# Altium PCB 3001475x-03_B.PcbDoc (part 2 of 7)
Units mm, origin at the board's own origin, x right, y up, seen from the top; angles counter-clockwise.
Board outline 100 x 72 mm, 12 copper layers (Top Layer, L2 GND, Layer 3, L4 GND, Layer 5, L6 PWR, L7 3V3, Layer 8, L9 GND, Layer 10, L11 GND, Bottom Layer), stack 1.735 mm thick; 431 components, 499 nets, 1977 pads, 1473 vias.

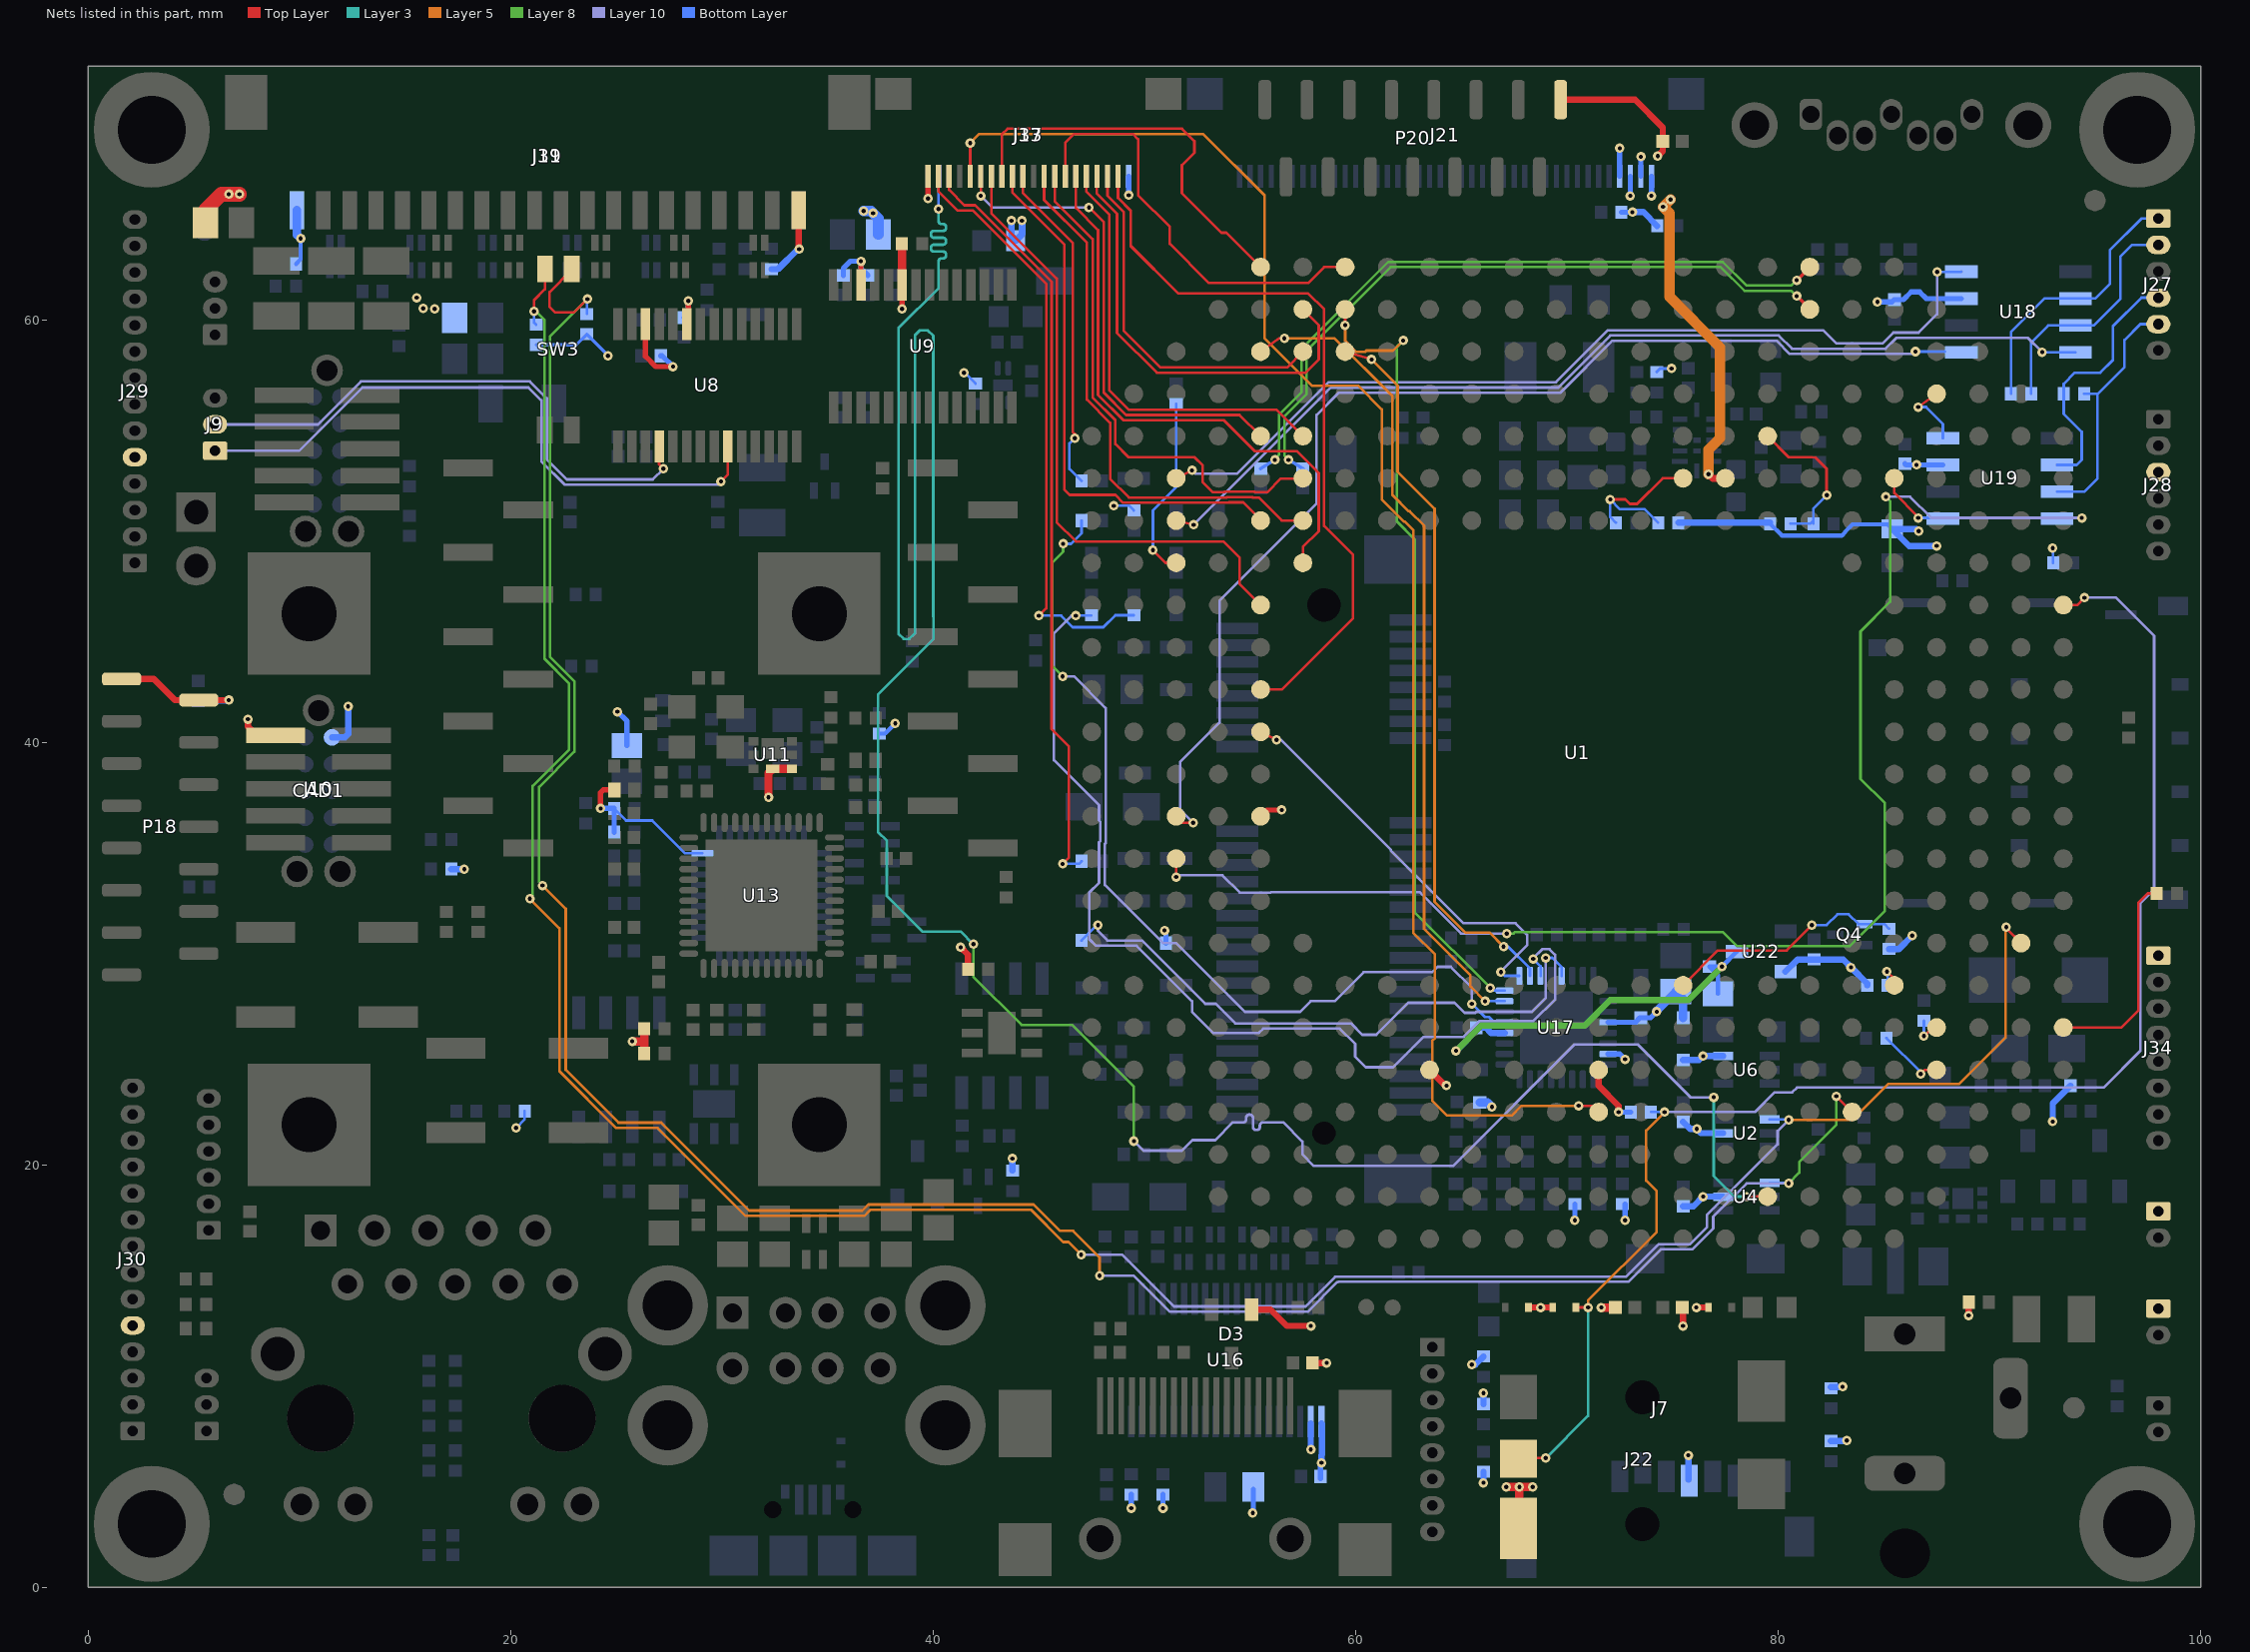
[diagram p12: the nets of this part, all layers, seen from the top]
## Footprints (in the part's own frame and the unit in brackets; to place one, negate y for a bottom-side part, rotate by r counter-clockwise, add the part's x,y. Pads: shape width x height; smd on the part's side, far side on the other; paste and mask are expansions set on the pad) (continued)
MODULE_CCWMX6 [mil]
  round 35 smd: A5(-590.55,905.51) A6(-511.81,905.51) A7(-433.07,905.51) A8(-354.33,905.51) A9(-275.59,905.51) A10(-196.85,905.51) A11(-118.11,905.51) A12(-39.37,905.51) A13(39.37,905.51) A14(118.11,905.51) A15(196.85,905.51) A16(275.59,905.51) A17(354.33,905.51) A18(433.07,905.51) A19(511.81,905.51) A20(590.55,905.51) AA2(-826.77,-669.29) AA3(-748.03,-669.29) AA4(-669.29,-669.29) AA5(-590.55,-669.29) AA6(-511.81,-669.29) AA7(-433.07,-669.29) AA8(-354.33,-669.29) AA9(-275.59,-669.29) AA10(-196.85,-669.29) AA11(-118.11,-669.29) AA12(-39.37,-669.29) AA13(39.37,-669.29) AA14(118.11,-669.29) AA15(196.85,-669.29) AA16(275.59,-669.29) AA17(354.33,-669.29) AA18(433.07,-669.29) AA19(511.81,-669.29) AA20(590.55,-669.29) AA21(669.29,-669.29) AA22(748.03,-669.29) AA23(826.77,-669.29) AB3(-748.03,-748.03) AB4(-669.29,-748.03) AB5(-590.55,-748.03) AB6(-511.81,-748.03) AB7(-433.07,-748.03) AB8(-354.33,-748.03) AB9(-275.59,-748.03) AB10(-196.85,-748.03) AB11(-118.11,-748.03) AB12(-39.37,-748.03) AB13(39.37,-748.03) AB14(118.11,-748.03) AB15(196.85,-748.03) AB16(275.59,-748.03) AB17(354.33,-748.03) AB18(433.07,-748.03) AB19(511.81,-748.03) AB20(590.55,-748.03) AB21(669.29,-748.03) AB22(748.03,-748.03) AC4(-669.29,-826.77) AC5(-590.55,-826.77) AC6(-511.81,-826.77) AC7(-433.07,-826.77) AC8(-354.33,-826.77) AC9(-275.59,-826.77) AC10(-196.85,-826.77) AC11(-118.11,-826.77) AC12(-39.37,-826.77) AC13(39.37,-826.77) AC14(118.11,-826.77) AC15(196.85,-826.77) AC16(275.59,-826.77) AC17(354.33,-826.77) AC18(433.07,-826.77) AC19(511.81,-826.77) AC20(590.55,-826.77) AC21(669.29,-826.77) AD5(-590.55,-905.51) AD6(-511.81,-905.51) AD7(-433.07,-905.51) AD8(-354.33,-905.51) AD9(-275.59,-905.51) AD10(-196.85,-905.51) AD11(-118.11,-905.51) AD12(-39.37,-905.51) AD13(39.37,-905.51) AD14(118.11,-905.51) AD15(196.85,-905.51) AD16(275.59,-905.51) AD17(354.33,-905.51) AD18(433.07,-905.51) AD19(511.81,-905.51) AD20(590.55,-905.51) B4(-669.29,826.77) B5(-590.55,826.77) B6(-511.81,826.77) B7(-433.07,826.77) B8(-354.33,826.77) B9(-275.59,826.77) B10(-196.85,826.77) B11(-118.11,826.77) B12(-39.37,826.77) B13(39.37,826.77) B14(118.11,826.77) B15(196.85,826.77) B16(275.59,826.77) B17(354.33,826.77) B18(433.07,826.77) B19(511.81,826.77) B20(590.55,826.77) B21(669.29,826.77) C3(-748.03,748.03) C4(-669.29,748.03) C5(-590.55,748.03) C6(-511.81,748.03) C7(-433.07,748.03) C8(-354.33,748.03) C9(-275.59,748.03) C10(-196.85,748.03) C11(-118.11,748.03) C12(-39.37,748.03) C13(39.37,748.03) C14(118.11,748.03) C15(196.85,748.03) C16(275.59,748.03) C17(354.33,748.03) C18(433.07,748.03) C19(511.81,748.03) C20(590.55,748.03) C21(669.29,748.03) C22(748.03,748.03) D2(-826.77,669.29) D3(-748.03,669.29) D4(-669.29,669.29) D5(-590.55,669.29) D6(-511.81,669.29) D7(-433.07,669.29) D8(-354.33,669.29) D9(-275.59,669.29) D10(-196.85,669.29) D11(-118.11,669.29) D12(-39.37,669.29) D13(39.37,669.29) D14(118.11,669.29) D15(196.85,669.29) D16(275.59,669.29) D17(354.33,669.29) D18(433.07,669.29) D19(511.81,669.29) D20(590.55,669.29) D21(669.29,669.29) D22(748.03,669.29) D23(826.77,669.29) E1(-905.51,590.55) E2(-826.77,590.55) E3(-748.03,590.55) E4(-669.29,590.55) E5(-590.55,590.55) E6(-511.81,590.55) E7(-433.07,590.55) E8(-354.33,590.55) E9(-275.59,590.55) E10(-196.85,590.55) E11(-118.11,590.55) E12(-39.37,590.55) E13(39.37,590.55) E14(118.11,590.55) E15(196.85,590.55) E16(275.59,590.55) E17(354.33,590.55) E18(433.07,590.55) E19(511.81,590.55) E20(590.55,590.55) E21(669.29,590.55) E22(748.03,590.55) E23(826.77,590.55) E24(905.51,590.55) F1(-905.51,511.81) F2(-826.77,511.81) F3(-748.03,511.81) F4(-669.29,511.81) F5(-590.55,511.81) F6(-511.81,511.81) F7(-433.07,511.81) F8(-354.33,511.81) F9(-275.59,511.81) F10(-196.85,511.81) F11(-118.11,511.81) F12(-39.37,511.81) F13(39.37,511.81) F14(118.11,511.81) F15(196.85,511.81) F16(275.59,511.81) F17(354.33,511.81) F18(433.07,511.81) F19(511.81,511.81) F20(590.55,511.81) F21(669.29,511.81) F22(748.03,511.81) F23(826.77,511.81) F24(905.51,511.81) G1(-905.51,433.07) G2(-826.77,433.07) G3(-748.03,433.07) G4(-669.29,433.07) G5(-590.55,433.07) G6(-511.81,433.07) G7(-433.07,433.07) G8(-354.33,433.07) G9(-275.59,433.07) G10(-196.85,433.07) G11(-118.11,433.07) G12(-39.37,433.07) G13(39.37,433.07) G14(118.11,433.07) G15(196.85,433.07) G16(275.59,433.07) G17(354.33,433.07) G18(433.07,433.07) G19(511.81,433.07) G20(590.55,433.07) G21(669.29,433.07) G22(748.03,433.07) G23(826.77,433.07) G24(905.51,433.07) H1(-905.51,354.33) H2(-826.77,354.33) H3(-748.03,354.33) H4(-669.29,354.33) H5(-590.55,354.33) H6(-511.81,354.33) H19(511.81,354.33) H20(590.55,354.33) H21(669.29,354.33) H22(748.03,354.33) H23(826.77,354.33) H24(905.51,354.33) J1(-905.51,275.59) J2(-826.77,275.59) J3(-748.03,275.59) J4(-669.29,275.59) J5(-590.55,275.59) J20(590.55,275.59) J21(669.29,275.59) J22(748.03,275.59) J23(826.77,275.59) J24(905.51,275.59) K1(-905.51,196.85) K2(-826.77,196.85) K3(-748.03,196.85) K4(-669.29,196.85) K5(-590.55,196.85) K20(590.55,196.85) K21(669.29,196.85) K22(748.03,196.85) K23(826.77,196.85) K24(905.51,196.85) L1(-905.51,118.11) L2(-826.77,118.11) L3(-748.03,118.11) L4(-669.29,118.11) L5(-590.55,118.11) L20(590.55,118.11) L21(669.29,118.11) L22(748.03,118.11) L23(826.77,118.11) L24(905.51,118.11) M1(-905.51,39.37) M2(-826.77,39.37) M3(-748.03,39.37) M4(-669.29,39.37) M5(-590.55,39.37) M20(590.55,39.37) M21(669.29,39.37) M22(748.03,39.37) M23(826.77,39.37) M24(905.51,39.37) N1(-905.51,-39.37) N2(-826.77,-39.37) N3(-748.03,-39.37) N4(-669.29,-39.37) N5(-590.55,-39.37) N20(590.55,-39.37) N21(669.29,-39.37) N22(748.03,-39.37) N23(826.77,-39.37) N24(905.51,-39.37) P1(-905.51,-118.11) P2(-826.77,-118.11) P3(-748.03,-118.11) P4(-669.29,-118.11) P5(-590.55,-118.11) P20(590.55,-118.11) P21(669.29,-118.11) P22(748.03,-118.11) P23(826.77,-118.11) P24(905.51,-118.11) R1(-905.51,-196.85) R2(-826.77,-196.85) R3(-748.03,-196.85) R4(-669.29,-196.85) R5(-590.55,-196.85) R20(590.55,-196.85) R21(669.29,-196.85) R22(748.03,-196.85) R23(826.77,-196.85) R24(905.51,-196.85) T1(-905.51,-275.59) T2(-826.77,-275.59) T3(-748.03,-275.59) T4(-669.29,-275.59) T5(-590.55,-275.59) T20(590.55,-275.59) T21(669.29,-275.59) T22(748.03,-275.59) T23(826.77,-275.59) T24(905.51,-275.59) U1(-905.51,-354.33) U2(-826.77,-354.33) U3(-748.03,-354.33) U4(-669.29,-354.33) U5(-590.55,-354.33) U6(-511.81,-354.33) U19(511.81,-354.33) U20(590.55,-354.33) U21(669.29,-354.33) U22(748.03,-354.33) U23(826.77,-354.33) U24(905.51,-354.33) V1(-905.51,-433.07) V2(-826.77,-433.07) V3(-748.03,-433.07) V4(-669.29,-433.07) V5(-590.55,-433.07) V6(-511.81,-433.07) V7(-433.07,-433.07) V8(-354.33,-433.07) V9(-275.59,-433.07) V10(-196.85,-433.07) V11(-118.11,-433.07) V12(-39.37,-433.07) V13(39.37,-433.07) V14(118.11,-433.07) V15(196.85,-433.07) V16(275.59,-433.07) V17(354.33,-433.07) V18(433.07,-433.07) V19(511.81,-433.07) V20(590.55,-433.07) V21(669.29,-433.07) V22(748.03,-433.07) V23(826.77,-433.07) V24(905.51,-433.07) W1(-905.51,-511.81) W2(-826.77,-511.81) W3(-748.03,-511.81) W4(-669.29,-511.81) W5(-590.55,-511.81) W6(-511.81,-511.81) W7(-433.07,-511.81) W8(-354.33,-511.81) W9(-275.59,-511.81) W10(-196.85,-511.81) W11(-118.11,-511.81) W12(-39.37,-511.81) W13(39.37,-511.81) W14(118.11,-511.81) W15(196.85,-511.81) W16(275.59,-511.81) W17(354.33,-511.81) W18(433.07,-511.81) W19(511.81,-511.81) W20(590.55,-511.81) W21(669.29,-511.81) W22(748.03,-511.81) W23(826.77,-511.81) W24(905.51,-511.81) Y1(-905.51,-590.55) Y2(-826.77,-590.55) Y3(-748.03,-590.55) Y4(-669.29,-590.55) Y5(-590.55,-590.55) Y6(-511.81,-590.55) Y7(-433.07,-590.55) Y8(-354.33,-590.55) Y9(-275.59,-590.55) Y10(-196.85,-590.55) Y11(-118.11,-590.55) Y12(-39.37,-590.55) Y13(39.37,-590.55) Y14(118.11,-590.55) Y15(196.85,-590.55) Y16(275.59,-590.55) Y17(354.33,-590.55) Y18(433.07,-590.55) Y19(511.81,-590.55) Y20(590.55,-590.55) Y21(669.29,-590.55) Y22(748.03,-590.55) Y23(826.77,-590.55) Y24(905.51,-590.55)
  silkscreen extent -984,-984 984,984, body extent -984,-984 984,984, height 220
MOLEX_53047-0210 [mm]
  rrect20% 0.875x1.15 hole 0.5: 1(0,0)
  oval 0.875x1.15 hole 0.5: 2(1.25,0)
  body extent -1.52,-1.15 2.73,2.05, height 4.2
MOLEX_53047-0310#1 [mm]
  rrect20% 1x1.15 hole 0.5: 1(0,0)
  oval 1x1.15 hole 0.5: 2(1.25,0) 3(2.5,0)
  body extent -1.5,-1.15 4,2.05, height 4.2
MOLEX_53047-0310#2 [mm]
  rrect20% 0.875x1.15 hole 0.5: 1(0,0)
  oval 0.875x1.15 hole 0.5: 2(1.25,0) 3(2.5,0)
  body extent -1.5,-1.15 4,2.05, height 4.2
MOLEX_53047-0610 [mm]
  rrect20% 0.875x1.15 hole 0.5: 1(0,0)
  oval 0.875x1.15 hole 0.5: 2(1.25,0) 3(2.5,0) 4(3.75,0) 5(5,0) 6(6.25,0)
  body extent -1.5,-1.15 7.75,2.05, height 4.2
MOLEX_53047-0810#1 [mm]
  rect 0.875x1.15 hole 0.5: 1(0,0)
  oval 0.875x1.15 hole 0.5: 2(1.25,0) 3(2.5,0) 4(3.75,0) 5(5,0) 6(6.25,0) 7(7.5,0) 8(8.75,0)
  body extent -1.5,-1.15 10.25,2.05, height 4.2
MOLEX_53047-0810#2 [mm]
  rrect20% 0.875x1.15 hole 0.5: 1(0,0)
  oval 0.875x1.15 hole 0.5: 2(1.25,0) 3(2.5,0) 4(3.75,0) 5(5,0) 6(6.25,0) 7(7.5,0) 8(8.75,0)
  body extent -1.5,-1.15 10.25,2.05, height 4.2
MOLEX_53047-1410 [mm]
  rrect20% 0.875x1.15 hole 0.5: 1(0,0)
  oval 0.875x1.15 hole 0.5: 2(1.25,0) 3(2.5,0) 4(3.75,0) 5(5,0) 6(6.25,0) 7(7.5,0) 8(8.75,0) 9(10,0) 10(11.25,0) 11(12.5,0) 12(13.75,0) 13(15,0) 14(16.25,0)
  body extent -1.5,-1.15 17.75,2.05, height 4.2
MOLEX_78727-0001 [mm]
  rect 0.8x0.6 smd: 1(0.33,4.38) 2(0.33,1.84) 3(0.33,-0.7) 4(0.33,-3.24) 5(-7.29,4.38) 6(-7.29,1.84) 7(-7.29,-0.7) 8(-7.29,-3.24)
  rect 0.85x0.8 smd: 9(-13.99,-4.98)
  rect 1.5x0.42 smd: 10(-2.47,-6.54) 12(-6.35,7.11) 13(-12.21,7.11) 14(-12.21,-7.11) 15(-6.35,-7.11)
  rect 1.4x0.87 smd: 11(0,6.95) 16(0,-6.95)
  body extent -14.53,-7.26 0.69,7.27, height 1.4
MOLEX_500873-0806 [mm]
  rect 0.8x1.5 smd: 1(0,0) 2(1.1,-0.4) 3(2.2,0) 4(3.3,0.2) 5(4.4,0) 6(5.5,0.2) 7(6.6,0) 8(7.7,0)
  rect 1.8x1.4 smd: 9(1.2,-10.3) 10(6.9,-10.3)
  rect 1.4x1.9 smd: 11(8.5,2.85) 12(-4.65,3.85)
  body extent -5.05,-10.7 8.95,4.5, height 1.87
omron_xf2m-2015-1a [mm]
  rect 0.25x1.1 smd: 1(-4.75,1.95) 2(-4.25,1.95) 3(-3.75,1.95) 4(-3.25,1.95) 5(-2.75,1.95) 6(-2.25,1.95) 7(-1.75,1.95) 8(-1.25,1.95) 9(-0.75,1.95) 10(-0.25,1.95) 11(0.25,1.95) 12(0.75,1.95) 13(1.25,1.95) 14(1.75,1.95) 15(2.25,1.95) 16(2.75,1.95) 17(3.25,1.95) 18(3.75,1.95) 19(4.25,1.95) 20(4.75,1.95)
  rect 1.7x1.5 smd: M1(6.4,-1.95) M2(-6.4,-1.95)
  body extent -7.05,-2.9 7.05,3.3, height 2.18
OMRON_XF2M-4015-1A [mm]
  rect 0.25x1.1 smd: 1(-9.75,1.95) 2(-9.25,1.95) 3(-8.75,1.95) 4(-8.25,1.95) 5(-7.75,1.95) 6(-7.25,1.95) 7(-6.75,1.95) 8(-6.25,1.95) 9(-5.75,1.95) 10(-5.25,1.95) 11(-4.75,1.95) 12(-4.25,1.95) 13(-3.75,1.95) 14(-3.25,1.95) 15(-2.75,1.95) 16(-2.25,1.95) 17(-1.75,1.95) 18(-1.25,1.95) 19(-0.75,1.95) 20(-0.25,1.95) 21(0.25,1.95) 22(0.75,1.95) 23(1.25,1.95) 24(1.75,1.95) 25(2.25,1.95) 26(2.75,1.95) 27(3.25,1.95) 28(3.75,1.95) 29(4.25,1.95) 30(4.75,1.95) 31(5.25,1.95) 32(5.75,1.95) 33(6.25,1.95) 34(6.75,1.95) 35(7.25,1.95) 36(7.75,1.95) 37(8.25,1.95) 38(8.75,1.95) 39(9.25,1.95) 40(9.75,1.95)
  rect 1.7x1.5 smd: M1(11.4,-1.95) M2(-11.4,-1.95)
  body extent -12.05,-2.9 12.05,3.3, height 2.18
OSC210P320X250X90-4N [mm]
  rect 1.25x1.1 smd: 1(-1.15,-0.95)
  rect 1.3x1.1 smd: 2(1.15,-0.95) 3(1.15,0.95) 4(-1.15,0.95)
  body extent -1.63,-1.3 1.62,1.3, height 0.6
PCBNUMBER [mm]
QFN50P500X500X100-33CN [mm]
  rrect50% 0.85x0.3 smd: 1(-2.45,1.75) 2(-2.45,1.25) 3(-2.45,0.75) 4(-2.45,0.25) 5(-2.45,-0.25) 6(-2.45,-0.75) 7(-2.45,-1.25) 8(-2.45,-1.75) 17(2.45,-1.75) 18(2.45,-1.25) 19(2.45,-0.75) 20(2.45,-0.25) 21(2.45,0.25) 22(2.45,0.75) 23(2.45,1.25) 24(2.45,1.75)
  rrect50% 0.3x0.85 smd: 9(-1.75,-2.45) 10(-1.25,-2.45) 11(-0.75,-2.45) 12(-0.25,-2.45) 13(0.25,-2.45) 14(0.75,-2.45) 15(1.25,-2.45) 16(1.75,-2.45) 25(1.75,2.45) 26(1.25,2.45) 27(0.75,2.45) 28(0.25,2.45) 29(-0.25,2.45) 30(-0.75,2.45) 31(-1.25,2.45) 32(-1.75,2.45)
  rect 3.45x3.45 smd: 33(0,0)
  body extent -2.5,-2.5 2.5,2.5, height 1.01
QFN50P600X600X100-37AN [mm]
  rrect35% 1.05x0.3 smd: 1(-2.8,2) 9(-2.8,-2) 19(2.8,-2) 27(2.8,2)
  rrect25% 1.1x0.3 smd: 2(-2.8,1.5) 3(-2.8,1) 4(-2.8,0.5) 5(-2.8,0) 6(-2.8,-0.5) 7(-2.8,-1) 8(-2.8,-1.5) 20(2.8,-1.5) 21(2.8,-1) 22(2.8,-0.5) 23(2.8,0) 24(2.8,0.5) 25(2.8,1) 26(2.8,1.5)
  rrect35% 0.3x1.05 smd: 10(-2,-2.8) 18(2,-2.8) 28(2,2.8) 36(-2,2.8)
  rrect25% 0.3x1.1 smd: 11(-1.5,-2.8) 12(-1,-2.8) 13(-0.5,-2.8) 14(0,-2.8) 15(0.5,-2.8) 16(1,-2.8) 17(1.5,-2.8) 29(1.5,2.8) 30(1,2.8) 31(0.5,2.8) 32(0,2.8) 33(-0.5,2.8) 34(-1,2.8) 35(-1.5,2.8)
  rect 3.8x3.8 smd: 37(0,0)
  body extent -3.05,-3.05 3.05,3.05, height 1.01
QFN50P700X700X100-49N [mm]
  oval 0.9x0.3 smd: 1(-3.45,2.75) 2(-3.45,2.25) 3(-3.45,1.75) 4(-3.45,1.25) 5(-3.45,0.75) 6(-3.45,0.25) 7(-3.45,-0.25) 8(-3.45,-0.75) 9(-3.45,-1.25) 10(-3.45,-1.75) 11(-3.45,-2.25) 12(-3.45,-2.75) 25(3.45,-2.75) 26(3.45,-2.25) 27(3.45,-1.75) 28(3.45,-1.25) 29(3.45,-0.75) 30(3.45,-0.25) 31(3.45,0.25) 32(3.45,0.75) 33(3.45,1.25) 34(3.45,1.75) 35(3.45,2.25) 36(3.45,2.75)
  oval 0.3x0.9 smd: 13(-2.75,-3.45) 14(-2.25,-3.45) 15(-1.75,-3.45) 16(-1.25,-3.45) 17(-0.75,-3.45) 18(-0.25,-3.45) 19(0.25,-3.45) 20(0.75,-3.45) 21(1.25,-3.45) 22(1.75,-3.45) 23(2.25,-3.45) 24(2.75,-3.45) 37(2.75,3.45) 38(2.25,3.45) 39(1.75,3.45) 40(1.25,3.45) 41(0.75,3.45) 42(0.25,3.45) 43(-0.25,3.45) 44(-0.75,3.45) 45(-1.25,3.45) 46(-1.75,3.45) 47(-2.25,3.45) 48(-2.75,3.45)
  rect 5.3x5.3 smd: 49(0,0)
  body extent -3.57,-3.57 3.57,3.57, height 1.01
QFN_MPS_MP2316 [mm]
  rect 0.75x0.25 smd: 1(-0.8,1)
  rect 0.7x0.25 smd: 2(-0.8,0.5) 3(-0.8,0) 4(-0.8,-0.5) 5(-0.8,-1) 7(0.8,-1) 8(0.8,-0.5) 9(0.8,0) 10(0.8,0.5) 11(0.8,1)
  rect 0.25x0.7 smd: 6(0,-1.45) 12(0,1.45)
  rect 0.35x0.25 smd: 13(0,0.5) 14(0,0)
  body extent -1,-1.5 1,1.5, height 1.01
RESC1005X40N#1 [mm]
  rect 0.57x0.62 smd: 1(-0.48,0) 2(0.48,0)
  body extent -0.5,-0.25 0.5,0.25, height 0.4
RESC1005X40N#2 [mm]
  rect 0.57x0.62 smd mask+0.05: 1(-0.48,0) 2(0.48,0)
  body extent -0.5,-0.25 0.5,0.25, height 0.4
RESC1609X55N#1 [mm]
  rect 0.9x1 smd: 1(-0.8,0) 2(0.8,0)
  body extent -0.87,-0.48 0.87,0.48, height 0.55
RESC1609X55N#2 [mm]
  rect 0.9x1 smd mask+0.05: 1(-0.8,0) 2(0.8,0)
  body extent -0.87,-0.48 0.87,0.48, height 0.55
RESC2013X70N [mm]
  rect 1.05x1.4 smd: 1(-0.95,0) 2(0.95,0)
  body extent -1.1,-0.67 1.1,0.68, height 0.7
SAMTEC_FTSH-105-01-F-DV [mil]
  rect 110x29 smd: 1(-80,100) 2(80,100) 3(-80,50) 4(80,50) 5(-80,0) 6(80,0) 7(-80,-50) 8(80,-50) 9(-80,-100) 10(80,-100)
  body extent -115,-207 115,208, height 325
SAMTEC_SMM-110-02-F-S [mm]
  rect 0.8x2.35 smd: 1(-9,-1.425) 2(-7,1.425) 3(-5,-1.425) 4(-3,1.425) 5(-1,-1.425) 6(1,1.425) 7(3,-1.425) 8(5,1.425) 9(7,-1.425) 10(9,1.425)
  body extent -10,-1 10,1, height 7.37
SOD3716X135N [mm]
  rect 1x0.8 smd: A(-1.8,0) K(1.8,0)
  body extent -1.95,-0.9 1.95,0.9, height 1.36
SODFL1006X43N12 [mm]
  rect 0.32x0.43 smd: 1(-0.55,0) 2(0.55,0)
  body extent -0.58,-0.33 0.58,0.33, height 0.4
SOIC127P600X175-8N [mm]
  rect 0.6x1.55 smd: 1(-1.905,-2.7) 2(-0.635,-2.7) 3(0.635,-2.7) 4(1.905,-2.7) 5(1.905,2.7) 6(0.635,2.7) 7(-0.635,2.7) 8(-1.905,2.7)
  body extent -2.5,-3.1 2.5,3.1, height 1.75
SON50P120X160X60-5T55X91N [mm] "Small Outline No-Lead (SON with Tab), 0.50 mm pitch; 4 pin, 1.20 mm L X 1.60 mm W X 0.60 mm H body"
  rrect52% 0.67x0.27 smd mask+0.051: 1(-0.81,0.25) 2(-0.81,-0.25) 3(0.81,-0.25) 4(0.81,0.25)
  rect 0.55x0.91 smd paste-0.099 mask+0.051: 5(0,0)
  body extent -0.85,-0.6 0.85,0.6, height 0.6
SON95P300X300X80-7N [mm]
  rect 0.4x1 smd: 1(-0.95,-1.4) 2(0,-1.4) 3(0.95,-1.4) 4(0.95,1.4) 5(0,1.4) 6(-0.95,1.4)
  rect 2x1.3 smd: 7(0,0)
  body extent -1.58,-1.58 1.58,1.58, height 0.8
SOP50P640X120-38N [mm]
  rect 1.5x0.3 smd: 1(-2.9,4.5) 2(-2.9,4) 3(-2.9,3.5) 4(-2.9,3) 5(-2.9,2.5) 6(-2.9,2) 7(-2.9,1.5) 8(-2.9,1) 9(-2.9,0.5) 10(-2.9,0) 11(-2.9,-0.5) 12(-2.9,-1) 13(-2.9,-1.5) 14(-2.9,-2) 15(-2.9,-2.5) 16(-2.9,-3) 17(-2.9,-3.5) 18(-2.9,-4) 19(-2.9,-4.5) 20(2.9,-4.5) 21(2.9,-4) 22(2.9,-3.5) 23(2.9,-3) 24(2.9,-2.5) 25(2.9,-2) 26(2.9,-1.5) 27(2.9,-1) 28(2.9,-0.5) 29(2.9,0) 30(2.9,0.5) 31(2.9,1) 32(2.9,1.5) 33(2.9,2) 34(2.9,2.5) 35(2.9,3) 36(2.9,3.5) 37(2.9,4) 38(2.9,4.5)
  body extent -3.3,-4.9 3.3,4.9, height 1.1
SOP65P640X120-28N [mm]
  rect 0.45x1.5 smd: 1(-4.225,-2.9) 2(-3.575,-2.9) 3(-2.925,-2.9) 4(-2.275,-2.9) 5(-1.625,-2.9) 6(-0.975,-2.9) 7(-0.325,-2.9) 8(0.325,-2.9) 9(0.975,-2.9) 10(1.625,-2.9) 11(2.275,-2.9) 12(2.925,-2.9) 13(3.575,-2.9) 14(4.225,-2.9) 15(4.225,2.9) 16(3.575,2.9) 17(2.925,2.9) 18(2.275,2.9) 19(1.625,2.9) 20(0.975,2.9) 21(0.325,2.9) 22(-0.325,2.9) 23(-0.975,2.9) 24(-1.625,2.9) 25(-2.275,2.9) 26(-2.925,2.9) 27(-3.575,2.9) 28(-4.225,2.9)
  body extent -4.9,-3.3 4.9,3.3, height 1.21
SOT65P210X110-5N [mm]
  rect 0.4x0.95 smd: 1(-0.65,-1.1) 2(0,-1.1) 3(0.65,-1.1) 4(0.65,1.1) 5(-0.65,1.1)
  body extent -1.07,-1.2 1.07,1.2, height 1.11
SOT65P210X110-6N [mm]
  rect 0.4x0.95 smd: 1(-0.65,-1.1) 2(0,-1.1) 3(0.65,-1.1) 4(0.65,1.1) 5(0,1.1) 6(-0.65,1.1)
  body extent -1.07,-1.2 1.07,1.2, height 1.11
SOT95P240X110-3N [mm]
  rect 0.7x1.1 smd: 1(-0.95,-1.2) 2(0.95,-1.2) 3(0,1.2)
  body extent -1.56,-1.35 1.56,1.35, height 1.11
SOT95P240X110_AXK-3N [mm]
  rect 0.65x1.05 smd: A(-0.95,-1.15) K(0,1.15) X(0.95,-1.15)
  body extent -1.56,-1.35 1.56,1.35, height 1.11
SOT95P240X110_GSD-3N [mm]
  rect 0.65x1.05 smd: D(0,1.15) G(-0.95,-1.15) S(0.95,-1.15)
  body extent -1.56,-1.35 1.56,1.35, height 1.11
SOTFL50P160X80_GSD-3N [mm]
  rect 0.4x0.77 smd: D(0,0.69) G(-0.5,-0.69) S(0.5,-0.69)
  body extent -0.85,-0.85 0.85,0.85, height 0.8
SW_KSC221J [mm]
  rect 1x2.8 smd: 1(2,2.9) 2(2,-2.9) 3(-2,2.9) 4(-2,-2.9)
  body extent -3.1,-3.4 3.1,3.4, height 3.5
SW_TDA02 [mm]
  rect 1.27x0.76 smd: 1(-3.81,0.635) 2(-3.81,-0.635) 3(3.81,-0.635)
  rect 1.27x0.74 smd: 4(3.81,0.635)
  body extent -3.12,-1.84 3.13,1.84, height 2.3
TC_TC2050-IDC-NL [mil]
  round 31 smd paste-50: 1(-100,-25) 2(-50,-25) 3(0,-25) 4(50,-25) 5(100,-25) 6(100,25) 7(50,25) 8(0,25) 9(-50,25) 10(-100,25)
  round 59 hole 39 unplated: MT1(-150,0) MT2(150,40) MT3(150,-40)
TP0762 [mil] "30mil SMT Round Testpoint"
  round 30 smd paste-100: 1(0,0)
XTAL_C3E-3427 [mm]
  rect 1.4x1.15 smd: 1(-1.1,-0.8) 2(1.1,-0.8) 3(1.1,0.8) 4(-1.1,0.8)
  body extent -1.7,-1.35 1.7,1.35, height 0.75

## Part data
C1 C9 C34 C35 C36: library part 1001196, "CAP TANT 100UF 6.3V 20% 1206"
C2 C11 C12 C42 C49 C56 C57 C60 C67 C69 C71 C72 C98: library part 1001168, "CAP CER 10UF 10V 20% X5R 0402"
C3 C62 C65 C87 C88 C91 C92 C93 C94 C104: library part 1001167, "CAP CER 1UF 10V 10% X5R 0402"
C4 C5 C6 C7 C10 C13 C18 C19 C20 C21 C22 C23 C24 C25 C26 C27 C29 C31 C32 C33 C37 C38 C39 C41 C43 C44 C45 C46 C47 C48 C50 C51 C52 C53 C54 C55 C58 C59 C61 C66 C68 C70 C73 C74 C75 C76 C77 C78 C79 C81 C82 C83 C84 C85 C86 C89 C90 C95 C96 C97 C99 C100 C101 C105 C106 C107 C118: library part 1000006, "CAP 100nF 16V 10% X7R 0402"
C8 C102 C103 C112: library part 1000998, "CAP CER 22UF 10V 20% X5R 0603"
C14 C15 C16 C17: library part 1001165, "CAP CER 10000PF 16V 10% X7R 0402"
C28 C30: library part 1001166, "CAP CER 22PF 50V 5% NP0 0402"
C40 C80: library part 1000500, "CAP CER 4.7UF 25V 10% X5R 0805"
C63 C64: library part 1000010, "CAP 33pF 50V 5% NP0 0402"
C108: library part 1000007, "CAP 47pF 50V 5% NP0 0402"
C109: library part 1000110, "CAP CER 1UF 25V 10% X5R 0603"
C110: library part 1000512, "CAP CER 0.015UF 16V 10% X7R 0402"
C111: library part 1000501, "CAP CER 47UF 6.3V 20% X5R 0805"
C113: library part 1000918, "CAP CER 0.1UF 50V 10% X7R 0402"
C114: library part 1000566, "CAP CER 100UF 10V 20% X5R 1206"
C115 C116 C117 C119: library part 1000111, "CAP CER 10UF 16V 10% X5R 0805"
CAD1 CAD2: library part CAD0066, "CBL PLUG-OF-NAILS 10-PIN"
D1 D4 D11: library part 1001189, "LED GREEN 573NM 1208 SMD"
D2: library part 1001494, "DIODE ZENER 5.1V 500MW SOD123"
D3: library part 1001169, "DIODE SCHOTTKY 30V 0.2A SOT23-3"
D5: library part 1001188, "LED YELLOW 588NM 1208 SMD"
D6: library part 1001190, "LED RED 653NM 20MA 1208 SMD"
D7 D8 D9 D10: library part 1001264, "TVS DIODE 5VWM SOD923"
FIDUCIAL1 FIDUCIAL2 FIDUCIAL3 FIDUCIAL4 FIDUCIAL5 FIDUCIAL6 FIDUCIAL7 FIDUCIAL8 FIDUCIAL9 FIDUCIAL10 FIDUCIAL11 FIDUCIAL12 FIDUCIAL13 FIDUCIAL14: library part CAD0023, "40 Mil Round Fiducial"
FIL1: library part 1001918, "DNF 2 MHZ -1000 MHZ SMD"
H1 H2 H3 H4: library part CAD0006, "NPTH for Tooling, 0.125in dia."
J1: library part 1001105, "DC Power Jack"
J2 J4 J5: library part 1001136, "CONN HEADER 2POS 1.25MM VERT TIN"
J3 J9 J25: library part 1001183, "CONN HEADER 3POS 1.25MM VERT TIN"
J7: library part 1001118, "CONN TRANSFLSH R/A PUSH-PUSH SMD"
J8: library part 1001115, "CONN PLUG SATA 7PS VERT PCB GOLD"
J10 J11: library part 1000034, "CONN HEADER 10POS DUAL .05\" SMD"
J12: library part 1001130, "SMCONN,MINI PCI EXP, 6.8MM HT"
J13: library part 1001142, "CONN MAGJACK 1PORT 1000 BASE-T"
J14: library part 1001120, "MEMORY CARD 6POS PUSH/PULL SMD"
J15: library part 1001121, "USB Stacked Dual A type"
J16: library part 1001117, "CONN RECEPT MICRO-USB TYPE AB R/A"
J17 J33: library part 1001145, "CONN FPC 20POS 0.5MM PITCH SMD"
J18: library part 1001128, "CONN HEADER 2POS .100\" SGL GOLD"
J19 J31: library part 1001132, "CONN HEADER 20POS 1.25MM R/A SMD"
J21: library part 1001144, "CONN FPC 40POS 0.5MM PITCH SMD"
J22: library part 1001133, "CONN JACK STEREO 5POS 3.5MM SMD"
J23 J24: library part 1001495, "CONN RCPT 2MM 10POS SMD"
J26 J34: library part 1001139, "CONN HEADER 8POS 1.25MM VERT TIN"
J27 J28 J32: library part 1001138, "CONN HEADER 6POS 1.25MM VERT TIN"
J29 J30: library part 1001140, "CONN HEADER 14POS 1.25MM STR TIN"
L1: library part 1001912, "FIXED IND 1.5UH 4.5A 42 MOHM SMD"
L2 L3 L4 L5 L18 L19 L20 L21 L22 L23 L24 L25: library part 1001175, "FERRITE BEAD 120 OHM .35A 0402"
L6 L7 L9 L12 L13 L15 L17 L26 L27 L28 L29 L35 L45: library part 1001174, "FERRITE BEAD 220 OHM 2.0A 0805"
L8 L10 L11 L14 L16: library part 1001173, "CHOKE COM MODE 120 OHM .37A"
L30 L31 L32 L33 L34 L36 L37 L38 L39 L40 L41 L42 L43 L44: library part 1001014, "CHOKE COIL COMMON MODE 150MA SMD"
P1: library part 1001123, "HDMI RECEPTACLE, SMT"
P18 P20: library part 1001866, "CONN FFC FPC VERT 15POS 1MM SMD"
PCB1: library part 3000137, "PCB CCWM6_SBC_v0.3"
Q1 Q3: library part 1001204, "TRANS GP SS PNP 40V SOT23"
Q2 Q4 Q5: library part 1000715, "MOSFET N-CH 60V 115MA SOT-523F"
R1 R2 R3 R42 R43 R48: library part 1000466, "RES 49.9 OHM 1/10W 1% 0402 SMD"
R4 R5 R6 R20 R24 R25 R44 R47 R51 R52 R77 R80 R81 R82 R84 R95 R96 R97 R98 R99 R100 R101 R102 R103 R105 R106 R107 R108 R111 R112 R113 R114 R115 R123 R129 R130 R131 R134 R135 R136 R141 R149 R150 R151 R152 R155 R156 R204 R205 R206 R207 R208 R257 R258 R259 R298 R299: library part 1000076, "RES 0.0 OHM 1/10W 0402 SMD"
R7 R13 R23 R31 R32 R33 R34 R36 R53 R55 R58 R60 R61 R62 R63 R64 R65 R66 R69 R72 R76 R78 R91 R92 R93 R117 R118 R122 R125 R126 R127 R128 R145 R146 R147 R153 R154: library part 1000537, "RES 10.0K OHM 1/10W 1% 0402 SMD"
R8 R35 R46: library part 1000467, "RES 100 OHM 1/10W 1% 0402 SMD"
R9 R10 R16 R17 R18 R19 R22 R28 R29 R41 R50 R54 R56 R57 R59: library part 1000079, "RES 1.00K OHM 1/10W 1% 0402 SMD"
R11: library part 1001323, "RES 270 OHM 1/2W 5% 0805 SMD"
R12: library part 1001154, "RES 220 OHM 1/16W 1% 0402 SMD"
R14 R137 R138: library part 1000701, "RES 470K OHM 1/10W 1% 0402 SMD"
R15: library part 1001150, "RES 316K OHM 1/10W 1% 0603 SMD"
R21 R83: library part 1000208, "RES 0.0 OHM 1/10W 0603"
R26 R27 R68 R71 R73 R74 R88 R90: library part 1001155, "RES 47.0K OHM 1/16W 1% 0402 SMD"
R30: library part 1001149, "RES 22.1K OHM 1/16W 1% 0402 SMD"
R37 R40 R75 R85 R87 R132: library part 1000038, "RES 4.7K OHM 1/10W 5% 0402 SMD"
R38 R45: library part 1000465, "RES 150 OHM 1/10W 1% 0402 SMD"
R39 R67: library part 1000971, "RES 1.00M OHM 1/16W 1% 0402 SMD"
R49 R70: library part 1000828, "RES 12.1K OHM 1/10W 1% 0402 SMD"
R86: library part 1001153, "RES 27.0K OHM 1/16W 1% 0402 SMD"
R89: library part 1000174, "RES 15.0K OHM 1/10W 1% 0402 SMD"
R94 R109 R110: library part 1001156, "RES 2.20K OHM 1/16W 1% 0402 SMD"
R104 R116 R119 R120 R121 R133: library part 1001158, "RES 120 OHM 1/16W 1% 0402 SMD"
R139 R140: library part 1000480, "RES 100K OHM 1/10W 1% 0402 SMD"
R142: library part 1001916, "RES SMD 2 OHM 5% 1/10W 0603"
R143: library part 1001518, "RES 53.6K OHM 1/10W 1% 0603 SMD"
R144: library part 1001200, "RES 12.0K OHM 1/10W 1% 0603 SMD"
R148: library part 1001557, "RES 0.0 OHM 1/8W JUMP 0805 SMD"
SW1 SW2: library part 1001124, "SWITCH TACTILE SPST-NO 0.05A 32V"
SW3: library part 1001500, "SWITCH DIP 2POS HALF PITCH 24V"
TP1 TP2: library part CAD0011, "TEST POINT 30mil PAD SMT"
U1: library part 1001177, "module, CCWMX6"
U2 U4: library part 1001179, "IC SWITCH SPDT SC88"
U3 U11: library part 1001205, "MOSFET P-CH 20V 7.8A 6-MICROFET"
U5: library part 1001206, "TVS DIODE 5VWM 9.2VC SMB"
U6: library part 1001160, "IC GATE NAND 2-INP HS LOG SC70-5"
U7: library part 1001857, "IC SW W/CTRL SLEW RATE 4TDFN"
U8 U9: library part 1001499, "IC RS232 3V-5.5V DRVR 28-TSSOP"
U10: library part 1001110, "IC TXRX ETHERNET 48-QFN"
U12 U14: library part 1001143, "IC SW DISTRIBUTION 2CHAN 8SOIC"
U13: library part 1001114, "4-PORT USB 2.0 HUB CTRLR 36VQFN"
U15 U22: library part 1001163, "MOSFET P-CH 20V 3.7A SOT23-3"
U16: library part 1001125, "IC HDMI XMITTER PORT P/I 38TSSOP"
U17: library part 1001126, "IC AUDIO CODEC STEREO 32-QFN"
U18 U19: library part 1001129, "IC CAN TRANSCEIVER 3.3V 8-SOIC"
U20 U21: library part 1001265, "TVS DIODE 5.5VWM 6SON"
U23: library part 1001907, "IC REG BUCK ADJ 3A SYNC"
X1: library part 1001497, "SMCRY,25MHZ 50PPM 20PF RH100 EXT"
X2: library part 1001134, "CRYSTAL 24MHZ 18PF SMD"

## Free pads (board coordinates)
  round 5.5 hole 3.2: 0(3,3) 0(3,69) 0(97,3) 0(97,69)
  rect 5.8x5.8 hole 2.6: 0(10.45,21.9) 0(10.45,46.1) 0(34.6,21.9) 0(34.6,46.1)

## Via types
v1: diameter 0.45, hole 0.2, Top Layer to Bottom Layer, tented both sides, 1473 vias

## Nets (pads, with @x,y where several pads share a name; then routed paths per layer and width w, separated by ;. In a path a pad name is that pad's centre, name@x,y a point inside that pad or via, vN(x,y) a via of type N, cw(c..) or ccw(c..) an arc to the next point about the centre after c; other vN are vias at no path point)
3V3: C5.2 C6.2 C7.2 C12.2 C13.2 C19.2 C21.2 C26.2 C27.2 C82.2 C99.2 C100.2 C105.2 C106.2 CAD1.1 D3.A J4.1 J7.4 J10.1 J17.20 J19.1 J21.37 J21.38 J28.3 J29.5 J30.5 J31.1 J33.20 J34.1 L2.1 L17.2 L28.1 P18.1 P18.2 P20.1 R7.2 R9.2 R10.2 R16.2 R22.2 R24.2 R25.2 R30.2 R31.2 R32.2 R33.2 R34.2 R36.2 R64.2 R65.2 R66.2 R68.2 R69.1 R75.1 R76.1 R78.1 R83.1 R88.1 R90.1 R93.2 R109.2 R110.2 R117.1 R118.1 R122.1 R127.1 R128.1 R132.2 R135.2 R139.1 R149.1 U1.P5 U1.Y9 U1.Y13 U2.5 U4.5 U6.5 U8.23 U8.26 U9.23 U9.26 U11.4 U11.8 U13.27 U16.2 U18.3 U19.3 U22.S | length 120.7
  Top Layer w0.25: v1(24.25,36.875) 24.25,37.625 24.375,37.75 L2.1@24.895,37.75 ; U8.26@26.375,59.805 26.375,58.275 26.863,57.787 v1(27.68,57.787) ; U8.23@28.325,59.805 28.3,59.83 28.4,59.93 v1(28.4,60.9) ; U9.26@36.575,61.65 v1(36.575,62.775) ; v1(38.525,60.525) U9.23@38.525,61.65 ; v1(39.75,65.75) J17.20@39.75,66.8 ; U1.P5@55.5,36.5 55.8,36.8 v1(56.5,36.8)
  Top Layer w0.3: P18.1@1.575,43 3.1,43 4.1,42 P18.2@5.225,42 v1(6.65,42) ; v1(7.55,41.1) 7.55,40.75 7.96,40.34 J10.1@8.868,40.34 ; J19.1@33.625,65.2 33.625,63.375 v1(33.65,63.35) ; v1(41.3,30.3) 41.645,29.955 R64.2@41.645,29.25 ; D3.A@55.075,13.15 55.975,13.15 56.75,12.375 v1(57.875,12.375) ; C82.2@57.96,10.625 v1(58.625,10.625) ; U1.Y9@63.5,24.5 64.25,23.75 v1(64.3,23.75) ; P20.1@69.7,70.425 73.225,70.425 74.54,69.11 C106.2@74.54,68.45 74.54,67.99 v1(74.3,67.75) ; U1.Y13@71.5,24.5 71.5,23.749 72.45,22.799 v1(72.45,22.5) ; v1(75.5,12.375) C12.2@75.5,13.21
  Top Layer w0.4: v1(25.75,25.85) 26.32,25.85 ; R66.2@26.32,25.275 26.32,25.85 ; R65.2@26.32,26.45 26.32,25.85 ; v1(32.2,37.4) 32.2,38.55 U11.8@32.4,38.75 U11.4@33.31,38.75 ; R127.1@38.52,63.6 38.525,63.595 U9.23@38.525,61.65 ; v1(71.625,13.25) C13.2@72.29,13.25
  Bottom Layer w0.125: v1(20.25,21.75) 20.655,22.155 R7.2@20.655,22.55 ; R68.2@24.895,36.86 25.455,36.3 26.7,36.3 28.25,34.75 U13.27@29.075,34.75 ; v1(41.45,57.5) 41.48,57.5 R22.2@42,56.98 ; v1(48.55,51.2) 49.28,51.2 R110.2@49.5,50.98 ; v1(93,49.2) 93.02,49.18 R117.1@93.02,48.5
  Bottom Layer w0.15: R9.2@21.2,58.82 23.1,58.82 R10.2@23.6,59.32 24.6,58.32 v1(24.6,58.3) ; R139.1@74.25,57.53 74.42,57.7 v1(74.95,57.7)
  Bottom Layer w0.2: R76.1@9.83,62.65 10.05,62.87 v1(10.05,63.85) ; R135.2@37.45,40.42 37.72,40.42 v1(38.2,40.9) ; R24.2@79.62,50.35 80.18,49.79 83.019,49.79 83.165,49.936 83.165,49.965 83.525,50.325 85.175,50.325 R83.1@85.4,50.1
  Bottom Layer w0.25: v1(24.25,36.875) R68.2@24.895,36.875 ; R69.1@24.895,35.75 R68.2@24.895,36.86 ; v1(25.05,41.45) 25.5,41 L17.2@25.5,39.85 ; C19.2@27.11,58.3 27.166,58.3 v1(27.68,57.787) ; C26.2@28.2,60.11 28.4,60.31 v1(28.4,60.9) ; C21.2@35.75,62.11 35.75,62.45 36.075,62.775 v1(36.575,62.775) 36.575,62.435 C27.2@36.9,62.11 ; v1(49.25,65.9) J33.20@49.25,66.8 ; v1(49.375,3.75) R90.1@49.375,4.395 ; v1(50.875,3.75) R88.1@50.875,4.395 ; v1(50.95,31.1) 51.02,31.03 R109.2@51.02,30.5 ; v1(72.45,22.5) R93.2@73.02,22.5 ; J21.37@72.5,66.8 v1(72.5,68.125) ; R78.1@72.58,65.1 v1(73.1,65.1) ; v1(73,65.875) J21.38@73,66.8 ; v1(84.7,60.85) 85.39,60.85 C99.2@85.5,60.96 85.932,60.96 86.297,61.325 86.697,61.325 87.012,61.01 U18.3@88.675,61.01 ; C100.2@86,53.19 86.055,53.135 v1(86.55,53.135) U19.3@87.8,53.135
  Bottom Layer w0.3: C105.2@5.2,41.99 6.64,41.99 v1(6.65,42) ; CAD1.1@11.535,40.24 12.14,40.24 12.3,40.4 v1(12.3,41.7) ; R149.1@17.18,34 v1(17.8,34) ; R118.1@32.35,62.4 32.65,62.4 33.6,63.35 v1(33.65,63.35) ; R75.1@43.75,19.73 v1(43.75,20.3) ; v1(57.875,6.525) U16.2@57.875,7.75 ; v1(65.5,10.55) 65.67,10.55 R30.2@66.05,10.93 ; v1(66.05,4.95) R32.2@66.05,5.47 ; R31.2@66.05,8.68 v1(66.05,9.2) ; v1(73.1,65.1) 73.62,65.1 R36.2@74.27,64.45 ; R25.2@75.28,50.4 R24.2@79.62,50.4 ; C7.2@75.5,18.04 75.99,18.04 v1(76.45,18.5) U4.5@77.4,18.5 ; C6.2@75.5,22.04 75.84,21.7 v1(76.15,21.7) 76.35,21.5 U2.5@77.4,21.5 ; C5.2@75.5,24.96 76.26,24.96 v1(76.45,25.15) U6.5@77.4,25.15 ; J7.4@75.75,5.1 v1(75.75,6.25) ; U22.S@80.35,29.15 80.92,29.72 R128.1@81.7,29.72 83.08,29.72 v1(83.45,29.35) 84.22,28.58 R16.2@84.22,28.5 ; R34.2@82.5,6.93 83.23,6.93 v1(83.25,6.95) ; R33.2@82.5,9.48 83.03,9.48 v1(83.05,9.5) ; R132.2@85.25,30.22 85.72,30.22 v1(86.35,30.85) ; v1(86.65,50) 86.55,50.1 R83.1@85.4,50.1 86.2,49.3 v1(87.5,49.3) ; v1(93,22.05) 93,22.91 R122.1@93.84,23.75
  Bottom Layer w0.4: J31.1@9.875,65.2 9.875,64.025 v1(10.05,63.85)
  other v1: 16.4,60.525 15.85,60.55 15.55,61.05
3V3_CODEC: C95.2 C96.2 L26.1 U17.20 U22.D | length 20.2
  Layer 8 w0.3: v1(64.75,25.4) 65.95,26.6 70.85,26.6 72.05,27.8 75.75,27.8 v1(77.34,29.39)
  Bottom Layer w0.2: L26.1@77.15,28.1 77.15,28.99 C96.2@76.75,29.39 v1(77.34,29.39) U22.D@78.05,30.1
  Bottom Layer w0.3: v1(64.75,25.4) 65.71,26.36 C95.2@65.71,26.5 66.157,26.5 66.407,26.25 U17.20@67.05,26.25
5V: C80.2 C81.2 J5.1 J21.39 J21.40 L35.1 L45.1 R12.2 R21.2 U1.F16 U16.1 | length 27.8
  Top Layer w0.3: v1(89.02,12.87) R12.2@89.02,13.5
  Top Layer w0.325: v1(76.7,52.7) 76.9,52.5 U1.F16@77.5,52.5
  Top Layer w0.7: L35.1@5.55,64.6 5.55,65.2 6.3,65.95 v1(6.65,65.95) v1(7.15,65.95)
  Layer 5 w0.5: v1(74.9,65.7) v1(74.55,65.35) 74.85,65.05 74.85,61.1 77.25,58.7 77.25,54.4 76.7,53.85 v1(76.7,52.7)
  Bottom Layer w0.25: v1@55.15,3.55 C80.2@55.15,4.65 ; C81.2@58.335,5.15 58.335,5.86 v1(58.375,5.9) ; J21.39@73.5,66.8 v1(73.5,67.725) ; v1(74,65.875) J21.40@74,66.8
  Bottom Layer w0.3: v1(58.375,5.9) 58.375,6.258 58.4,6.283 58.4,7.725 U16.1@58.375,7.75
  Bottom Layer w0.325: v1(43.7,64.7) 43.7,63.95 R21.2@43.9,63.75 44.2,64.05 v1(44.2,64.7)
  Bottom Layer w0.5: v1(36.7,65.15) 37.05,65.15 v1(37.15,65.05) 37.4,64.8 L45.1@37.4,64.05
  other v1: 55.125,3.525
AGND: C94.1 C97.1 C98.1 D7.1 D8.1 D9.1 J22.1 L27.2 R91.1 R92.1 U17.4 U17.7 | length 13.7
  Top Layer w0.3: D7.1@68.175,13.25 v1(68.75,13.25) D9.1@69.325,13.25 ; v1(76.125,13.25) D8.1@76.7,13.25
  Top Layer w0.4: v1(67.125,4.75) v1(67.75,4.75) ; J22.1@67.7,2.8 J22.1@67.7,3.325 ; J22.1@67.75,2.8 v1(67.75,4.75) ; v1(68.375,4.75) v1(67.75,4.75)
  Bottom Layer w0.25: v1(70.375,17.375) R91.1@70.375,18.145 ; U17.7@71.95,25.25 72.5,25.25 v1(72.75,25) ; U17.4@71.95,26.75 73.25,26.75 C97.1@73.46,26.96 ; v1(72.75,17.375) R92.1@72.75,18.145 ; C97.1@73.5,26.96 73.96,26.96 v1(74.25,27.25)
  Bottom Layer w0.4: C94.1@65.875,22.96 66.24,22.96 v1(66.45,22.75) ; v1(74.25,27.25) 74.25,27.3 L27.2@75.15,28.2 75.5,27.85 C98.1@75.5,26.96
AUD_CLK: R1.2 U17.21 | length 43.2
  Layer 8 w0.125: v1(46.125,43.125) 45.625,43.625 45.625,48.5 46.15,49.025 v1(46.15,49.4)
  Layer 10 w0.125: v1(46.125,43.125) 46.658,43.125 48.163,41.621 48.163,35.226 48.125,35.188 48.125,33.25 50.875,30.5 51.5,30.5 54.75,27.25 57.375,27.25 57.875,27.75 59,27.75 60.375,29.125 63.625,29.125 63.875,29.375 64.5,29.375 65.5,28.375 v1(65.5,27.625)
  Bottom Layer w0.125: v1(46.15,49.4) 46.525,49.4 47.02,49.895 R1.2@47.02,50.5 ; v1(65.5,27.625) 66.125,27 66.313,27 66.563,26.75 U17.21@67.05,26.75
AUD_HP_DET: D9.2 J22.5 R93.1 U1.J24 | length 70.5
  Top Layer w0.125: J22.5@67.725,6.125 v1(69,6.125) ; D9.2@70.425,13.25 v1(71,13.25) ; U1.J24@93.5,46.5 94.15,46.5 v1(94.5,46.85)
  Layer 5 w0.125: v1(71,13.25) 71,13.575 74.25,16.825 74.25,18.75 73.75,19.25 73.75,21.625 v1(74.625,22.5)
  Layer 10 w0.125: v1(74.625,22.5) 78.9,22.5 79.837,23.437 80.671,23.437 80.896,23.663 95.413,23.663 97.15,25.4 97.15,32.4 97.8,33.05 97.8,45.05 96,46.85 v1(94.5,46.85)
  Layer 3 w0.125: v1(69,6.125) 71,8.125 v1(71,13.25)
  Bottom Layer w0.125: R93.1@73.98,22.5 v1(74.625,22.5)
AUD_I2C_SCL: R114.2 U17.29 | length 28.9
  Layer 10 w0.125: v1(47.8,31.35) 47.8,31.075 48.25,30.625 49.875,30.625 52.875,27.625 53.375,27.625 54.3,26.7 59.775,26.7 60.312,26.163 60.975,26.163 62.487,27.675 64.675,27.675 65.15,27.2 65.658,27.2 65.708,27.25 68.333,27.25 69,27.917 v1(69,29.8)
  Bottom Layer w0.125: R114.2@47.02,30.625 47.745,31.35 v1(47.8,31.35) ; v1(69,29.8) 69.317,29.8 69.75,29.367 U17.29@69.75,28.95
AUD_I2C_SDA: R115.2 U17.27 | length 48.8
  Layer 10 w0.125: v1(46.75,46) 46.542,46 45.712,45.171 45.712,39.163 47.85,37.025 47.85,36.3 47.913,36.237 47.913,35.329 47.85,35.267 47.85,33.35 47.387,32.887 47.387,30.688 47.7,30.375 49.625,30.375 52.25,27.75 52.25,27.25 53.25,26.25 55.425,26.25 55.625,26.45 59.25,26.45 59.975,25.725 59.975,25.125 60.475,24.625 61.775,24.625 63.213,26.063 65.113,26.063 65.85,26.8 68.4,26.8 69.45,27.85 69.45,29.667 69.437,29.679 69.437,29.946 69.171,30.213 68.829,30.213 68.4,29.783 v1(68.4,29.75)
  Bottom Layer w0.125: v1(46.75,46) R115.2@47.48,46 ; v1(68.4,29.75) 68.75,29.4 U17.27@68.75,28.95
AUD_PWR_EN: Q4.G R132.1 U1.V15 | length 11.4
  Top Layer w0.125: U1.V15@75.5,28.5 77.15,30.15 80.4,30.15 v1(81.6,31.35)
  Bottom Layer w0.125: v1(81.6,31.35) 82.3,31.35 82.813,31.863 83.337,31.863 83.8,31.4 Q4.G@84.09,31.4 85.03,31.4 R132.1@85.25,31.18
AUD_RXD: U1.M5 U17.25 | length 19.8
  Top Layer w0.125: U1.M5@55.5,40.5 v1(56.25,40.125)
  Layer 10 w0.125: v1(56.25,40.125) 56.458,40.125 61.663,34.921 61.663,34.879 65.104,31.438 67.562,31.438 68.113,30.887 68.113,30.399 66.875,29.162 v1(66.875,29.125)
  Bottom Layer w0.125: v1(66.875,29.125) 67.05,28.95 U17.25@67.75,28.95
AUD_TXC: U1.B7 U17.24 | length 38
  Top Layer w0.125: v1(59.5,59.75) U1.B7@59.5,60.5
  Layer 8 w0.125: v1(62.25,59.025) 61.95,58.725 61.95,50.454 62.8,49.604 62.8,31.95 v1(66.375,28.375)
  Layer 5 w0.125: v1(59.5,59.75) 59.5,59.017 60.029,58.487 60.437,58.487 60.5,58.55 61.775,58.55 v1(62.25,59.025)
  Bottom Layer w0.125: v1(66.375,28.375) 66.5,28.25 U17.24@67.05,28.25
AUD_TXD: U1.C7 U17.26 | length 34.4
  Top Layer w0.125: U1.C7@59.5,58.5 v1(60.75,58.125)
  Layer 5 w0.125: v1(60.75,58.125) 61.987,56.888 61.987,52.813 63.737,51.063 63.737,32.451 65.188,31 66.333,31 v1(67,30.333)
  Bottom Layer w0.125: v1(67,30.333) 67.217,30.333 68.25,29.3 U17.26@68.25,28.95
AUD_TXFS: U1.C5 U17.23 | length 38.7
  Top Layer w0.125: U1.C5@55.5,58.5 56.375,59.125
  Layer 5 w0.125: v1(56.625,59.125) 59,59.125 61.737,56.388 61.737,51.714 62.509,50.942 62.558,50.942 63.237,50.263 63.237,31.176 65.43,28.983 65.43,28.445 v1(66.125,27.75)
  Bottom Layer w0.125: v1(66.125,27.75) U17.23@67.05,27.75
BOOT_CFG_1_4: R18.1 U1.W24 | length 10
  Top Layer w0.125: U1.W24@93.5,26.5 96.25,26.5 97.05,27.3 97.05,32.4 97.5,32.85 R18.1@97.92,32.85
BOOT_CFG_1_5: R10.1 SW3.3 U1.AA19 U4.1 | length 117.3
  Top Layer w0.125: SW3.3@22.884,62.367 21.837,61.321 21.837,60.613 22.1,60.35 22.986,60.35 v1(23.625,60.988) ; SW3.3@22.885,62.367 SW3.3@22.885,62.41 ; v1(82.75,23.25) U1.AA19@83.5,22.5
  Layer 8 w0.125: v1(21.5,33.225) 21.337,33.388 21.337,37.884 23.013,39.559 23.013,42.891 21.85,44.054 21.85,58.854 21.85,59.214 v1(23.625,60.988) ; v1(80.5,19.125) 81,19.625 81,20.137 82.75,21.887 v1(82.75,23.25)
  Layer 5 w0.125: v1(21.5,33.225) 22.6,32.125 22.6,24.5 25.1,22 27.125,22 31.288,17.837 36.638,17.837 36.925,18.125 44.75,18.125 46,16.875 46.625,16.875 47.875,15.625 v1(47.875,14.75)
  Layer 10 w0.125: v1(47.875,14.75) 49.5,14.75 51.2,13.05 57.736,13.05 59.136,14.45 59.167,14.45 59.179,14.463 72.913,14.463 74.45,16 75.937,16 76.925,16.988 76.925,17.55 78.5,19.125 v1(80.5,19.125)
  Bottom Layer w0.125: R10.1@23.6,60.28 23.6,60.964 v1(23.625,60.988) ; U4.1@79.6,19.15 v1@80.475,19.15
BOOT_CFG_1_6: R9.1 SW3.4 U1.U23 U2.1 | length 127.4
  Top Layer w0.125: v1(21.1,60.4) 21.1,60.937 21.615,61.452 SW3.4@21.615,62.41 ; v1(90.8,31.25) 90.8,31.2 U1.U23@91.5,30.5
  Layer 8 w0.125: v1(20.9,32.6) 21.038,32.738 21.038,37.938 22.763,39.663 22.763,42.787 21.6,43.95 21.6,60 21.2,60.4 v1(21.1,60.4)
  Layer 5 w0.125: v1(20.9,32.6) 22.3,31.2 22.3,24.446 24.996,21.75 26.95,21.75 31.113,17.587 36.741,17.587 37.029,17.875 44.625,17.875 46.15,16.35 46.4,16.35 v1(47,15.75) ; v1(80.5,22.125) 83.5,22.125 85.212,23.837 88.571,23.837 90.763,26.029 90.763,31.213 v1(90.8,31.25)
  Layer 10 w0.125: v1(47,15.75) 48.946,15.75 51.396,13.3 57.632,13.3 59.032,14.7 59.063,14.7 59.076,14.713 72.809,14.713 74.346,16.25 75.833,16.25 76.625,17.042 76.625,17.625 79.975,20.975 79.975,21.608 80.492,22.125 v1(80.5,22.125)
  Bottom Layer w0.125: v1(21.1,60.4) 21.1,59.88 R9.1@21.2,59.78 ; U2.1@79.6,22.15 v1@80.475,22.15
BOOT_CFG_1_7: R19.1 U1.Y21 | length 3.2
  Top Layer w0.125: v1(86.75,24.3) 86.95,24.5 U1.Y21@87.5,24.5
  Bottom Layer w0.125: R19.1@85.13,26 86.75,24.38 v1(86.75,24.3)
BOOT_CFG_2_5: R16.1 U1.V20 | length 1.5
  Top Layer w0.125: v1(85.15,29.15) 85.5,28.8 U1.V20@85.5,28.5
  Bottom Layer w0.125: v1(85.15,29.15) 85.18,29.12 R16.1@85.18,28.5
BOOT_CFG_2_6: R17.1 U1.W21 | length 1.5
  Top Layer w0.125: v1(86.9,26.1) 87.3,26.5 U1.W21@87.5,26.5
  Bottom Layer w0.125: v1(86.9,26.1) R17.1@86.9,26.82
BOOT_MODE0: R24.1 R28.1 U1.E17 | length 7.7
  Top Layer w0.125: U1.E17@79.5,54.5 80.5,53.5 81.75,53.5 82.294,52.956 82.294,51.556 82.3,51.562 v1(82.3,51.7)
  Bottom Layer w0.125: R24.1@80.58,50.35 81.52,50.35 R28.1@81.67,50.5 ; R28.1@81.67,50.35 R28.1@81.67,50.5 ; v1(82.3,51.7) 81.67,51.07 R28.1@81.67,50.5
BOOT_MODE1: R25.1 R29.1 U1.F15 | length 8
  Top Layer w0.125: v1(72.05,51.5) 72.767,51.5 72.979,51.287 73.321,51.287 74.533,52.5 U1.F15@75.5,52.5
  Bottom Layer w0.125: R29.1@72.32,50.4 72.05,50.67 v1(72.05,51.5) 72.512,51.038 73.682,51.038 R25.1@74.32,50.4
BT_DISABLE_N: R4.2 U1.H3 | length 8.7
  Top Layer w0.125: v1(50.4,49.1) 51,48.5 U1.H3@51.5,48.5
  Bottom Layer w0.125: v1(50.4,49.1) 50.4,50.975 51.5,52.075 R4.2@51.5,56.02
CAN1_H: J27.2 R104.2 U18.7 | length 11.5
  Bottom Layer w0.125: R104.2@91.98,56.5 91.98,58.93 92.79,59.74 U18.7@94.075,59.74 94.95,59.74 96.2,60.99 96.2,63 96.75,63.55 J27.2@98,63.55
CAN1_L: J27.1 R104.1 U18.6 | length 13.1
  Bottom Layer w0.125: R104.1@91.02,56.5 91.02,59.42 92.61,61.01 U18.6@94.075,61.01 95.01,61.01 95.7,61.7 95.7,63.3 97.2,64.8 J27.1@98,64.8
CAN1_RXD: U1.F3 U18.4 | length 43
  Top Layer w0.125: U1.F3@51.5,52.5 v1(52.25,52.875)
  Layer 10 w0.125: v1(52.25,52.875) 52.413,52.712 54.384,52.712 58.721,57.05 69.483,57.05 71.946,59.513 82.137,59.513 82.763,58.887 84.937,58.887 85.45,59.4 86.65,59.4 87.525,60.275 v1(87.525,62.275)
  Bottom Layer w0.125: v1(87.525,62.275) 88.67,62.275 U18.4@88.675,62.28
CAN1_STBY: U1.G3 U18.8 | length 47.1
  Top Layer w0.125: U1.G3@51.5,50.5 v1(52.325,50.3)
  Layer 10 w0.125: v1(52.325,50.3) 58.825,56.8 69.587,56.8 72.049,59.263 80.029,59.263 80.654,58.637 85.087,58.637 85.6,59.15 91.825,59.15 v1(92.5,58.475)
  Bottom Layer w0.125: v1@92.5,58.47 U18.8@94.075,58.47
CAN1_TXD: U1.P3 U18.1 | length 54.7
  Top Layer w0.125: U1.P3@51.5,36.5 51.8,36.2 v1(52.3,36.2)
  Layer 10 w0.125: v1(52.3,36.2) 51.687,36.813 51.687,39.074 53.55,40.937 53.55,46.712 58.15,51.312 58.15,55.5 59.2,56.55 69.69,56.55 72.153,59.013 79.925,59.013 80.55,58.387 86.387,58.387 v1(86.5,58.5)
  Bottom Layer w0.125: v1(86.5,58.5) 87.895,58.5
CAN2_H: J27.5 R116.2 U19.7 | length 11.8
  Bottom Layer w0.125: U19.7@93.2,51.865 94.49,51.865 95.125,52.5 95.125,56.5 ; R116.2@94.48,56.5 95.125,56.5 ; J27.5@98,59.8 97.15,59.8 96.4,59.05 96.4,57.775 95.125,56.5
CAN2_L: J27.4 R116.1 U19.6 | length 12.3
  Bottom Layer w0.125: U19.6@93.2,53.135 94.135,53.135 94.375,53.375 94.375,54.7 93.52,55.555 R116.1@93.52,56.5 93.52,56.97 94.05,57.5 95.25,57.5 95.85,58.1 95.85,59.7 97.2,61.05 J27.4@98,61.05
CAN2_RXD: U1.D21 U19.4 | length 3.3
  Top Layer w0.125: v1(86.625,55.875) U1.D21@87.5,56.5
  Bottom Layer w0.125: v1(86.625,55.875) 87,55.875 87.8,55.075 U19.4@87.8,54.405
CAN2_STBY: U1.R3 U19.8 | length 68.2
  Top Layer w0.125: v1(51.5,33.625) U1.R3@51.5,34.5
  Layer 8 w0.125: v1(67.15,30.95) 67.467,30.95 67.529,31.013 77.387,31.013 78.05,30.35 83.375,30.35 85.05,32.025 85.05,37.125 83.9,38.275 83.9,45.25 85.3,46.65 85.3,51.425 v1(85.1,51.625)
  Layer 10 w0.125: v1(51.5,33.625) 51.588,33.713 53.687,33.713 54.513,32.887 55.971,32.887 55.996,32.913 63.021,32.913 64.983,30.95 v1(67.15,30.95) ; v1(85.1,51.625) 86.25,51.625 87.25,50.625 v1(94.375,50.625)
  Bottom Layer w0.125: U19.8@93.23,50.625 v1(94.375,50.625)
CAN2_TXD: U1.F20 U19.1 | length 3.5
  Top Layer w0.125: U1.F20@85.5,52.5 85.5,51.808 86.625,50.683 v1(86.625,50.625)
  Bottom Layer w0.125: v1(86.625,50.625) U19.1@87.77,50.625
CLK1_N: C31.1 U1.B18 | length 32.8
  Top Layer w0.157: v1(80.875,61.125) U1.B18@81.5,60.5
  Layer 8 w0.119: v1(56.825,53.375) 56.622,53.578 56.622,55.422 57.598,56.398 57.669,56.469 57.669,58.524 61.645,62.5 77.28,62.5 78.402,61.378 80.622,61.378 v1(80.875,61.125)
  Bottom Layer w0.157: v1(56.825,53.375) C31.1@57.5,52.96
CLK1_P: C32.1 U1.A18 | length 33.2
  Top Layer w0.157: v1(80.875,61.875) U1.A18@81.5,62.5
  Layer 8 w0.119: v1(56.175,53.375) 56.175,53.425 56.378,53.628 56.378,55.523 57.425,56.57 57.425,58.625 61.544,62.744 77.381,62.744 78.503,61.622 80.622,61.622 v1(80.875,61.875)
  Bottom Layer w0.157: C32.1@55.5,52.96 v1(56.175,53.375)
CONSOLE_RX: J9.2 U8.4 | length 27
  Top Layer w0.125: U8.4@27.025,54.005 27.025,53.155 v1(27.225,52.955)
  Layer 10 w0.125: J9.2@6,55.05 10.872,55.05 12.909,57.087 20.902,57.087 21.7,56.289 21.7,53.404 22.654,52.45 26.72,52.45 v1(27.225,52.955)
CONSOLE_TX: J9.1 U8.9 | length 30.6
  Top Layer w0.125: v1(29.95,52.35) 30.275,52.675 U8.9@30.275,54.005
  Layer 10 w0.125: J9.1@6,53.8 9.975,53.8 12.975,56.8 20.833,56.8 21.45,56.183 21.45,53.3 22.55,52.2 29.8,52.2 v1(29.95,52.35)
CSI0_DAT12: J17.2 U1.L5 | length 34.9
  Top Layer w0.125: J17.2@48.75,66.8 48.75,65.775 49.35,65.175 49.35,63.5 51.6,61.25 57.75,61.25 58.5,60.5 58.5,50.25 59.875,48.875 59.875,45.875 56.5,42.5 U1.L5@55.5,42.5
CSI0_DAT13: J17.3 U1.C6 | length 17.1
  Top Layer w0.125: J17.3@48.25,66.8 48.25,65.875 49.025,65.1 49.025,59.479 50.754,57.75 56.75,57.75 U1.C6@57.5,58.5
CSI0_DAT14: J17.4 U1.B6 | length 21.1
  Top Layer w0.125: J17.4@47.75,66.8 47.75,65.975 48.7,65.025 48.7,59.385 50.585,57.5 57.625,57.5 58.25,58.125 58.25,59.75 U1.B6@57.5,60.5
CSI0_DAT15: J17.5 U1.E6 | length 20.6
  Top Layer w0.125: J17.5@47.25,66.8 47.25,66.075 48.337,64.988 48.337,56.663 49.25,55.75 56.25,55.75 U1.E6@57.5,54.5
CSI0_DAT16: J17.6 U1.H6 | length 27.3
  Top Layer w0.125: J17.6@46.75,66.8 46.75,65.3 47.8,64.25 47.8,56.45 49,55.25 53.75,55.25 55.212,53.788 57.212,53.788 58.25,52.75 58.25,50 57.5,49.25 U1.H6@57.5,48.5
CSI0_DAT17: J17.7 U1.A7 | length 20.3
  Top Layer w0.125: J17.7@46.25,66.8 46.25,68.375 46.675,68.8 49.45,68.8 49.7,68.55 49.7,65.9 51.2,64.4 51.2,63.6 53.05,61.75 57.75,61.75 58.5,62.5 U1.A7@59.5,62.5
CSI0_DAT18: J17.8 U1.F6 | length 24.5
  Top Layer w0.125: J17.8@45.75,66.8 45.75,65.625 47.55,63.825 47.55,56.325 48.625,55.25 48.625,54.125 49.25,53.5 52.375,53.5 52.75,53.125 52.75,52.321 53.228,51.843 53.772,51.843 53.792,51.863 55.208,51.863 55.228,51.843 55.81,51.843 56.454,52.487 57.5,52.487 U1.F6@57.5,52.5
CSI0_DAT19: J17.9 U1.G6 | length 25.6
  Top Layer w0.125: J17.9@45.25,66.8 45.25,65.675 47.275,63.65 47.275,56.225 48.375,55.125 48.375,52.475 49.257,51.593 53.876,51.593 53.895,51.613 55.105,51.613 55.124,51.593 55.407,51.593 56.5,50.5 U1.G6@57.5,50.5
CSI0_GPIO: J17.15 U1.E5 | length 23.6
  Top Layer w0.125: v1(42.25,65.875) J17.15@42.25,66.8 ; v1(47.375,65.325) 48.075,64.625 48.075,56.55 49.125,55.5 54.5,55.5 U1.E5@55.5,54.5
  Layer 10 w0.125: v1(42.25,65.875) 42.8,65.325 v1(47.375,65.325)
CSI0_HSYNC: J17.13 U1.A5 | length 19.3
  Top Layer w0.125: J17.13@43.25,66.8 43.25,68.775 43.525,69.05 51.775,69.05 52.363,68.462 52.363,67.913 51.775,67.325 51.775,66 53.65,64.125 53.875,64.125 U1.A5@55.5,62.5
CSI0_I2C_SCL: J17.18 R108.2 | length 36.3
  Top Layer w0.125: J17.18@40.75,66.8 40.75,66.15 41.475,65.425 41.987,65.425 45.6,61.812 45.6,40.625 46.425,39.8 46.425,34.55 v1(46.125,34.25)
  Bottom Layer w0.125: v1(46.125,34.25) 46.895,34.25 R108.2@47.02,34.375
CSI0_I2C_SDA: J17.19 R111.2 | length 28.5
  Top Layer w0.125: J17.19@40.25,66.8 40.25,66.075 41.15,65.175 41.883,65.175 45.35,61.708 45.35,46.35 v1(45,46)
  Bottom Layer w0.125: v1(45,46) 46.05,46 46.6,45.45 48.05,45.45 48.62,46.02 R111.2@49.5,46.02
CSI0_MCLK: J17.11 R3.2 | length 15.8
  Top Layer w0.125: J17.11@44.25,66.8 44.25,66 46.6,63.65 46.6,54.7 46.7,54.6 v1(46.7,54.4)
  Bottom Layer w0.125: v1(46.7,54.4) 46.45,54.15 46.45,52.945 R3.2@47.02,52.375
CSI0_PIXCLK: J17.12 U1.G5 | length 25.8
  Top Layer w0.125: J17.12@43.75,66.8 43.75,66.025 46.213,63.562 46.213,51.962 46.462,51.713 48.621,51.713 48.99,51.343 53.979,51.343 53.999,51.363 54.671,51.363 55.5,50.533 U1.G5@55.5,50.5
CSI0_RESET_N: J17.16 U1.AA13 | length 72.9
  Top Layer w0.125: J17.16@41.75,66.8 v1(41.75,68.375) ; v1(70.55,22.8) 71.2,22.8 U1.AA13@71.5,22.5
  Layer 5 w0.125: v1(41.75,68.375) 42.175,68.8 52.775,68.8 55.687,65.888 55.687,59.126 57.927,56.886 60.114,56.886 61.237,55.763 61.237,51.507 62.302,50.442 62.329,50.442 62.737,50.034 62.737,30.968 63.75,29.956 63.75,26 63.625,25.875 63.625,23.042 64.329,22.337 67.387,22.337 67.85,22.8 v1(70.55,22.8)
CSI0_VSYNC: J17.14 U1.J5 | length 29.7
  Top Layer w0.125: J17.14@42.75,66.8 42.75,65.05 45.85,61.95 45.85,50.417 46.754,49.513 53.737,49.513 54.5,48.75 54.5,47.5 U1.J5@55.5,46.5
CSI1_DAT12: J33.2 U1.AC17 | length 128.7
  Top Layer w0.125: v1(78.5,18.5) U1.AC17@79.5,18.5
  Layer 8 w0.125: v1(41.9,30.45) 41.9,28.912 44.187,26.625 46.575,26.625 49.5,23.7 v1(49.5,21.125)
  Layer 10 w0.125: v1(49.5,21.125) 49.95,20.675 51.775,20.675 52.275,21.175 53.35,21.175 54.188,22.013 54.65,22.013 54.666,22.013 ccw(c54.666,22.159) 54.812,22.159 54.812,22.229 cw(c54.959,22.229) 54.959,22.375 54.991,22.375 cw(c54.991,22.229) 55.137,22.229 55.137,22.013 55.137,21.796 ccw(c55.284,21.796) 55.284,21.65 55.316,21.65 ccw(c55.316,21.796) 55.463,21.796 55.463,21.866 cw(c55.609,21.866) 55.609,22.013 56.571,22.013 57.475,21.108 57.475,20.5 58.025,19.95 64.6,19.95 70.35,25.7 73.35,25.7 75.85,23.2 v1(76.95,23.2)
  Layer 3 w0.125: v1(40.25,65.25) 40.25,64.684 ccw(c40.396,64.684) 40.396,64.538 40.462,64.538 cw(c40.462,64.391) 40.608,64.391 40.608,64.359 cw(c40.462,64.359) 40.462,64.213 40.038,64.213 ccw(c40.038,64.066) 39.892,64.066 39.892,64.034 ccw(c40.038,64.034) 40.038,63.887 40.462,63.887 cw(c40.462,63.741) 40.608,63.741 40.608,63.709 cw(c40.462,63.709) 40.462,63.562 40.038,63.562 ccw(c40.038,63.416) 39.892,63.416 39.892,63.384 ccw(c40.038,63.384) 40.038,63.237 40.462,63.237 cw(c40.462,63.091) 40.608,63.091 40.608,63.059 cw(c40.462,63.059) 40.462,62.912 40.396,62.912 ccw(c40.396,62.766) 40.25,62.766 40.25,61.5 38.35,59.6 38.35,45.15 38.6,44.9 38.869,44.9 39.138,45.169 39.138,59.287 39.35,59.5 39.75,59.5 40,59.25 40,45.946 40.013,45.933 40.013,44.896 37.387,42.271 37.387,35.763 37.8,35.35 37.8,32.742 39.492,31.05 41.3,31.05 v1(41.9,30.45) ; v1(76.95,23.2) 76.95,19.475 77.925,18.5 v1(78.5,18.5)
  Bottom Layer w0.125: v1(40.25,65.25) J33.2@40.25,66.8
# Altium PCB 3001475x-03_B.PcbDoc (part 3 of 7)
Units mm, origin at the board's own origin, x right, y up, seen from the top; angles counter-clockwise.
Board outline 100 x 72 mm, 12 copper layers (Top Layer, L2 GND, Layer 3, L4 GND, Layer 5, L6 PWR, L7 3V3, Layer 8, L9 GND, Layer 10, L11 GND, Bottom Layer), stack 1.735 mm thick; 431 components, 499 nets, 1977 pads, 1473 vias.

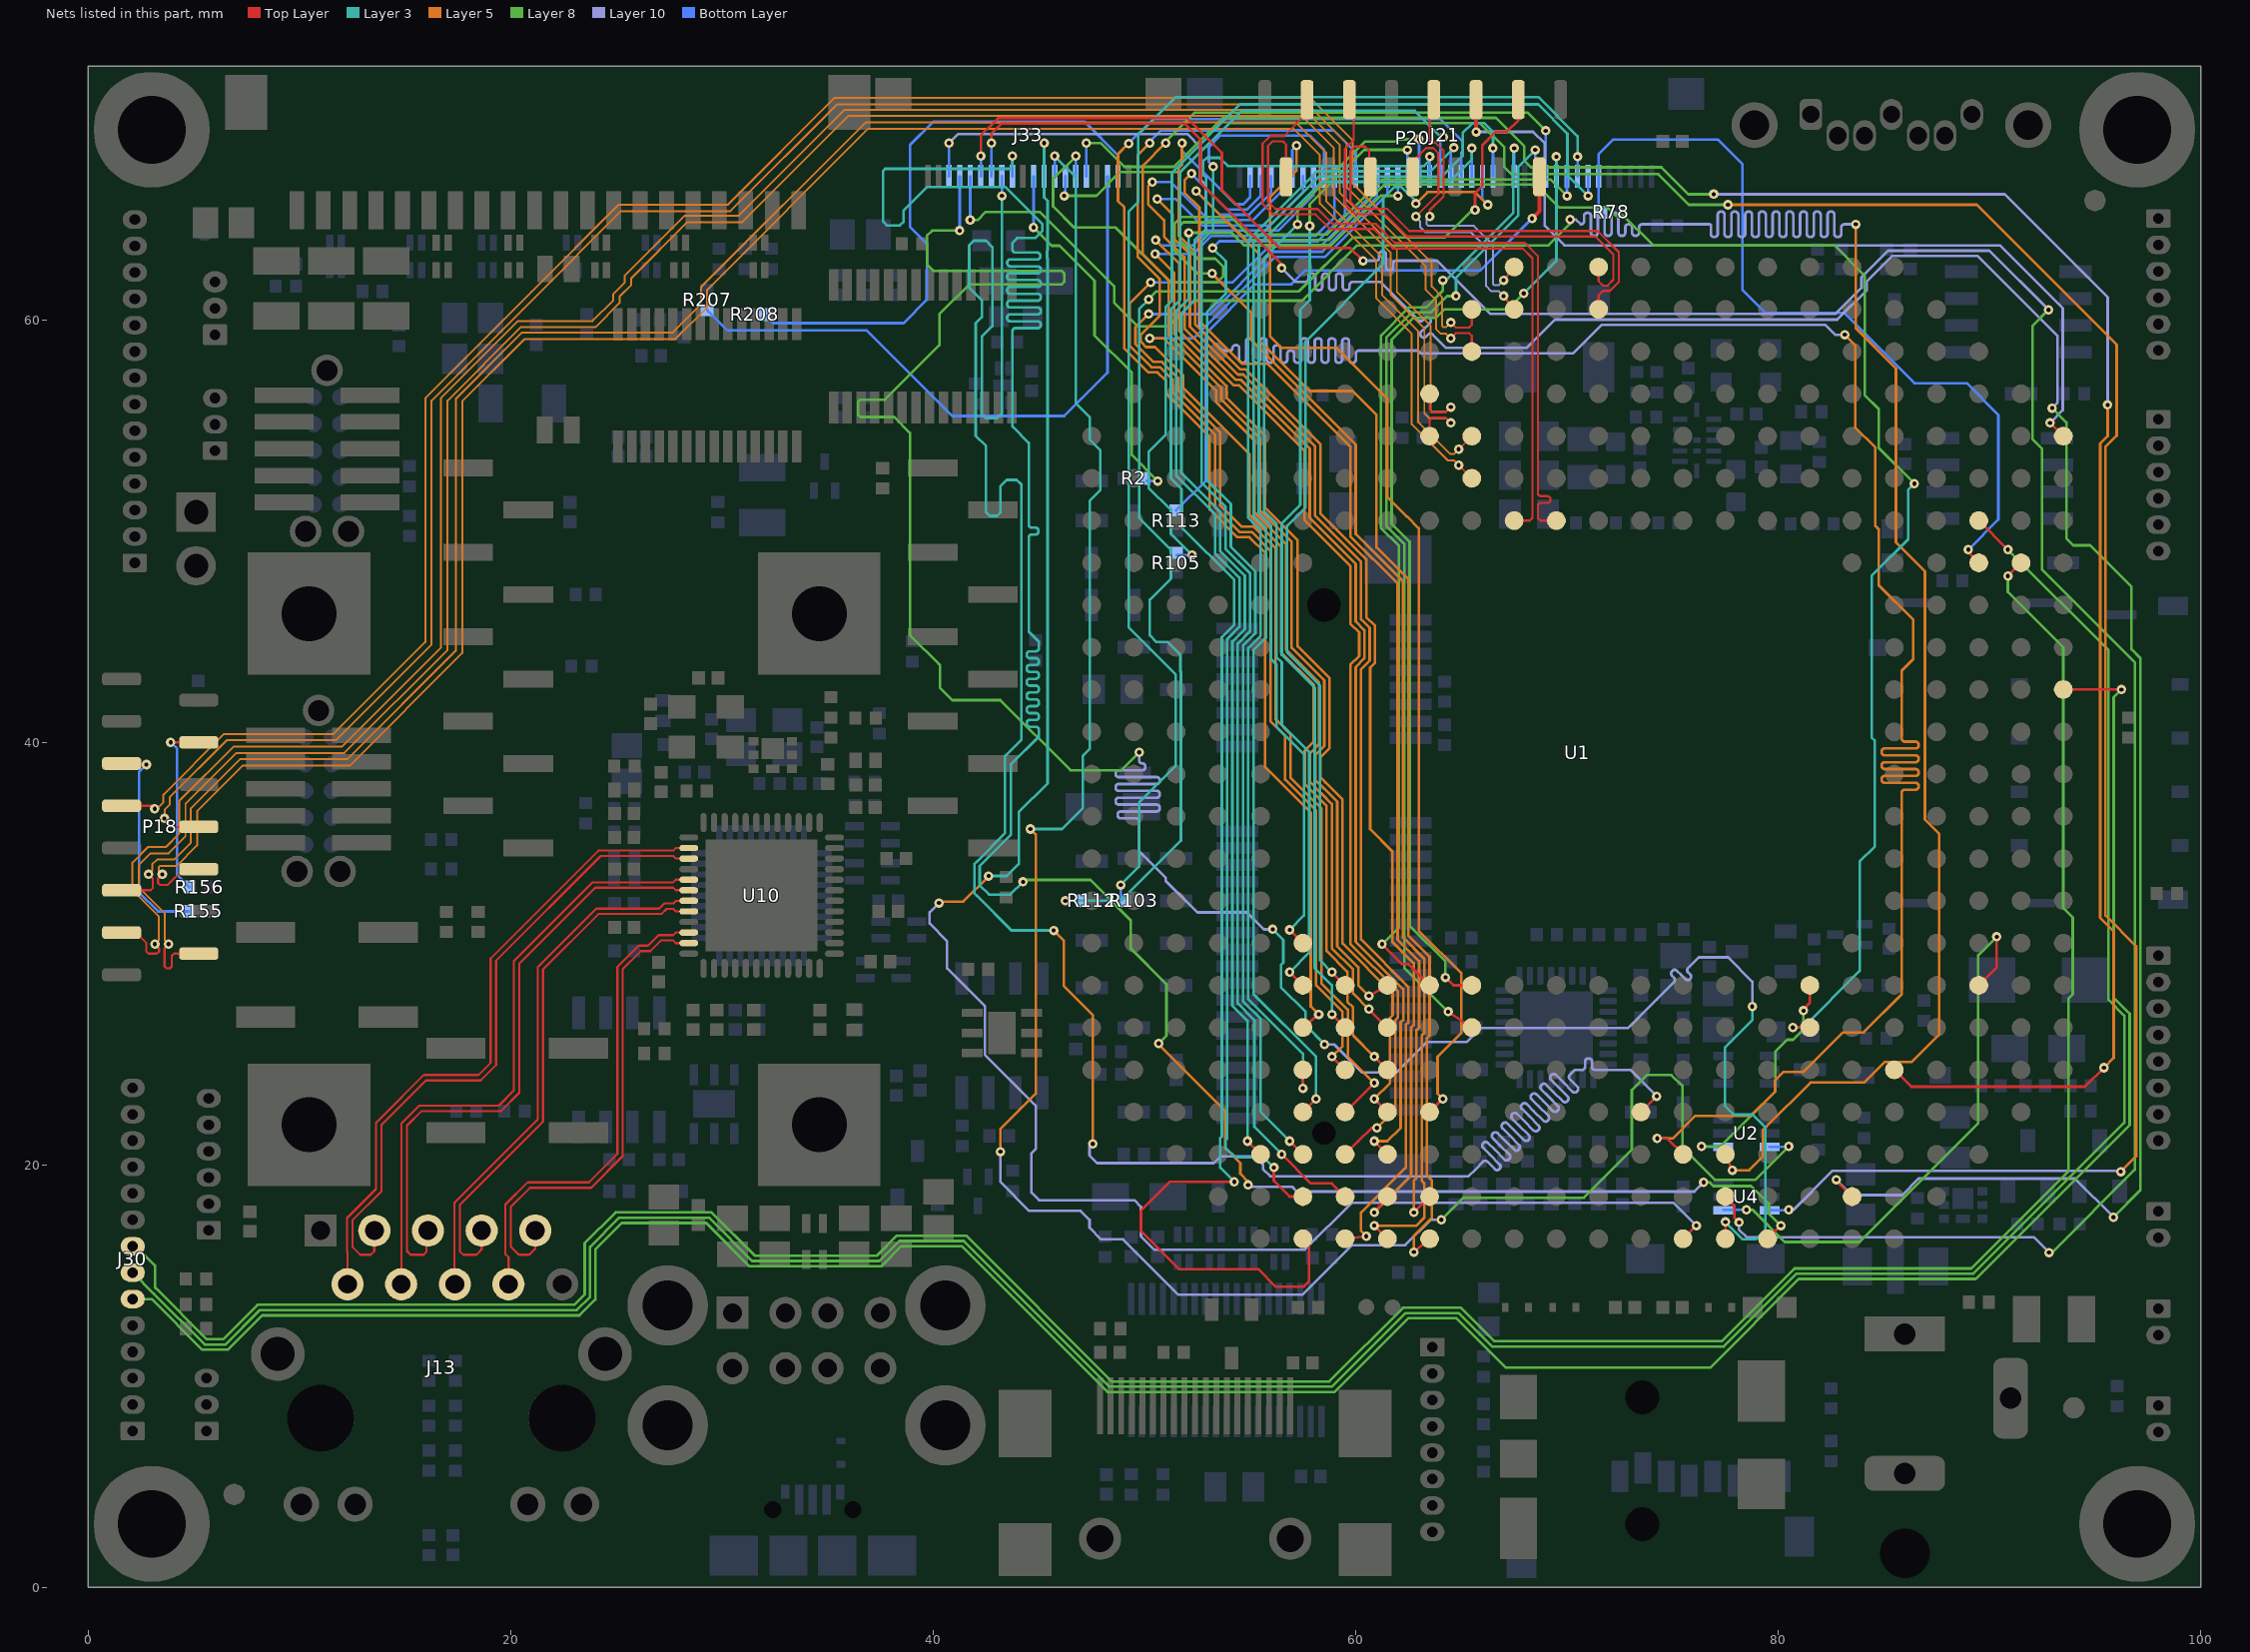
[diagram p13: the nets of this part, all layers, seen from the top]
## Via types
v1: diameter 0.45, hole 0.2, Top Layer to Bottom Layer, tented both sides, 1473 vias

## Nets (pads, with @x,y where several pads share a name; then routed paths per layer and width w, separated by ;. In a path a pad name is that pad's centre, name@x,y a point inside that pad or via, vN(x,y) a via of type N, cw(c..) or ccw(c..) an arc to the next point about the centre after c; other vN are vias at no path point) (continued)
CSI1_DAT13: J33.3 U1.AB15 | length 130.5
  Top Layer w0.125: v1(74.275,21.25) 74.75,21.25 U1.AB15@75.5,20.5
  Layer 5 w0.125: v1(74.275,21.25) 75,21.25 76.075,22.325 78.7,22.325 79.85,23.475 79.85,24 80.25,24.4 81.2,24.4 83.075,26.275 84.05,26.275 85.85,28.075 85.85,37.616 cw(c85.996,37.616) 85.996,37.762 86.503,37.762 ccw(c86.503,37.909) 86.649,37.909 86.649,37.941 ccw(c86.503,37.941) 86.503,38.087 85.047,38.087 cw(c85.047,38.234) 84.901,38.234 84.901,38.266 cw(c85.047,38.266) 85.047,38.412 86.503,38.412 ccw(c86.503,38.559) 86.649,38.559 86.649,38.591 ccw(c86.503,38.591) 86.503,38.737 85.047,38.737 cw(c85.047,38.884) 84.901,38.884 84.901,38.916 cw(c85.047,38.916) 85.047,39.062 86.503,39.062 ccw(c86.503,39.209) 86.649,39.209 86.649,39.241 ccw(c86.503,39.241) 86.503,39.388 85.047,39.388 cw(c85.047,39.534) 84.901,39.534 84.901,39.566 cw(c85.047,39.566) 85.047,39.713 86.503,39.713 ccw(c86.503,39.859) 86.649,39.859 86.649,39.891 ccw(c86.503,39.891) 86.503,40.038 85.996,40.038 cw(c85.996,40.184) 85.85,40.184 85.85,43.4 86.4,43.95 86.4,45.8 84.763,47.437 84.763,50.087 84.6,50.25 84.6,53.95 83.65,54.9 83.65,58.8 v1(83.15,59.3)
  Layer 10 w0.125: v1(40.75,68.375) 41.175,68.8 52.025,68.8 52.65,68.175 52.65,66.65 52.9,66.4 52.9,64.275 52.6,63.975 52.6,59.613 53.663,58.55 54,58.55 54.053,58.55 ccw(c54.053,58.659) 54.163,58.659 cw(c54.309,58.659) 54.309,58.806 54.341,58.806 cw(c54.341,58.659) 54.488,58.659 54.488,58.55 54.488,58.121 ccw(c54.634,58.121) 54.634,57.975 54.666,57.975 ccw(c54.666,58.121) 54.813,58.121 54.813,58.55 54.813,58.979 cw(c54.959,58.979) 54.959,59.125 54.991,59.125 cw(c54.991,58.979) 55.138,58.979 55.138,58.55 55.138,58.121 ccw(c55.284,58.121) 55.284,57.975 55.316,57.975 ccw(c55.316,58.121) 55.463,58.121 55.463,58.55 55.463,58.979 cw(c55.609,58.979) 55.609,59.125 55.641,59.125 cw(c55.641,58.979) 55.788,58.979 55.788,58.55 55.788,58.121 ccw(c55.934,58.121) 55.934,57.975 55.966,57.975 ccw(c55.966,58.121) 56.113,58.121 56.113,58.55 56.113,58.654 cw(c56.259,58.654) 56.259,58.8 56.291,58.8 cw(c56.291,58.654) 56.438,58.654 56.438,58.55 56.438,58.121 ccw(c56.584,58.121) 56.584,57.975 56.616,57.975 ccw(c56.616,58.121) 56.763,58.121 56.763,58.404 cw(c56.909,58.404) 56.909,58.55 56.941,58.55 cw(c56.941,58.404) 57.088,58.404 57.088,58.121 ccw(c57.234,58.121) 57.234,57.975 57.266,57.975 ccw(c57.266,58.121) 57.413,58.121 57.413,58.55 57.413,58.979 cw(c57.559,58.979) 57.559,59.125 57.591,59.125 cw(c57.591,58.979) 57.738,58.979 57.738,58.55 57.738,58.121 ccw(c57.884,58.121) 57.884,57.975 57.916,57.975 ccw(c57.916,58.121) 58.063,58.121 58.063,58.55 58.063,58.979 cw(c58.209,58.979) 58.209,59.125 58.241,59.125 cw(c58.241,58.979) 58.388,58.979 58.388,58.55 58.388,58.121 ccw(c58.534,58.121) 58.534,57.975 58.566,57.975 ccw(c58.566,58.121) 58.713,58.121 58.713,58.55 58.713,58.979 cw(c58.859,58.979) 58.859,59.125 58.891,59.125 cw(c58.891,58.979) 59.038,58.979 59.038,58.55 59.038,58.121 ccw(c59.184,58.121) 59.184,57.975 59.216,57.975 ccw(c59.216,58.121) 59.363,58.121 59.363,58.55 59.363,58.979 cw(c59.509,58.979) 59.509,59.125 59.541,59.125 cw(c59.541,58.979) 59.688,58.979 59.688,58.55 59.688,58.121 ccw(c59.834,58.121) 59.834,57.975 59.866,57.975 ccw(c59.866,58.121) 60.013,58.121 60.013,58.404 cw(c60.159,58.404) 60.159,58.55 60.35,58.55 62.95,58.55 63.075,58.425 70.3,58.425 71.638,59.763 82.241,59.763 82.704,59.3 v1(83.15,59.3)
  Bottom Layer w0.125: J33.3@40.75,66.8 v1(40.75,68.375)
CSI1_DAT14: J33.4 U1.AD16 | length 128.1
  Top Layer w0.125: U1.AD16@77.5,16.5 v1(77.5,17.3)
  Layer 8 w0.125: 40.25,43.725 40.325,43.65 ; v1(41.25,64.225) 39.95,64.225 39.7,63.975 39.7,62.625 40,62.325 46.075,62.325 46.2,62.2 46.2,61.8 46.075,61.675 41.692,61.675 40.287,60.271 40.287,58.804 37.708,56.225 36.55,56.225 36.45,56.125 36.45,55.5 36.55,55.4 38.15,55.4 38.9,54.65 38.9,45.075 40.325,43.65 ; v1(49.75,39.525) 48.908,38.683 46.492,38.683 43.175,42 40.9,42 40.325,42.575 40.325,43.65
  Layer 10 w0.125: v1(49.75,39.525) 49.75,39.168 49.75,39.152 ccw(c49.896,39.152) 49.896,39.006 cw(c49.896,38.859) 50.043,38.859 50.043,38.827 cw(c49.896,38.827) 49.896,38.681 49.75,38.681 48.783,38.681 ccw(c48.783,38.534) 48.637,38.534 48.637,38.502 ccw(c48.783,38.502) 48.783,38.356 49.75,38.356 50.579,38.356 cw(c50.579,38.209) 50.725,38.209 50.725,38.177 cw(c50.579,38.177) 50.579,38.031 49.75,38.031 48.783,38.031 ccw(c48.783,37.884) 48.637,37.884 48.637,37.852 ccw(c48.783,37.852) 48.783,37.706 49.75,37.706 50.579,37.706 cw(c50.579,37.559) 50.725,37.559 50.725,37.527 cw(c50.579,37.527) 50.579,37.381 49.75,37.381 48.783,37.381 ccw(c48.783,37.234) 48.637,37.234 48.637,37.202 ccw(c48.783,37.202) 48.783,37.056 49.75,37.056 50.579,37.056 cw(c50.579,36.909) 50.725,36.909 50.725,36.877 cw(c50.579,36.877) 50.579,36.731 49.75,36.731 48.873,36.731 ccw(c48.873,36.584) 48.727,36.584 48.727,36.552 ccw(c48.873,36.552) 48.873,36.406 49.604,36.406 cw(c49.604,36.259) 49.75,36.259 49.75,35.55 49.75,34.85 51,33.6 51,33.454 52.504,31.95 54.85,31.95 55.65,31.15 v1(56.075,31.15) ; v1(58.525,25.7) 58.975,25.7 60.3,24.375 61.925,24.375 63.363,25.813 65.238,25.813 65.9,26.475 72.892,26.475 74.258,27.842 75.072,28.655 ccw(c74.969,28.759) 75.072,28.862 74.974,28.96 cw(c75.078,29.063) 74.974,29.167 74.997,29.19 cw(c75.101,29.086) 75.204,29.19 75.405,28.989 75.606,28.788 ccw(c75.71,28.891) 75.813,28.788 75.836,28.811 ccw(c75.733,28.914) 75.836,29.017 75.739,29.115 cw(c75.842,29.218) 75.739,29.322 75.75,29.333 76.242,29.825 77.625,29.825 78.775,28.675 v1(78.775,27.5)
  Layer 3 w0.125: v1(56.075,31.15) 56.575,30.65 56.575,29.575 56.462,29.462 56.462,29.271 56.463,28.412 57.625,27.25 57.625,26.6 v1(58.525,25.7) ; v1(77.5,17.3) 78.325,16.475 78.925,16.475 79.4,16.95 79.4,21.775 78.8,22.375 77.9,22.375 77.475,22.8 77.475,25.55 78.775,26.85 v1(78.775,27.5)
  Bottom Layer w0.125: v1(41.25,64.225) J33.4@41.25,66.8
CSI1_DAT15: J33.5 U1.AB16 | length 130
  Top Layer w0.125: U1.AB16@77.5,20.5 v1(77.825,19.75)
  Layer 8 w0.125: v1(41.75,64.725) 42.1,64.725 42.488,65.113 45.037,65.113 48.575,61.575 48.575,60.8 49.675,59.7 51.15,59.7 52.363,60.913 57.459,60.913 60.071,63.524 69.124,63.524 70.15,64.55 v1(70.15,64.75)
  Layer 5 w0.125: v1(77.825,19.75) 78.625,19.75 79.275,20.4 79.275,21.65 79.425,21.8 79.429,21.8 81.529,23.9 84.075,23.9 85.05,24.875 86.325,24.875 87.625,26.175 87.625,35.675 86.95,36.35 86.95,48.1 85.575,49.475 85.575,57.7 83.675,59.6 v1(83.675,64.525)
  Layer 10 w0.125: v1(70.15,64.75) 70.425,64.75 70.65,64.525 70.666,64.525 ccw(c70.666,64.671) 70.812,64.671 70.812,64.924 cw(c70.959,64.924) 70.959,65.07 70.991,65.07 cw(c70.991,64.924) 71.138,64.924 71.138,64.525 71.138,64.126 ccw(c71.284,64.126) 71.284,63.98 71.316,63.98 ccw(c71.316,64.126) 71.463,64.126 71.463,64.525 71.463,64.924 cw(c71.609,64.924) 71.609,65.07 71.641,65.07 cw(c71.641,64.924) 71.788,64.924 71.788,64.525 71.788,64.126 ccw(c71.934,64.126) 71.934,63.98 71.966,63.98 ccw(c71.966,64.126) 72.113,64.126 72.113,64.525 72.113,64.924 cw(c72.259,64.924) 72.259,65.07 72.291,65.07 cw(c72.291,64.924) 72.438,64.924 72.438,64.525 72.438,64.126 ccw(c72.584,64.126) 72.584,63.98 72.616,63.98 ccw(c72.616,64.126) 72.763,64.126 72.763,64.379 cw(c72.909,64.379) 72.909,64.525 72.941,64.525 cw(c72.941,64.379) 73.088,64.379 73.088,64.126 ccw(c73.234,64.126) 73.234,63.98 73.266,63.98 ccw(c73.266,64.126) 73.413,64.126 73.413,64.379 cw(c73.559,64.379) 73.559,64.525 74.45,64.525 76.75,64.525 cw(c76.75,64.463) 76.812,64.463 76.812,64.071 ccw(c76.959,64.071) 76.959,63.925 76.991,63.925 ccw(c76.991,64.071) 77.137,64.071 77.137,64.525 77.137,64.979 cw(c77.284,64.979) 77.284,65.125 77.316,65.125 cw(c77.316,64.979) 77.462,64.979 77.462,64.525 77.462,64.071 ccw(c77.609,64.071) 77.609,63.925 77.641,63.925 ccw(c77.641,64.071) 77.787,64.071 77.787,64.525 77.787,64.979 cw(c77.934,64.979) 77.934,65.125 77.966,65.125 cw(c77.966,64.979) 78.112,64.979 78.112,64.525 78.112,64.071 ccw(c78.259,64.071) 78.259,63.925 78.291,63.925 ccw(c78.291,64.071) 78.437,64.071 78.437,64.525 78.437,64.979 cw(c78.584,64.979) 78.584,65.125 78.616,65.125 cw(c78.616,64.979) 78.762,64.979 78.762,64.525 78.762,64.071 ccw(c78.909,64.071) 78.909,63.925 78.941,63.925 ccw(c78.941,64.071) 79.087,64.071 79.087,64.525 79.087,64.979 cw(c79.234,64.979) 79.234,65.125 79.266,65.125 cw(c79.266,64.979) 79.412,64.979 79.412,64.525 79.412,64.071 ccw(c79.559,64.071) 79.559,63.925 79.591,63.925 ccw(c79.591,64.071) 79.737,64.071 79.737,64.525 79.737,64.979 cw(c79.884,64.979) 79.884,65.125 79.916,65.125 cw(c79.916,64.979) 80.062,64.979 80.062,64.525 80.062,64.071 ccw(c80.209,64.071) 80.209,63.925 80.241,63.925 ccw(c80.241,64.071) 80.387,64.071 80.387,64.525 80.387,64.979 cw(c80.534,64.979) 80.534,65.125 80.566,65.125 cw(c80.566,64.979) 80.712,64.979 80.712,64.525 80.712,64.071 ccw(c80.859,64.071) 80.859,63.925 80.891,63.925 ccw(c80.891,64.071) 81.037,64.071 81.037,64.525 81.037,64.979 cw(c81.184,64.979) 81.184,65.125 81.216,65.125 cw(c81.216,64.979) 81.362,64.979 81.362,64.525 81.362,64.071 ccw(c81.509,64.071) 81.509,63.925 81.541,63.925 ccw(c81.541,64.071) 81.687,64.071 81.687,64.525 81.687,64.979 cw(c81.834,64.979) 81.834,65.125 81.866,65.125 cw(c81.866,64.979) 82.012,64.979 82.012,64.525 82.012,64.071 ccw(c82.159,64.071) 82.159,63.925 82.191,63.925 ccw(c82.191,64.071) 82.337,64.071 82.337,64.525 82.337,64.979 cw(c82.484,64.979) 82.484,65.125 82.516,65.125 cw(c82.516,64.979) 82.662,64.979 82.662,64.525 82.662,64.071 ccw(c82.809,64.071) 82.809,63.925 82.841,63.925 ccw(c82.841,64.071) 82.987,64.071 82.987,64.379 cw(c83.134,64.379) 83.134,64.525 83.15,64.525 v1(83.675,64.525)
  Bottom Layer w0.125: v1(41.75,64.725) J33.5@41.75,66.8
CSI1_DAT16: J33.6 U1.AC16 | length 127.4
  Top Layer w0.125: v1(42.25,67.75) 42.25,68.725 43.075,69.55 52.025,69.55 53.663,67.912 53.663,66.154 56.417,63.4 59.75,63.4 v1(60.35,62.8) ; U1.AC16@77.5,18.5 77.925,18.075 77.925,17.5 v1(78.15,17.275)
  Layer 8 w0.125: v1(92.8,60.475) 92.05,59.725 92.05,54.35 92.5,53.9 92.5,48.175 96.89,43.785 96.89,19.769 92.971,15.85 v1(92.825,15.85)
  Layer 10 w0.125: v1(60.35,62.8) 60.95,62.8 60.966,62.8 ccw(c60.966,62.946) 61.112,62.946 61.112,63.095 cw(c61.259,63.095) 61.259,63.241 61.291,63.241 cw(c61.291,63.095) 61.437,63.095 61.437,62.8 61.437,62.505 ccw(c61.584,62.505) 61.584,62.359 61.616,62.359 ccw(c61.616,62.505) 61.763,62.505 61.763,62.654 cw(c61.909,62.654) 61.909,62.8 63.8,62.8 63.85,62.8 66.363,60.287 82.721,60.287 83.95,61.517 83.95,62.025 85.2,63.275 90,63.275 v1(92.8,60.475) ; v1(78.15,17.275) 78.15,16.925 78.5,16.575 92.1,16.575 v1(92.825,15.85)
  Bottom Layer w0.125: J33.6@42.25,66.8 v1(42.25,67.75)
CSI1_DAT17: J33.7 U1.AC19 | length 127.4
  Top Layer w0.125: v1(42.75,68.375) 42.75,68.8 43.25,69.3 51.9,69.3 52.65,68.55 52.65,66.483 56.5,62.633 v1(56.5,62.45) ; v1(82.75,19.3) 82.75,19.225 82.775,19.225 U1.AC19@83.5,18.5
  Layer 8 w0.125: v1(92.975,55.825) 93.65,55.15 93.65,49.65 93.975,49.325 94.775,49.325 96.725,47.375 96.725,44.4 97.15,43.975 97.15,18.8 v1(95.875,17.525)
  Layer 10 w0.125: v1(56.5,62.45) 57.15,61.8 57.6,61.8 57.616,61.8 ccw(c57.616,61.946) 57.762,61.946 57.762,62.048 cw(c57.909,62.048) 57.909,62.194 57.941,62.194 cw(c57.941,62.048) 58.087,62.048 58.087,61.8 58.087,61.552 ccw(c58.234,61.552) 58.234,61.406 58.266,61.406 ccw(c58.266,61.552) 58.412,61.552 58.412,61.8 58.412,62.048 cw(c58.559,62.048) 58.559,62.194 58.591,62.194 cw(c58.591,62.048) 58.737,62.048 58.737,61.8 58.737,61.552 ccw(c58.884,61.552) 58.884,61.406 58.916,61.406 ccw(c58.916,61.552) 59.063,61.552 59.063,61.8 59.063,62.048 cw(c59.209,62.048) 59.209,62.194 59.241,62.194 cw(c59.241,62.048) 59.388,62.048 59.388,61.8 59.388,61.552 ccw(c59.534,61.552) 59.534,61.406 59.566,61.406 ccw(c59.566,61.552) 59.713,61.552 59.713,61.654 cw(c59.859,61.654) 59.859,61.8 61.15,61.8 62.45,60.5 62.972,59.978 ccw(c63.075,60.081) 63.179,59.978 63.284,60.083 cw(c63.387,59.98) 63.491,60.083 63.514,60.06 cw(c63.41,59.957) 63.514,59.853 63.305,59.645 63.097,59.436 ccw(c63.2,59.333) 63.097,59.229 63.12,59.206 ccw(c63.223,59.31) 63.327,59.206 63.432,59.311 cw(c63.535,59.208) 63.639,59.311 63.65,59.3 64.275,58.675 64.625,58.675 68.092,58.675 69.429,60.013 82.799,60.013 84.2,61.413 84.2,61.825 85.4,63.025 89.45,63.025 93.225,59.25 93.225,56.075 v1(92.975,55.825) ; v1(82.75,19.3) 83.475,18.575 85.875,18.575 86.65,19.35 94.05,19.35 v1(95.875,17.525)
  Bottom Layer w0.125: J33.7@42.75,66.8 v1(42.75,68.375)
CSI1_DAT18: J33.8 U1.AA14 | length 128.5
  Top Layer w0.125: U1.AA14@73.5,22.5 v1(74.25,23.25)
  Layer 5 w0.125: v1(45.7,31.1) 46.175,30.625 46.175,28.475 47.55,27.1 v1(47.55,21)
  Layer 10 w0.125: v1(47.55,21) 47.4,20.85 47.4,20.45 47.763,20.087 48.204,20.087 53.284,20.087 53.609,20.413 55.224,20.413 55.613,20.024 55.613,19.804 55.954,19.462 65.337,19.462 65.663,19.787 66.025,20.15 cw(c66.128,20.046) 66.232,20.15 66.587,19.794 ccw(c66.691,19.898) 66.794,19.794 66.817,19.817 ccw(c66.714,19.921) 66.817,20.024 66.358,20.483 66.029,20.812 cw(c66.133,20.916) 66.029,21.019 66.052,21.042 cw(c66.155,20.939) 66.259,21.042 66.588,20.713 67.047,20.254 ccw(c67.15,20.357) 67.254,20.254 67.277,20.277 ccw(c67.173,20.38) 67.277,20.484 66.818,20.943 66.489,21.272 cw(c66.592,21.375) 66.489,21.479 66.512,21.502 cw(c66.615,21.398) 66.719,21.502 67.048,21.173 67.507,20.714 ccw(c67.61,20.817) 67.713,20.714 67.736,20.737 ccw(c67.633,20.84) 67.736,20.943 67.277,21.402 66.948,21.731 cw(c67.052,21.835) 66.948,21.938 66.971,21.961 cw(c67.075,21.858) 67.178,21.961 67.507,21.632 67.966,21.173 ccw(c68.07,21.277) 68.173,21.173 68.196,21.196 ccw(c68.093,21.3) 68.196,21.403 67.737,21.862 67.408,22.191 cw(c67.511,22.294) 67.408,22.398 67.431,22.421 cw(c67.534,22.317) 67.638,22.421 67.967,22.092 68.426,21.633 ccw(c68.529,21.736) 68.633,21.633 68.656,21.656 ccw(c68.552,21.759) 68.656,21.863 68.197,22.322 67.868,22.651 cw(c67.971,22.754) 67.868,22.857 67.891,22.88 cw(c67.994,22.777) 68.097,22.88 68.426,22.551 68.885,22.092 ccw(c68.989,22.196) 69.092,22.092 69.115,22.115 ccw(c69.012,22.219) 69.115,22.322 68.656,22.781 68.327,23.11 cw(c68.431,23.214) 68.327,23.317 68.35,23.34 cw(c68.454,23.237) 68.557,23.34 68.886,23.011 69.345,22.552 ccw(c69.448,22.655) 69.552,22.552 69.575,22.575 ccw(c69.471,22.678) 69.575,22.782 69.116,23.241 68.787,23.57 cw(c68.89,23.673) 68.787,23.777 68.81,23.8 cw(c68.913,23.696) 69.017,23.8 69.346,23.471 69.805,23.012 ccw(c69.908,23.115) 70.011,23.012 70.034,23.035 ccw(c69.931,23.138) 70.034,23.242 69.575,23.7 69.246,24.03 cw(c69.35,24.133) 69.246,24.236 69.269,24.259 cw(c69.373,24.156) 69.476,24.259 69.805,23.93 70.264,23.471 ccw(c70.368,23.575) 70.471,23.471 70.494,23.494 ccw(c70.391,23.598) 70.494,23.701 70.139,24.057 cw(c70.242,24.16) 70.139,24.264 70.15,24.275 70.375,24.5 70.7,24.5 70.716,24.5 ccw(c70.716,24.646) 70.862,24.646 70.862,24.892 cw(c71.009,24.892) 71.009,25.038 71.041,25.038 cw(c71.041,24.892) 71.188,24.892 71.188,24.646 ccw(c71.334,24.646) 71.334,24.5 72.45,24.5 73,24.5 v1(74.25,23.25)
  Layer 3 w0.125: v1(43.25,65.875) 43.25,55.575 43.025,55.35 42.475,55.35 42.3,55.525 42.3,59.2 42.8,59.7 42.8,63.45 42.5,63.75 41.925,63.75 41.7,63.525 41.7,61.525 42.3,60.925 42.3,60.125 42.012,59.837 42.012,54.513 42.5,54.025 42.5,50.9 42.675,50.725 43.025,50.725 43.175,50.875 43.175,52.125 43.475,52.425 43.95,52.425 44.175,52.2 44.175,40.125 43.4,39.35 43.4,35.7 42.05,34.35 41.95,34.25 41.95,32.85 42.05,32.75 43.7,31.1 v1(45.7,31.1)
  Bottom Layer w0.125: v1(43.25,65.875) J33.8@43.25,66.8
CSI1_DAT19: J33.9 U1.AD17 | length 127.7
  Top Layer w0.125: U1.AD17@79.5,16.5 v1(80.125,17.125)
  Layer 8 w0.125: v1(44.25,33.4) 44.338,33.488 47.446,33.488 49.35,31.583 49.35,30.243 51.038,28.555 51.038,26.113 v1(50.675,25.75) ; v1(76.475,19.175) 76.75,19.175 76.925,19 78.725,19 79.55,18.175 79.55,17.7 v1(80.125,17.125)
  Layer 5 w0.125: v1(50.675,25.75) 50.675,25.692 53.821,22.545 53.821,20.8 54.537,20.084 54.537,19.579 54.9,19.217 v1(54.9,19.05)
  Layer 10 w0.125: v1(54.9,19.05) 54.988,18.962 56.996,18.962 57.221,18.737 76.037,18.737 v1(76.475,19.175)
  Layer 3 w0.125: v1(43.75,67.75) 43.75,67.275 43.625,67.15 37.725,67.15 37.625,67.05 37.625,64.65 37.8,64.475 38.425,64.475 38.6,64.65 38.6,65.183 39.704,66.288 43.421,66.288 45.163,64.546 45.163,64.204 44.833,63.875 43.975,63.875 43.75,63.65 43.75,63.35 43.75,63.334 ccw(c43.896,63.334) 43.896,63.188 44.92,63.188 cw(c44.92,63.041) 45.067,63.041 45.067,63.009 cw(c44.92,63.009) 44.92,62.863 43.75,62.863 43.646,62.863 ccw(c43.646,62.716) 43.5,62.716 43.5,62.684 ccw(c43.646,62.684) 43.646,62.538 43.75,62.538 44.945,62.538 cw(c44.945,62.391) 45.092,62.391 45.092,62.359 cw(c44.945,62.359) 44.945,62.212 43.75,62.212 43.646,62.212 ccw(c43.646,62.066) 43.5,62.066 43.5,62.034 ccw(c43.646,62.034) 43.646,61.887 43.75,61.887 44.945,61.887 cw(c44.945,61.741) 45.092,61.741 45.092,61.709 cw(c44.945,61.709) 44.945,61.562 43.75,61.562 43.646,61.562 ccw(c43.646,61.416) 43.5,61.416 43.5,61.384 ccw(c43.646,61.384) 43.646,61.237 43.75,61.237 44.945,61.237 cw(c44.945,61.091) 45.092,61.091 45.092,61.059 cw(c44.945,61.059) 44.945,60.912 43.75,60.912 43.646,60.912 ccw(c43.646,60.766) 43.5,60.766 43.5,60.734 ccw(c43.646,60.734) 43.646,60.587 43.75,60.587 44.945,60.587 cw(c44.945,60.441) 45.092,60.441 45.092,60.409 cw(c44.945,60.409) 44.945,60.262 43.75,60.262 43.646,60.262 ccw(c43.646,60.116) 43.5,60.116 43.5,60.084 ccw(c43.646,60.084) 43.646,59.937 43.75,59.937 44.945,59.937 cw(c44.945,59.791) 45.092,59.791 45.092,59.759 cw(c44.945,59.759) 44.945,59.612 43.896,59.612 ccw(c43.896,59.466) 43.75,59.466 43.75,58.95 43.75,54.95 44.525,54.175 44.525,51.25 44.525,50.309 ccw(c44.671,50.309) 44.671,50.163 44.835,50.163 cw(c44.835,50.016) 44.982,50.016 44.982,49.984 cw(c44.835,49.984) 44.835,49.838 44.671,49.838 ccw(c44.671,49.691) 44.525,49.691 44.525,49.512 44.525,49.35 44.525,45.25 45,44.775 45,44.6 45,44.459 cw(c44.854,44.459) 44.854,44.313 44.571,44.313 ccw(c44.571,44.166) 44.425,44.166 44.425,44.134 ccw(c44.571,44.134) 44.571,43.988 44.854,43.988 cw(c44.854,43.841) 45,43.841 45,43.809 cw(c44.854,43.809) 44.854,43.663 44.571,43.663 ccw(c44.571,43.516) 44.425,43.516 44.425,43.484 ccw(c44.571,43.484) 44.571,43.338 44.854,43.338 cw(c44.854,43.191) 45,43.191 45,43.159 cw(c44.854,43.159) 44.854,43.013 44.571,43.013 ccw(c44.571,42.866) 44.425,42.866 44.425,42.834 ccw(c44.571,42.834) 44.571,42.688 44.854,42.688 cw(c44.854,42.541) 45,42.541 45,42.509 cw(c44.854,42.509) 44.854,42.363 44.571,42.363 ccw(c44.571,42.216) 44.425,42.216 44.425,42.184 ccw(c44.571,42.184) 44.571,42.038 44.854,42.038 cw(c44.854,41.891) 45,41.891 45,41.859 cw(c44.854,41.859) 44.854,41.712 44.571,41.712 ccw(c44.571,41.566) 44.425,41.566 44.425,41.534 ccw(c44.571,41.534) 44.571,41.387 44.854,41.387 cw(c44.854,41.241) 45,41.241 45,41.209 cw(c44.854,41.209) 44.854,41.062 44.571,41.062 ccw(c44.571,40.916) 44.425,40.916 44.425,40.884 ccw(c44.571,40.884) 44.571,40.737 44.854,40.737 cw(c44.854,40.591) 45,40.591 45,40.575 45,40.275 43.675,38.95 43.675,35.621 42.2,34.146 42.2,33.238 42.638,32.8 43.65,32.8 v1(44.25,33.4)
  Bottom Layer w0.125: J33.9@43.75,66.8 v1(43.75,67.75)
CSI1_GPIO: J33.15 U1.W18 | length 93.1
  Top Layer w0.125: v1@80.65,26.475 80.675,26.5 v1(80.7,26.5) U1.W18@81.5,26.5
  Layer 8 w0.125: v1(46.75,67.75) 45.675,66.675 45.675,65.375 46.675,64.375 48.625,64.375 51.225,61.775 53.425,61.775 53.725,62.075 53.725,62.525 53.35,62.9 52.525,62.9 51.675,63.75 51.675,64.446 51.854,64.625 53.979,64.625 54.816,63.787 58.737,63.787 61.35,66.4 68.55,66.4 69.625,65.325 71.925,65.325 72.312,64.938 72.679,64.938 74.092,63.524 82.679,63.524 84.1,62.104 84.1,56.433 84.763,55.771 84.763,53.937 v1(86.45,52.25)
  Layer 3 w0.125: v1(80.7,26.5) 81.183,26.5 83.863,29.179 83.863,34.367 84.575,35.079 84.575,40.075 84.425,40.225 84.425,47.875 86.15,49.6 86.15,51.95 v1(86.45,52.25)
  Bottom Layer w0.125: J33.15@46.75,66.8 v1(46.75,67.75)
CSI1_HSYNC: J33.13 U2.3 | length 104.4
  Layer 8 w0.125: v1(64.05,17.4) 65.1,18.45 70.8,18.45 73.075,20.725 73.075,23.546 73.779,24.25 74.95,24.25 75.475,23.725 75.475,20.825 77,19.3 78.925,19.3 v1(80.5,20.875)
  Layer 5 w0.125: v1(43.175,20.625) 43.175,21.7 44.85,23.375 44.85,35.65 v1(44.6,35.9)
  Layer 10 w0.125: v1(43.175,20.625) 43.175,19.2 44.55,17.825 46.975,17.825 47.4,17.4 47.4,17.025 47.95,16.475 48.992,16.475 51.617,13.85 57.475,13.85 59.825,16.2 62.35,16.2 63.55,17.4 v1(64.05,17.4)
  Layer 3 w0.125: v1(44.6,35.9) 46.1,35.9 47.087,36.887 47.087,39.371 47.413,39.696 47.413,51.45 47.913,51.95 47.913,53.826 47.413,54.326 47.413,55.387 46.75,56.05 46.75,66.75 v1(45.75,67.75)
  Bottom Layer w0.125: J33.13@45.75,66.8 v1(45.75,67.75) ; U2.3@79.6,20.85 v1@80.475,20.85
CSI1_HSYNC/BTCFG2_3: U1.V18 U2.4 | length 11.4
  Top Layer w0.125: v1(81.2,27.3) 81.2,27.375 81.5,27.675 U1.V18@81.5,28.5
  Layer 8 w0.125: v1(76.375,20.875) 77.25,20.875 79.875,23.5 79.875,25.375 80.425,25.925 80.708,25.925 81.2,26.417 v1(81.2,27.3)
  Bottom Layer w0.125: v1@76.4,20.85 U2.4@77.4,20.85
CSI1_I2C_SCL: J33.18 R207.2 | length 31.2
  Bottom Layer w0.125: R207.2@29.3,60.47 30.27,59.5 36.85,59.5 40.9,55.45 46.2,55.45 48.25,57.5 J33.18@48.25,66.8
CSI1_I2C_SDA: J33.19 R208.2 | length 27.9
  Bottom Layer w0.125: R208.2@32.03,60.25 32.43,59.85 38.6,59.85 39.7,60.95 39.7,63.6 38.9,64.4 38.9,68.275 40,69.375 47.175,69.375 48.75,67.8 J33.19@48.75,66.8
CSI1_MCLK: J33.11 R2.2 | length 17.6
  Layer 8 w0.125: v1(44.75,64.375) 45.612,63.513 45.971,63.513 47.633,61.85 47.633,59.267 49.4,57.5 49.4,53.6 v1(50.625,52.375)
  Bottom Layer w0.125: v1(44.75,64.375) J33.11@44.75,66.8 ; R2.2@50.105,52.375 v1(50.625,52.375)
CSI1_PIXCLK: J33.12 U1.AD15 | length 92.6
  Top Layer w0.125: U1.AD15@75.5,16.5 v1(76.125,17.125)
  Layer 5 w0.125: v1(40.275,32.4) 40.338,32.463 41.428,32.463 42.619,33.653 v1(42.619,33.677)
  Layer 10 w0.125: v1(40.275,32.4) 39.825,31.95 39.825,31.425 40.658,30.592 40.658,29.305 42.45,27.514 42.45,25.2 44.86,22.789 44.86,20.76 44.65,20.55 44.65,18.689 45.014,18.325 49.525,18.325 49.837,18.013 49.837,16.613 50.461,15.99 57.59,15.99 59.8,18.2 75.05,18.2 v1(76.125,17.125)
  Layer 3 w0.125: v1(42.619,33.677) 42.621,33.675 43.483,33.675 44.05,34.242 44.05,36.7 45.413,38.063 45.413,62.904 45.387,62.929 45.387,63.271 45.413,63.296 45.413,65.637 45.25,65.8 v1(45.25,68.375)
  Bottom Layer w0.125: J33.12@45.25,66.8 v1(45.25,68.375)
CSI1_RESET_N: J33.16 U1.Y20 | length 103
  Top Layer w0.125: U1.Y20@85.5,24.5 86.3,23.7 94.525,23.7 v1(95.425,24.6)
  Layer 8 w0.125: v1(47.25,68.375) 47.925,68.375 49.05,67.25 51.4,67.25 53.713,69.563 66.646,69.563 67.975,68.233 67.975,67.55 68.3,67.225 74.475,67.225 75.75,65.95 v1(76.95,65.95)
  Layer 5 w0.125: v1(95.425,24.6) 95.887,25.062 95.887,31.059 95.25,31.696 95.25,54.15 95.6,54.5 v1(95.6,55.975)
  Layer 10 w0.125: v1(76.95,65.95) 90.725,65.95 95.6,61.075 v1(95.6,55.975)
  Bottom Layer w0.125: J33.16@47.25,66.8 v1(47.25,68.375)
CSI1_VSYNC: J33.14 U4.3 | length 114.7
  Layer 8 w0.125: v1(46.2,65.875) 47.725,65.875 48.85,67 51.7,67 54.013,69.313 65.896,69.313 67.025,68.183 67.025,67.25 67.375,66.9 74.325,66.9 75.775,65.45 v1(77.625,65.45)
  Layer 5 w0.125: v1(77.625,65.45) 89.4,65.45 96.025,58.825 96.025,54.525 95.5,54 95.5,31.8 96.95,30.35 96.95,20.413 v1(96.219,19.681)
  Layer 10 w0.125: v1(80.5,17.875) 80.725,17.875 82.563,19.713 96.187,19.713 v1(96.219,19.681)
  Bottom Layer w0.125: v1@46.25,65.875 J33.14@46.25,66.8 ; U4.3@79.6,17.85 v1@80.475,17.85
CSI1_VSYNC/BTCFG2_4: U1.V22 U4.4 | length 26.9
  Top Layer w0.125: U1.V22@89.5,28.5 90.35,29.35 v1(90.35,30.8)
  Layer 8 w0.125: v1(78.5,17.875) 78.792,17.875 80.317,16.35 83.85,16.35 89.475,21.975 89.475,29.925 v1(90.35,30.8)
  Bottom Layer w0.125: U4.4@77.425,17.875 v1(78.5,17.875)
CSI_CLK0_N: P20.8 U1.B11 | length 13.5
  Top Layer w0.104: P20.8@62.7,66.775 62.7,67.506 63.33,68.136 63.67,68.136 63.911,67.895 63.911,65.961 v1(62.85,64.9) ; v1(67,61.125) U1.B11@67.5,60.5
  Layer 10 w0.093: v1(62.85,64.9) 62.85,64.854 63.05,64.654 63.05,64.4 63.3,64.15 65.45,64.15 66.175,63.425 66.175,61.601 66.426,61.35 66.5,61.35 66.775,61.35 v1(67,61.125)
CSI_CLK0_P: P20.7 U1.A11 | length 13.5
  Top Layer w0.104: v1(63.5,64.9) 63.5,65.189 64.166,65.855 64.166,68.001 63.776,68.391 63.6,68.391 63.5,68.491 63.5,70.225 P20.7@63.7,70.425 ; v1(67,61.875) U1.A11@67.5,62.5
  Layer 10 w0.093: v1(63.5,64.9) 63.35,64.75 63.35,64.55 63.45,64.45 65.6,64.45 66.5,63.55 66.5,61.7 66.55,61.65 66.775,61.65 v1(67,61.875)
CSI_D0_N: P20.14 U1.G12 | length 33.3
  Top Layer w0.104: P20.14@56.7,66.775 56.7,68.3 56.55,68.45 56.061,68.45 55.85,68.239 55.85,65.6 56.2,65.25 58.205,65.25 58.9,64.555 60.945,64.555 61.861,63.639 68.011,63.639 68.621,63.029 68.621,52 68.621,51.977 68.621,51.8 ccw(c68.766,51.8) 68.766,51.655 69.076,51.655 cw(c69.076,51.51) 69.221,51.51 69.221,51.478 cw(c69.076,51.478) 69.076,51.333 68.766,51.333 ccw(c68.766,51.188) 68.621,51.188 68.621,51.011 68.621,50.85 68.621,50.629 68.75,50.5 U1.G12@69.5,50.5
CSI_D0_P: P20.13 U1.G11 | length 33.2
  Top Layer w0.104: P20.13@57.7,70.425 57.639,70.364 57.639,69.739 56.605,68.705 55.955,68.705 55.595,68.345 55.595,65.494 56.094,64.995 58.099,64.995 58.794,64.3 60.839,64.3 61.755,63.384 67.905,63.384 68.366,62.923 68.366,50.629 68.237,50.5 U1.G11@67.5,50.5
CSI_D1_N: P20.11 U1.A13 | length 21.6
  Top Layer w0.104: P20.11@59.7,70.425 59.9,70.225 59.9,68.5 59.495,68.095 59.495,65.494 59.989,65 61.389,65 62.439,63.95 71.35,63.95 72.2,63.1 72.2,61.9 71.928,61.628 71.7,61.628 71.5,61.827 U1.A13@71.5,62.5
CSI_D1_P: P20.10 U1.B13 | length 21.7
  Top Layer w0.104: P20.10@60.7,66.775 60.639,66.836 60.639,68.011 60.45,68.2 59.961,68.2 59.75,67.989 59.75,65.6 60.095,65.255 61.495,65.255 62.545,64.205 71.456,64.205 72.455,63.206 72.455,61.794 72.033,61.373 71.7,61.373 71.5,61.173 U1.B13@71.5,60.5
CSI_I2C_SCL: P20.3 R112.2 | length 58.8
  Top Layer w0.125: v1(65.65,65.2) 65.65,66 66,66.35 66,68.275 66.625,68.9 67.15,68.9 67.7,69.45 P20.3@67.7,70.425
  Layer 8 w0.125: v1(50.2,60.975) 50.575,61.35 57.317,61.35 59.867,63.9 64.2,63.9 65.5,65.2 v1(65.65,65.2)
  Layer 3 w0.125: v1(46.25,32.5) 48.875,32.5 51.725,35.35 51.725,43.329 51.7,43.354 51.7,44.15 51.1,44.75 50.575,44.75 50.25,45.075 50.25,46.75 51.25,47.75 51.25,49.125 49.75,50.625 49.75,60.5 v1@50.225,60.975
  Bottom Layer w0.125: v1(46.25,32.5) R112.2@47.02,32.5
CSI_I2C_SDA: P20.2 R113.2 | length 28.8
  Top Layer w0.2: v1(68.35,64.8) 68.7,65.15 P20.2@68.7,66.775
  Bottom Layer w0.125: R113.2@51.5,50.98 52.9,52.38 52.9,59.358 55.225,61.683 56.95,61.683 57.617,62.35 65.9,62.35 v1(68.35,64.8)
CSI_RESET_N: P20.5 U1.E24 | length 41.6
  Top Layer w0.125: v1(92.875,55.125) U1.E24@93.5,54.5
  Top Layer w0.2: v1(65.7,68.9) P20.5@65.7,70.425
  Layer 10 w0.125: v1(65.7,68.9) 68.4,68.9 68.95,68.35 68.95,64.45 69.875,63.525 90.5,63.525 93.475,60.55 93.475,55.725 v1(92.875,55.125)
DISP0_CLK: J21.27 U1.V9 | length 45.9
  Top Layer w0.125: v1(61.25,30.45) 62.2,29.5 62.5,29.5 U1.V9@63.5,28.5
  Layer 8 w0.125: v1(61.25,30.45) 62.05,31.25 62.05,49.293 61.2,50.143 61.2,59.265 62.535,60.6 63.35,60.6 64.125,61.375 v1(64.125,61.875)
  Layer 3 w0.125: v1(64.125,61.875) 64.271,61.875 67.45,65.054 67.45,68.075 v1(67.5,68.125)
  Bottom Layer w0.125: J21.27@67.5,66.8 v1(67.5,68.125)
DISP0_CONTRAST: J21.32 U1.AD8 | length 77.3
  Top Layer w0.125: v1(60.875,17.125) U1.AD8@61.5,16.5
  Layer 8 w0.125: v1(53.2,62.2) 52.5,62.2 51.425,63.275 51.425,64.55 51.75,64.875 54.082,64.875 54.92,64.037 58.632,64.037 61.245,66.65 69.225,66.65 v1(70,65.875)
  Layer 5 w0.125: v1(53.2,62.2) 55.05,60.35 55.05,59.054 60,54.104 60,49.868 62.237,47.63 62.237,30.761 63.25,29.749 63.25,26.25 63.125,26.125 63.125,19.25 63.25,19.125 63.25,17.5 62.875,17.125 v1(60.875,17.125)
  Bottom Layer w0.125: v1(70,65.875) J21.32@70,66.8
DISP0_DAT0: J21.2 U1.AC8 | length 63.2
  Top Layer w0.125: v1(60.875,17.75) U1.AC8@61.5,18.5
  Layer 5 w0.125: v1(51.775,68.375) 51.775,67.35 51.625,67.2 51.625,63.979 52.4,63.204 52.4,59.788 54.526,57.663 54.782,57.663 58.325,54.119 58.325,50.836 60.5,48.661 60.5,45.933 60.913,45.52 60.913,43.768 60.687,43.543 60.687,35.896 61.737,34.846 61.737,30.554 62.75,29.542 62.75,26.625 62.625,26.5 62.625,19.5 v1(60.875,17.75)
  Bottom Layer w0.125: v1(51.775,68.375) 51.775,68 54.3,65.475 54.675,65.475 55,65.8 J21.2@55,66.8
DISP0_DAT1: J21.3 U1.AC9 | length 61
  Top Layer w0.125: v1(62.75,17.75) U1.AC9@63.5,18.5
  Layer 5 w0.125: v1(52.225,66.925) 51.9,66.6 51.9,66.025 52.6,65.325 52.6,63.357 52.65,63.307 52.65,59.892 54.617,57.925 55.825,57.925 59.75,54 59.75,49.764 61.987,47.527 61.987,30.658 63,29.645 63,26.5 62.875,26.375 62.875,19.375 62.75,19.25 v1(62.75,17.75)
  Bottom Layer w0.125: v1(52.225,66.925) 53.925,65.225 54.846,65.225 55.5,65.879 J21.3@55.5,66.8
DISP0_DAT2: J21.4 U1.AD9 | length 62.7
  Top Layer w0.125: v1(62.75,15.875) U1.AD9@63.5,16.5
  Layer 5 w0.125: v1(52.45,66.1) 55.437,63.113 55.437,59.022 57.824,56.636 59.848,56.636 60.987,55.496 60.987,49.234 62.487,47.734 62.487,30.865 63.5,29.852 63.5,29.146 63.5,26.125 63.375,26 63.375,19.5 63.6,19.275 63.6,17.475 62.75,16.625 v1(62.75,15.875)
  Bottom Layer w0.125: v1(52.45,66.1) 53.575,64.975 54.95,64.975 56,66.025 J21.4@56,66.8
DISP0_DAT3: J21.5 U1.AB8 | length 60.9
  Top Layer w0.125: v1(60.875,21.125) U1.AB8@61.5,20.5
  Layer 5 w0.125: v1(50.375,66.525) 50.175,66.325 50.175,65.475 50.931,64.719 50.931,63.944 51.9,62.975 51.9,59.581 54.318,57.163 54.574,57.163 57.825,53.912 57.825,50.629 60,48.454 60,45.979 60,45.726 60.413,45.313 60.413,43.976 60,43.563 60,30.563 62.25,28.313 62.25,26.875 62.125,26.75 62.125,21.75 61.5,21.125 v1(60.875,21.125)
  Bottom Layer w0.125: v1(50.375,66.525) 51.25,66.525 53.05,64.725 55.125,64.725 56.5,66.1 J21.5@56.5,66.8
DISP0_DAT4: J21.6 U1.AA9 | length 53.9
  Top Layer w0.125: U1.AA9@63.5,22.5 v1(64.125,23.125)
  Layer 5 w0.125: v1(57.2,68.25) 57.2,67.075 55.937,65.812 55.937,59.229 56.492,58.675 59.096,58.675 61.487,56.284 61.487,51.611 62.406,50.692 62.433,50.692 62.987,50.138 62.987,31.072 65,29.06 65,26.25 63.875,25.125 63.875,23.375 v1(64.125,23.125)
  Bottom Layer w0.125: J21.6@57,66.8 57,68.05 v1(57.2,68.25)
DISP0_DAT5: J21.7 U1.AD7 | length 65.4
  Top Layer w0.125: U1.AD7@59.5,16.5 v1(60.5,16.625)
  Layer 5 w0.125: v1(50.6,65.725) 51.325,65 51.325,63.925 52.15,63.1 52.15,59.685 54.422,57.413 54.678,57.413 58.075,54.015 58.075,50.732 60.25,48.557 60.25,45.875 60.25,45.829 60.663,45.417 60.663,43.872 60.25,43.46 60.25,30.667 62.5,28.417 62.5,26.75 62.375,26.625 62.375,19.875 60.25,17.75 60.25,16.875 v1(60.5,16.625)
  Bottom Layer w0.125: v1(50.6,65.725) 51.475,65.725 52.725,64.475 52.968,64.475 55.925,64.475 57.5,66.05 J21.7@57.5,66.8
DISP0_DAT6: J21.8 U1.AB7 | length 59.2
  Top Layer w0.125: U1.AB7@59.5,20.5 60.125,21.125 60.75,21.75 v1(61,21.75)
  Layer 5 w0.125: v1(50.525,63.775) 51.65,62.65 51.65,59.477 54.215,56.913 54.471,56.913 57.575,53.808 57.575,50.525 59.75,48.35 59.75,46.082 59.75,45.622 60.163,45.21 60.163,44.079 59.75,43.667 59.75,30.46 62,28.21 62,26.979 61.875,26.854 61.875,26.646 61.875,22.625 v1(61,21.75)
  Bottom Layer w0.125: v1(50.525,63.775) 50.775,63.525 52.3,63.525 53,64.225 53.071,64.225 56.325,64.225 58,65.9 J21.8@58,66.8
DISP0_DAT7: J21.9 U1.AC7 | length 60.9
  Top Layer w0.125: v1(56.5,20.5) 57.875,19.125 58.875,19.125 U1.AC7@59.5,18.5
  Layer 3 w0.125: v1(53.25,67.25) 53.25,64.275 52.713,63.738 52.713,52.287 53.837,51.163 53.837,49.159 55,47.996 55,45.261 54.413,44.673 54.413,27.641 55.2,26.854 55.2,21.8 v1(56.5,20.5)
  Bottom Layer w0.125: v1@53.125,67.4 53.05,67.475 53.05,68.175 53.6,68.725 57.825,68.725 58.5,68.05 J21.9@58.5,66.8
DISP0_DAT8: J21.10 U1.AA8 | length 57.4
  Top Layer w0.125: v1(60.875,23.125) U1.AA8@61.5,22.5
  Layer 5 w0.125: v1(50.5,63.125) 51.4,62.225 51.4,59.357 53.887,56.87 53.887,56.329 55.712,54.504 55.712,51.092 57.25,49.555 57.25,44.55 58.763,43.037 58.763,39.721 58.337,39.296 58.337,38.329 58.579,38.087 58.587,38.087 59.375,37.3 59.375,30.481 61.75,28.106 61.75,27.082 61.625,26.957 61.625,26.543 61.625,23.875 v1(60.875,23.125)
  Bottom Layer w0.125: v1(50.5,63.125) 52.325,63.125 53.175,63.975 58.111,63.975 59,64.864 59,65.875 J21.10@59,66.8
DISP0_DAT9: J21.11 U1.AB6 | length 54.6
  Top Layer w0.125: v1(56.875,21.125) U1.AB6@57.5,20.5
  Layer 3 w0.125: v1(53.225,63.4) 53.85,62.775 53.85,61.25 52.963,60.363 52.963,52.412 54.087,51.288 54.087,49.263 55.25,48.1 55.25,45.157 54.663,44.57 54.663,27.745 55.5,26.907 55.5,22.5 v1(56.875,21.125)
  Bottom Layer w0.125: v1(53.225,63.4) 53.55,63.725 58.214,63.725 59.5,65.011 J21.11@59.5,66.8
DISP0_DAT10: J21.12 U1.Y8 | length 61.9
  Top Layer w0.125: v1(60.875,25.125) U1.Y8@61.5,24.5
  Layer 5 w0.125: v1(50.25,68.375) 49.675,67.8 49.675,62.983 50.713,61.946 50.713,61.912 50.725,61.9 50.725,60.2 49.825,59.3 49.825,58.967 50.079,58.712 50.485,58.712 51.837,57.36 51.837,56.777 54.962,53.652 54.962,50.782 56.463,49.282 56.463,44.277 58.013,42.727 58.013,40.032 57.587,39.607 57.587,38.018 58.268,37.337 58.277,37.337 58.625,36.989 58.625,30.125 59.604,29.146 59.604,27.729 59.875,27.457 59.875,27.043 59.875,26.125 v1(60.875,25.125)
  Bottom Layer w0.125: v1@50.25,68.45 50.775,68.975 58.951,68.975 60,67.926 J21.12@60,66.8
DISP0_DAT11: J21.13 U1.Y7 | length 55.9
  Top Layer w0.125: v1(58.875,25.125) U1.Y7@59.5,24.5
  Layer 5 w0.125: v1(50.3,61.775) 49.3,60.775 49.3,59.454 49.3,58.785 50.322,57.763 50.728,57.763 51.337,57.153 51.337,56.57 53.337,54.57 53.337,51.126 54.501,49.963 55.074,49.963 55.963,49.074 55.963,40.996 56.663,40.296 56.663,38.236 58.061,36.837 58.07,36.837 58.125,36.782 58.125,28.5 59.375,27.25 59.375,25.625 v1(58.875,25.125)
  Bottom Layer w0.125: v1(50.3,61.775) 54.175,61.775 55.875,63.475 58.318,63.475 60.5,65.657 J21.13@60.5,66.8
DISP0_DAT12: J21.14 U1.AA7 | length 57.9
  Top Layer w0.125: U1.AA7@59.5,22.5 v1(60.875,23.875)
  Layer 5 w0.125: v1(50.2,60.275) 49.575,59.65 49.575,58.863 50.426,58.013 50.832,58.013 51.587,57.257 51.587,56.673 53.587,54.673 53.587,51.229 54.604,50.213 55.178,50.213 56.213,49.178 56.213,41.099 56.913,40.399 56.913,38.34 58.165,37.087 58.173,37.087 58.375,36.886 58.375,28.604 59.625,27.354 59.625,27.146 59.625,25.125 v1(60.875,23.875)
  Bottom Layer w0.125: v1(50.2,60.275) 53.11,60.275 56.06,63.225 58.421,63.225 61,65.804 J21.14@61,66.8
DISP0_DAT13: J21.15 U1.W8 | length 53
  Top Layer w0.125: v1(60.625,27.375) U1.W8@61.5,26.5
  Layer 5 w0.125: v1(50.25,59.125) 50.925,59.125 53.387,56.663 53.387,56.122 55.212,54.297 55.212,50.885 56.713,49.385 56.713,44.38 58.263,42.83 58.263,39.928 57.837,39.503 57.837,38.122 58.372,37.587 58.38,37.587 58.875,37.093 58.875,30.25 59.875,29.25 59.875,28.125 v1(60.625,27.375)
  Bottom Layer w0.125: v1(50.25,59.125) 52.313,59.125 56.163,62.975 58.525,62.975 61.5,65.95 J21.15@61.5,66.8
DISP0_DAT14: J21.16 U1.AC6 | length 62.1
  Top Layer w0.125: v1(56.125,19.875) 56.125,19.25 56.875,18.5 U1.AC6@57.5,18.5
  Layer 8 w0.125: v1@52.05,64.125 v1(52.1,64.125) 54.125,64.125 54.713,63.537 58.841,63.537 61.179,65.875 v1(62,65.875)
  Layer 3 w0.125: v1(52.1,64.125) 52.1,61.004 51.5,60.404 51.5,52.646 53.337,50.809 53.337,48.952 54.5,47.789 54.5,45.468 53.913,44.88 53.913,21.246 53.837,21.171 53.837,20.829 54.317,20.35 55.65,20.35 v1(56.125,19.875)
  Bottom Layer w0.125: v1(62,65.875) J21.16@62,66.8
DISP0_DAT15: J21.17 U1.W7 | length 47.7
  Top Layer w0.125: v1(58.875,27.125) U1.W7@59.5,26.5
  Layer 8 w0.125: v1(57.825,64.45) 57.825,65.475 60.4,68.05 v1(62.45,68.05)
  Layer 3 w0.125: v1(57.825,64.45) 57.825,60.925 57.375,60.475 57.375,51.25 56.5,50.375 56.5,44.146 58.063,42.584 58.063,29.312 58.875,28.5 v1(58.875,27.125)
  Bottom Layer w0.125: v1(62.45,68.05) 62.45,66.85 J21.17@62.5,66.8
DISP0_DAT16: J21.18 U1.V6 | length 47.8
  Top Layer w0.125: v1(56.875,29.125) U1.V6@57.5,28.5
  Layer 8 w0.125: v1(57.25,64.525) 57.25,65.254 60.434,68.437 61.871,68.437 61.983,68.55 v1(63,68.55)
  Layer 3 w0.125: v1(56.875,29.125) 57.8,30.05 57.8,39.55 56.5,40.85 56.5,43.793 56.25,44.043 56.25,50.357 55.663,50.945 55.663,62.938 v1(57.25,64.525)
  Bottom Layer w0.125: J21.18@63,66.8 v1(63,68.55)
DISP0_DAT17: J21.19 U1.AB5 | length 61.6
  Top Layer w0.125: v1(54.875,21.125) U1.AB5@55.5,20.5
  Layer 3 w0.125: v1(54.875,21.125) 54.875,26.825 54.163,27.537 54.163,44.777 54.75,45.364 54.75,47.893 53.587,49.055 53.587,50.913 51.75,52.75 51.75,60.3 52.375,60.925 52.375,63.775 52.925,64.325 52.925,66.725 52.775,66.875 52.775,67.498 52.952,67.675 53.55,67.675 53.937,67.288 63.238,67.288 v1@63.5,67.55
  Bottom Layer w0.125: J21.19@63.5,66.8 v1(63.5,67.725)
DISP0_DAT18: J21.20 U1.AD6 | length 83.1
  Top Layer w0.125: v1(54.25,19.2) 51.2,19.2 49.837,17.837 49.837,16.863 51.637,15.063 55.379,15.063 56.204,14.237 57.546,14.237 57.788,14.479 57.788,16.212 U1.AD6@57.5,16.5
  Layer 3 w0.125: v1(54.25,19.2) 53.587,19.863 53.587,21.274 53.663,21.349 53.663,44.984 54.25,45.571 54.25,47.686 51.75,50.186 51.75,52 51.25,52.5 51.25,60.507 51.688,60.945 51.688,66.988 54.6,69.9 62.8,69.9 64.05,68.65 v1(64.15,68.65)
  Bottom Layer w0.125: J21.20@64,66.8 64,68.5 v1(64.15,68.65)
DISP0_DAT19: J21.21 U1.Y6 | length 55.5
  Top Layer w0.125: v1(57.5,23.625) U1.Y6@57.5,24.5
  Layer 3 w0.125: v1(57.5,23.625) 57.5,25.261 54.913,27.848 54.913,44.466 55.5,45.054 55.5,50.046 54.913,50.634 54.913,63.77 58.18,67.038 63.538,67.038 v1(64.65,68.15)
  Bottom Layer w0.125: J21.21@64.5,66.8 64.5,68 v1(64.65,68.15)
DISP0_DAT20: J21.22 U1.W6 | length 65.3
  Top Layer w0.125: U1.W6@57.5,26.5 v1(58.25,27.125)
  Layer 5 w0.125: v1(49.25,68.35) 48.75,67.85 48.75,65.625 49.05,65.325 49.05,58.65 50.187,57.513 50.624,57.513 51.013,57.124 51.013,56.541 53.087,54.466 53.087,51.022 54.397,49.713 54.971,49.713 55.713,48.971 55.713,38.833 57.875,36.67 57.875,27.5 v1(58.25,27.125)
  Bottom Layer w0.125: v1(49.25,68.35) 50.4,69.5 64.025,69.5 65.063,68.462 65.063,67.979 65,67.917 65,67.725 J21.22@65,66.8
DISP0_DAT21: J21.23 U1.U6 | length 48.1
  Top Layer w0.125: v1(56.875,31.125) U1.U6@57.5,30.5
  Layer 3 w0.125: v1(56.875,31.125) 57.55,31.8 57.55,39.446 56.25,40.746 56.25,43.689 56,43.939 56,50.254 55.413,50.841 55.413,63.563 58.388,66.538 64.438,66.538 65.5,67.6 v1(65.5,68.125)
  Bottom Layer w0.125: J21.23@65.5,66.8 v1(65.5,68.125)
DISP0_DAT22: J21.24 U1.V7 | length 47.8
  Top Layer w0.125: v1(58.875,29.125) U1.V7@59.5,28.5
  Layer 5 w0.125: v1(62.85,65.5) 63.4,66.05 65.65,66.05 v1(66.25,65.45)
  Layer 3 w0.125: v1(58.875,29.125) 58.313,29.687 58.313,42.687 56.75,44.25 56.75,50.25 57.625,51.125 57.625,58.975 61.3,62.65 61.3,65.758 61.829,66.288 62.171,66.288 62.85,65.608 v1(62.85,65.5)
  Bottom Layer w0.125: J21.24@66,66.8 66,65.7 v1(66.25,65.45)
DISP0_DAT23: J21.25 U1.AA6 | length 59.7
  Top Layer w0.125: U1.AA6@57.5,22.5 v1(58.125,23.125)
  Layer 3 w0.125: v1(58.125,23.125) 58.125,25.125 55.163,28.087 55.163,44.363 55.75,44.95 55.75,50.15 55.163,50.737 55.163,63.666 58.284,66.788 64.088,66.788 65.063,67.763 65.063,68.846 65.529,69.313 66.087,69.313 66.5,68.9 v1(66.5,68.125)
  Bottom Layer w0.125: J21.25@66.5,66.8 v1(66.5,68.125)
DISP0_DRDY: J21.31 U1.V10 | length 47.8
  Top Layer w0.125: v1(64.25,28.875) 64.625,28.5 U1.V10@65.5,28.5
  Layer 8 w0.125: v1(64.25,28.875) 64.25,29.625 62.55,31.325 62.55,49.5 61.7,50.35 61.7,59.058 62.742,60.1 63.8,60.1 64.2,60.5 67.2,60.5 v1(67.95,61.25)
  Layer 3 w0.125: v1(67.95,61.25) 69.5,62.8 v1(69.5,67.725)
  Bottom Layer w0.125: J21.31@69.5,66.8 v1(69.5,67.725)
DISP0_HSYNC: J21.29 U1.W10 | length 48.3
  Top Layer w0.125: v1(64.375,27.25) U1.W10@65.5,26.5
  Layer 8 w0.125: v1(64.375,27.25) 62.3,29.325 62.3,49.396 61.45,50.246 61.45,59.162 62.638,60.35 63.55,60.35 64.325,61.125 v1(64.75,61.125)
  Layer 3 w0.125: v1(64.75,61.125) 64.75,62 67.7,64.95 67.7,67.25 v1(68.5,68.05)
  Bottom Layer w0.125: J21.29@68.5,66.8 v1(68.5,68.05)
DISP0_I2C_SCL: J21.33 R103.2 | length 62.5
  Layer 3 w0.125: v1(48.875,33.25) 49.75,34.125 49.75,37.15 51.475,38.875 51.475,43.225 49.25,45.45 49.25,65.125 49.7,65.575 49.7,68.75 51.5,70.55 68.646,70.55 70.5,68.696 v1(70.5,67.725)
  Bottom Layer w0.125: R103.2@48.875,32.645 v1(48.875,33.25) ; J21.33@70.5,66.8 v1(70.5,67.725)
DISP0_I2C_SDA: J21.34 R105.2 | length 45
  Layer 3 w0.125: v1(52.25,48.875) 51.25,49.875 51.25,51 50.2,52.05 50.2,53.75 51,54.55 51,60.611 51.298,60.909 51.298,66.973 54.525,70.2 68.643,70.2 70.025,68.818 70.025,66.85 v1(71,65.875)
  Bottom Layer w0.125: R105.2@51.52,48.875 v1(52.25,48.875) ; v1(71,65.875) J21.34@71,66.8
DISP0_IRQ_N: J21.35 R78.2 U1.H22 | length 38.7
  Top Layer w0.125: v1(89,49.125) 89,49 U1.H22@89.5,48.5
  Bottom Layer w0.125: R78.2@71.62,65.1 71.5,65.22 J21.35@71.5,66.8 71.5,67.833 72.204,68.538 77.143,68.538 78.315,67.366 78.315,61.413 79.391,60.337 83.113,60.337 86.45,57 88.925,57 90.425,55.5 90.425,50.55 v1(89,49.125)
DISP0_VSYNC: J21.30 U1.V8 | length 67.7
  Top Layer w0.125: v1(60.625,28) U1.V8@61.5,28.5
  Layer 8 w0.125: v1@51,68.425 52.388,69.813 68.137,69.813 v1(69,68.95)
  Layer 5 w0.125: v1(51,68.375) 49.925,67.3 49.925,63.1 51.15,61.875 51.15,59.254 53.637,56.766 53.637,56.226 55.462,54.401 55.462,50.989 56.963,49.489 56.963,44.484 58.513,42.934 58.513,39.824 58.087,39.399 58.087,38.226 58.476,37.837 58.484,37.837 59.125,37.196 59.125,30.354 60.125,29.354 60.125,29.146 60.125,28.5 v1(60.625,28)
  Bottom Layer w0.125: J21.30@69,66.8 v1(69,68.95)
DSI_CLK0_N: P18.11 U1.E10 | length 100
  Top Layer w0.104: P18.11@1.575,33 2.95,33 3.048,33.098 3.048,33.553 v1(2.851,33.75) ; v1(64.875,53.875) U1.E10@65.5,54.5
  Layer 5 w0.093: v1(2.851,33.75) 3.026,33.925 3.026,34.224 3.251,34.45 4.05,34.45 4.85,35.25 4.85,36.874 7.176,39.2 12.25,39.2 17.4,44.35 17.4,56.262 20.538,59.4 27.675,59.4 29,60.725 29,61.55 36.8,69.35 57.174,69.35 58.6,67.924 58.6,65.624 61.263,62.961 61.263,61.161 62.95,59.474 62.95,59.316 62.951,58.735 62.95,55.174 64.474,53.65 64.65,53.65 v1(64.875,53.875)
DSI_CLK0_P: P18.10 U1.F10 | length 100
  Top Layer w0.104: v1(3.5,33.75) 3.303,33.553 3.303,33.347 3.4,33.25 3.75,33.25 4.5,34 P18.10@5.225,34 ; v1(64.875,53.125) U1.F10@65.5,52.5
  Layer 5 w0.093: v1(3.5,33.75) 3.326,33.925 3.326,34.1 3.375,34.15 4.174,34.15 5.15,35.126 5.15,36.75 7.3,38.9 12.374,38.9 17.7,44.226 17.7,56.138 20.662,59.1 27.799,59.1 29.3,60.601 29.3,61.426 36.924,69.05 57.05,69.05 58.3,67.8 58.3,65.5 60.963,62.837 60.963,61.037 62.65,59.35 62.65,59.191 62.651,58.859 ; 62.65,58.859 62.65,55.05 64.35,53.35 64.65,53.35 v1(64.875,53.125)
DSI_D0_N: P18.8 U1.C10 | length 93.1
  Top Layer w0.104: v1(3.6,36.4) 3.6,36.3 3.9,36 P18.8@5.225,36 ; v1(64.5,59.125) 64.744,59.369 65.381,59.369 65.5,59.25 U1.C10@65.5,58.5
  Layer 5 w0.093: v1(3.6,36.4) 3.616,36.416 3.616,36.813 3.85,37.048 3.85,37.4 6.55,40.1 11.724,40.1 16.25,44.626 16.25,56.176 20.573,60.499 21.101,61.027 25.224,65.15 30.4,65.15 35.462,70.212 57.714,70.212 59.562,68.364 59.562,66.288 63.3,62.55 63.3,61.45 63.8,60.95 63.8,59.576 64.026,59.35 64.275,59.35 v1(64.5,59.125)
DSI_D0_P: P18.7 U1.B10 | length 93.1
  Top Layer w0.104: P18.7@1.575,37 3,37 v1(3.141,36.859) ; v1(64.5,59.875) 64.744,59.631 65.365,59.631 65.5,59.766 U1.B10@65.5,60.5
  Layer 5 w0.093: v1(3.141,36.859) 3.157,36.875 3.316,36.875 3.316,36.938 3.55,37.172 3.55,37.524 6.426,40.4 11.6,40.4 15.95,44.75 15.95,56.3 20.273,60.623 20.977,61.327 25.1,65.45 30.276,65.45 35.338,70.512 57.838,70.512 59.862,68.488 59.862,66.443 63.6,62.705 63.6,61.574 64.1,61.074 64.1,59.7 64.15,59.65 64.275,59.65 v1(64.5,59.875)
DSI_D1_N: P18.14 U1.E9 | length 105.6
  Top Layer w0.104: v1(3.799,30.45) 3.602,30.253 3.602,29.398 3.7,29.3 3.85,29.3 3.95,29.4 3.95,29.9 4.05,30 4.3,30 P18.14@5.225,30 ; U1.E9@63.5,54.5 63.5,55.25 63.619,55.369 64.256,55.369 v1(64.5,55.125)
  Layer 5 w0.093: v1(3.799,30.45) 3.625,30.625 3.625,31.9 2.388,33.136 2.388,34.188 2.95,34.75 3.55,34.75 3.799,34.75 4.6,35.551 4.6,37.1 7,39.5 12.124,39.5 17,44.376 17,56.182 20.468,59.65 23.7,59.65 ; 23.576,59.65 23.7,59.65 ; v1(64.5,55.125) 64.275,55.35 63.476,55.35 63.25,55.576 63.25,59.6 61.65,61.2 61.65,63.184 58.95,65.884 58.95,66.476 58.95,68.15 57.45,69.65 35.975,69.65 30.949,64.624 28.348,64.624 25.7,61.976 25.7,61.65 25.15,61.1 25.15,60.8 24,59.65 23.7,59.65
DSI_D1_P: P18.13 U1.D9 | length 105.5
  Top Layer w0.104: P18.13@1.575,31 2.25,31 2.75,30.5 2.75,30.1 2.85,30 3.247,30 3.347,30.1 3.347,30.253 v1(3.15,30.45) ; U1.D9@63.5,56.5 63.5,55.766 63.635,55.631 64.256,55.631 v1(64.5,55.875)
  Layer 5 w0.093: v1(3.15,30.45) 3.325,30.625 3.325,31.775 2.088,33.012 2.088,34.312 2.826,35.05 3.674,35.05 4.3,35.676 4.3,37.224 6.876,39.8 12,39.8 16.7,44.5 16.7,56.306 20.344,59.95 23.576,59.95 23.876,59.95 24.85,60.924 24.85,61.224 25.4,61.774 25.4,62.1 28.224,64.924 30.774,64.924 35.8,69.95 57.574,69.95 59.25,68.274 59.25,66.008 61.95,63.308 61.95,61.324 63.55,59.724 63.55,55.7 63.6,55.65 64.275,55.65 v1(64.5,55.875)
DSI_I2C_SCL: P18.5 R155.2 | length 10.1
  Top Layer w0.125: P18.5@1.575,39 2.7,39 v1(2.75,38.95)
  Bottom Layer w0.125: v1(2.75,38.95) 2.4,38.6 2.4,32.9 3.3,32 R155.2@4.745,32
DSI_I2C_SDA: P18.4 R156.2 | length 8.5
  Top Layer w0.125: v1(3.9,40) P18.4@5.225,40
  Bottom Layer w0.125: v1(3.9,40) 4.2,39.7 4.2,33.72 R156.2@4.77,33.15
ETH_TXRXA_N: J13.3 U10.3 | length 31.3
  Top Layer w0.104: J13.3@13.54,16.89 13.54,15.915 13.375,15.75 12.875,15.75 12.5,16.125 12.5,17.375 13.875,18.75 13.875,21.889 15.986,24.001 18.576,24.001 19.3,24.725 19.3,29.664 24.258,34.622 27.689,34.622 27.811,34.5 U10.3@28.425,34.5
ETH_TXRXA_P: J13.2 U10.2 | length 31.3
  Top Layer w0.104: J13.2@12.27,14.35 12.27,15.855 12.245,15.88 12.245,17.481 13.62,18.856 13.62,21.995 13.907,22.282 15.881,24.256 18.47,24.256 19.045,24.831 19.045,29.77 24.152,34.877 27.689,34.877 27.811,35 U10.2@28.425,35
ETH_TXRXB_N: J13.5 U10.6 | length 29.6
  Top Layer w0.104: J13.5@16,16.81 16,15.875 15.875,15.75 15.25,15.75 15.08,15.92 15.08,21.855 15.775,22.55 19.536,22.55 20.4,23.414 20.4,29.525 23.997,33.122 27.689,33.122 27.811,33 U10.6@28.425,33
ETH_TXRXB_P: J13.4 U10.5 | length 29.6
  Top Layer w0.104: J13.4@14.825,14.365 14.825,21.961 15.669,22.805 19.43,22.805 20.145,23.52 20.145,29.645 23.877,33.377 27.689,33.377 27.811,33.5 U10.5@28.425,33.5
ETH_TXRXC_N: J13.7 U10.8 | length 25.2
  Top Layer w0.104: J13.7@18.62,16.89 18.62,15.995 18.375,15.75 17.75,15.75 17.583,15.917 17.583,18.097 21.53,22.044 21.53,29.255 24.15,31.875 27.128,31.875 27.375,32.123 27.689,32.123 27.811,32 U10.8@28.425,32
ETH_TXRXC_P: J13.6 U10.7 | length 25.2
  Top Layer w0.104: U10.7@28.425,32.5 27.811,32.5 27.689,32.378 27.269,32.378 27.022,32.13 24.23,32.13 24.044,32.13 21.275,29.361 21.275,22.15 17.328,18.203 J13.6@17.328,14.372 ; J13.6@17.328,14.372 J13.6@17.35,14.35 ; J13.6@17.328,14.372 J13.6@17.35,14.35 ; J13.6@17.35,14.35 17.375,14.375 J13.6@17.35,14.35
ETH_TXRXD_N: J13.9 U10.11 | length 23.1
  Top Layer w0.104: J13.9@21.16,16.89 21.16,16.035 20.875,15.75 20.375,15.75 20,16.125 20,18.014 20.905,18.92 23.805,18.92 25.3,20.414 25.3,29.269 26.156,30.125 26.611,30.125 27.108,30.622 27.689,30.622 27.811,30.5 U10.11@28.425,30.5
ETH_TXRXD_P: J13.8 U10.10 | length 23
  Top Layer w0.104: J13.8@19.89,14.35 19.89,15.624 19.745,15.769 19.745,18.12 20.8,19.175 23.7,19.175 25.045,20.52 25.045,29.375 25.05,29.38 26.05,30.38 26.505,30.38 27.002,30.877 27.689,30.877 27.811,31 U10.10@28.425,31
EXP_GPIO_0: J30.6 U1.L24 | length 134.5
  Top Layer w0.125: U1.L24@93.5,42.5 v1(96.25,42.5)
  Layer 8 w0.125: J30.6@2.1,13.65 3,13.65 5.4,11.25 6.6,11.25 8.225,12.875 23.25,12.875 24,13.625 24,16 25.25,17.25 29.25,17.25 29.3,17.2 29.304,17.2 31.304,15.2 37.546,15.2 38.496,16.15 41.343,16.15 48.243,9.25 48.729,9.25 59,9.25 62.487,12.737 64.77,12.737 67.107,10.4 76.775,10.4 80.975,14.6 89.35,14.6 96.64,21.89 96.64,27.164 95.887,27.916 95.887,42.137 v1(96.25,42.5)
EXP_GPIO_1: J30.7 U1.G22 | length 141.5
  Top Layer w0.125: U1.G22@89.5,50.5 v1(90.875,49.125)
  Layer 8 w0.125: J30.7@2.1,14.9 3.1,13.9 3.104,13.9 5.504,11.5 6.496,11.5 8.121,13.125 23.125,13.125 23.75,13.75 23.75,16.125 25.125,17.5 29.375,17.5 31.425,15.45 37.443,15.45 38.393,16.4 41.446,16.4 48.346,9.5 58.875,9.5 62.362,12.987 64.873,12.987 66.461,11.4 77.421,11.4 80.871,14.85 89.246,14.85 96.39,21.993 96.39,27.06 95.637,27.813 95.637,44.363 v1(90.875,49.125)
EXP_GPIO_2: J30.8 U1.H23 | length 137.9
  Top Layer w0.125: v1(90.875,47.875) U1.H23@91.5,48.5
  Layer 8 w0.125: J30.8@2.1,16.15 2.25,16.15 3.15,15.25 3.15,14.204 3.204,14.15 3.207,14.15 5.607,11.75 6.393,11.75 8.018,13.375 23,13.375 23.5,13.875 23.5,16.293 24.957,17.75 29.5,17.75 31.55,15.7 37.325,15.7 38.275,16.65 41.55,16.65 48.45,9.75 58.75,9.75 62.237,13.237 64.977,13.237 66.564,11.65 77.318,11.65 80.768,15.1 89.143,15.1 93.737,19.695 93.737,27.862 93.95,28.075 93.95,31.717 93.5,32.167 93.5,44.5 90.875,47.125 v1(90.875,47.875)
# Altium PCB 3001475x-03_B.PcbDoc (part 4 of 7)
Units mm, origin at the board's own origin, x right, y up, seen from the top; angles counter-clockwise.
Board outline 100 x 72 mm, 12 copper layers (Top Layer, L2 GND, Layer 3, L4 GND, Layer 5, L6 PWR, L7 3V3, Layer 8, L9 GND, Layer 10, L11 GND, Bottom Layer), stack 1.735 mm thick; 431 components, 499 nets, 1977 pads, 1473 vias.

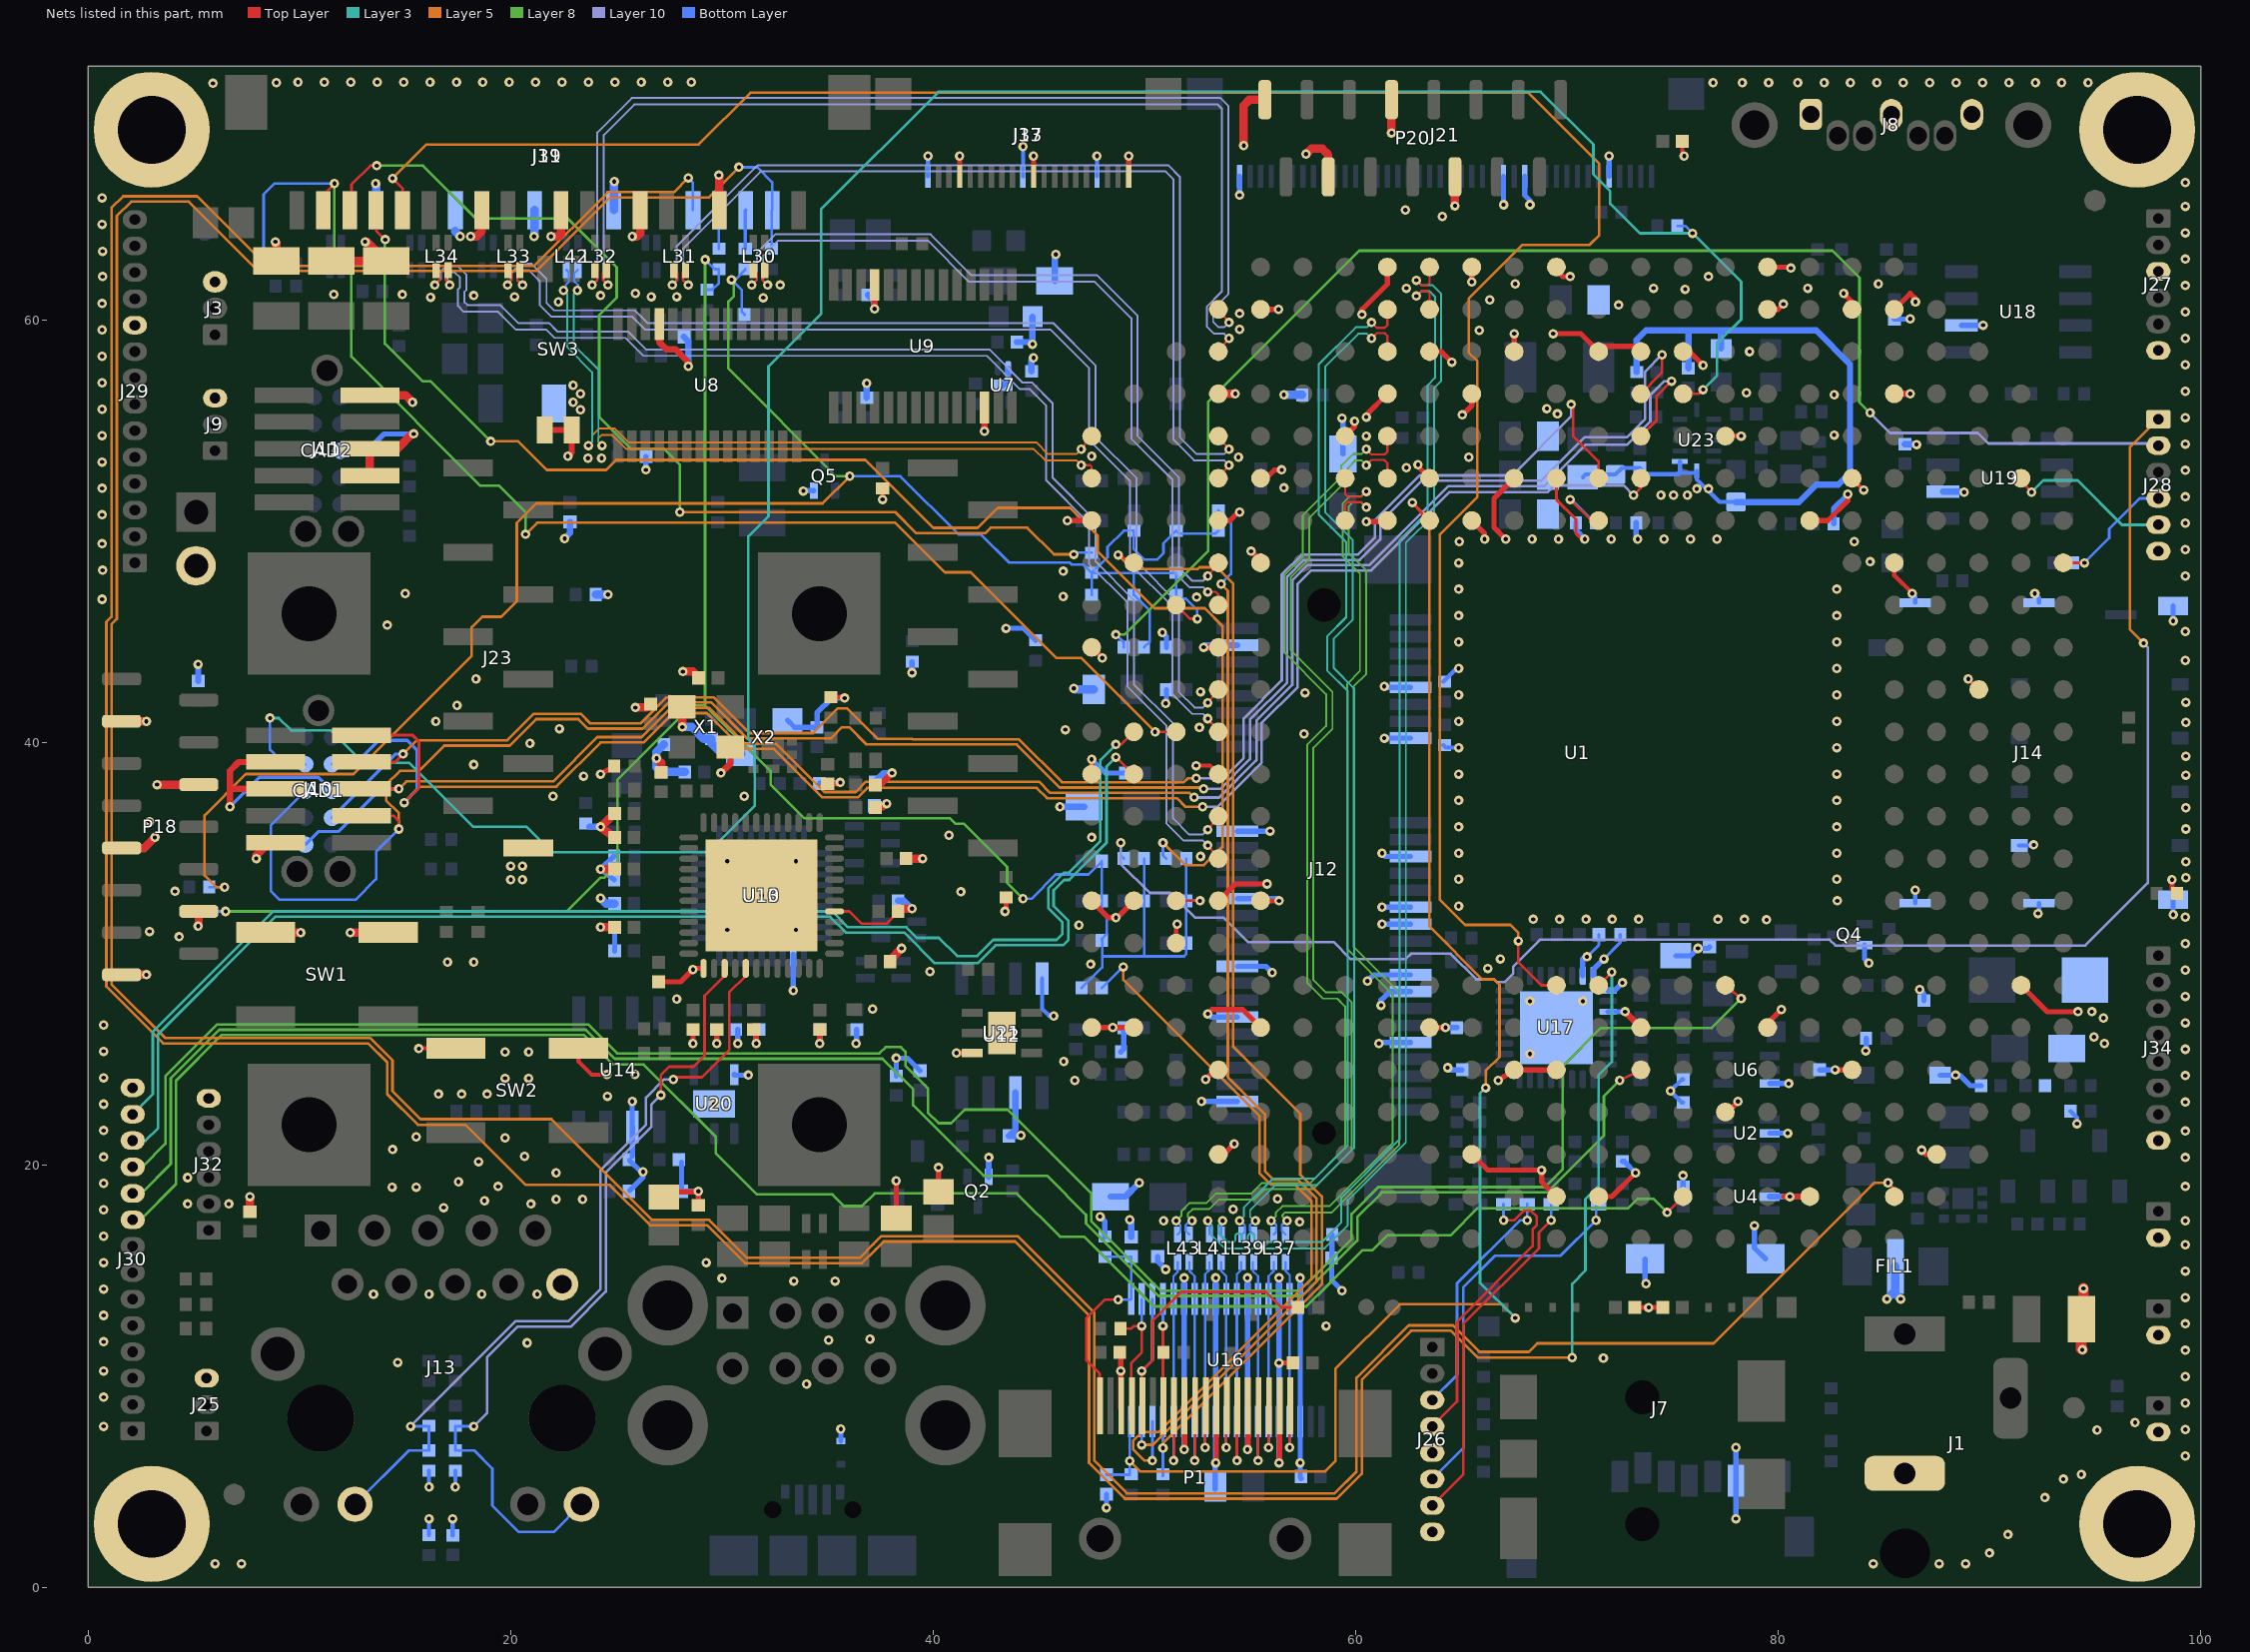
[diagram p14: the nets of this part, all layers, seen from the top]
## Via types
v1: diameter 0.45, hole 0.2, Top Layer to Bottom Layer, tented both sides, 1473 vias

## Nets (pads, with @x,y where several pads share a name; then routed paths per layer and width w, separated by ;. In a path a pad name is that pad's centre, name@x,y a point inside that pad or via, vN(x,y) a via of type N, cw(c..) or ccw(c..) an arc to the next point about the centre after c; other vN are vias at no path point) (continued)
EXP_GPIO_3: J30.9 U1.AC15 | length 88.9
  Top Layer w0.125: v1(74.75,17.75) U1.AC15@75.5,18.5
  Layer 8 w0.125: J30.9@2.1,17.4 2.45,17.4 4.15,19.1 4.15,23.993 6.307,26.15 23.45,26.15 24.85,24.75 26.3,24.75 29.7,21.35 29.7,20.55 31.65,18.6 35.23,18.6 35.78,18.05 36.625,18.05 37.225,18.65 43.954,18.65 46.004,16.6 47.15,16.6 50.45,13.3 51.039,13.3 57.669,13.3 58.687,14.318 58.687,14.324 59.076,14.713 59.082,14.713 60.332,15.962 60.796,15.962 61.508,16.675 64.504,16.675 65.779,17.95 72.904,17.95 73.354,18.4 74.1,18.4 v1(74.75,17.75)
EXP_GPIO_4: J30.10 U1.Y14 | length 89
  Top Layer w0.125: v1(72.5,24) U1.Y14@73.5,24.5
  Layer 8 w0.125: J30.10@2.1,18.65 2.5,18.65 3.9,20.05 3.9,24.096 6.204,26.4 23.554,26.4 24.929,25.025 37.6,25.025 39.05,23.575 39.05,22.825 42.388,19.487 45.388,19.487 47.237,17.638 47.237,17.226 50.663,13.8 57.462,13.8 58.187,14.526 58.187,14.532 58.868,15.213 58.874,15.213 60.075,16.413 60.075,17.533 61.242,18.7 69.054,18.7 71.75,21.396 71.75,23.25 v1(72.5,24)
EXP_GPIO_5: J30.11 U1.V16 | length 98.9
  Top Layer w0.125: U1.V16@77.5,28.5 v1(78.25,27.875)
  Layer 8 w0.125: J30.11@2.1,19.9 2.55,19.9 3.65,21 3.65,24.2 6.1,26.65 23.657,26.65 25.032,25.275 37.45,25.275 37.75,25.575 38.475,25.575 38.685,25.365 38.685,24.69 39.75,23.625 39.75,22.479 40.25,21.979 40.854,21.979 41.488,22.613 43.521,22.613 47.487,18.646 47.487,17.329 50.767,14.05 57.358,14.05 57.937,14.629 57.937,14.635 58.765,15.463 58.771,15.463 59.8,16.492 59.8,17.675 61.075,18.95 68.95,18.95 69.8,19.8 69.8,24.675 71.612,26.487 76.862,26.487 v1(78.25,27.875)
EXP_GPIO_6: J30.12 U1.N2 | length 64.2
  Top Layer w0.125: v1(48.65,39.3) 49.45,38.5 U1.N2@49.5,38.5
  Layer 3 w0.125: J30.12@2.1,21.15 2.7,21.15 3.3,21.75 3.3,26.196 8.854,31.75 35.113,31.75 35.863,31 38.625,31 40.075,29.55 42.1,29.55 42.95,30.4 46.154,30.4 46.4,30.646 46.4,31.55 45.7,32.25 45.7,32.996 46.191,33.488 46.438,33.488 48.2,35.25 48.2,38.85 v1(48.65,39.3)
EXP_GPIO_7: J30.13 U1.M2 | length 62.8
  Top Layer w0.125: v1(48.65,39.9) 48.9,39.9 U1.M2@49.5,40.5
  Layer 3 w0.125: J30.13@2.1,22.4 3.05,23.35 3.05,26.3 8.75,32 35.216,32 35.966,31.25 38.729,31.25 39.229,30.75 40.267,30.75 41.129,29.887 42.084,29.887 42.846,30.65 45.833,30.65 46.113,30.929 46.113,31.484 45.45,32.146 45.45,33.1 46.187,33.837 46.421,33.837 47.913,35.329 47.913,39.163 v1(48.65,39.9)
EXP_I2C_GPIO: J28.5 U1.F23 | length 8
  Top Layer w0.125: U1.F23@91.5,52.5 91.5,52.35 v1(92,51.85)
  Layer 3 w0.125: v1(92,51.85) 92.55,52.4 94.175,52.4 96.275,50.3 J28.5@98,50.3
EXP_I2C_IRQ_N: J28.4 R117.2 U1.H24 | length 6.5
  Top Layer w0.125: U1.H24@93.5,48.5 v1(94.5,48.5)
  Bottom Layer w0.125: R117.2@93.98,48.5 v1(94.5,48.5) 95.675,49.675 95.675,50.1 97.125,51.55 J28.4@98,51.55
EXP_I2C_SCL: J28.1 R106.2 | length 78.2
  Layer 5 w0.125: v1(97.3,44.7) 96.65,45.35 96.65,53.95 J28.1@98,55.3
  Layer 10 w0.125: v1(48.875,35.25) 48.875,34.25 50.25,32.875 51.225,32.875 52.4,31.7 53.75,31.7 54.9,30.55 58.95,30.55 59.75,29.75 62.375,29.75 62.625,30 64.5,30 65.713,28.788 66.546,28.788 66.683,28.65 67.05,28.65 67.45,29.05 67.45,29.383 68.729,30.663 82.437,30.663 82.713,30.387 94.537,30.387 97.5,33.35 97.5,44.5 v1(97.3,44.7)
  Bottom Layer w0.125: v1(48.875,35.25) 48.875,34.645 R106.2@49.02,34.5
EXP_I2C_SDA: J28.2 R107.2 | length 69
  Layer 8 w0.125: v1(48.65,45.1) 49.058,45.1 53.012,49.054 53.012,56.112 60.174,63.274 82.576,63.274 83.85,62 83.85,56.1 v1(84.35,55.6)
  Layer 10 w0.125: v1(84.35,55.6) 85.3,54.65 89.45,54.65 89.95,54.15 97.9,54.15 J28.2@98,54.05
  Bottom Layer w0.125: v1(48.65,45.1) 49.02,44.73 R107.2@49.02,44.5
GND: C1.2 C2.1 C3.1 C4.1 C5.1 C6.1 C7.1 C8.1 C9.2 C10.1 C11.1 C12.1 C13.1 C24.1 C25.1 C26.1 C27.1 C28.1 C29.1 C30.1 C33.2 C34.2 C35.2 C36.2 C37.1 C38.1 C39.1 C40.1 C41.1 C42.1 C43.1 C44.1 C45.1 C46.1 C47.1 C48.1 C49.1 C50.1 C51.1 C52.1 C53.1 C54.1 C55.1 C56.1 C57.1 C58.1 C59.1 C60.1 C61.1 C62.1 C63.2 C64.2 C65.2 C66.1 C67.1 C68.1 C69.1 C70.1 C71.1 C72.1 C73.1 C74.1 C75.1 C76.1 C77.1 C78.1 C79.1 C80.1 C81.1 C82.1 C83.1 C84.1 C85.1 C86.1 C89.1 C90.1 C95.1 C96.1 C99.1 C100.1 C101.1 C105.1 C106.1 C109.1 C110.1 C111.1 C112.1 C113.1 C114.1 C115.1 C116.1 C117.1 C118.1 C119.1 CAD1.3 CAD2.3 D1.K D2.A D4.K D5.K D6.K D10.1 FIL1.2 J1.2 J2.2 J3.3 J4.2 J5.2 J7.6 J7.9 J7.10 J8.1 J8.4 J8.7 J9.3 J10.3 J10.5 J10.9 J11.3 J11.5 J11.9 J12.4 J12.9 J12.15 J12.18 J12.21 J12.26 J12.27 J12.29 J12.34 J12.35 J12.37 J12.40 J12.43 J12.50 J13.10 J14.5 J14.11 J14.12 J14.13 J14.14 J14.15 J14.16 J17.1 J17.10 J17.17 J18.2 J19.4 J19.7 J19.10 J19.13 J21.1 J21.26 J21.28 J21.36 J23.10 J25.3 J26.5 J26.8 J27.3 J27.6 J28.6 J29.10 J30.14 J31.4 J31.7 J31.10 J31.13 J32.6 J33.1 J33.10 J33.17 J34.8 L12.1 L13.1 L15.1 L27.1 P1.2 P1.5 P1.8 P1.11 P1.17 P18.3 P18.6 P18.9 P18.12 P18.15 P20.6 P20.9 P20.12 P20.15 pad.0@3,3 pad.0@3,69 pad.0@97,3 pad.0@97,69 Q2.S Q4.S Q5.S R5.1 R14.1 R17.2 R18.2 R19.2 R20.1 R27.1 R28.2 R29.2 R37.1 R42.1 R43.1 R46.1 R49.1 R50.1 R54.2 R56.2 R57.2 R59.2 R70.1 R71.1 R73.1 R74.1 R84.1 R89.1 R130.2 R134.2 R136.2 R138.1 R144.1 R145.1 R146.1 SW1.1 SW1.2 SW2.1 SW2.2 SW3.1 SW3.2 U1.A8 U1.A10 U1.A12 U1.A17 U1.AA16 U1.AB4 U1.AB10 U1.AB21 U1.AC12 U1.AC13 U1.AC18 U1.B5 U1.B17 U1.B19 U1.B20 U1.C9 U1.C11 U1.C13 U1.C14 U1.C15 U1.D4 U1.D8 U1.D10 U1.D20 U1.E7 U1.E16 U1.F5 U1.F9 U1.F11 U1.F12 U1.F19 U1.G1 U1.G4 U1.G8 U1.G10 U1.G18 U1.H5 U1.H20 U1.K1 U1.K4 U1.L22 U1.N1 U1.N4 U1.T1 U1.T2 U1.T4 U1.T5 U1.U3 U1.V23 U1.W1 U1.W2 U1.W5 U1.W9 U1.W14 U1.W17 U1.Y4 U1.Y11 U1.Y12 U1.Y19 U2.2 U4.2 U5.A U6.3 U7.2 U7.5 U8.25 U9.12 U9.25 U10.13 U10.29 U10.49 U12.4 U12.6 U13.11 U13.37 U14.6 U16.3 U16.5 U16.8 U16.11 U16.14 U16.25 U16.28 U16.31 U16.34 U16.36 U17.1 U17.3 U17.31 U17.32 U17.33 U18.2 U19.2 U20.3 U20.7 U21.3 U21.7 U23.1 U23.12 X1.2 X1.4 X2.2 X2.4 | length 425.4
  Top Layer w0.125: U10.29@35.325,32 36.021,32 36.609,31.413 37.788,31.413 C54.1@38.5,32.125
  Top Layer w0.15: U1.F12@69.5,52.5 69.5,51.5 70.42,50.58 70.42,49.905 v1@70.85,49.475
  Top Layer w0.2: v1(15.65,25.5) 15.675,25.525 SW2.1@17.4,25.525 ; SW2.2@23.2,25.525 23.2,24.9 23.825,24.275 v1(24.55,24.275) ; v1(37.6,51.5) R136.2@37.6,52.02 ; U1.U3@51.5,30.5 51.5,31.35 v1(51.55,31.4) ; v1(52.45,38.9) 53.1,38.9 U1.N4@53.5,38.5 ; C106.1@75.46,68.45 75.46,67.84 v1(75.55,67.75) ; U1.F19@83.5,52.5 v1(84.05,51.95) ; U1.H20@85.5,48.5 85.5,47.9 v1(86.35,47.05) ; v1(89,43) U1.L22@89.5,42.5
  Top Layer w0.25: v1(24.25,38.5) R49.1@24.895,38.875 ; R49.1@24.834,38.953 R49.1@24.895,39 ; C43.1@27,28.665 28.04,28.665 v1(28.625,29.25) 28.675,29.3 U10.13@29.125,29.3 ; L15.1@27.25,18.725 v1@28.85,18.725 ; v1(28.625,25.75) C50.1@28.625,26.415 ; C71.1@28.875,18.085 v1@28.875,18.725 ; v1(29.75,25.75) C46.1@29.75,26.415 ; v1(31.625,25.75) C51.1@31.625,26.415 ; v1(34.625,25.75) C52.1@34.625,26.415 ; C47.1@35,38.04 35.54,38.04 v1(35.6,38.1) ; R50.1@35.15,42.14 35.76,42.14 v1(35.8,42.1) ; L13.1@38.25,17.475 v1(38.25,19.25) ; L12.1@40.25,18.725 v1(40.25,19.875) ; v1(41.1,25.3) U21.3@41.85,25.3 ; J17.17@41.25,66.8 v1(41.25,67.75) ; v1(43.4,32) 43.45,32.05 R130.2@43.45,32.67 ; J17.10@44.75,66.8 v1(44.75,67.75) ; v1(46.35,50.5) U1.G1@47.5,50.5 ; U1.W1@47.5,26.5 U1.W2@49.5,26.5 ; U1.T1@47.5,32.5 48.3,31.7 v1(48.65,31.7) 48.7,31.7 U1.T2@49.5,32.5 ; U1.N1@47.5,38.5 v1(47.5,39.2) ; U1.K1@47.5,44.5 v1(48,44) ; P1.17@48.875,8.5 v1(48.875,10.25) C86.1@48.875,11.085 ; J17.1@49.25,66.8 v1(49.25,67.75) ; v1(51.875,6.525) 51.9,6.55 P1.11@51.9,8.6 ; v1(52.9,24.05) 53.35,24.5 U1.Y4@53.5,24.5 ; v1(53,27.15) 53.2,27.35 54.65,27.35 U1.W5@55.5,26.5 ; v1(53.375,5.9) 53.4,5.925 P1.8@53.4,8.6 ; U1.AB4@53.5,20.5 53.75,20.5 v1(54.25,21) ; U1.T4@53.5,32.5 54.3,33.3 v1(55.8,33.3) ; U1.G4@53.5,50.5 54.05,50.5 54.45,50.9 v1(54.5,50.9) ; v1(54.875,6.525) 54.9,6.55 P1.5@54.9,8.6 ; v1(55.05,49.05) 55.5,48.6 U1.H5@55.5,48.5 ; U1.T5@55.5,32.5 v1(56.375,32.5) ; U1.F5@55.5,52.5 55.758,52.5 56.158,52.9 v1(56.5,52.9) ; U1.B5@55.5,60.5 v1(56.35,60.5) ; v1(56.375,5.9) 56.4,5.925 P1.2@56.4,8.6 ; v1(56.375,10.625) C82.1@57.04,10.625 ; U1.E7@59.5,54.5 59.95,54.95 v1(59.95,55.2) ; v1(60.3,60.25) 60.3,60.5 61.5,61.7 U1.A8@61.5,62.5 ; v1(60.5,50.45) 61.45,50.45 U1.G8@61.5,50.5 ; v1(60.5,55.4) 60.5,55.5 U1.D8@61.5,56.5 ; v1(62.95,53.15) 62.95,53.05 U1.F9@63.5,52.5 ; U1.W9@63.5,26.5 v1(64.25,26.5) ; U1.C9@63.5,58.5 64.05,58.5 v1(64.55,58) ; v1(65.05,55.5) 65.5,55.95 U1.D10@65.5,56.5 ; U1.AB10@65.5,20.5 66.25,19.75 v1(68.8,19.75) 68.8,19.2 U1.AC12@69.5,18.5 ; U1.G10@65.5,50.5 66.1,49.9 v1@66.1,49.6 ; v1(65.5,61.8) U1.A10@65.5,62.5 ; v1(66.75,24) U1.Y11@67.5,24.5 U1.Y12@69.5,24.5 ; v1(67.1,49.625) 66.55,50.175 66.55,51.55 U1.F11@67.5,52.5 ; U1.C11@67.5,58.5 v1(67.5,59.35) ; v1(69.35,59.35) 70.65,59.35 U1.C13@71.5,58.5 71.75,58.75 73.25,58.75 U1.C14@73.5,58.5 ; U1.A12@69.5,62.5 69.5,62.35 69.8,62.05 v1(70.15,62.05) ; U1.AC13@71.5,18.5 72.125,18.5 v1(73.25,19.625) ; C13.1@73.21,13.25 v1(73.875,13.25) C12.1@74.54,13.25 ; U1.C15@75.5,58.5 75.8,58.5 v1(76.45,57.85) ; U1.AA16@77.5,22.5 77.6,22.5 v1(78.1,23) ; U1.E16@77.5,54.5 v1(78.25,54.5) ; U1.W17@79.5,26.5 79.5,26.7 v1(80.15,27.35) ; U1.B17@79.5,60.5 80,60.5 v1(80.25,60.75) ; U1.A17@79.5,62.5 80.55,62.5 v1(80.6,62.45) ; U1.G18@81.5,50.5 82.35,50.5 83.3,51.45 v1(83.3,51.75) ; v1(82.7,24.5) U1.Y19@83.5,24.5 ; v1(83.1,61.25) 83.5,60.85 U1.B19@83.5,60.5 ; U1.B20@85.5,60.5 86.25,61.25 86.5,61 v1(86.5,60.85) ; v1(86.8,20.7) 87,20.5 U1.AB21@87.5,20.5 ; U1.V23@91.5,28.5 92.75,27.25 v1(94.2,27.25) ; v1(98.65,33.5) 98.65,33.08 R18.2@98.88,32.85
  Top Layer w0.3: v1(6.7,36.95) 6.7,37.8 ; J10.5@8.868,37.8 6.7,37.8 ; J10.3@8.868,39.07 7.12,39.07 6.7,38.65 6.7,37.8 ; SW3.1@21.465,54.79 SW3.1@21.615,54.79 SW3.2@22.885,54.79 22.885,53.735 v1(22.7,53.55) ; U8.25@27.025,59.805 27.025,58.95 27.375,58.6 27.8,58.6 28.4,58 v1(28.4,57.8) ; v1(29.95,38.55) 30.4,39 X1.2@30.4,39.775 ; v1(37.225,60.525) U9.25@37.225,61.65 ; C56.1@37.26,36.925 37.625,36.925 v1(37.8,37.1) ; C55.1@37.26,37.975 37.475,37.975 v1(38.05,38.55) ; v1(42.425,54.725) U9.12@42.425,55.85 ; v1(52.8,44.5) U1.K4@53.5,44.5 ; v1(72.75,27.25) U1.W14@73.5,26.5 ; v1(80.55,18.5) 80.3,18.5 U1.AC18@81.5,18.5 ; U1.D20@85.5,56.5 v1(86.25,56.5)
  Top Layer w0.4: P18.15@1.575,29 v1(2.75,29) ; P18.9@1.575,35 2.65,35 v1(3.15,35.5) ; P18.3@1.575,41 v1(2.75,41) ; v1(3.25,38) P18.6@5.225,38 ; v1(5.2,31.3) 5.225,31.325 P18.12@5.225,32 ; C29.1@7.65,17.785 v1(7.65,18.5) ; v1(7.95,34.5) 7.95,34.65 8.56,35.26 J10.9@8.868,35.26 ; SW1.1@8.4,31 v1(10.05,31) ; v1(8.85,63.7) 8.9,63.65 D6.K@8.9,62.8 ; D5.K@11.5,62.8 D4.K@14.1,62.8 13.2,63.7 v1(13.1,63.7) ; v1(12.4,31) SW1.2@14.2,31 ; J11.3@13.332,52.63 J11.5@13.332,53.9 14.64,53.9 14.65,53.91 14.65,53.928 15.322,54.6 v1(15.4,54.6) ; J11.9@13.332,56.44 15.01,56.44 v1(15.35,56.1) ; v1(18.1,63.95) 18.375,63.95 18.625,64.2 ; v1(21.9,63.95) 22.25,63.95 22.375,64.075 J19.10@22.375,65.2 ; v1(24.25,31.25) C58.1@24.915,31.25 ; v1(24.25,34) C59.1@24.915,34 ; C45.1@24.915,35.5 v1(24.25,36) C42.1@24.915,36.625 ; v1(25.75,63.95) 25.975,63.95 26.125,64.1 J19.7@26.125,65.2 ; v1(25.9,41.65) 26.425,41.65 C28.1@26.625,41.85 ; v1(26.9,39.25) 27.125,39.025 C44.1@27.125,38.585 ; v1(28.125,40.725) X1.4@28.125,41.675 ; v1(28.15,43.35) 28.63,43.35 C30.1@28.89,43.09 ; v1(29.85,66.85) 29.875,66.825 J19.4@29.875,65.2 ; C53.1@37.96,29.71 v1(38.5,30.25) ; C54.1@38.5,32.125 v1(39,32.125) ; C48.1@38.71,34.5 v1(39.5,34.5) ; U1.D4@53.5,56.5 v1(54.3,56.5) ; v1(54.7,68.25) 54.7,70.15 54.975,70.425 P20.15@55.7,70.425 ; v1(57.65,67.85) 57.9,68.1 58.424,68.1 58.7,67.824 P20.12@58.7,66.775 ; v1(61.7,68.85) P20.9@61.7,70.425 ; v1(64.7,65.4) P20.6@64.7,66.775
  Top Layer w0.5: v1(94.4,11.25) 94.35,11.3 D1.K@94.35,12.7 94.45,12.6 v1(94.45,14.15)
  Bottom Layer w0.15: v1(6.7,36.95) 8.1,38.35 10.885,38.35 CAD1.3@11.535,37.7 ; v1(70.95,29.85) 71.51,30.41 C118.1@71.51,30.9 ; v1(71.75,29.75) 72.52,30.52 R20.1@72.52,30.9
  Bottom Layer w0.2: R46.1@16.125,2.48 v1(16.125,3.25) ; v1(16.125,4.75) R54.2@16.125,5.52 ; C33.2@17.25,2.46 v1(17.25,3.25) ; v1(17.375,4.75) R56.2@17.375,5.52 ; J33.1@39.75,66.8 v1(39.75,67.75) ; J33.10@44.25,66.8 v1(44.25,68.2) ; U12.4@45.155,28.825 45.155,27.395 45.5,27.05 v1(45.7,27.05) ; J33.17@47.75,66.8 v1(47.75,67.75) ; R42.1@64.15,39.87 64.27,39.75 v1(64.875,39.75) ; R43.1@64.15,42.88 64.77,43.5 v1(64.875,43.5) ; C111.1@70.75,52.55 70.88,52.68 C112.1@72.3,52.68 72.61,52.99 C113.1@73.45,52.99 73.74,52.7 75.3,52.7 75.35,52.75 ; U23.1@75.35,53.3 75.35,52.75 ; C6.1@75.5,22.96 75.44,22.96 v1(74.9,23.5) 75.44,24.04 C5.1@75.5,24.04 ; C109.1@78,51.38 77.22,51.38 76.15,52.45 U23.12@76.15,52.85 76.05,52.75 75.35,52.75 ; v1(86.35,47.05) 86.49,46.91 J14.14@86.49,46.61 ; J14.13@86.49,32.39 v1(86.49,33) ; J14.5@91.41,35.12 92.07,35.12 v1(92.1,35.15) ; v1(92.15,47.05) 92.35,46.85 J14.15@92.35,46.61 ; v1(92.3,31.9) 92.35,31.95 J14.12@92.35,32.39 ; R14.1@93.84,22.55 94.15,22.24 v1(94.15,21.95)
  Bottom Layer w0.25: CAD2.3@11.935,53.8 13.2,53.8 14,54.6 v1(15.4,54.6) ; v1(24.25,31.25) R71.1@24.895,31.25 24.915,31.23 C57.1@24.915,30.125 ; R73.1@24.895,33.5 v1(24.25,34) R74.1@24.895,34.625 ; C68.1@25.625,18.79 26.263,19.428 v1(26.263,19.671) 26.164,19.671 C65.2@25.625,20.21 ; U14.6@25.75,21.81 v1(25.75,23) ; C65.2@25.76,20.425 U14.6@25.76,21.8 ; v1(26.4,52.9) C24.1@26.4,53.54 ; C70.1@28.085,20.125 C69.1@28.085,18.75 v1(28.875,18.75) ; U20.3@30.575,24.275 30.6,24.25 v1(31.25,24.25) ; v1(30.75,25.75) C73.1@30.75,26.415 ; v1(31.625,25.75) C78.1@31.625,26.415 ; X2.4@33.1,41.05 33.44,40.71 C64.2@34.5,40.71 34.5,41.4 35.2,42.1 v1(35.8,42.1) ; v1@33.365,28.375 33.365,29.94 U13.11@33.375,29.95 ; v1(33.85,51.9) 33.86,51.91 Q5.S@34.35,51.91 ; C79.1@34.61,38.05 34.66,38.1 v1(35.6,38.1) ; v1(34.625,25.75) C74.1@34.625,26.415 ; D10.1@35.625,6.925 v1(35.625,7.5) ; v1(36.35,25.75) 36.375,25.775 C49.1@36.375,26.415 ; C67.1@38.25,24.21 v1(38.25,25.05) 38.785,25.05 C66.1@39.375,24.46 ; v1(39,43.3) R145.1@39,43.82 ; v1@43.5,45.35 v1(43.45,45.4) 44.28,45.4 R134.2@44.85,44.83 ; v1(47.5,39.2) 48.15,38.55 C39.1@49.09,38.55 ; v1(47.9,17.55) 48.125,17.325 R89.1@48.125,16.605 ; v1(48.2,3.77) C83.1@48.2,4.415 ; v1(48.5,26.5) R59.2@49.02,26.5 49.02,25.49 R27.1@48.88,25.35 ; C38.1@50.625,15.665 50.625,15.425 v1(51,15.05) ; v1(50.85,45.2) 51.04,45.01 C37.1@51.04,44.5 ; v1(51,41.85) 51.04,41.89 C41.1@51.04,42.5 ; v1(51.875,6.525) U16.14@51.875,7.85 51.875,13.55 v1(51.875,14.65) ; v1(52.7,23) J12.50@54.4,23 ; v1(53,27.15) 53.15,27 J12.40@54.4,27 ; C80.1@53.35,4.65 C80.1@53.35,4.75 53.35,5.875 v1(53.375,5.9) 53.375,7.75 U16.28@53.375,13.65 v1(53.375,14.65) ; J12.34@54.4,29.4 55.75,29.4 v1(56.05,29.1) ; J12.26@54.4,32.6 56.275,32.6 v1(56.375,32.5) ; J12.18@54.4,35.8 v1(55.95,35.8) ; v1(54.5,65.9) J21.1@54.5,66.8 ; v1(54.875,6.525) 54.875,7.75 U16.31@54.875,13.55 ; U16.31@54.875,13.65 v1(54.875,14.65) ; v1(56.375,5.9) U16.5@56.375,7.85 v1(56.375,10.625) 56.375,13.55 v1(56.375,14.65) ; v1(57.375,14.65) 57.375,7.75 v1(57.375,5.9) 57.375,5.19 C81.1@57.415,5.15 ; R57.2@58.88,16.7 58.88,15.62 C84.1@58.86,15.6 58.86,14.54 v1(59.35,14.05) ; v1(59.35,55.35) 59.4,55.3 C36.2@59.4,53.65 ; v1(60.55,28.7) 60.85,29 J12.35@62.6,29 ; v1(61.1,25.75) 61.15,25.8 J12.43@62.6,25.8 ; v1(61.2,27.55) 61.2,27.8 61.6,28.2 J12.37@62.6,28.2 ; v1(61.25,31.4) J12.29@62.6,31.4 ; v1(61.25,32.2) J12.27@62.6,32.2 ; v1(61.25,34.75) 61.4,34.6 J12.21@62.6,34.6 ; v1(61.35,40.2) J12.15@62.6,40.2 ; v1(61.35,42.65) 61.4,42.6 J12.9@62.6,42.6 ; v1(64.25,26.5) C95.1@64.79,26.5 ; v1(64.35,24.6) 64.45,24.5 C89.1@65.04,24.5 ; v1(67,65.45) J21.26@67,66.8 ; J21.28@68,66.8 68,65.9 68.25,65.65 v1(68.25,65.45) ; R37.1@70.42,50.4 70.42,50.055 v1(70.85,49.625) ; U17.31@70.75,28.95 70.75,29.75 70.85,29.85 v1(70.95,29.85) ; U17.32@71.25,28.95 71.25,29.25 v1(71.75,29.75) ; U17.3@71.95,27.25 v1(72.75,27.25) ; U17.1@71.95,28.25 72.25,28.25 v1(72.625,28.625) ; J21.36@72,66.8 v1(72,67.75) ; C90.1@72.625,20.165 72.71,20.165 v1(73.25,19.625) ; R29.2@73.28,50.4 73.28,49.695 v1(73.35,49.625) ; v1@73.7,14.425 J7.9@73.7,15.55 ; L27.1@75.15,29.9 75.85,29.9 v1(76.2,30.25) 76.69,30.25 C96.1@76.75,30.31 ; C7.1@75.5,18.96 v1(75.5,19.5) ; v1(78,3.25) J7.6@78,5.05 v1(78,6.625) ; v1@78.875,17 78.875,16.075 J7.10@79.4,15.55 ; U2.2@79.6,21.5 v1(80.45,21.5) ; U6.3@79.6,23.85 v1(80.5,23.85) ; C4.1@81.96,24.5 v1(82.7,24.5) ; R28.2@82.63,50.35 82.63,51.08 v1(83.3,51.75) ; Q4.S@84.09,30.4 84.09,29.76 v1(84.3,29.55) ; v1(84.15,25.4) 84.17,25.42 R19.2@84.17,26 ; C99.1@85.5,60.04 86.24,60.04 v1(86.25,60.05) ; v1(86.7,28.3) 86.9,28.1 R17.2@86.9,27.78 ; D2.A@87.67,24.25 v1(88.4,24.25) 88.6,24.25 89.1,23.75 C3.1@89.61,23.75 ; U18.2@88.675,59.74 89.69,59.74 v1(89.7,59.75) ; v1(98.7,31.85) J14.11@98.7,32.55 ; v1(98.7,45.75) J14.16@98.7,46.45
  Bottom Layer w0.27: U7.5@43.55,57.15 U7.2@43.55,57.71
  Bottom Layer w0.3: C105.1@5.2,42.91 v1(5.2,43.7) ; v1(22.55,49.65) 22.8,49.9 C101.1@22.8,50.44 ; R146.1@23.73,36 v1(24.25,36) ; C26.1@28.2,59.19 28.4,58.99 v1(28.4,57.8) ; C25.1@36.85,56.31 v1(36.85,57) ; C27.1@36.9,61.19 37.225,60.865 v1(37.225,60.525) ; C76.1@37.21,37 37.7,37 v1(37.8,37.1) ; R70.1@37.23,38.125 37.655,38.55 v1(38.05,38.55) ; C75.1@38.335,32.5 38.625,32.5 v1(39,32.125) ; Q2.S@42.625,19.44 v1(42.625,20.346) ; U7.5@43.3,56.9 U7.5@43.55,57.15 ; U12.6@43.885,23.425 43.885,21.675 C62.1@43.585,21.375 44.125,21.375 v1(44.15,21.4) ; C10.1@43.96,58.95 44.6,58.95 v1(44.7,58.85) C8.1@44.7,60.15 ; C11.1@44.65,57.56 44.65,58.1 v1(44.75,58.2) ; C9.2@45.75,61.85 45.75,63.05 v1(45.8,63.1) ; v1(46,36.95) C35.2@47.15,36.95 ; C34.2@48.4,18.5 49.1,18.5 v1(49.75,19.15) ; v1(49.3,17.4) 49.35,17.4 49.375,17.375 C85.1@49.375,16.585 ; v1(52.8,44.5) 52.9,44.6 J12.4@54.4,44.6 ; R138.1@73.3,57.53 73.3,59.05 73.75,59.5 75.8,59.5 ; C110.1@75.75,57.71 75.75,59.45 75.8,59.5 ; R144.1@77.3,58.65 77.3,59.4 77.4,59.5 ; C109.1@78,51.38 80.98,51.38 81.8,52.2 82.85,52.2 83.4,52.75 83.4,57.9 81.8,59.5 77.4,59.5 ; U4.2@79.6,18.5 v1(80.55,18.5) ; C100.1@86,54.11 86.54,54.11 v1(86.55,54.1) ; U19.2@87.8,51.865 88.785,51.865 v1(88.8,51.85) ; 75.8,59.5 77.4,59.5
  Bottom Layer w0.4: v1(13.6,66.45) 13.625,66.425 J31.4@13.625,65.2 ; 17.375,64.2 17.375,64.175 v1(17.6,63.95) ; v1(21.1,63.95) 21.125,63.975 J31.10@21.125,65.2 ; v1(22.7,53.55) v1@22.71,53.54 ; R84.1@24.03,47 v1(24.6,47) ; v1(24.25,32.625) 24.5,32.375 C77.1@24.915,32.375 ; J31.13@24.875,65.2 24.875,66.525 v1(24.9,66.55) ; C60.1@27.24,39.9 26.9,39.56 v1(26.9,39.25) 26.9,38.81 C72.1@27.125,38.585 27.14,38.6 C61.1@28.24,38.6 ; v1(28.125,40.725) 28.575,40.725 29.135,40.165 C63.2@29.5,40.165 29.5,39.95 30,39.45 X2.2@30.9,39.45 ; v1(46.65,42.55) 46.7,42.5 C40.1@47.6,42.5 ; v1(56.6,56.45) R5.1@57.47,56.45 ; v1(85.15,13.65) FIL1.2@85.55,14.05 ; FIL1.2@85.55,15.2 FIL1.2@85.55,14.05 ; v1(85.8,13.65) 85.55,13.9 FIL1.2@85.55,14.05
  other v1: 6,1.125 7.25,1.125 84.5,1.125 87.625,1.125 88.875,1.125 90,1.625 90.875,2.5 92.625,4.25 93.5,5.125 94.35,5.35 99.275,6.225 95.1,7.45 99.275,7.475 0.725,7.625 96.9,7.8 99.275,8.725 0.725,9 34,9.625 99.275,9.975 0.725,10.25 14.65,10.65 71.725,10.85 99.275,11.225 20.775,11.575 0.725,11.625 35.05,11.7 37,11.75 58.6,12.375 99.275,12.475 0.725,12.875 99.275,13.725 13.5,13.875 16.125,13.875 18.625,13.875 21.25,13.875 0.725,14.125 73.75,14.375 33.4,14.5 35.35,14.5 30,14.625 99.275,14.975 0.725,15.375 29.25,15.375 99.275,16.225 0.725,16.625 78.875,17.125 57.35,17.3 50.9,17.35 99.275,17.35 0.725,17.875 54.2,17.9 16.825,17.975 4.7,18.15 6.65,18.15 20.95,18.15 18.75,18.3 22.15,18.375 23.4,18.375 56.3,18.4 14.375,18.95 15.525,18.95 19.4,18.975 99.275,18.975 0.725,19.125 17.525,19.2 4.7,19.4 22.15,19.625 18.475,20.15 99.275,20.35 0.725,20.375 20.65,20.4 14.4,20.725 19.725,21.275 15.525,21.325 99.275,21.6 0.725,21.625 0.725,22.875 29.625,22.875 99.275,22.975 24.575,23.25 16.575,23.35 17.675,23.35 18.875,23.35 46.7,24 19.725,24.1 20.85,24.1 0.725,24.125 99.275,24.225 25.875,24.275 46.175,24.9 68.25,25.25 19.725,25.35 20.85,25.35 0.725,25.375 99.275,25.475 95.45,25.75 94.95,26.05 43.25,26.25 0.725,26.625 99.275,26.725 95.4,26.95 94.85,27.25 37.125,27.375 68.25,27.75 70.75,27.75 27.85,27.85 99.275,27.975 33.375,28.25 39.85,29.15 99.275,29.225 66.25,29.3 47.45,29.5 17,29.6 18.25,29.598 66.85,29.75 99.275,30.475 4.3,30.8 2.9,31.05 30.25,31.125 33.5,31.125 46.9,31.35 79.45,31.6 68.4,31.625 69.65,31.625 70.9,31.625 72.15,31.625 73.4,31.625 77.15,31.625 78.4,31.625 99.275,31.725 64.875,32.25 82.8,32.5 31.875,32.75 41.305,32.923 4.1,32.95 20,33.5 20.55,33.5 64.875,33.525 82.775,33.525 99.3,33.6 20,34.15 20.55,34.15 99.3,34.35 30.25,34.375 33.5,34.375 52.65,34.6 64.875,34.75 82.775,34.75 47.5,35.5 40.75,35.6 99.3,35.9 64.875,36 82.775,36 2.9,36.25 99.3,36.9 64.875,37.25 82.775,37.25 22,37.45 31.05,37.45 23.45,38.4 99.3,38.45 64.875,38.5 82.775,38.5 18.25,38.95 99.3,39.35 82.775,39.75 20.9,39.95 57.55,40.4 46.25,40.6 22.3,40.65 52.6,40.7 99.3,40.95 16.45,41 64.875,41 82.775,41 17.45,41.75 99.3,41.9 64.875,42.25 82.775,42.25 57.6,42.35 52.65,42.4 18.35,43 82.775,43.5 99.275,43.875 64.875,44.75 82.775,44.75 99.275,45.25 14.15,45.55 64.875,46 82.775,46 0.65,46.775 52.472,46.873 46.15,46.9 15,47.05 64.875,47.25 82.775,47.25 99.275,47.875 46.15,48.1 0.675,48.15 64.875,48.5 84.35,48.55 99.275,49.125 0.65,49.4 64.9,49.5 83.6,49.5 66.1,49.625 68.35,49.625 69.6,49.625 72.1,49.625 74.6,49.625 75.85,49.625 77.1,49.625 99.275,50.375 0.65,50.775 99.275,51.625 74.45,51.7 75.05,51.7 75.7,51.7 76.15,52 76.7,52 0.65,52.025 56.6,52.05 99.275,52.875 62.4,53 0.65,53.275 23.65,53.45 24.3,53.45 54.45,53.5 65.35,53.5 47.5,53.55 99.275,54.125 60.5,54.5 0.65,54.525 82.65,54.55 99.275,55.375 69.55,55.55 23.3,55.75 0.65,55.775 69.05,55.8 22.95,56.1 82.65,56.45 23.3,56.5 78.5,56.55 99.275,56.625 22.95,56.9 0.65,57.025 99.275,57.875 0.65,58.275 78.65,58.5 99.275,59.125 65.85,59.5 0.65,59.525 54.5,59.55 54.5,60.3 99.275,60.375 72.45,60.7 0.65,60.775 22.25,60.85 66.35,60.95 31.95,61.05 16.2,61.075 20.175,61.1 26.65,61.1 27.85,61.1 18.25,61.15 24.25,61.15 14.865,61.2 11.616,61.202 25.9,61.25 75.6,61.45 62.4,61.5 74.1,61.5 81.4,61.5 99.275,61.625 32.75,61.65 67.55,61.7 84.75,61.7 0.675,62.05 76.7,62.05 99.275,62.875 0.675,63.25 99.275,64.125 0.65,64.525 64.1,64.9 62.35,65.2 99.275,65.375 0.65,65.775 99.275,66.5 5.9,71.2 8.9,71.225 76.925,71.225 78.3,71.225 79.55,71.225 80.925,71.225 82.175,71.225 83.425,71.225 84.675,71.225 85.925,71.225 87.175,71.225 88.425,71.225 89.675,71.225 90.925,71.225 92.175,71.225 93.425,71.225 94.675,71.225 9.925,71.25 11.175,71.25 12.425,71.25 13.675,71.25 14.925,71.25 16.175,71.25 17.425,71.25 18.675,71.25 19.925,71.25 21.175,71.25 22.425,71.25 23.675,71.25 24.925,71.25 26.175,71.25 27.425,71.25 28.55,71.25
HDMI_CEC_IN: R88.2 U1.H2 U16.16 | length 55.3
  Top Layer w0.125: v1(48.75,48.875) U1.H2@49.5,48.5
  Layer 5 w0.125: v1(48.75,48.875) 49.413,48.212 52.524,48.212 52.599,48.288 53.421,48.288 54.2,47.508 54.2,25.6 57.375,22.425 57.375,19.532 58.4,18.507 58.4,14.35 50.875,6.825 v1(50.875,6.602)
  Bottom Layer w0.125: R88.2@50.875,5.27 R88.2@50.875,5.355 v1(50.875,6.602) U16.16@50.875,7.85
HDMI_CLK_N: L43.4 U1.E8 | length 49.8
  Top Layer w0.104: v1(60.5,53.875) 60.748,53.628 61.375,53.628 61.5,53.753 U1.E8@61.5,54.5
  Layer 8 w0.093: v1(51.5,17.35) 51.75,17.6 51.75,17.8 52.15,18.2 52.941,18.2 53.391,18.649 ; 53.141,18.4 53.391,18.649 ; 57.499,49.01 57.499,49.59 ; 57.5,49.009 57.5,48.8 56.625,47.925 56.625,44.25 58.6,42.275 58.6,40.775 57.7,39.874 57.7,28.626 58.451,27.875 59.125,27.875 59.5,27.5 59.5,20.799 57.851,19.15 55.561,19.15 55.064,18.653 53.395,18.653 53.391,18.649 ; 57.5,49.591 57.5,50.75 59.325,52.575 59.325,53.099 59.876,53.65 60.275,53.65 v1(60.5,53.875)
  Bottom Layer w0.104: v1(51.5,17.35) 51.695,17.155 51.695,16.82 L43.4@51.575,16.7
HDMI_CLK_P: L43.1 U1.F8 | length 49.3
  Top Layer w0.104: v1(60.5,53.125) 60.748,53.372 61.35,53.372 61.5,53.222 U1.F8@61.5,52.5
  Layer 8 w0.093: v1(52.25,17.35) 52.05,17.55 52.05,17.676 52.274,17.9 53.065,17.9 53.515,18.349 ; 53.353,18.188 53.515,18.349 ; 57.799,49.134 57.799,49.466 ; 57.8,49.134 57.8,48.676 56.925,47.801 56.925,44.374 58.9,42.399 58.9,40.65 58,39.75 58,28.75 58.575,28.175 59.325,28.175 59.8,27.7 59.8,20.675 57.975,18.85 55.685,18.85 55.188,18.353 53.519,18.353 53.515,18.349 ; 57.8,49.466 57.8,50.626 59.625,52.451 59.625,52.975 60,53.35 60.275,53.35 v1(60.5,53.125)
  Bottom Layer w0.104: L43.1@52.125,16.7 51.95,16.875 51.95,17.15 52.15,17.35 v1(52.25,17.35)
HDMI_D0_N: L41.4 U1.A9 | length 57.5
  Top Layer w0.104: v1(62.875,61.875) 63.122,61.628 63.375,61.628 63.5,61.753 U1.A9@63.5,62.5
  Layer 3 w0.093: v1(53,17.35) 53.2,17.15 53.2,16.651 53.801,16.05 58.524,16.05 59.625,17.151 59.625,18.326 62.375,21.076 62.375,49.45 63.712,50.787 63.712,56.788 64.05,57.126 64.05,61.224 63.624,61.65 63.1,61.65 v1(62.875,61.875)
  Bottom Layer w0.104: v1(53,17.35) 53.075,17.275 L41.4@53.075,16.7
HDMI_D0_P: L41.1 U1.B9 | length 57.1
  Top Layer w0.104: v1(62.875,61.125) 63.123,61.373 63.378,61.373 63.5,61.25 U1.B9@63.5,60.5
  Layer 3 w0.093: v1(53.7,17.35) 53.5,17.15 53.5,16.775 53.925,16.35 54.15,16.35 54.165,16.35 ccw(c54.165,16.485) 54.301,16.485 54.301,16.615 cw(c54.436,16.615) 54.436,16.75 54.466,16.75 cw(c54.466,16.615) 54.602,16.615 54.602,16.485 ccw(c54.737,16.485) 54.737,16.35 54.767,16.35 ccw(c54.767,16.485) 54.903,16.485 54.903,16.615 cw(c55.038,16.615) 55.038,16.75 55.068,16.75 cw(c55.068,16.615) 55.204,16.615 55.204,16.485 ccw(c55.339,16.485) 55.339,16.35 55.4,16.35 58.4,16.35 59.325,17.275 59.325,18.45 62.075,21.2 62.075,49.574 63.412,50.911 63.412,56.912 63.75,57.25 63.75,61.1 63.5,61.35 63.1,61.35 v1(62.875,61.125)
  Bottom Layer w0.104: L41.1@53.625,16.7 53.625,17.275 v1(53.7,17.35)
HDMI_D1_N: L39.4 U1.B8 | length 50.9
  Top Layer w0.104: v1(60.75,59.875) 60.998,59.628 61.375,59.628 61.5,59.753 U1.B8@61.5,60.5
  Layer 3 w0.093: v1(54.5,17.35) 54.7,17.55 54.7,17.974 56.076,19.35 58.05,19.35 59.625,20.925 59.625,42.425 58.662,43.388 58.662,45.036 59.55,45.924 59.55,49.476 58.25,50.776 58.25,57.899 60.001,59.65 60.525,59.65 v1(60.75,59.875)
  Bottom Layer w0.104: v1@54.55,17.35 54.745,17.155 54.745,16.82 L39.4@54.625,16.7
HDMI_D1_P: L39.1 U1.C8 | length 50.5
  Top Layer w0.104: v1(60.75,59.125) 60.998,59.372 61.375,59.372 61.5,59.247 U1.C8@61.5,58.5
  Layer 3 w0.093: v1(55.25,17.35) 55.2,17.35 55,17.55 55,17.85 56.2,19.05 58.174,19.05 59.925,20.801 59.925,42.549 58.962,43.512 58.962,44.912 59.85,45.8 59.85,49.6 58.55,50.9 58.55,57.775 60.125,59.35 60.525,59.35 v1(60.75,59.125)
  Bottom Layer w0.104: L39.1@55.175,16.7 55,16.875 55,17.15 v1@55.2,17.35
HDMI_D2_N: L37.4 U1.F7 | length 43.2
  Top Layer w0.104: U1.F7@59.5,52.5 59.5,51.752 59.625,51.628 60.253,51.628 v1(60.5,51.875)
  Layer 8 w0.093: v1(56,17.35) 56.225,17.575 56.225,17.749 56.526,18.05 58.751,18.05 61.75,21.049 61.75,28.066 60.716,29.101 60.713,29.101 60.713,29.103 59.6,30.216 59.6,42.774 60.2,43.374 60.2,48 59.375,48.825 59.375,51.299 59.726,51.65 60.275,51.65 v1(60.5,51.875)
  Bottom Layer w0.104: v1@56.05,17.35 56.245,17.155 56.245,16.82 L37.4@56.125,16.7
HDMI_D2_P: L37.1 U1.G7 | length 42.7
  Top Layer w0.104: U1.G7@59.5,50.5 59.5,51.248 59.625,51.373 60.253,51.373 v1(60.5,51.125)
  Layer 8 w0.093: v1(56.75,17.35) 56.525,17.575 56.525,17.625 56.65,17.75 58.875,17.75 62.05,20.925 62.05,28.129 62.05,28.191 59.9,30.341 59.9,42.65 60.5,43.25 60.5,48.124 59.675,48.949 59.675,51.175 59.85,51.35 60.275,51.35 v1(60.5,51.125)
  Bottom Layer w0.104: L37.1@56.675,16.7 56.5,16.875 56.5,17.15 v1@56.7,17.35
HDMI_DDC_SCL: P1.15 R87.1 U16.22 | length 15.7
  Top Layer w0.125: P1.15@49.875,8.5 v1(49.875,10.25) 50.375,10.75 50.375,12.625 51.737,13.987 55.747,13.987 56.485,13.25 R87.1@57.27,13.25
  Bottom Layer w0.125: v1(49.875,10.25) 50.375,10.75 U16.22@50.375,13.65
HDMI_DDC_SDA: P1.16 R85.1 U16.21 | length 6.4
  Top Layer w0.125: R85.1@48.855,12.25 49.375,12.25 49.5,12.375 v1(49.875,12.375) 49.875,11.125 49.375,10.625 P1.16@49.375,8.5
  Bottom Layer w0.125: v1(49.875,12.375) U16.21@49.875,13.65
HDMI_FIL_CLK_N: L43.3 P1.12 U16.15 U16.24 | length 12.1
  Top Layer w0.122: v1(51.375,6) 51.4,6.025 P1.12@51.4,8.6
  Bottom Layer w0.104: U16.24@51.375,13.65 51.375,14.733 51.575,14.933 L43.3@51.575,15.4
  Bottom Layer w0.122: v1(51.375,6) U16.15@51.375,7.85 U16.24@51.375,13.65
HDMI_FIL_CLK_P: L43.2 P1.10 U16.13 U16.26 | length 12.1
  Top Layer w0.122: v1(52.375,6) 52.4,6.025 P1.10@52.4,8.6
  Bottom Layer w0.104: L43.2@52.125,15.4 52.125,14.983 52.375,14.733 U16.26@52.375,13.65
  Bottom Layer w0.122: v1(52.375,6) U16.13@52.375,7.85 U16.26@52.375,13.65
HDMI_FIL_D0_N: L41.3 P1.9 U16.12 U16.27 | length 10.7
  Top Layer w0.122: v1(52.875,6.625) P1.9@52.875,8.5
  Bottom Layer w0.104: U16.27@52.875,13.65 52.875,14.825 53.075,15.025 L41.3@53.075,15.4
  Bottom Layer w0.122: v1(52.875,6.625) U16.12@52.875,7.85 U16.27@52.875,13.65
HDMI_FIL_D0_P: L41.2 P1.7 U16.10 U16.29 | length 10.8
  Top Layer w0.122: v1(53.875,6.625) P1.7@53.875,8.5
  Bottom Layer w0.104: L41.2@53.625,15.4 53.625,14.983 53.875,14.733 U16.29@53.875,13.65
  Bottom Layer w0.122: v1(53.875,6.625) U16.10@53.875,7.85 U16.29@53.875,13.65
HDMI_FIL_D1_N: L39.3 P1.6 U16.9 U16.30 | length 12
  Top Layer w0.122: v1(54.375,6) P1.6@54.375,8.5
  Bottom Layer w0.104: U16.30@54.375,13.65 54.375,14.825 54.575,15.025 L39.3@54.575,15.4
  Bottom Layer w0.122: v1(54.375,6) U16.9@54.375,7.85 U16.30@54.375,13.65
HDMI_FIL_D1_P: L39.2 P1.4 U16.7 U16.32 | length 12
  Top Layer w0.122: v1(55.375,6) P1.4@55.375,8.5
  Bottom Layer w0.104: L39.2@55.125,15.4 55.125,14.983 55.375,14.733 U16.32@55.375,13.65
  Bottom Layer w0.122: v1(55.375,6) U16.7@55.375,7.85 U16.32@55.375,13.65
HDMI_FIL_D2_N: L37.3 P1.3 U16.6 U16.33 | length 10.8
  Top Layer w0.122: v1(55.875,6.625) P1.3@55.875,8.5
  Bottom Layer w0.104: U16.33@55.875,13.65 55.875,14.733 56.125,14.983 L37.3@56.125,15.4
  Bottom Layer w0.122: v1(55.875,6.625) U16.6@55.875,7.85 U16.33@55.875,13.65
HDMI_FIL_D2_P: L37.2 P1.1 U16.4 U16.35 | length 10.7
  Top Layer w0.122: v1(56.875,6.625) P1.1@56.875,8.5
  Bottom Layer w0.104: L37.2@56.675,15.4 56.675,14.975 56.875,14.775 U16.35@56.875,13.65
  Bottom Layer w0.122: v1(56.875,6.625) U16.4@56.875,7.85 U16.35@56.875,13.65
HDMI_HPD: C83.2 R90.2 U1.G9 U16.19 | length 71
  Top Layer w0.125: v1(62.68,51.355) U1.G9@63.43,50.48
  Layer 5 w0.125: v1(49.305,5.98) 49.805,5.48 58.538,5.48 59.038,5.979 59.038,10.338 62.1,13.4 66.91,13.4 v1(67.555,12.755) ; v1(62.68,51.355) 63.487,50.548 63.487,31.279 65.979,28.788 66.546,28.788 66.805,28.528 66.805,25.105 66.15,24.45 v1(66.15,23.65)
  Layer 3 w0.125: v1(66.15,23.65) 65.887,23.387 65.887,14.423 v1(67.555,12.755)
  Bottom Layer w0.125: C83.2@48.2,5.335 49.305,5.335 v1(49.305,5.98) U16.19@49.305,7.83
HDMI_I2C_SCL: R99.2 U16.17 | length 35.6
  Layer 5 w0.125: v1(49,29.375) 49,28.75 55.45,22.3 55.45,19.6 56,19.05 57.15,19.05 57.9,18.3 57.9,14.592 50.658,7.35 49.875,7.35 49.462,6.937 49.462,6.538 50,6 v1(50.375,6)
  Bottom Layer w0.125: R99.2@47.98,28.375 48.98,29.375 v1(49,29.375) ; v1(50.375,6) U16.17@50.375,7.85
HDMI_I2C_SDA: R100.2 U16.18 | length 52.2
  Layer 5 w0.125: v1@49.875,6.625 v1(49.875,6.75) 50.412,6.75 58.15,14.488 58.15,18.404 57.254,19.3 56.104,19.3 55.704,19.7 55.704,22.4 53.95,24.154 53.95,47.175 v1(53.625,47.5)
  Bottom Layer w0.125: v1(49.875,6.75) U16.18@49.875,7.85 ; R100.2@53.5,50.98 54.1,50.38 54.1,47.975 v1(53.625,47.5)
HDMICEC: P1.13 R86.2 U16.23 | length 5.1
  Top Layer w0.125: P1.13@50.875,8.5 v1(50.875,12.375)
  Bottom Layer w0.125: v1(50.875,12.375) U16.23@50.875,13.65
HDMIHPD: C85.2 P1.19 R89.2 U16.20 | length 10.2
  Top Layer w0.125: P1.19@47.875,8.5 47.875,10.125 47.25,10.75 47.25,12.75 48.125,13.625 v1(48.75,13.625)
  Bottom Layer w0.125: R89.2@48.125,15.645 C85.2@49.355,15.645 ; v1(48.75,13.625) U16.20@49.35,13.625 ; U16.20@49.375,13.65 C85.2@49.375,15.645
I2C3_SCL: R95.1 R97.1 R99.1 R103.1 R106.1 R108.1 R109.1 R112.1 R114.1 R155.1 R207.1 R298.1 U1.T3 | length 98.9
  Top Layer w0.125: U1.T3@51.5,32.5 v1@52.625,32.5
  Layer 8 w0.125: v1(6.5,32) 22.65,32 24.237,33.587 24.421,33.587 25.05,34.217 25.05,38.233 28.567,41.75 29.2,41.75 ; v1(29.2,62.85) 29.2,41.75 ; v1(44.25,32.6) 43.5,33.35 43.5,34.099 41.447,36.152 41.049,36.152 40.788,36.412 33.888,36.412 32.3,38 32.3,38.65 29.2,41.75
  Bottom Layer w0.125: R155.1@5.705,32 v1(6.5,32) ; v1(29.2,62.85) 29.65,62.4 R298.1@29.85,62.4 29.85,61.742 29.538,61.43 R207.1@29.3,61.43 ; v1(44.25,32.6) 44.65,32.6 45.8,33.75 47.355,33.75 R108.1@47.98,34.375 47.98,31.97 48.213,31.737 48.213,30.933 R114.1@47.98,30.7 ; R99.1@47.02,28.375 48,29.355 48,29.875 ; R114.1@47.98,30.625 R114.1@47.98,30.7 ; R106.1@49.98,34.5 R103.1@49.98,32.5 49.98,29.875 ; R97.1@51.98,34.5 R95.1@51.98,32.5 ; v1(52.625,32.5) R95.1@51.98,32.5 ; R114.1@47.98,30.7 48,30.68 48,29.875 ; 48,29.875 49.98,29.875 ; 49.98,29.875 51.875,29.875 51.98,29.98 R109.1@51.98,30.5 R95.1@51.98,32.5
I2C3_SDA: R96.1 R98.1 R100.1 R105.1 R107.1 R110.1 R111.1 R113.1 R115.1 R156.1 R208.1 R299.1 U1.J3 | length 95.1
  Top Layer w0.125: U1.J3@51.5,46.5 52.15,45.85 v1(52.5,45.85)
  Layer 8 w0.125: v1@30.563,61.835 30.563,61.129 30.3,60.867 30.3,57.7 35.4,52.6 v1(36.05,52.6)
  Layer 5 w0.125: v1(6.45,33.15) 6.05,33.15 5.5,33.7 5.5,36.55 7.45,38.5 12.55,38.5 18.15,44.1 18.15,45.45 18.65,45.95 19.549,45.95 20.287,46.688 20.287,50.387 21.213,51.313 34.763,51.313 v1(36.05,52.6)
  Bottom Layer w0.125: R156.1@5.73,33.15 v1(6.45,33.15) ; v1(30.45,61.9) 30.937,61.413 30.937,60.383 R208.1@31.07,60.25 ; v1@30.628,61.9 31.1,62.372 R299.1@31.1,62.4 ; v1(36.05,52.6) 38.45,52.6 41.202,49.848 42.248,49.848 43.583,48.513 46.454,48.513 46.542,48.425 47.095,48.425 R98.1@47.5,48.02 ; R115.1@47.5,46.98 R98.1@47.5,48.02 ; R107.1@49.98,44.5 50.25,44.77 50.25,46.23 R111.1@49.5,46.98 49.5,48.02 ; v1(52.5,45.85) 52.5,46.262 51.962,46.8 51.68,46.8 R96.1@51.5,46.98 R105.1@51.5,48.02 49.5,48.02 ; R100.1@53.5,50.02 53.367,49.887 51.633,49.887 R113.1@51.5,50.02 50.9,49.42 50.9,48.95 50.6,48.65 50,48.65 49.5,49.15 R110.1@49.5,50.02 49.02,50.02 48.25,49.25 48.25,48.77 R98.1@47.5,48.02 ; R98.1@47.5,48.02 49.5,48.02
JTAG_MOD: R37.2 U1.G13 | length 3.5
  Top Layer w0.125: v1(70.15,51.5) 71.15,50.5 U1.G13@71.5,50.5 U1.G13@71.5,50.6
  Bottom Layer w0.125: v1(70.15,51.5) 70.217,51.5 71.317,50.4 R37.2@71.38,50.4
JTAG_TCK: CAD1.4 J10.4 U1.F13 | length 82.5
  Top Layer w0.125: v1(70.2,56) 70.287,55.913 70.287,54.513 71.5,53.3 U1.F13@71.5,52.5
  Top Layer w0.15: J10.4@12.932,39.07 14.52,39.07 v1(14.9,39.45)
  Layer 5 w0.125: v1(14.9,39.45) 15.548,40.098 19.844,40.098 21.096,41.35 23.3,41.35 23.75,40.9 26.139,40.9 27.377,42.138 29.598,42.138 31.298,40.437 34.312,40.437 35.487,41.613 35.921,41.613 37.371,40.163 38.999,40.163 39.012,40.15 44.054,40.15 46.091,38.113 51.859,38.113 52.046,38.3 v1(52.45,38.3)
  Layer 10 w0.125: v1(52.45,38.3) 53.739,38.3 54.7,39.261 54.7,41.136 56.5,42.936 56.5,47.95 57.437,48.887 60.087,48.887 60.913,49.713 60.913,50.524 63.026,52.637 67.421,52.637 70.2,55.417 v1(70.2,56) v1@70.187,56.013
  Bottom Layer w0.15: CAD1.4@11.535,36.43 14.555,39.45 v1(14.9,39.45)
JTAG_TDI: CAD1.8 J10.8 U1.D14 | length 99.5
  Top Layer w0.125: J10.8@12.932,36.53 14.435,36.53 14.7,36.265 v1(14.7,35.9) ; U1.D14@73.5,56.5 74.5,57.5 v1(74.5,58.35)
  Layer 5 w0.125: v1(14.7,35.9) 14.7,36.65 14.1,37.25 14.1,38 14.75,38.65 15.65,38.65 16.848,39.848 19.948,39.848 21.2,41.1 23.196,41.1 23.646,40.65 26.243,40.65 27.48,41.888 29.495,41.888 31.195,40.187 35.154,40.187 35.679,40.713 36.021,40.713 36.821,39.913 38.896,39.913 38.908,39.9 43.95,39.9 45.987,37.863 52.737,37.863 v1(52.8,37.8)
  Layer 10 w0.125: v1(52.8,37.8) 53.593,37.8 54.995,39.202 54.995,41.077 56.75,42.832 56.75,47.846 57.541,48.637 60.191,48.637 61.163,49.609 61.163,50.421 63.129,52.387 68.781,52.387 70.844,54.45 72.85,54.45 73.7,55.3 73.7,57.55 v1(74.5,58.35)
  Bottom Layer w0.125: CAD1.8@10.265,37.7 8.65,36.085 8.65,32.95 9.05,32.55 12.65,32.55 13.625,33.525 13.625,34.825 v1(14.7,35.9)
JTAG_TDO: CAD1.6 J10.6 U1.E14 | length 87.4
  Top Layer w0.125: U1.E14@73.5,54.5 74.25,55.25 74.25,56.4 v1(74.95,57.1)
  Top Layer w0.15: J10.6@12.932,37.8 v1(14.7,37.8)
  Layer 5 w0.125: v1(14.7,37.8) 15.05,38.15 22,38.15 24.1,40.25 26.196,40.25 27.584,41.638 29.391,41.638 31.091,39.937 32.563,39.937 34.85,37.65 36.328,37.65 36.814,38.136 45.014,38.136 45.537,37.613 52.137,37.613 v1(52.35,37.4)
  Layer 10 w0.125: v1(52.35,37.4) 52.363,37.387 53.534,37.387 55.3,39.154 55.3,41.029 57,42.729 57,47.675 57.712,48.387 60.637,48.387 64.387,52.137 68.937,52.137 70.896,54.096 72.85,54.096 73.95,55.196 73.95,56.45 74.6,57.1 v1(74.95,57.1)
  Bottom Layer w0.15: CAD1.6@10.265,35.16 10.884,35.779 11.829,35.779 13.85,37.8 v1(14.7,37.8)
JTAG_TMS: CAD1.2 J10.2 U1.F14 | length 87
  Top Layer w0.125: v1(14.95,37.15) 15.65,37.85 15.65,39.15 ; v1(73.15,51.7) 73.5,52.05 U1.F14@73.5,52.5
  Top Layer w0.15: J10.2@12.932,40.34 15.36,40.34 15.65,40.05 15.65,39.15
  Layer 5 w0.125: v1(14.95,37.15) 15.7,37.9 22.15,37.9 24.25,40 26.3,40 27.688,41.388 29.288,41.388 30.988,39.687 32.459,39.687 34.746,37.4 36.432,37.4 36.882,37.85 44.9,37.85 45.387,37.363 51.537,37.363 51.95,36.95 v1(52.75,36.95)
  Layer 10 w0.125: v1(52.75,36.95) 53.45,36.95 55.55,39.05 55.55,40.925 57.25,42.625 57.25,47.5 57.887,48.137 60.741,48.137 64.454,51.85 69.096,51.85 69.409,52.163 72.687,52.163 v1(73.15,51.7)
  Bottom Layer w0.15: CAD1.2@11.535,38.97 12.62,38.97 13.75,40.1 15.1,40.1 15.55,39.65 15.55,37.75 v1(14.95,37.15)
JTAG_TRST_N: CAD1.9 R36.1 U1.D15 | length 118.2
  Top Layer w0.125: U1.D15@75.5,56.5 76.25,56.5 v1(76.45,56.7)
  Layer 3 w0.125: v1(8.6,41.15) 9.017,41.15 9.593,40.573 11.477,40.573 13.013,39.037 15.183,39.037 18.22,36 20.75,36 21.95,34.8 29.35,34.8 31.55,37 31.55,39.85 31.25,40.15 31.25,49.75 32.2,50.7 32.2,57.8 34.7,60.3 34.7,65.25 40.253,70.803 68.747,70.803 71.25,68.3 71.25,66.9 72.05,66.1 72.05,65.5 73.45,64.1 v1(75.95,64.1) 78.25,61.8 78.25,60.025 77.1,58.875 77.1,57.35 v1(76.45,56.7)
  Bottom Layer w0.125: v1(8.6,41.15) 8.6,39.65 9.28,38.97 CAD1.9@10.265,38.97 ; R36.1@75.23,64.45 75.6,64.45 v1(75.95,64.1)
LED1/PHYAD0: J13.D2 R53.1 R54.1 U10.17 | length 38.4
  Top Layer w0.125: v1(27.7,24.05) 27.8,24.15 29.05,24.15 30.337,25.437 30.337,28.171 31.125,28.958 U10.17@31.125,29.3
  Layer 10 w0.125: v1(15.25,7.625) 20.225,12.6 22.725,12.6 24.25,14.125 24.25,19.75 26.4,21.9 26.4,23.183 27.267,24.05 v1(27.7,24.05)
  Bottom Layer w0.125: J13.D2@12.626,3.936 15.17,6.48 R54.1@16.125,6.48 ; v1(15.25,7.625) R53.1@16.105,7.625 ; R53.1@16.125,7.625 R54.1@16.125,6.48 ; R53.1@16.125,7.645 R54.1@16.125,6.48
LED2/PHYAD1: J13.D4 R55.1 R56.1 U10.15 | length 41
  Top Layer w0.125: v1(27.1,23.3) 27.1,24.25 27.5,24.65 28.65,24.65 29.175,25.175 29.175,28.008 30.125,28.958 U10.15@30.125,29.3
  Layer 10 w0.125: v1(18.25,7.625) 18.875,8.25 18.875,10.896 20.329,12.35 22.85,12.35 24.5,14 24.5,19.646 26.65,21.796 26.65,22.85 v1(27.1,23.3)
  Bottom Layer w0.125: R55.1@17.375,7.625 R56.1@17.375,6.48 ; R55.1@17.375,7.645 R56.1@17.375,6.48 ; R55.1@17.395,7.625 v1(18.25,7.625) ; J13.D4@23.344,3.936 22.033,2.625 20.375,2.625 19.125,3.875 19.125,5.625 18.27,6.48 R56.1@17.375,6.48
LINE_IN_L: J26.4 L21.1 | length 14.6
  Top Layer w0.125: J26.4@63.625,7.625 64.8,8.8 64.8,12.575 68.375,16.15 68.375,16.95 68.575,17.15 68.575,17.55 68.3,17.825 67.95,17.825 67.5,17.375 v1(67,17.375)
  Bottom Layer w0.125: v1(67,17.375) L21.1@67,18.145
LINE_IN_R: J26.3 L20.1 | length 11.3
  Bottom Layer w0.125: J26.3@63.625,8.875 64.8,10.05 64.8,14.4 67.775,17.375 v1(68.125,17.375) L20.1@68.125,18.145
LINE_OUT_L: J26.7 L19.2 | length 16.6
  Top Layer w0.125: J26.7@63.625,3.875 65.087,5.337 65.087,12.462 68.675,16.05 68.675,16.8 v1(69.25,17.375)
  Bottom Layer w0.125: v1(69.25,17.375) L19.2@69.25,18.145
LINE_OUT_R: J26.6 L18.2 | length 18.1
  Bottom Layer w0.125: J26.6@63.625,5.125 65.087,6.587 65.087,14.187 66.6,15.7 69.7,15.7 v1(71.375,17.375) 71.375,18.02 L18.2@71.5,18.145
LVDS0_CLK_N: L33.1 U1.M4 | length 51.3
  Top Layer w0.104: L33.1@20.425,62.375 20.308,62.258 20.308,61.892 v1(20.551,61.649) ; v1(53,41.125) U1.M4@53.5,40.5
  Layer 10 w0.093: v1(20.551,61.649) 20.3,61.9 20.3,62.075 20.575,62.35 20.866,62.35 21.366,61.85 21.366,61.484 ; 21.366,61.609 21.366,61.484 ; v1(53,41.125) 52.775,41.35 52.251,41.35 51.325,42.276 51.325,46.425 49.325,48.425 49.325,52.376 47.375,54.326 47.375,57.725 45.55,59.55 26.35,59.55 25.75,60.15 21.926,60.15 21.366,60.709 21.366,61.484
LVDS0_CLK_P: L33.4 U1.L4 | length 51.7
  Top Layer w0.104: v1(19.85,61.65) 19.85,61.697 20.053,61.9 20.053,62.197 L33.4@19.875,62.375 ; v1(53,41.875) U1.L4@53.5,42.5
  Layer 10 w0.093: v1(19.85,61.65) 19.85,61.697 20,61.847 20,62.199 20.451,62.65 20.991,62.65 21.691,61.95 21.691,61.609 21.691,60.809 22.05,60.45 25.874,60.45 26.474,59.85 45.674,59.85 47.675,57.849 47.675,54.45 49.625,52.5 49.625,48.549 51.625,46.549 51.625,42.4 52.375,41.65 52.775,41.65 v1(53,41.875)
LVDS0_CONTRAST: J19.16 U1.V12 | length 110.1
  Top Layer w0.125: v1(14.4,66.7) 14.875,66.225 J19.16@14.875,65.2 ; v1(67.7,30.6) 67.7,29.583 68.783,28.5 U1.V12@69.5,28.5
  Layer 5 w0.125: v1(14.4,66.7) 16,68.3 28.9,68.3 31.35,70.75 68.175,70.75 71.525,67.4 71.525,64 71.075,63.55 67.9,63.55 65.35,61 65.35,58.463 65.763,58.05 65.763,51.62 63.987,49.845 63.987,32.554 65.179,31.363 67.321,31.363 67.7,30.983 v1(67.7,30.6)
LVDS0_I2C_SCL: J19.17 R97.2 | length 68.2
  Top Layer w0.125: J19.17@13.625,65.2 13.625,64.225 v1(14.05,63.8)
  Layer 8 w0.125: v1(14.05,63.8) 14.037,63.787 14.037,58.879 15.829,57.087 16.213,57.087 v1(19.05,54.25)
  Layer 5 w0.125: v1(19.05,54.25) 20.35,54.25 21.7,52.9 24.512,52.9 24.979,53.368 36.782,53.368 39.998,50.152 42.102,50.152 43.05,51.1 46.475,51.1 47.775,49.8 47.775,49.05 50.475,46.35 52.85,46.35 53.7,45.5 53.7,35.067 52.821,34.187 51.938,34.187 v1(50.875,35.25)
  Bottom Layer w0.125: v1(50.875,35.25) 50.875,34.645 R97.2@51.02,34.5
LVDS0_I2C_SDA: J19.18 R98.2 | length 51.2
  Top Layer w0.125: J19.18@12.375,65.2 12.463,65.287 12.463,66.413 13.35,67.3 v1(13.65,67.3)
  Layer 8 w0.125: v1(13.65,67.3) 15.85,67.3 18.35,64.8 22.7,64.8 25.014,62.486 25.014,61.05 24.187,60.223 24.187,55.413 25.7,53.9 27.25,53.9 28,53.15 v1(28,50.9)
  Layer 5 w0.125: v1(28,50.9) 38.2,50.9 39.198,49.902 42.452,49.902 42.713,50.163 44.45,50.163 45.713,48.9 v1(46.65,48.9)
  Bottom Layer w0.125: v1(46.65,48.9) 46.73,48.98 R98.2@47.5,48.98
LVDS0_IRQ_N: J19.19 R76.2 U1.M3 | length 64.6
  Top Layer w0.125: J19.19@11.125,65.2 11.125,65.925 v1(11.65,66.45) ; v1(50.5,40.5) U1.M3@51.5,40.5
  Layer 8 w0.125: v1(11.65,66.45) 11.65,63.3 12.45,62.5 12.45,58.267 18.565,52.152 19.447,52.152 20.7,50.899 v1(20.7,49.85)
  Layer 5 w0.125: v1(20.7,49.85) 21.25,50.4 38.2,50.4 40.55,48.05 41.775,48.05 45.825,44 47,44 v1(50.5,40.5)
  Bottom Layer w0.125: R76.2@8.87,62.65 8.3,63.22 8.3,65.95 8.8,66.45 v1(11.65,66.45)
LVDS0_TX0_N: L30.1 U1.J4 | length 37.4
  Top Layer w0.104: L30.1@32.025,62.375 31.9,62.25 31.9,61.9 v1(32.153,61.647) ; v1(53,47.125) 53.375,47.125 53.5,47 U1.J4@53.5,46.55
  Layer 10 w0.093: v1(32.153,61.647) 31.95,61.85 31.95,63.05 32.65,63.75 33.484,63.75 33.816,63.751 39.75,63.75 41.692,61.808 47.642,61.808 49.375,60.076 49.375,54.375 51.325,52.425 51.325,48.151 52.126,47.35 52.775,47.35 v1(53,47.125)
LVDS0_TX0_P: L30.4 U1.H4 | length 37.8
  Top Layer w0.104: v1(31.403,61.647) 31.653,61.897 31.653,62.197 L30.4@31.475,62.375 ; v1(53,47.875) U1.H4@53.5,48.5
  Layer 10 w0.093: v1(31.403,61.647) 31.65,61.894 31.65,63.174 32.526,64.05 33.359,64.05 ; 33.36,64.051 33.94,64.051 39.874,64.05 41.816,62.108 47.767,62.108 49.675,60.2 49.675,54.499 51.625,52.549 51.625,48.275 52.25,47.65 52.775,47.65 v1(53,47.875)
LVDS0_TX1_N: L31.1 U1.F4 | length 43.8
  Top Layer w0.104: L31.1@28.275,62.375 28.149,62.249 28.149,61.901 v1(28.4,61.65) ; U1.F4@53.5,52.5 v1(54,53.125)
  Layer 10 w0.093: v1(28.4,61.65) 28.15,61.9 28.15,63.35 31.825,67.025 51,67.025 51.375,66.65 51.375,54.326 52.351,53.35 53.775,53.35 v1(54,53.125)
LVDS0_TX1_P: L31.4 U1.E4 | length 44.3
  Top Layer w0.104: v1(27.65,61.65) 27.902,61.902 27.902,62.198 L31.4@27.725,62.375 ; U1.E4@53.5,54.5 v1(54,53.875)
  Layer 10 w0.093: v1(27.65,61.65) 27.85,61.85 27.85,63.474 31.701,67.325 51.124,67.325 51.675,66.774 51.675,54.45 52.475,53.65 53.775,53.65 v1(54,53.875)
LVDS0_TX2_N: L32.1 U1.C4 | length 50.7
  Top Layer w0.104: L32.1@24.525,62.375 24.35,62.2 24.35,61.9 v1(24.601,61.649) ; U1.C4@53.5,58.5 v1(54,59.125)
  Layer 10 w0.093: v1(24.601,61.649) 24.4,61.85 24.4,68.75 25.85,70.2 53.475,70.2 53.663,70.012 53.663,61.337 52.95,60.624 52.95,59.7 53.3,59.35 53.775,59.35 v1(54,59.125)
LVDS0_TX2_P: L32.4 U1.B4 | length 51.2
  Top Layer w0.104: v1(23.851,61.649) 24.103,61.9 24.103,62.247 L32.4@23.975,62.375 ; U1.B4@53.5,60.5 v1(54,59.875)
  Layer 10 w0.093: v1(23.851,61.649) 24.1,61.897 24.1,68.874 25.726,70.5 53.599,70.5 53.963,70.136 53.963,61.213 53.25,60.5 53.25,59.9 53.5,59.65 53.775,59.65 v1(54,59.875)
LVDS0_TX3_N: L34.1 U1.R4 | length 58.7
  Top Layer w0.104: L34.1@17.025,62.375 16.9,62.25 16.9,61.9 17.1,61.7 v1(17.1,61.65) ; v1(53,35.125) U1.R4@53.5,34.5
  Layer 10 w0.093: v1(17.1,61.65) 17.1,61.7 17,61.8 17,62.175 17.075,62.25 17.35,62.25 17.6,62 17.6,61.55 17.497,61.447 17.497,60.654 17.75,60.4 19.376,60.4 20.226,59.55 21.676,59.55 22.076,59.15 25.426,59.15 26.276,58.3 42.532,58.3 44.108,56.724 44.565,56.724 45.35,55.939 45.35,52.401 47.375,50.376 47.375,48.451 49.2,46.626 49.2,42.626 51.05,40.776 51.05,36.15 51.85,35.35 52.775,35.35 v1(53,35.125)
LVDS0_TX3_P: L34.4 U1.P4 | length 59.2
  Top Layer w0.104: v1(16.401,61.649) 16.645,61.892 16.645,62.205 L34.4@16.475,62.375 ; v1(53,35.875) U1.P4@53.5,36.5
  Layer 10 w0.093: v1(16.401,61.649) 16.688,61.935 16.688,62.287 16.951,62.55 17.474,62.55 17.9,62.124 17.9,61.426 17.796,61.322 17.796,60.854 17.95,60.7 19.5,60.7 20.35,59.85 21.8,59.85 22.2,59.45 25.55,59.45 26.4,58.6 42.656,58.6 44.232,57.024 44.689,57.024 45.65,56.063 45.65,52.525 47.675,50.5 47.675,48.575 49.5,46.75 49.5,42.75 51.35,40.9 51.35,36.4 52.1,35.65 52.775,35.65 v1(53,35.875)
LVDS1_CLK_N: L42.1 U1.E1 | length 34.4
  Top Layer w0.104: v1(47,53.875) U1.E1@47.5,54.5
  Layer 5 w0.093: v1(23.676,54.05) 23.85,54.225 23.85,54.524 24.176,54.85 24.924,54.85 25.574,54.2 44.875,54.2 45.425,53.65 46.775,53.65 v1(47,53.875)
  Layer 3 w0.093: v1(22.5,61.4) 22.675,61.225 22.675,58.701 23.85,57.526 23.85,54.225 v1(23.676,54.05)
  Bottom Layer w0.104: v1(22.5,61.4) 22.575,61.4 22.602,61.427 22.602,61.652 22.745,61.795 22.745,62.255 L42.1@22.625,62.375
LVDS1_CLK_P: L42.4 U1.F1 | length 34.1
  Top Layer w0.104: v1(47,53.125) 47.425,53.125 47.5,53.05 U1.F1@47.5,52.5
  Layer 5 w0.093: v1(24.325,54.05) 24.15,54.225 24.15,54.4 24.3,54.55 24.8,54.55 25.45,53.9 44.751,53.9 45.301,53.35 46.775,53.35 v1(47,53.125)
  Layer 3 w0.093: v1(23.15,61.4) 22.975,61.225 22.975,58.825 24.15,57.65 24.15,54.225 v1(24.325,54.05)
  Bottom Layer w0.104: 23,61.828 23.177,61.652 23.177,61.427 v1(23.15,61.4) ; 23,61.828 23,62.2 L42.4@23.175,62.375
LVDS1_CONTRAST: J31.16 U1.V13 | length 180.8
  Top Layer w0.125: U1.V13@71.5,28.5 v1(72.125,29.125)
  Layer 5 w0.125: v1(28.4,66.723) 27.727,66.05 24.6,66.05 21.113,62.563 8.437,62.563 5.15,65.85 1.646,65.85 1.1,65.304 1.1,45.95 0.85,45.7 0.85,28.45 3.55,25.75 13.25,25.75 14.15,24.85 14.15,23.35 15.6,21.9 17.85,21.9 20.7,19.05 24.686,19.05 26.586,17.15 29.289,17.15 31.089,15.35 36.625,15.35 37.275,16 37.65,16.375 43.875,16.375 47.375,12.875 47.375,5.896 49.071,4.2 58.896,4.2 59.104,4.2 60.288,5.384 60.288,9.82 62.618,12.15 64.507,12.15 65.782,10.875 v1(70.25,10.875)
  Layer 3 w0.125: v1(70.25,10.875) 70.25,14.375 70.875,15 70.875,18.375 71.5,19 71.5,24.25 72.125,24.875 v1(72.125,29.125)
  Bottom Layer w0.125: v1(28.4,66.723) 28.625,66.498 J31.16@28.625,65.2
LVDS1_I2C_SCL: J31.17 R298.2 | length 1.9
  Bottom Layer w0.101: R298.2@29.85,63.36 29.85,65.175 J31.17@29.875,65.2
LVDS1_I2C_SDA: J31.18 R299.2 | length 1.9
  Bottom Layer w0.15: R299.2@31.1,63.36 31.1,65.175 J31.18@31.125,65.2
LVDS1_IRQ_N: J31.19 R118.2 U1.AC20 | length 185
  Top Layer w0.125: v1(85.2,19.15) 85.5,18.85 U1.AC20@85.5,18.5
  Layer 5 w0.125: v1(30.8,67.225) 30.8,67.217 29.383,65.8 24.704,65.8 21.216,62.313 8.037,62.313 4.75,65.6 2.029,65.6 1.35,64.921 1.35,45.846 1.1,45.596 1.1,28.554 3.654,26 13.354,26 14.4,24.954 14.4,23.489 15.727,22.163 21.927,22.163 26.689,17.4 29.393,17.4 31.193,15.6 36.521,15.6 37.171,16.25 37.546,16.625 44,16.625 47.625,13 47.625,6 49.175,4.45 59,4.45 60.038,5.488 60.038,9.923 62.514,12.4 64.611,12.4 65.861,11.15 68.2,11.15 68.6,11.55 76.944,11.55 84.544,19.15 v1(85.2,19.15)
  Bottom Layer w0.125: v1(30.8,67.225) 31.675,67.225 32.375,66.525 J31.19@32.375,65.2 32.35,65.175 R118.2@32.35,63.36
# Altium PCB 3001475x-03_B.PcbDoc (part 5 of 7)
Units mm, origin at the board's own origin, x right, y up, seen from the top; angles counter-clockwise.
Board outline 100 x 72 mm, 12 copper layers (Top Layer, L2 GND, Layer 3, L4 GND, Layer 5, L6 PWR, L7 3V3, Layer 8, L9 GND, Layer 10, L11 GND, Bottom Layer), stack 1.735 mm thick; 431 components, 499 nets, 1977 pads, 1473 vias.

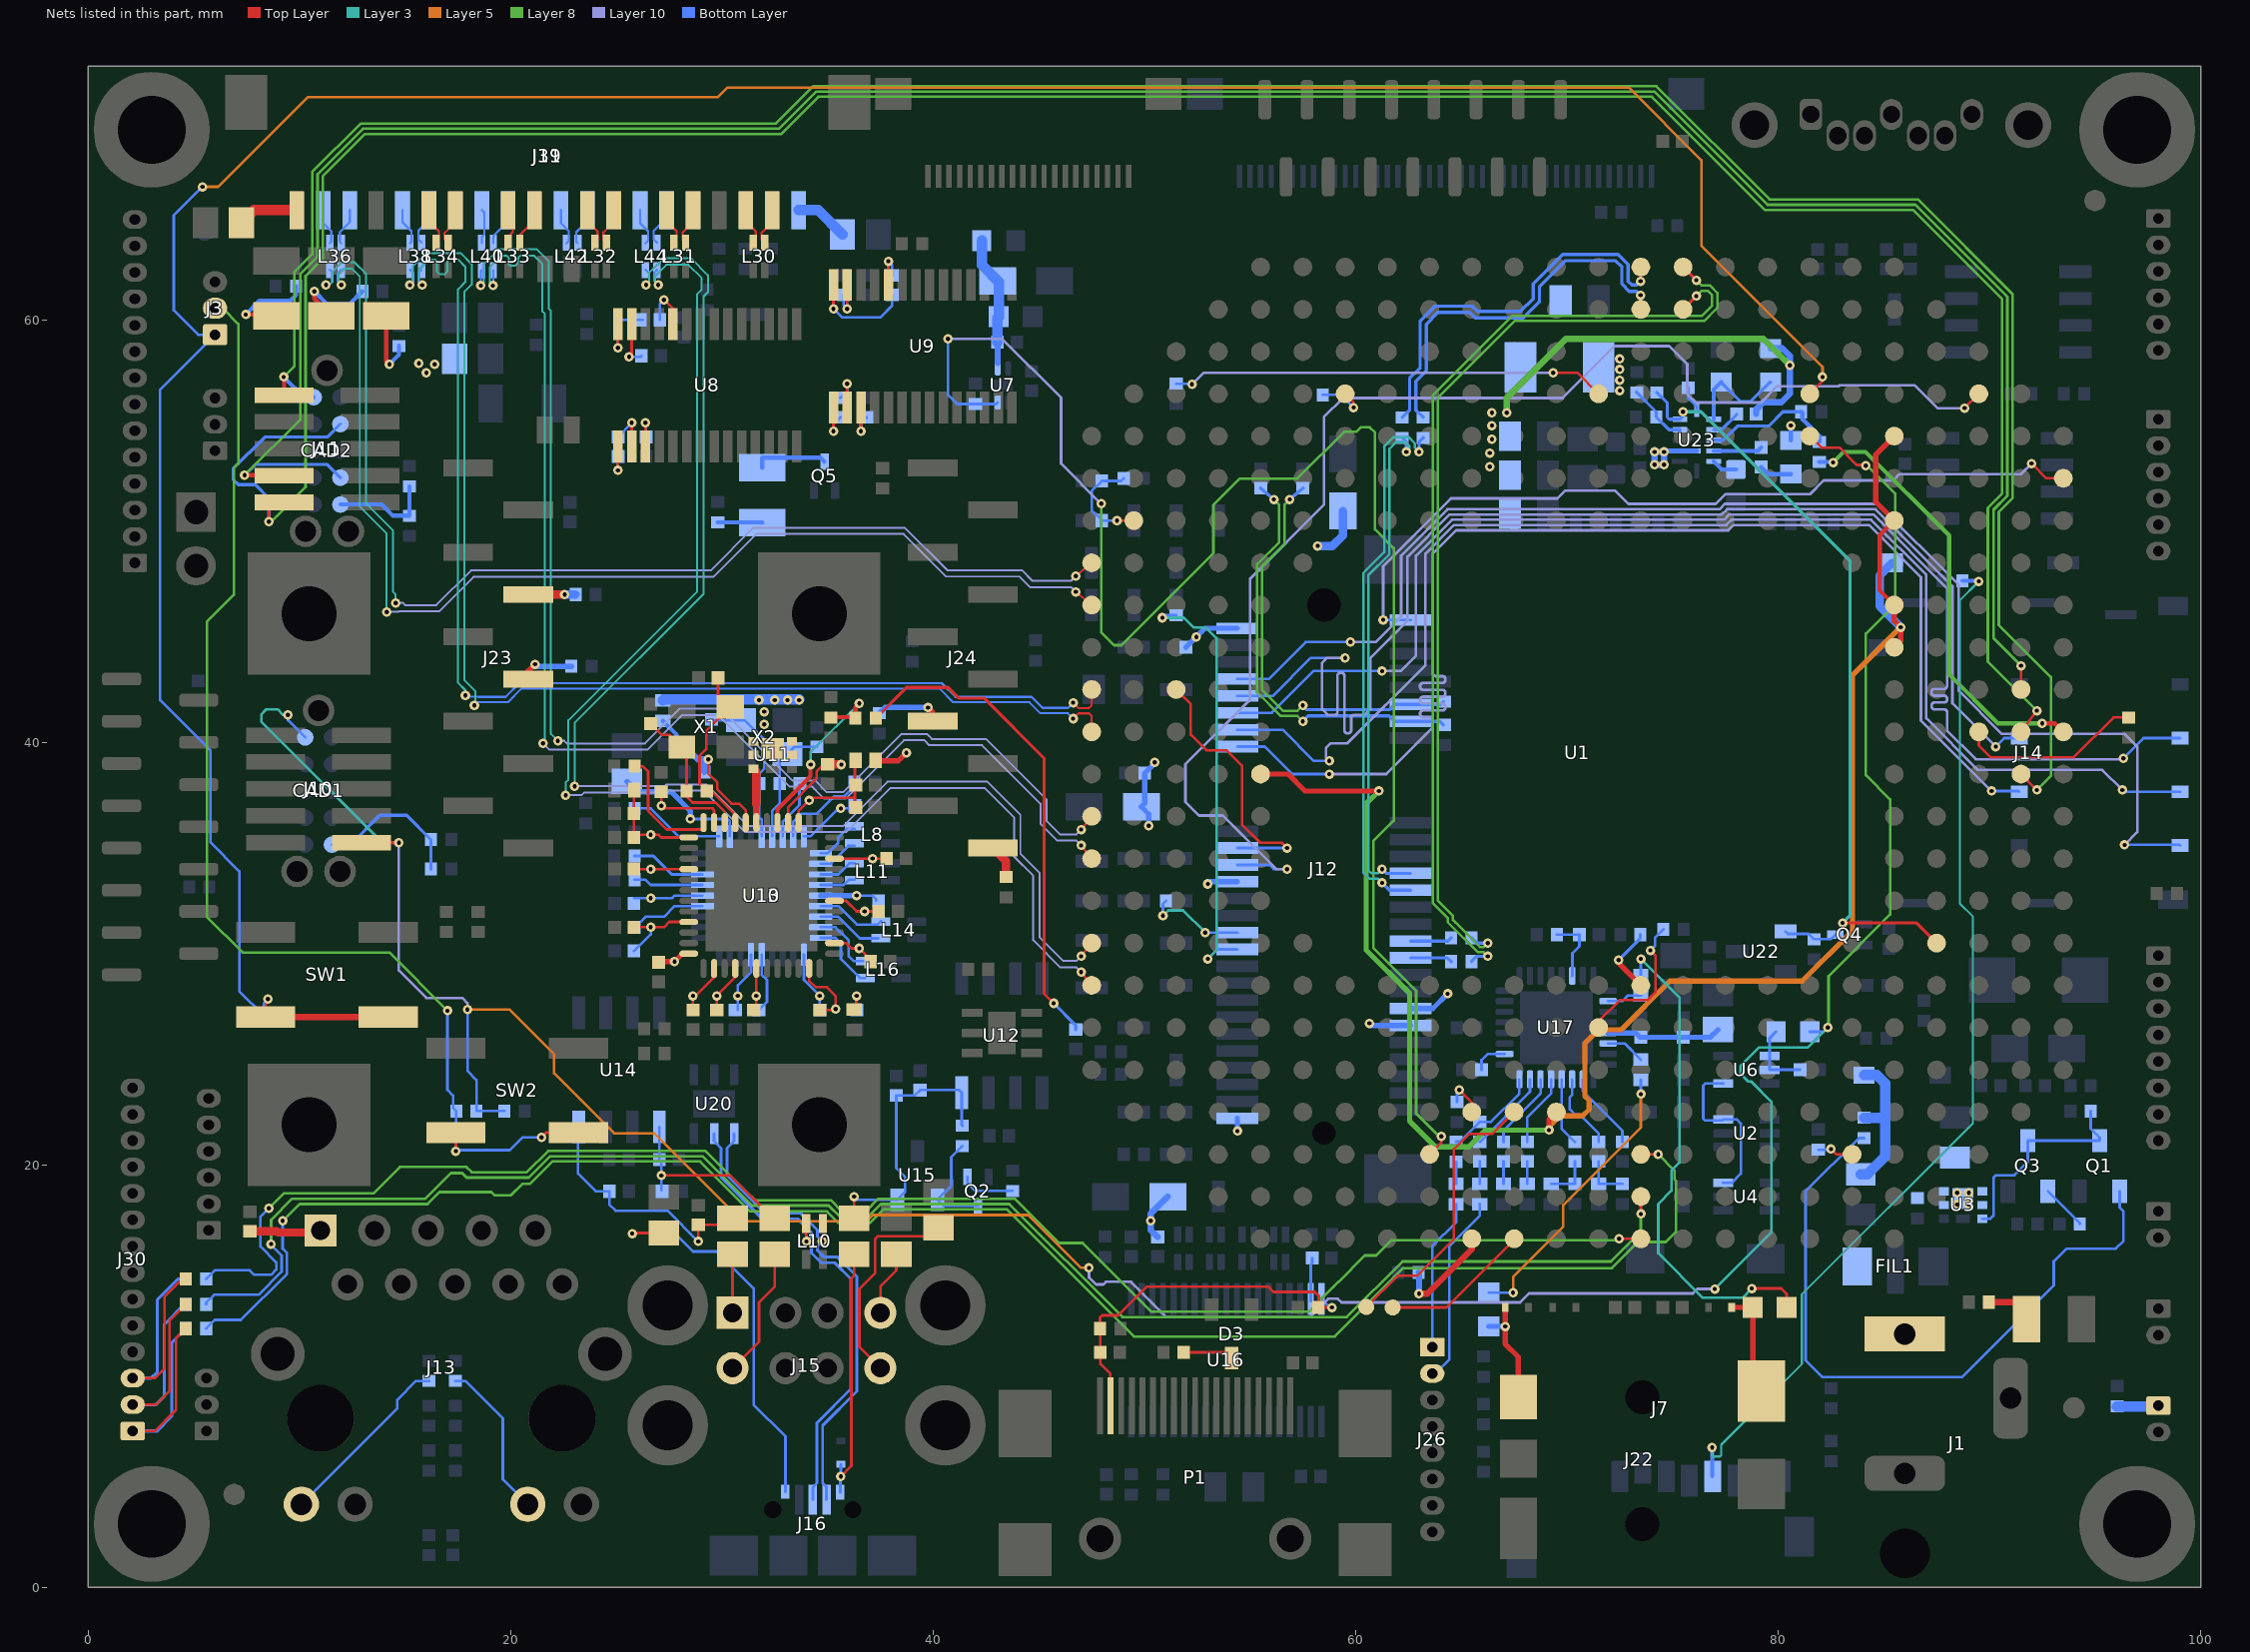
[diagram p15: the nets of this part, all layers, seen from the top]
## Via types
v1: diameter 0.45, hole 0.2, Top Layer to Bottom Layer, tented both sides, 1473 vias

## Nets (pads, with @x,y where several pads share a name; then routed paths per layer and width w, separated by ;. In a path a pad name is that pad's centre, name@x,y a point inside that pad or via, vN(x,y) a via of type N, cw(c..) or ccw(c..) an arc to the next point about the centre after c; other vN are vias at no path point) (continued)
LVDS1_TX0_N: L36.1 U1.H1 | length 55.6
  Top Layer w0.104: v1(46.75,47.875) U1.H1@47.5,48.5
  Layer 10 w0.093: v1(14.55,46.6) 14.9,46.6 15,46.5 16.475,46.5 18.111,48.136 29.462,48.136 31.489,50.163 38.65,50.163 40.663,48.15 44.199,48.15 44.699,47.65 46.525,47.65 v1(46.75,47.875)
  Layer 3 w0.093: v1@11.402,61.652 11.539,61.789 11.539,62.264 12.002,62.727 12.602,62.727 13.15,62.178 13.15,51.3 14.425,50.025 14.425,47.125 14.55,47 v1(14.55,46.6)
  Bottom Layer w0.104: v1@11.402,61.652 11.552,61.802 11.552,62.248 L36.1@11.425,62.375
  other v1: 11.252,61.652
LVDS1_TX0_P: L36.4 U1.J1 | length 55.4
  Top Layer w0.104: v1(46.75,47.125) U1.J1@47.5,46.5
  Layer 10 w0.093: v1(14.125,46.175) 14.675,46.175 14.7,46.2 16.599,46.2 18.235,47.836 29.586,47.836 31.613,49.863 38.6,49.863 40.613,47.85 44.075,47.85 44.575,47.35 46.525,47.35 v1(46.75,47.125)
  Layer 3 w0.093: v1(11.977,61.652) 11.839,61.789 11.839,62.139 12.127,62.427 12.477,62.427 12.85,62.054 12.85,51.15 14.125,49.875 v1(14.125,46.175)
  Bottom Layer w0.104: 11.8,61.828 11.8,62.2 L36.4@11.975,62.375 ; 11.8,61.828 v1(11.977,61.652)
LVDS1_TX1_N: L38.1 U1.M1 | length 57.4
  Top Layer w0.104: v1(46.625,41.125) 46.872,41.373 47.375,41.373 47.5,41.247 U1.M1@47.5,40.5
  Layer 3 w0.093: v1(15.225,61.65) 15.363,61.788 15.363,62.524 16.001,63.162 17.624,63.162 18.15,62.637 18.15,61.676 17.796,61.322 17.796,42.95 17.9,42.846 18.324,42.422 18.324,41.799 v1(18.275,41.75)
  Bottom Layer w0.104: v1(15.225,61.65) 15.376,61.801 15.376,62.224 L38.1@15.225,62.375 ; v1(18.275,41.75) 18.424,41.899 19.856,41.899 20.508,42.55 40.292,42.55 40.944,41.899 44.552,41.899 45.073,41.378 46.372,41.378 v1(46.625,41.125)
LVDS1_TX1_P: L38.4 U1.L1 | length 57.4
  Top Layer w0.104: v1(46.625,41.875) 46.872,41.628 47.375,41.628 47.5,41.753 U1.L1@47.5,42.5
  Layer 3 w0.093: v1(15.8,61.65) 15.663,61.787 15.663,62.4 16.125,62.862 16.425,62.862 16.5,62.787 16.5,62.287 16.625,62.162 16.875,62.162 17,62.287 17,62.787 17.075,62.862 17.5,62.862 17.85,62.512 17.85,61.8 17.497,61.447 17.497,42.825 17.85,42.472 v1(17.85,42.225)
  Bottom Layer w0.104: 15.624,61.826 v1(15.8,61.65) ; 15.623,61.827 15.623,62.223 L38.4@15.775,62.375 ; v1(17.85,42.225) 17.906,42.169 18.449,42.169 18.464,42.154 19.751,42.154 20.402,42.805 40.398,42.805 41.049,42.154 44.658,42.154 45.178,41.633 46.383,41.633 v1(46.625,41.875)
LVDS1_TX2_N: L40.1 U1.P1 | length 60.2
  Top Layer w0.104: v1(47,35.875) U1.P1@47.5,36.5
  Layer 10 w0.093: v1(22.225,40.075) 22.525,40.075 22.65,39.95 26.351,39.95 28.001,41.6 29.925,41.6 31.125,40.4 33.325,38.2 34.4,38.2 34.961,37.639 35.731,37.639 38.491,40.4 39.7,40.4 ; 39.788,40.312 39.7,40.4 ; v1(47,35.875) 46.775,35.65 46,35.65 45.375,36.275 45.375,37.275 42.486,40.164 39.936,40.164 39.7,40.4
  Layer 3 w0.093: v1(18.578,61.625) 18.716,61.763 18.716,62.624 19.429,63.338 20.877,63.338 21.237,63.338 21.8,62.774 21.8,60.524 21.9,60.424 21.9,40.4 v1(22.225,40.075)
  Bottom Layer w0.104: v1(18.578,61.625) 18.578,62.303 L40.1@18.625,62.35
LVDS1_TX2_P: L40.4 U1.R1 | length 60.5
  Top Layer w0.104: v1(47,35.125) U1.R1@47.5,34.5
  Layer 10 w0.093: v1(21.525,39.95) 21.825,39.65 26.475,39.65 28.125,41.3 29.801,41.3 31.001,40.1 33.201,37.9 34.276,37.9 34.836,37.339 35.855,37.339 38.616,40.1 39.576,40.1 39.812,39.864 42.311,39.864 45.075,37.1 45.075,36.151 45.876,35.35 46.775,35.35 v1(47,35.125)
  Layer 3 w0.093: v1(19.153,61.625) 19.016,61.763 19.016,62.5 19.553,63.038 19.813,63.038 19.9,62.95 19.9,62.65 19.987,62.563 20.213,62.563 20.35,62.7 20.35,62.95 20.438,63.038 20.753,63.038 21.113,63.038 21.5,62.65 21.5,60.4 21.6,60.3 21.6,40.025 v1(21.525,39.95)
  Bottom Layer w0.104: v1(19.153,61.625) 19.175,61.647 L40.4@19.175,62.35
LVDS1_TX3_N: L44.1 U1.U1 | length 64.7
  Top Layer w0.104: v1(47,29.875) U1.U1@47.5,30.5
  Layer 10 w0.093: v1(23.025,37.925) 27.276,37.925 27.364,38.013 29.261,38.013 31.224,36.05 35.75,36.05 37.836,38.136 42.563,38.136 44.125,36.574 44.125,34.725 45.038,33.812 45.038,30.761 46.149,29.65 46.775,29.65 v1(47,29.875)
  Layer 3 w0.093: v1(23.025,37.925) 23.025,40.925 29.125,47.025 29.125,61.1 29.338,61.313 29.338,62.112 28.537,62.912 27.238,62.912 26.539,62.213 26.539,61.789 v1(26.402,61.652)
  Bottom Layer w0.104: L44.1@26.375,62.375 26.552,62.198 26.552,61.802 v1(26.402,61.652)
LVDS1_TX3_P: L44.4 U1.V1 | length 64.6
  Top Layer w0.104: v1(47,29.125) U1.V1@47.5,28.5
  Layer 10 w0.093: v1(22.6,37.5) 23.35,37.5 23.475,37.625 27.4,37.625 27.488,37.713 29.137,37.713 31.1,35.75 35.874,35.75 37.96,37.836 42.439,37.836 43.825,36.45 43.825,34.601 44.738,33.688 44.738,30.637 46.025,29.35 46.775,29.35 v1(47,29.125)
  Layer 3 w0.093: v1(22.6,37.5) 22.6,38.1 22.725,38.225 22.725,41.049 28.825,47.149 28.825,61.224 29.038,61.437 29.038,61.988 28.413,62.612 27.362,62.612 26.839,62.089 26.839,61.789 v1(26.977,61.652)
  Bottom Layer w0.104: 26.8,61.828 26.8,62.25 L44.4@26.925,62.375 ; 26.8,61.828 v1(26.977,61.652)
MCA_RESET_N: CAD2.10 J11.10 U1.N23 | length 125.3
  Top Layer w0.125: U1.N23@91.5,38.5 v1(92.25,37.75)
  Top Layer w0.2: v1(9.25,57.3) 9.268,57.282 J11.10@9.268,56.44
  Layer 8 w0.125: v1(9.25,57.3) 9.75,57.8 9.75,62.25 10.6,63.1 10.6,67 12.9,69.3 32.55,69.3 34.313,71.063 74.235,71.063 79.598,65.7 86.607,65.7 91.1,61.207 91.1,51.564 90.45,50.914 90.45,45.55 92.913,43.087 92.913,38.413 v1(92.25,37.75)
  Bottom Layer w0.2: v1(9.25,57.3) 10.21,56.34 CAD2.10@10.665,56.34
MCA_SWD_CLK: CAD2.4 J11.4 U1.L23 | length 127.6
  Top Layer w0.125: U1.L23@91.5,42.5 v1(91.5,43.625)
  Top Layer w0.2: v1(7.4,52.65) 9.248,52.65 J11.4@9.268,52.63
  Layer 8 w0.125: v1(7.4,52.65) 10.037,55.287 10.037,62.184 10.85,62.996 10.85,66.896 13.004,69.05 32.7,69.05 34.463,70.813 74.132,70.813 79.494,65.45 86.504,65.45 90.85,61.104 90.85,51.668 90.2,51.018 90.2,44.925 v1(91.5,43.625)
  Bottom Layer w0.15: v1(7.4,52.65) 7.9,53.15 11.315,53.15 CAD2.4@11.935,52.53
MCA_SWD_DIO: CAD2.2 J11.2 U1.M23 | length 135.7
  Top Layer w0.125: v1(8.55,50.45) 8.55,51.36 J11.2@9.268,51.36 ; U1.M23@91.5,40.5 v1(92.25,41.5)
  Layer 8 w0.125: v1(8.55,50.45) 8.65,50.45 10.287,52.087 10.287,62.08 11.1,62.893 11.1,66.793 13.107,68.8 32.804,68.8 34.566,70.563 74.028,70.563 79.39,65.2 86.4,65.2 90.6,61 90.6,51.771 89.925,51.096 89.925,43.825 v1(92.25,41.5)
  Bottom Layer w0.15: v1(8.55,50.45) 8.55,51.55 7.9,52.2 7.1,52.2 6.85,52.45 6.85,52.95 8.35,54.45 11.315,54.45 CAD2.2@11.935,55.07
MIC_BIAS: J26.1 L23.1 | length 7.2
  Bottom Layer w0.125: J26.1@63.625,11.375 63.625,16.15 64.75,17.275 L23.1@64.75,18.145
MIC_IN: J26.2 L22.1 | length 8.9
  Bottom Layer w0.125: J26.2@63.765,10.125 64.44,10.8 64.44,16.165 65.875,17.6 L22.1@65.875,18.145
NetC4_2: C4.2 R15.2 U6.1 U6.2 | length 3.4
  Bottom Layer w0.15: R15.2@79.9,26.3 79.6,26 U6.1@79.6,25.15 U6.2@79.6,24.5 C4.2@81.04,24.5
NetC8_2: C8.2 C9.1 C10.2 R21.1 U7.1 | length 6.2
  Bottom Layer w0.27: U7.1@43.05,57.96 C10.2@43.05,58.94
  Bottom Layer w0.3: C10.2@43.04,58.95 C10.2@43.05,58.94
  Bottom Layer w0.5: R21.1@42.3,63.75 42.3,62.6 C9.1@43.05,61.85 43.1,61.8 C8.2@43.1,60.15 43.04,60.09 C10.2@43.04,58.95
NetC18_1: C18.1 U8.24 | length 2.3
  Top Layer w0.125: v1(27.25,60.95) 27.675,60.525 U8.24@27.675,59.805
  Bottom Layer w0.125: C18.1@27.06,60 27.06,60.76 v1(27.25,60.95)
NetC18_2: C18.2 U8.28 | length 3.5
  Top Layer w0.125: v1(25.075,58.68) U8.28@25.075,59.805
  Bottom Layer w0.125: v1(25.075,58.68) 25.075,59.825 25.25,60 C18.2@26.24,60
NetC19_1: C19.1 U8.27 | length 2.2
  Top Layer w0.125: v1(25.6,58.25) 25.725,58.375 U8.27@25.725,59.805
  Bottom Layer w0.125: v1(25.6,58.25) 26.14,58.25 C19.1@26.19,58.3
NetC20_1: C20.1 U9.24 | length 1.9
  Top Layer w0.125: U9.24@37.875,61.65 v1(37.875,62.775)
  Bottom Layer w0.125: v1(37.875,62.775) 38.05,62.6 C20.1@38.05,62.11
NetC20_2: C20.2 U9.28 | length 4.8
  Top Layer w0.125: v1(35.275,60.525) U9.28@35.275,61.65
  Bottom Layer w0.125: v1(35.275,60.525) 35.688,60.112 37.487,60.112 38.05,60.675 C20.2@38.05,61.19
NetC21_1: C21.1 U9.27 | length 1.9
  Top Layer w0.125: v1(35.925,60.525) U9.27@35.925,61.65
  Bottom Layer w0.125: C21.1@35.75,61.19 35.75,60.7 v1(35.925,60.525)
NetC22_1: C22.1 U8.2 | length 2.1
  Top Layer w0.125: U8.2@25.725,54.005 v1(25.725,55.13)
  Bottom Layer w0.125: C22.1@25.075,54.46 25.725,55.11 v1(25.725,55.13)
NetC22_2: C22.2 U8.1 | length 1.8
  Top Layer w0.125: v1(25.075,52.88) U8.1@25.075,54.005
  Bottom Layer w0.125: v1(25.075,52.88) C22.2@25.075,53.54
NetC23_1: C23.1 U9.2 | length 1.9
  Top Layer w0.125: U9.2@35.925,55.85 v1(35.925,56.975)
  Bottom Layer w0.125: C23.1@35.6,56.31 35.925,56.635 v1(35.925,56.975)
NetC23_2: C23.2 U9.1 | length 1.9
  Top Layer w0.125: v1(35.275,54.725) U9.1@35.275,55.85
  Bottom Layer w0.125: v1(35.275,54.725) 35.275,55.065 C23.2@35.6,55.39
NetC24_2: C24.2 U8.3 | length 1.8
  Top Layer w0.125: U8.3@26.375,54.005 v1(26.375,55.13)
  Bottom Layer w0.125: v1(26.375,55.13) 26.4,55.105 C24.2@26.4,54.46
NetC25_2: C25.2 U9.3 | length 1.9
  Top Layer w0.125: v1(36.575,54.725) U9.3@36.575,55.85
  Bottom Layer w0.125: v1(36.575,54.725) 36.575,55.115 C25.2@36.85,55.39
NetC28_2: C28.2 R39.2 U10.46 X1.1 | length 7
  Top Layer w0.125: C28.2@26.625,40.89 27.165,40.35 27.525,40.35 X1.1@28.1,39.775 28.32,39.555 R39.2@28.32,37.7 28.32,37.43 28.6,37.15 29.693,37.15 30.125,36.718 U10.46@30.125,36.2
NetC29_2: C29.2 J13.1 | length 3.4
  Top Layer w0.4: C29.2@7.65,16.865 8.907,16.865 8.972,16.8 10.91,16.8 J13.1@11,16.89
NetC30_2: C30.2 R39.1 U10.45 X1.3 | length 8.5
  Top Layer w0.125: C30.2@29.81,43.05 29.81,42.265 X1.3@30.4,41.675 29.25,40.525 29.25,39.683 28.938,39.371 28.938,38.042 R39.1@29.28,37.7 29.496,37.7 30.609,36.588 30.625,36.588 U10.45@30.625,36.2
NetC42_2: C42.2 C43.2 C44.2 C45.2 L2.2 U10.1 U10.12 U10.47 | length 10.3
  Top Layer w0.125: C45.2@25.835,35.5 C42.2@25.835,36.625 L2.2@25.835,37.855 ; C45.2@25.96,35.625 v1(26.625,35.625) 27,35.625 27.125,35.5 U10.1@28.425,35.5 ; C44.2@27.125,37.665 v1(27.125,37.002) 27.253,36.875 29.551,36.875 29.625,36.801 U10.47@29.625,36.2
  Top Layer w0.25: C43.2@27.04,29.625 v1(27.75,29.625) 28.125,30 U10.12@28.425,30
NetC46_2: C46.2 C47.2 C48.2 C49.2 L3.1 U10.16 U10.34 U10.40 | length 12.3
  Top Layer w0.125: C46.2@29.75,27.335 v1(29.75,28) 30.625,28.875 U10.16@30.625,29.3 ; U10.40@33.125,36.2 33.125,36.925 34.478,38.278 34.478,38.627 34.81,38.96 C47.2@34.9,38.96 ; L3.1@36.25,27.355 36.375,27.48 v1(36.375,28) ; C48.2@37.79,34.5 v1(37.125,34.5) ; v1(37.125,34.5) U10.34@35.325,34.5 v1(37.125,34.5)
  Top Layer w0.4: C47.2@34.9,38.96 35.64,38.96 v1(35.65,38.95)
  Bottom Layer w0.125: C49.2@36.375,27.335 v1(36.375,28)
NetC50_2: C50.2 C51.2 C52.2 C53.2 C54.2 C55.2 C56.2 L4.1 U10.14 U10.18 U10.23 U10.26 U10.30 U10.39 | length 17.7
  Top Layer w0.125: C50.2@28.625,27.335 28.625,27.875 29.625,28.875 U10.14@29.625,29.3 ; C51.2@31.625,27.46 v1(31.625,28) U10.18@31.625,29.3 ; U10.39@33.625,36.2 33.625,36.75 v1(34.125,37.25) 34.25,37.375 36.29,37.375 ; U10.23@34.125,29.3 34.125,28.725 34.437,28.413 34.962,28.413 35.375,28 v1(35.375,27.375) 35.375,27.335 C52.2@34.625,27.335 ; U10.26@35.325,30.5 35.875,30.5 36.125,30.25 v1(36.5,30.25) C53.2@37.04,29.71 ; U10.30@35.325,32.5 35.875,32.5 36.375,32 v1(36.75,32) C54.2@37.165,32 ; C56.2@36.29,36.875 36.29,37.375 ; L4.1@36.29,39.25 36.29,37.375
  other v1: 28.625,28
NetC60_2: C60.2 C61.2 L5.2 U10.44 | length 7.6
  Top Layer w0.125: v1(29.35,39.2) 29.35,38.526 29.778,38.098 29.778,37.773 30.45,37.1 30.8,37.1 31.125,36.775 U10.44@31.125,36.2
  Bottom Layer w0.2: L5.2@27.2,41.02 27.2,41.014 27.85,40.364 27.85,40.21 C60.2@28.16,39.9
  Bottom Layer w0.3: C60.2@28.16,39.9 28.86,39.2 v1(29.35,39.2) 29.16,39.01 C61.2@29.16,38.6
NetC63_1: C63.1 R67.1 U13.32 X2.3 | length 7.6
  Bottom Layer w0.125: C63.1@29.535,41.05 X2.3@30.9,41.05 31.075,41.05 32,40.125 32,38.75 31.75,38.5 31.75,36.475 31.875,36.35 U13.32@31.875,35.55
NetC64_1: C64.1 R67.2 U13.33 X2.1 | length 5.7
  Bottom Layer w0.125: U13.33@32.375,35.55 32.375,36.75 32.73,37.105 32.73,39.08 X2.1@33.1,39.45 33.44,39.79 C64.1@34.5,39.79
NetC66_2: C66.2 C67.2 L9.2 R72.1 U12.8 U15.S | length 13.2
  Top Layer w0.125: L9.2@36.25,17.475 v1(36.25,18.5)
  Bottom Layer w0.125: v1(36.25,18.5) 36.4,18.35 U15.S@38.3,18.35 38.663,18.713 38.663,19.437 38.25,19.85 C67.2@38.25,23.29 39.125,23.29 C66.2@39.375,23.54 41.23,23.54 U12.8@41.345,23.425 41.345,21.885 R72.1@41.375,21.855
NetC68_2: C68.2 C71.2 L7.2 U14.8 | length 11.7
  Top Layer w0.125: v1(28.875,16.375) C71.2@28.875,17.165 L7.2@30.19,17.165
  Bottom Layer w0.125: U14.8@23.22,21.8 23.187,21.767 23.187,19.579 24.017,18.75 C68.2@24.665,18.75 24.665,18.125 24.955,17.835 27.415,17.835 v1(28.875,16.375)
NetC69_2: C69.2 C70.2 L6.2 U14.5 | length 9.1
  Top Layer w0.125: v1(27.125,19.5) 30.375,19.5 32.4,17.475 L6.2@32.5,17.475
  Bottom Layer w0.125: C70.2@27.03,20.26 U14.5@27.03,21.8 ; C69.2@27.125,18.79 v1(27.125,19.5) C70.2@27.125,20.165
NetC72_2: C72.2 C73.2 C74.2 C75.2 C76.2 C77.2 L17.1 U13.5 U13.10 U13.15 U13.23 U13.29 U13.36 | length 21.4
  Bottom Layer w0.125: C77.2@25.835,32.625 v1(26.625,32.625) 27.625,32.625 27.75,32.75 U13.23@29.075,32.75 ; v1(28.5,36.375) 30.25,36.375 30.375,36.25 U13.29@30.375,35.55 ; C73.2@30.75,27.335 v1(30.75,28) 30.75,28.5 31.375,29.125 U13.15@31.375,29.95 ; U13.10@33.875,29.95 33.875,28.75 v1(34.625,28) C74.2@34.625,27.335 ; U13.36@33.875,35.55 34.175,35.55 35.5,36.875 v1(35.625,36.875) C76.2@36.29,36.875 ; v1(36.375,32.75) 37.125,32.75 37.29,32.585 C75.2@37.29,32.5
  Bottom Layer w0.25: L17.1@25.5,38.15 25.985,37.665 C72.2@27.125,37.665 27.585,37.665 28.5,36.75 v1(28.5,36.375) ; U13.5@34.675,32.75 v1(36.375,32.75)
NetC78_2: C78.2 U13.14 | length 2.9
  Bottom Layer w0.125: C78.2@31.75,27.335 32.125,27.71 32.125,28.75 31.875,29 U13.14@31.875,29.95
NetC79_2: C79.2 U13.34 | length 2.8
  Bottom Layer w0.125: U13.34@32.875,35.55 32.875,36.25 33.665,37.04 C79.2@33.665,38
NetC84_2: C84.2 U16.37 | length 2.1
  Bottom Layer w0.138: U16.37@57.875,13.55 U16.37@57.875,13.65 57.875,15.275 57.94,15.34 C84.2@57.94,15.6
NetC86_2: C86.2 P1.18 R85.2 R87.2 U16.38 | length 17.5
  Top Layer w0.125: R85.2@47.895,12.25 47.895,12.77 48,12.875 48.75,12.875 50.112,14.237 55.851,14.237 56.101,13.987 58.071,13.987 58.25,13.809 58.25,13.27 R87.2@58.23,13.25 v1(58.875,13.25) ; R85.2@47.915,12.25 C86.2@47.915,11.125 47.915,10.585 48.375,10.125 P1.18@48.375,8.5
  Bottom Layer w0.125: U16.38@58.375,13.65 58.775,13.25 v1(58.875,13.25)
NetC87_1: C87.1 U17.11 | length 3.7
  Bottom Layer w0.125: U17.11@70.25,24.05 70.25,23.313 70.137,23.2 70.137,22.629 70.379,22.387 70.613,22.387 71.5,21.5 C87.1@71.5,21.085
NetC87_2: C87.2 L18.1 R92.2 | length 2.2
  Bottom Layer w0.125: C87.2@71.5,20.165 L18.1@71.5,19.105 R92.2@72.625,19.105
NetC88_1: C88.1 U17.12 | length 3.2
  Bottom Layer w0.125: U17.12@69.75,24.05 69.75,21.71 C88.1@70.375,21.085
NetC88_2: C88.2 L19.1 R91.2 | length 2.2
  Bottom Layer w0.125: L19.1@69.25,19.105 R91.2@70.375,19.105 C88.2@70.375,20.165
NetC89_2: C89.2 U17.18 | length 1.7
  Bottom Layer w0.125: C89.2@65.96,24.5 65.96,24.96 66.25,25.25 U17.18@67.05,25.25
NetC90_2: C90.2 U17.10 | length 3.7
  Bottom Layer w0.125: U17.10@70.75,24.05 70.75,23.5 72.625,21.625 C90.2@72.625,21.085
NetC91_1: C91.1 L20.2 | length 1.1
  Bottom Layer w0.125: L20.2@68.125,19.105 C91.1@68.125,20.165
NetC91_2: C91.2 U17.13 | length 3.4
  Bottom Layer w0.125: C91.2@68.125,21.085 68.125,22.25 69.25,23.375 U17.13@69.25,24.05
NetC92_1: C92.1 L21.2 | length 1.1
  Bottom Layer w0.125: L21.2@67,19.105 C92.1@67,20.165
NetC92_2: C92.2 U17.14 | length 3.7
  Bottom Layer w0.125: C92.2@67,21.085 67,21.625 68.75,23.375 U17.14@68.75,24.05
NetC93_1: C93.1 L22.2 | length 1.1
  Bottom Layer w0.125: L22.2@65.875,19.105 C93.1@65.875,20.165
NetC93_2: C93.2 U17.15 | length 3.9
  Bottom Layer w0.125: C93.2@65.875,21.085 68.25,23.46 U17.15@68.25,24.05
NetC94_2: C94.2 R94.2 U17.16 | length 4.6
  Bottom Layer w0.125: R94.2@64.75,21.105 64.94,21.105 C94.2@65.875,22.04 66.415,22.04 67.75,23.375 U17.16@67.75,24.05
NetC97_2: C97.2 C98.2 L26.2 U17.5 | length 5.5
  Bottom Layer w0.25: U17.5@71.95,26.25 73.25,26.25 C97.2@73.46,26.04 ; L26.2@77.15,26.4 76.79,26.04 C98.2@75.5,26.04 C97.2@73.5,26.04 ; C97.2@73.46,26.04 C97.2@73.5,26.04 ; C97.2@73.46,26.04 C97.2@73.5,26.04
NetC102_1: C102.1 D8.2 J22.2 | length 5.1
  Top Layer w0.25: D8.2@77.8,13.25 C102.1@78.8,13.25 78.8,9.7 J22.2@79.2,9.3
NetC102_2: C102.2 L24.2 | length 23.7
  Top Layer w0.125: v1(78.75,14.15) 80.15,14.15 80.4,13.9 C102.2@80.4,13.25
  Layer 3 w0.125: v1(73.5,29.75) 75.325,27.925 75.325,20.1 74.95,19.725 74.95,18.775 74.325,18.15 74.325,15.825 76.438,13.712 78.312,13.712 v1(78.75,14.15)
  Bottom Layer w0.125: L24.2@73.5,28.98 v1(73.5,29.75)
NetC103_1: C103.1 D7.2 J22.3 | length 5.3
  Top Layer w0.25: D7.2@67.075,13.25 v1(67.075,12.35) 67.075,11.525 67.7,10.9 J22.3@67.7,9
  Bottom Layer w0.25: C103.1@66.3,12.35 v1(67.075,12.35)
NetC103_2: C103.2 L25.2 | length 13.7
  Layer 5 w0.125: v1(67.45,13.95) 67.45,14.7 69.825,17.075 69.825,18.096 73.5,21.771 v1(73.5,23.35)
  Bottom Layer w0.125: C103.2@66.3,13.95 v1(67.45,13.95) ; v1(73.5,23.35) L25.2@73.5,24.02
NetC104_2: C104.2 R48.1 | length 23.4
  Top Layer w0.15: R48.1@37.28,41.15 38.73,42.6 40.7,42.6 41.2,42.1 42.4,42.1 45.25,39.25 45.25,28.1 v1(45.7,27.65)
  Bottom Layer w0.15: v1@45.701,27.65 46.75,26.601 C104.2@46.75,26.41
NetC107_1: C107.1 U23.10 | length 2.3
  Bottom Layer w0.2: U23.10@76.95,53.8 79.04,53.8 C107.1@79.2,53.96
NetC107_2: C107.2 R142.1 | length 1.5
  Bottom Layer w0.2: C107.2@79.2,53.04 79.54,52.7 R142.1@80.6,52.7
NetC108_1: C108.1 U23.8 | length 1.4
  Bottom Layer w0.15: U23.8@76.95,54.8 77.318,54.8 78.04,55.522 C108.1@78.04,55.55
NetC109_2: C109.2 U23.11 | length 1.2
  Bottom Layer w0.2: U23.11@76.95,53.3 77.33,52.92 C109.2@78,52.92
NetC110_2: C110.2 U23.6 | length 1.2
  Bottom Layer w0.15: C110.2@75.75,56.79 75.75,56.3 76.15,55.9 U23.6@76.15,55.75
NetC118_2: C118.2 R131.1 U17.30 | length 3.2
  Bottom Layer w0.125: R131.1@69.53,30.9 C118.2@70.59,30.9 70.59,30.348 70.263,30.021 70.263,28.962 U17.30@70.25,28.95
NetCAD1_5: CAD1.5 R149.2 R151.2 | length 7.1
  Bottom Layer w0.15: CAD1.5@11.535,35.16 12.41,35.16 13.8,36.55 15.07,36.55 R151.2@16.22,35.4 R149.2@16.22,34
NetCAD2_5: CAD2.5 R150.2 R152.2 | length 4.9
  Bottom Layer w0.2: CAD2.5@11.935,51.26 13.89,51.26 14.42,50.73 R152.2@15.2,50.73 R150.2@15.2,52.12
NetD1_A: D1.A R12.1 | length 2.6
  Top Layer w0.3: R12.1@89.98,13.5 91.75,13.5 D1.A@91.75,12.7
NetD2_K: D2.K R11.1 R13.1 | length 7.1
  Bottom Layer w0.5: R11.1@83.92,19.55 84.22,19.55 85.07,20.4 85.07,22.2 ; R13.1@84.07,22.23 85.04,22.23 85.07,22.2 ; D2.K@84.07,24.25 84.67,24.25 85.07,23.85 85.07,22.2
NetD3_K: D3.K R86.1 | length 2.2
  Top Layer w0.125: R86.1@51.855,11.125 D3.K@54.1,11.125
NetD4_A: D4.A R119.1 | length 3.4
  Top Layer w0.2: D4.A@14.1,60.2 14.1,58.05 v1(14.25,57.9)
  Bottom Layer w0.2: v1(14.25,57.9) 14.7,58.35 R119.1@14.7,58.77
NetD5_A: D5.A R120.1 | length 4.2
  Top Layer w0.2: v1(10.7,61.35) 10.7,61 D5.A@11.5,60.2
  Bottom Layer w0.2: v1(10.7,61.35) 11.298,60.752 12.372,60.752 R120.1@12.97,61.35
NetD6_A: D6.A R121.1 | length 4.7
  Top Layer w0.2: v1(7.45,60.25) 8.85,60.25 D6.A@8.9,60.2
  Bottom Layer w0.2: v1(7.45,60.25) 8.1,60.9 9.55,60.9 9.83,61.18 R121.1@9.83,61.6
NetD10_2: D10.2 J16.1 L9.1 | length 12.1
  Top Layer w0.125: v1(35.625,5.25) 36.125,5.75 36.125,14.625 36.25,14.75 L9.1@36.25,15.775
  Bottom Layer w0.125: J16.1@35.6,4.5 35.6,5.225 v1(35.625,5.25) D10.2@35.625,5.825
NetD11_A: D11.A R133.2 | length 2.1
  Bottom Layer w0.2: R133.2@29.8,50.42 31.88,50.42 D11.A@31.9,50.4
NetD11_K: D11.K Q5.D | length 3.5
  Bottom Layer w0.2: D11.K@31.9,53 31.9,53.475 34.665,53.475 Q5.D@34.85,53.29
NetFIL1_1: FIL1.1 J1.1
NetJ2_1: J2.1 R8.1 | length 2
  Bottom Layer w0.5: R8.1@96.05,8.57 97.97,8.57 J2.1@98,8.6
NetJ3_2: J3.2 R77.1 R123.1 SW2.3 SW2.4 | length 57.2
  Top Layer w0.125: v1(17.4,20.65) 17.4,20.95 SW2.3@17.4,21.525 ; v1(21.45,21.3) 21.675,21.525 SW2.4@23.2,21.525
  Layer 8 w0.125: J3.2@6,60.55 6.35,60.55 7.1,59.8 7.1,53.2 6.887,52.987 6.887,46.987 5.613,45.713 5.613,31.737 7.3,30.05 14.25,30.05 v1(17,27.3)
  Bottom Layer w0.125: J3.2@6,60.55 J3.2@6.032,60.55 ; v1(17,27.3) 17,23.55 17.262,23.288 17.262,22.708 R123.1@17.42,22.55 R77.1@17.42,21.5 17.4,21.48 v1@17.4,20.7 ; v1(17.4,20.65) v1@17.4,20.7 ; v1(21.45,21.3) 20.55,21.3 19.95,20.7 v1@17.4,20.7
NetJ7_5: J7.5 R35.2 | length 49.9
  Layer 3 w0.103: v1(76.875,6.625) 76.875,6.25 76.925,6.2 77.25,6.2 77.3,6.25 77.3,6.75 81.125,10.575 81.125,13.875 89.225,21.975 89.225,31.75 88.598,32.377 88.598,46.723 v1(89.5,47.625)
  Bottom Layer w0.2: J7.5@76.875,5.275 v1(76.875,6.625) ; R35.2@88.73,47.65 89.475,47.65 v1(89.5,47.625)
NetJ13_D1: J13.D1 R45.1 | length 8.7
  Bottom Layer w0.125: J13.D1@10.086,3.936 14.625,8.475 14.625,8.875 15.52,9.77 R45.1@16.125,9.77
NetJ13_D3: J13.D3 R38.1 | length 7.5
  Bottom Layer w0.125: R38.1@17.375,9.77 17.855,9.77 19.625,8 19.625,5.115 J13.D3@20.804,3.936
NetJ15_A1: J15.A1 L7.1 | length 2.8
  Top Layer w0.125: J15.A1@30.5,13 L7.1@30.5,15.775
NetJ15_A4: J15.A4 L13.2 | length 3.1
  Top Layer w0.125: J15.A4@37.5,13 37.5,14.25 38.25,15 L13.2@38.25,15.775
NetJ15_B1: J15.B1 L6.1 | length 6.2
  Top Layer w0.125: J15.B1@30.5,10.38 31.75,11.63 31.75,13.5 32.5,14.25 L6.1@32.5,15.775
NetJ15_B4: J15.B4 L12.2 | length 10.1
  Top Layer w0.125: J15.B4@37.5,10.38 36.5,11.38 36.5,14.125 37.25,14.875 37.25,16.5 37.375,16.625 39.85,16.625 L12.2@40.25,17.025
NetJ16_5: J16.5 L15.2 | length 18.6
  Top Layer w0.125: v1@25.75,16.775 L15.2@27.225,16.775
  Bottom Layer w0.125: v1@25.75,16.775 27.75,16.775 28.625,15.9 29.75,15.9 31.5,14.15 31.5,8.65 33,7.15 33,4.55 J16.5@33,4.525
  other v1: 25.75,16.75
NetJ19_2: J19.2 L30.2 | length 1.8
  Top Layer w0.104: L30.2@32.025,63.625 L30.2@32.025,63.65 31.875,63.8 31.875,64.125 32.375,64.625 J19.2@32.375,65.2
NetJ19_3: J19.3 L30.3 | length 1.8
  Top Layer w0.104: J19.3@31.125,65.2 31.125,64.675 31.6,64.2 31.6,63.75 L30.3@31.475,63.625
NetJ19_5: J19.5 L31.2 | length 1.9
  Top Layer w0.104: L31.2@28.225,63.625 L31.2@28.275,63.625 ; L31.2@28.275,63.65 28.138,63.788 28.138,64.138 28.625,64.625 J19.5@28.625,65.2
NetJ19_6: J19.6 L31.3 | length 1.8
  Top Layer w0.104: J19.6@27.375,65.2 27.375,64.675 27.85,64.2 27.85,63.75 L31.3@27.725,63.625
NetJ19_8: J19.8 L32.2 | length 1.9
  Top Layer w0.104: L32.2@24.475,63.625 L32.2@24.525,63.625 ; L32.2@24.525,63.65 24.388,63.788 24.388,64.138 24.875,64.625 J19.8@24.875,65.2
NetJ19_9: J19.9 L32.3 | length 1.8
  Top Layer w0.104: J19.9@23.625,65.2 23.625,64.675 24.1,64.2 24.1,63.75 L32.3@23.975,63.625
NetJ19_11: J19.11 L33.2 | length 1.9
  Top Layer w0.104: L33.2@20.425,63.625 20.425,64.025 21.125,64.725 J19.11@21.125,65.2
NetJ19_12: J19.12 L33.3 | length 1.7
  Top Layer w0.104: L33.3@19.875,63.65 19.875,63.936 20.1,64.161 20.1,64.975 J19.12@19.875,65.2
NetJ19_14: J19.14 L34.2 | length 1.9
  Top Layer w0.104: L34.2@16.975,63.625 L34.2@17.025,63.625 ; L34.2@17.025,63.65 16.862,63.813 16.862,64.113 17.375,64.625 J19.14@17.375,65.2
NetJ19_15: J19.15 L34.3 | length 1.8
  Top Layer w0.104: J19.15@16.125,65.2 16.125,64.675 16.6,64.2 16.6,63.75 L34.3@16.475,63.625
NetJ19_20: J19.20 L35.2 | length 2.9
  Top Layer w0.5: L35.2@7.25,64.6 7.85,65.2 J19.20@9.875,65.2
NetJ23_4: J23.4 R84.2 | length 2.2
  Top Layer w0.4: J23.4@20.825,47 v1(22.55,47)
  Bottom Layer w0.4: v1(22.55,47) R84.2@23.07,47
NetJ23_6: J23.6 R101.2 | length 2.6
  Top Layer w0.254: J23.6@20.825,43 20.825,43.375 v1(21.15,43.7)
  Bottom Layer w0.254: v1(21.15,43.7) 21.25,43.6 R101.2@22.87,43.6
NetJ24_7: J24.7 R135.1 | length 3.2
  Top Layer w0.25: v1(39.75,41.65) 39.975,41.425 J24.7@39.975,41
  Bottom Layer w0.25: R135.1@37.45,41.38 37.72,41.65 v1(39.75,41.65)
NetJ24_10: J24.10 R130.1 | length 1.6
  Top Layer w0.4: J24.10@42.825,35 43.45,34.375 R130.1@43.45,33.63
NetJ30_1: J30.1 R204.2 R257.2 | length 13.1
  Top Layer w0.125: J30.1@2.1,7.4 3.15,7.4 4.15,8.4 4.15,11.78 R257.2@4.62,12.25
  Bottom Layer w0.15: J30.1@2.1,7.4 3.25,7.4 3.95,8.1 3.95,11.58 R204.2@4.62,12.25
NetJ30_2: J30.2 R205.2 R258.2 | length 12.9
  Top Layer w0.125: J30.2@2.1,8.65 3.2,8.65 3.85,9.3 3.85,12.65 4.6,13.4 R258.2@4.62,13.4
  Bottom Layer w0.15: J30.2@2.1,8.65 3.2,8.65 3.6,9.05 3.6,12.45 4.55,13.4 R205.2@4.62,13.4
NetJ30_3: J30.3 R206.2 R259.2 | length 12.9
  Top Layer w0.125: J30.3@2.1,9.9 3.15,9.9 3.6,10.35 3.6,13.75 4.45,14.6 R259.2@4.62,14.6
  Bottom Layer w0.15: J30.3@2.1,9.9 2.962,9.9 3.263,10.2 3.263,13.613 4.25,14.6 R206.2@4.62,14.6
NetJ31_2: J31.2 L36.2 | length 1.8
  Bottom Layer w0.104: J31.2@11.125,65.2 11.125,64.575 11.5,64.2 11.5,63.7 L36.2@11.425,63.625
NetJ31_3: J31.3 L36.3 | length 1.8
  Bottom Layer w0.104: L36.3@11.975,63.625 11.9,63.7 11.9,64.15 12.375,64.625 J31.3@12.375,65.2
NetJ31_5: J31.5 L38.2 | length 1.8
  Bottom Layer w0.104: J31.5@14.875,65.2 14.875,64.625 15.3,64.2 15.3,63.7 L38.2@15.225,63.625
NetJ31_6: J31.6 L38.3 | length 1.8
  Bottom Layer w0.104: L38.3@15.775,63.65 15.625,63.8 15.625,64.225 16.125,64.725 J31.6@16.125,65.2
NetJ31_8: J31.8 L40.2 | length 1.7
  Bottom Layer w0.104: L40.2@18.625,63.625 18.625,63.925 18.75,64.05 18.75,65.075 J31.8@18.625,65.2
NetJ31_9: J31.9 L40.3 | length 1.9
  Bottom Layer w0.104: L40.3@19.175,63.625 19.175,63.975 19.875,64.675 J31.9@19.875,65.2
NetJ31_11: J31.11 L42.2 | length 1.8
  Bottom Layer w0.104: J31.11@22.375,65.2 22.375,64.575 22.75,64.2 22.75,63.75 L42.2@22.625,63.625
NetJ31_12: J31.12 L42.3 | length 1.8
  Bottom Layer w0.104: L42.3@23.175,63.625 23.1,63.7 23.1,64.15 23.625,64.675 J31.12@23.625,65.2
NetJ31_14: J31.14 L44.2 | length 1.8
  Bottom Layer w0.104: J31.14@26.125,65.2 26.125,64.575 26.5,64.2 26.5,63.75 L44.2@26.375,63.625
NetJ31_15: J31.15 L44.3 | length 1.9
  Bottom Layer w0.104: L44.3@26.925,63.65 26.761,63.814 26.761,64.211 27.375,64.825 J31.15@27.375,65.2
NetJ31_20: J31.20 L45.2 | length 2.6
  Bottom Layer w0.5: J31.20@33.625,65.2 34.55,65.2 L45.2@35.7,64.05
NetL1_1: L1.1 R142.2 U23.2 U23.13 | length 4.3
  Bottom Layer w0.2: R142.2@80.6,54.3 v1(80.6,55)
  Bottom Layer w0.25: v1@74.75,53.8 U23.2@75.35,53.8 U23.13@76.15,53.8
  Bottom Layer w0.3: v1@74.65,53.8 v1(74.6,53.75) ; v1(74.6,53.75) v1(74.15,53.75) v1(74.15,53.15) v1(74.6,53.15) v1(74.6,53.75)
  other v1: 72.5,56.65 72.5,57.15 72.5,57.65 72.5,58.15
NetL8_1: L8.1 U13.1 | length 2.2
  Bottom Layer w0.125: U13.1@34.675,34.75 35,34.75 35.5,35.25 35.5,35.5 35.9,35.9 L8.1@36.275,35.9
NetL8_4: L8.4 U13.2 | length 2
  Bottom Layer w0.125: U13.2@34.675,34.25 35.125,34.25 35.975,35.1 L8.4@36.275,35.1
NetL11_1: L11.1 U13.3 | length 1.8
  Bottom Layer w0.125: U13.3@34.675,33.75 35.5,33.75 36.025,34.275 L11.1@36.275,34.275
NetL11_4: L11.4 U13.4 | length 1.7
  Bottom Layer w0.125: U13.4@34.675,33.25 35.75,33.25 36,33.5 L11.4@36.275,33.5
NetL14_1: L14.1 U13.6 | length 3.3
  Bottom Layer w0.125: U13.6@34.675,32.25 35.5,32.25 36.375,31.375 37.375,31.375 L14.1@37.525,31.525
NetL14_4: L14.4 U13.7 | length 3.1
  Bottom Layer w0.125: U13.7@34.675,31.75 35.5,31.75 36.525,30.725 L14.4@37.4,30.725
NetL16_1: L16.1 U13.8 | length 3.2
  Bottom Layer w0.125: U13.8@34.675,31.25 35.375,31.25 36,30.625 36,29.875 36.225,29.65 L16.1@36.775,29.65
NetL16_4: L16.4 U13.9 | length 3.3
  Bottom Layer w0.125: U13.9@34.675,30.75 35.375,30.75 35.625,30.5 35.625,29.75 36.525,28.85 L16.4@36.775,28.85
NetL23_2: L23.2 R94.1 | length 1
  Bottom Layer w0.125: L23.2@64.75,19.105 R94.1@64.75,20.145
NetL24_1: L24.1 U17.2 | length 1.7
  Bottom Layer w0.125: U17.2@71.95,27.75 72.625,27.75 72.895,28.02 L24.1@73.5,28.02
NetL25_1: L25.1 U17.6 | length 1.9
  Bottom Layer w0.125: U17.6@71.95,25.75 72.73,25.75 L25.1@73.5,24.98
NetQ1_1: Q1.1 R13.2 | length 33
  Bottom Layer w0.125: R13.2@84.07,21.27 83.82,21.27 81.3,18.75 81.3,10.75 82.097,9.953 88.703,9.953 93.05,14.3 93.05,15.433 93.654,16.037 95.987,16.037 96.35,16.4 96.35,17.8 96.17,17.98 Q1.1@96.17,18.75
NetQ1_3: Q1.3 Q3.3 R14.2 U3.3 | length 10.3
  Bottom Layer w0.125: U3.3@89.66,17.45 90.05,17.45 90.2,17.6 90.2,19.4 90.313,19.513 91.183,19.513 91.82,20.15 Q3.3@91.82,21.15 Q1.3@95.22,21.15 95.22,21.3 94.8,21.72 R14.2@94.8,22.55
NetQ2_D: Q2.D R72.2 U15.G | length 5.1
  Bottom Layer w0.125: R72.2@41.375,20.895 40.85,20.37 40.85,19 U15.G@40.2,18.35 40.49,18.06 Q2.D@42.125,18.06
NetQ2_G: Q2.G R75.2 | length 2.6
  Bottom Layer w0.125: Q2.G@41.625,19.44 41.625,19.125 41.98,18.77 R75.2@43.75,18.77
NetQ3_1: Q3.1 R125.2 | length 2.2
  Bottom Layer w0.125: Q3.1@92.77,18.75 94.28,17.24 R125.2@94.28,17.2
NetQ4_D: Q4.D R128.2 U22.G | length 2.6
  Bottom Layer w0.125: U22.G@80.35,31.05 80.463,30.937 81.442,30.937 R128.2@81.7,30.68 82.49,30.68 Q4.D@82.71,30.9
NetR1_1: R1.1 R2.1 R3.1 U1.G2 | length 4.9
  Top Layer w0.125: v1(48.7,50.5) U1.G2@49.5,50.5
  Bottom Layer w0.125: v1(48.7,50.5) R1.1@47.98,50.5 47.5,50.98 47.5,51.895 R3.1@47.98,52.375 48.895,52.375 R2.1@49.02,52.5
NetR4_1: R4.1 U1.D13 | length 20.7
  Top Layer w0.125: v1(69.35,57.5) 70.5,57.5 U1.D13@71.5,56.5
  Layer 10 w0.125: v1(52.25,56.948) 52.802,57.5 v1(69.35,57.5)
  Bottom Layer w0.125: R4.1@51.5,56.98 52.218,56.98 v1(52.25,56.948)
NetR5_2: R5.2 U1.D7 | length 2.5
  Top Layer w0.125: U1.D7@59.5,56.5 59.9,56.1 v1(59.9,55.85)
  Bottom Layer w0.125: R5.2@58.43,56.45 59.3,56.45 v1(59.9,55.85)
NetR6_2: R6.2 R148.1 U3.1 U3.2 U3.5 U3.6 U3.7
  other v1: 88.475,18.125 89.025,18.125 88.475,18.675 89.025,18.675
NetR20_2: R20.2 U1.V14 | length 3.3
  Top Layer w0.254: v1(72.45,29.7) 72.45,29.55 U1.V14@73.5,28.5
  Bottom Layer w0.15: v1(72.45,29.7) 73.48,30.73 R20.2@73.48,30.9
NetR23_1: R23.1 U1.W13 | length 6.9
  Top Layer w0.125: U1.W13@71.5,26.5 71.5,26.8 72.5,27.8 73.8,27.8 74.2,28.2 74.2,29.9 v1(73.95,30.15)
  Bottom Layer w0.125: v1(73.95,30.15) 74.17,30.37 74.17,30.75 R23.1@74.57,31.15
NetR48_2: R48.2 R50.2 R154.2 U10.41 | length 9.2
  Top Layer w0.2: U10.41@32.625,36.2 32.625,36.832 34.19,38.397 34.19,38.94 v1(34.2,38.95) ; R50.2@35.15,41.18 35.17,41.2 36.27,41.2 R48.2@36.32,41.15 36.32,41.67 v1(36.5,41.85)
  Layer 3 w0.103: v1(34.2,38.95) 34.2,39.55 v1(36.5,41.85)
NetR49_2: R49.2 U10.48 | length 5.6
  Top Layer w0.125: R49.2@25.855,38.875 26.25,38.875 26.5,38.625 26.5,36.75 27.375,35.875 U10.48@29.125,35.875
NetR68_1: R68.1 U13.28 | length 4.6
  Bottom Layer w0.125: R68.1@25.855,36.875 26.625,36.875 27.95,35.55 U13.28@29.875,35.55
NetR70_2: R70.2 U13.35 | length 4.5
  Bottom Layer w0.125: U13.35@33.375,35.55 33.375,36.25 33.75,36.625 34.5,36.625 35.325,37.45 35.8,37.45 36.27,37.92 R70.2@36.27,38.125
NetR71_2: R71.2 U13.22 | length 3.6
  Bottom Layer w0.125: R71.2@25.875,31.25 26.375,31.75 27.25,31.75 27.75,32.25 U13.22@29.075,32.25
NetR73_2: R73.2 U13.24 | length 3.3
  Bottom Layer w0.125: R73.2@25.855,33.5 26.375,33.5 26.625,33.25 U13.24@29.075,33.25
NetR74_2: R74.2 U13.25 | length 7.2
  Bottom Layer w0.125: 26.75,34.625 R74.2@25.855,34.625 26.75,34.625 ; 26.75,34.625 27.625,33.75 ; 26.75,34.625 27.625,33.75 ; 27.625,33.75 U13.25@29.075,33.75 27.625,33.75
NetR80_2: R80.2 U1.M22 | length 8.8
  Top Layer w0.125: U1.M22@89.5,40.5 89.5,39.85 90.05,39.3 94,39.3 95.88,41.18 R80.2@96.6,41.18
NetR81_2: R81.2 U1.AD10 | length 4.9
  Top Layer w0.3: v1(63,13.9) 63.4,13.9 65.5,16 U1.AD10@65.5,16.5
  Bottom Layer w0.3: R81.2@62.98,14.9 63,14.88 v1(63,13.9)
NetR82_2: R82.2 U1.AA10 | length 1.9
  Top Layer w0.125: v1(64.9,23.55) 65.5,22.95 U1.AA10@65.5,22.5
  Bottom Layer w0.125: R82.2@64.8,22.98 64.8,23.45 v1(64.9,23.55)
NetR83_2: R83.2 U1.AA12 U1.E20 U1.G20 U1.J20 U1.K20 U1.N5 | length 82.1
  Top Layer w0.2: U1.J20@85.5,46.5 84.806,47.194 84.806,49.805 U1.G20@85.5,50.5
  Top Layer w0.25: U1.N5@55.5,38.5 56.8,38.5 57.6,37.7 v1(61.1,37.7) ; v1(69.15,21.65) 69.15,22.15 U1.AA12@69.5,22.5 ; U1.K20@85.5,44.5 85.8,44.8 v1(85.8,45.45) 85.5,45.75 U1.J20@85.5,46.5 ; U1.G20@85.5,50.5 84.625,51.375 84.625,53.625 U1.E20@85.5,54.5
  Layer 8 w0.25: v1(61.1,37.7) 60.5,37.1 60.5,30.166 62.55,28.116 62.55,22.075 63.775,20.85 65.35,20.85 66.15,21.65 v1(69.15,21.65)
  Layer 5 w0.25: v1(69.15,21.65) 69.15,21.8 69.675,22.325 70.747,22.325 71.05,22.628 71.05,23.05 70.85,23.25 70.85,25.75 71.5,26.4 72.572,26.4 74.872,28.7 81.141,28.7 83.525,31.084 83.525,43.175 v1(85.8,45.45)
  Bottom Layer w0.4: R83.2@85.4,48.5 84.8,47.9 84.8,46.45 v1(85.8,45.45)
NetR137_1: R137.1 R138.2 U23.4 | length 2.9
  Bottom Layer w0.15: R138.2@73.3,56.57 74.23,55.64 R137.1@74.23,55.4 74.83,54.8 U23.4@75.35,54.8
NetR140_1: R140.1 R141.2 U23.9 | length 6.5
  Bottom Layer w0.15: U23.9@76.95,54.3 77.4,54.3 78.075,54.975 79.55,54.975 80.225,55.65 R140.1@81.096,55.65
  Bottom Layer w0.2: R140.1@81.096,55.65 81.15,55.596 81.15,55.3 81.95,54.5 R141.2@81.95,54.23
NetR143_1: R143.1 R144.2 U23.7 | length 5
  Bottom Layer w0.15: R144.2@77.3,57.05 78.225,56.125 78.676,56.125 79.601,57.05 R143.1@79.65,57.05
  Bottom Layer w0.2: U23.7@76.95,55.3 76.95,56.7 R144.2@77.3,57.05
NetR153_1: R153.1 U1.AB19 | length 1.7
  Top Layer w0.125: v1(82.5,20.75) 82.75,20.5 U1.AB19@83.5,20.5
  Bottom Layer w0.125: R153.1@81.9,20.72 82.47,20.72 v1(82.5,20.75)
NetTP1_1: TP1.1 U1.AA11 | length 13.3
  Top Layer w0.125: TP1.1@60.5,13.275 61.975,14.75 62.9,14.75 64.65,16.5 64.65,20.75 65.36,21.46 66.46,21.46 U1.AA11@67.5,22.5
NetTP2_1: TP2.1 U1.AD11 | length 7.1
  Top Layer w0.125: TP2.1@61.75,13.25 64.3,13.25 67.5,16.45 U1.AD11@67.5,16.5
NetU2_6: U2.6 U4.6 U6.4 | length 7.9
  Bottom Layer w0.125: U4.6@77.4,19.15 77.808,19.15 78.238,19.579 78.238,21.962 78.05,22.15 U2.6@77.4,22.15 77.35,22.1 76.55,22.1 76.45,22.2 76.45,23.75 76.55,23.85 U6.4@77.4,23.85
NetU10_43: U10.43 U11.3 | length 2.6
  Top Layer w0.3: U10.43@31.625,36.2 31.625,37.075
  Top Layer w0.4: U11.3@31.49,38.75 31.625,38.615 31.625,37.075
ON/OFF: J3.1 R147.1 SW1.3 SW1.4 U1.D18 | length 139.8
  Top Layer w0.125: SW1.3@8.4,27 8.4,27.75 v1(8.5,27.85) ; U1.D18@81.5,56.5 82.1,57.1 v1(82.1,57.3)
  Top Layer w0.3: SW1.3@8.4,27 SW1.4@14.2,27
  Layer 5 w0.125: v1(5.4,66.3) 6.15,66.3 10.4,70.55 29.8,70.55 30.25,71 72.925,71 76.363,67.562 76.363,63.512 82.1,57.775 v1(82.1,57.3)
  Bottom Layer w0.125: v1(5.4,66.3) 4.046,64.946 4.046,60.454 5.2,59.3 J3.1@6,59.3 3.4,56.7 3.4,42 5.775,39.625 5.775,35.275 7.15,33.9 7.15,28.22 R147.1@8.32,27.05 8.32,27.67 v1(8.5,27.85)
OTGD_N: J16.2 L10.2 U20.4 | length 23.2
  Top Layer w0.137: v1(34.75,16.375) 34.75,16.673 34.775,16.698 L10.2@34.775,17.225
  Bottom Layer w0.137: U20.4@30.575,21.475 30.575,21.125 30.24,20.79 30.24,19.51 32.02,17.73 33.701,17.73 34.515,16.916 34.515,16.61 v1(34.75,16.375) 34.515,16.14 34.515,15.95 34.815,15.65 35.446,15.65 36.38,14.716 36.38,9.28 34.765,7.665 34.765,4.935 34.95,4.75 J16.2@34.95,4.15
OTGD_P: J16.3 L10.3 U20.5 | length 23.2
  Top Layer w0.137: L10.3@33.975,17.225 33.975,16.698 34,16.673 v1(34,16.375)
  Bottom Layer w0.137: U20.5@29.625,21.475 29.625,21.125 29.96,20.79 29.96,19.394 31.904,17.45 33.585,17.45 34.235,16.8 34.235,16.61 v1(34,16.375) 34.235,16.14 34.235,15.834 34.699,15.37 35.33,15.37 36.1,14.6 36.1,9.396 34.485,7.781 34.485,4.935 34.3,4.75 J16.3@34.3,4.15
PCIE_DIS_N: J12.20 U1.L3 | length 13.2
  Top Layer w0.125: U1.L3@51.5,42.5 52.187,41.813 52.187,40.363 52.925,39.625 53.875,39.625 54.625,38.875 54.625,36.1 55.475,35.25 56.5,35.25 v1(56.75,35)
  Bottom Layer w0.125: J12.20@54.4,35 v1(56.75,35)
PCIE_I2C_SCL: J12.30 R95.2 | length 4.8
  Layer 3 w0.125: v1(50.875,31.8) 51.125,32.05 51.825,32.05 v1(52.875,31)
  Bottom Layer w0.125: v1(50.875,31.8) 50.875,32.355 R95.2@51.02,32.5 ; v1(52.875,31) J12.30@54.4,31
PCIE_I2C_SDA: J12.32 R96.2 | length 20.6
  Layer 3 w0.125: v1(50.85,45.9) 51.867,45.9 52.329,45.437 52.913,45.437 53.413,44.937 53.413,30.163 v1(53,29.75)
  Bottom Layer w0.125: v1(50.85,45.9) 50.97,46.02 R96.2@51.5,46.02 ; v1(53,29.75) 53.45,30.2 J12.32@54.4,30.2
PCIE_RESET_N: J12.22 U1.D22 | length 64.9
  Top Layer w0.125: v1(88.825,55.825) U1.D22@89.5,56.5
  Layer 10 w0.125: v1(56.75,34) 56.25,34 53.713,36.537 52.579,36.537 51.937,37.179 51.937,38.971 55,42.033 55,47.755 58.495,51.25 58.495,55.395 59.4,56.3 69.794,56.3 72.257,58.763 74.837,58.763 75.7,57.9 75.7,56.5 76.113,56.087 79.187,56.087 79.963,56.863 82.863,56.863 82.913,56.913 86.462,56.913 87.55,55.825 v1(88.825,55.825)
  Bottom Layer w0.125: J12.22@54.4,34.2 55.925,34.2 56.125,34 v1(56.75,34)
PCIE_RX_N: R44.1 U1.A14 | length 19.1
  Top Layer w0.157: v1(73.487,61.83) 73.5,61.843 U1.A14@73.5,62.5
  Bottom Layer w0.157: R44.1@62.2,55.38 62.55,55.73 62.55,57.224 63.05,57.724 63.05,59.95 63.75,60.65 65.524,60.65 65.774,60.4 67.026,60.4 67.8,60.4 68.4,61 68.4,61.7 69.8,63.1 72.424,63.1 72.9,62.624 72.9,61.824 73.074,61.65 73.307,61.65 v1(73.487,61.83)
PCIE_RX_P: R47.1 U1.B14 | length 18.6
  Top Layer w0.157: v1(73.487,61.17) 73.5,61.157 U1.B14@73.5,60.5
  Bottom Layer w0.157: R47.1@63.2,55.38 62.85,55.73 62.85,57.1 63.35,57.6 63.35,59.8 63.9,60.35 65.4,60.35 65.65,60.1 67.15,60.1 67.924,60.1 68.7,60.876 68.7,61.576 69.924,62.8 72.3,62.8 72.6,62.5 72.6,61.7 72.95,61.35 73.307,61.35 v1(73.487,61.17)
PCIE_TX_N: R51.1 U1.A15 | length 46.3
  Top Layer w0.157: U1.A15@75.5,62.5 v1(76.125,61.875)
  Layer 8 w0.119: 63.894,49.7 63.894,49.994 ; v1(66.25,30.5) 66.059,30.309 65.886,30.309 64.721,31.474 64.604,31.592 64.604,31.792 63.894,32.501 63.894,49.994 ; v1(76.125,61.875) 76.378,61.622 76.776,61.622 77.121,61.278 77.121,60.569 77.049,60.498 76.501,59.95 69.195,59.95 67.521,59.95 63.894,56.323 63.894,55.994 63.894,49.994
  Bottom Layer w0.157: R51.1@65.48,30.75 65.73,30.5 v1(66.25,30.5)
PCIE_TX_P: R52.1 U1.B15 | length 46.4
  Top Layer w0.157: U1.B15@75.5,60.5 v1(76.125,61.125)
  Layer 8 w0.119: 63.65,49.7 63.65,50.095 ; v1(66.25,29.875) 66.059,30.065 65.784,30.065 64.36,31.49 64.36,31.69 63.65,32.4 63.65,50.095 ; v1(76.125,61.125) 76.378,61.378 76.675,61.378 76.877,61.176 76.877,60.671 76.4,60.194 69.094,60.194 67.42,60.194 63.65,56.424 63.65,56.095 63.65,50.095
  Bottom Layer w0.157: R52.1@65.48,29.625 65.73,29.875 v1(66.25,29.875)
PCIE_UIM_CLK: J12.12 J14.3 | length 62.9
  Layer 10 w0.125: v1(61.25,43.375) 62.125,43.375 62.852,44.102 62.852,48.834 64.555,50.538 77.438,50.538 77.688,50.788 84.505,50.788 88,47.293 88,42.684 cw(c87.854,42.684) 87.854,42.538 87.409,42.538 ccw(c87.409,42.391) 87.262,42.391 87.262,42.359 ccw(c87.409,42.359) 87.409,42.213 87.854,42.213 cw(c87.854,42.066) 88,42.066 88,42.034 cw(c87.854,42.034) 87.854,41.888 87.409,41.888 ccw(c87.409,41.741) 87.262,41.741 87.262,41.709 ccw(c87.409,41.709) 87.409,41.563 87.854,41.563 cw(c87.854,41.416) 88,41.416 88,40.55 89.35,39.2 96.3,39.2 v1(96.35,39.25)
  Bottom Layer w0.125: J12.12@54.4,41.4 56.025,41.4 58,43.375 v1(61.25,43.375) ; v1(96.35,39.25) 97.3,40.2 J14.3@99.03,40.2
PCIE_UIM_DATA: J12.10 J14.7 | length 63
  Layer 10 w0.125: v1(59.5,44) 58.65,44 58.4,43.75 58.4,41.6 58.7,41.3 58.991,41.3 ccw(c58.991,41.446) 59.137,41.446 59.137,43.154 cw(c59.284,43.154) 59.284,43.3 59.316,43.3 cw(c59.316,43.154) 59.462,43.154 59.462,40.577 ccw(c59.609,40.577) 59.609,40.43 59.641,40.43 ccw(c59.641,40.577) 59.788,40.577 59.788,41.154 cw(c59.934,41.154) 59.934,41.3 60.4,41.3 60.7,41.6 60.7,44 62.45,45.75 62.45,48.786 64.452,50.788 77.334,50.788 77.584,51.038 84.609,51.038 88.25,47.396 88.25,41.85 v1(90.3,39.8)
  Bottom Layer w0.125: J12.10@54.4,42.2 56.075,42.2 57.875,44 v1(59.5,44) ; v1(90.3,39.8) 90.7,40.2 J14.7@91.41,40.2
PCIE_UIM_PWR: J12.8 J14.1 | length 63
  Layer 10 w0.125: v1(59.75,44.75) 60.95,44.75 62.15,45.95 62.15,48.839 64.348,51.038 77.23,51.038 77.48,51.288 84.712,51.288 88.55,47.45 88.55,42.45 90.6,40.4 96.4,40.4 97,39.8 97,35.75 v1(96.4,35.15)
  Bottom Layer w0.125: J12.8@54.4,43 55.875,43 57.625,44.75 v1(59.75,44.75) ; v1(96.4,35.15) 99,35.15 J14.1@99.03,35.12
PCIE_UIM_RST: J12.14 J14.2 | length 62.9
  Layer 10 w0.125: v1(58.75,39.125) 58.6,39.275 58.6,39.75 58.8,39.95 59.586,39.95 63.3,43.664 63.3,48.929 64.659,50.288 77.541,50.288 77.791,50.538 84.402,50.538 87.013,47.927 87.013,41.137 89.45,38.7 95.35,38.7 v1(96.3,37.75)
  Bottom Layer w0.125: J12.14@54.4,40.6 56.55,40.6 58.025,39.125 58.25,39.125 v1(58.75,39.125) ; v1(96.3,37.75) 96.39,37.66 J14.2@99.03,37.66
PCIE_UIM_VPP: J12.16 J14.6 | length 62.9
  Layer 10 w0.125: v1(58.75,38.5) 61.45,38.5 63.625,40.675 ; 63.535,40.585 63.65,40.7 63.65,40.862 63.65,41.041 ccw(c63.504,41.041) 63.504,41.187 63.196,41.187 cw(c63.196,41.334) 63.05,41.334 63.05,41.366 cw(c63.196,41.366) 63.196,41.512 63.65,41.512 64.104,41.512 ccw(c64.104,41.659) 64.25,41.659 64.25,41.691 ccw(c64.104,41.691) 64.104,41.837 63.65,41.837 63.196,41.837 cw(c63.196,41.984) 63.05,41.984 63.05,42.016 cw(c63.196,42.016) 63.196,42.162 63.65,42.162 64.104,42.162 ccw(c64.104,42.309) 64.25,42.309 64.25,42.341 ccw(c64.104,42.341) 64.104,42.487 63.65,42.487 63.196,42.487 cw(c63.196,42.634) 63.05,42.634 63.05,42.666 cw(c63.196,42.666) 63.196,42.813 63.65,42.813 64.104,42.813 ccw(c64.104,42.959) 64.25,42.959 64.25,42.991 ccw(c64.104,42.991) 64.104,43.138 63.796,43.138 cw(c63.796,43.284) 63.65,43.284 63.65,43.3 63.65,48.925 64.762,50.038 77.645,50.038 77.895,50.288 84.298,50.288 86.763,47.823 86.763,41.034 90.096,37.7 v1(90.1,37.7)
  Bottom Layer w0.125: J12.16@54.4,39.8 55.7,39.8 57,38.5 v1(58.75,38.5) ; v1(90.1,37.7) 91.37,37.7 J14.6@91.41,37.66
PCIE_VCC: C34.1 C35.1 C36.1 C37.2 C38.2 C39.2 C108.2 C115.2 C116.2 C117.2 C119.2 J12.2 J12.24 J12.39 J12.41 J12.52 L1.2 L29.1 R143.2 | length 38
  Layer 8 w0.3: v1(67.15,55.6) 67.15,56.3 69.95,59.1 79.3,59.1 v1(80.55,57.85)
  Bottom Layer w0.25: v1(50.2,36.05) 50.2,36.6 C35.1@49.85,36.95 50.01,37.11 C39.2@50.01,38.55 50.49,39.03 v1(50.49,39.058) ; C37.2@51.96,44.5 v1(52.454,44.994) 52.86,45.4 J12.2@54.4,45.4 ; v1(53,33.3) 53.1,33.4 J12.24@54.4,33.4 ; v1(54.4,21.6) J12.52@54.4,22.2 ; v1(60.65,26.7) 60.75,26.6 J12.41@62.6,26.6 ; J12.39@62.6,27.4 63.65,27.4 v1(64.35,28.1) ; C108.2@78.96,55.55 C108.2@78.975,55.565
  Bottom Layer w0.3: C38.2@50.625,16.585 50.3,16.91 v1(50.3,17.35) 50.3,17.7 C34.1@51.1,18.5 ; C108.2@78.96,55.55 78.96,55.76 79.3,56.1 80.15,56.1 80.55,56.5 v1(80.55,57.85) 80.55,58.3 80.2,58.65 R143.2@79.65,58.65
  Bottom Layer w0.4: v1(58.2,49.3) 58.9,49.3 59.4,49.8 C36.1@59.4,50.95
  other v1: 66.35,53.05 66.35,53.7 66.45,54.35 66.45,55 66.45,55.6 16,57.5 16.4,57.9 15.65,57.95
PCIE_VCC_EN: R141.1 U1.M24 | length 21.1
  Top Layer w0.2: v1(92.5,40.9) 93.1,40.9 U1.M24@93.5,40.5
  Layer 8 w0.2: v1(82.6,53.25) 83.1,53.75 84.136,53.75 88.1,49.786 88.1,43.2 90.4,40.9 v1(92.5,40.9)
  Bottom Layer w0.2: R141.1@81.95,53.27 82.58,53.27 v1(82.6,53.25)
PCIE_VCC_PG: R139.2 U1.U21 U23.5 | length 35.4
  Top Layer w0.15: v1(83.05,31.45) 86.55,31.45 U1.U21@87.5,30.5
  Layer 3 w0.15: v1(75.5,55.65) 76.35,55.65 83.4,48.6 83.4,31.8 v1(83.05,31.45)
  Bottom Layer w0.15: R139.2@74.25,56.57 74.75,56.07 74.75,55.4 74.85,55.3 U23.5@75.35,55.3 75.5,55.45 v1(75.5,55.65)
PCIE_WAKE_N: J12.1 U1.F24 | length 38.9
  Top Layer w0.125: v1(92,53.2) 92.7,52.5 U1.F24@93.5,52.5
  Layer 10 w0.125: v1(61.3,45.8) 61.3,48.343 64.507,51.55 69.55,51.55 69.913,51.913 72.287,51.913 72.912,51.288 77.038,51.288 77.5,51.75 81.5,51.75 82.15,52.4 85.45,52.4 85.75,52.7 91.5,52.7 v1(92,53.2)
  Bottom Layer w0.125: v1(61.3,45.8) J12.1@62.6,45.8
PCIECLK_N: C31.2 J12.11 R43.2 | length 19.7
  Layer 8 w0.119: v1(56.875,51.5) 56.622,51.247 56.622,49.377 55.575,48.33 55.575,42.475 56.553,41.497 57.247,41.497 v1(57.5,41.75)
  Bottom Layer w0.157: v1(56.875,51.5) C31.2@57.5,52.04 ; v1(57.5,41.75) 57.7,41.55 61.6,41.55 61.85,41.8 J12.11@62.6,41.8 64.03,41.8 R43.2@64.15,41.92
PCIECLK_P: C32.2 J12.13 R42.2 | length 20.2
  Layer 8 w0.119: v1(56.125,51.5) 56.378,51.247 56.378,49.478 55.331,48.431 55.331,42.374 56.452,41.253 57.247,41.253 v1(57.5,41)
  Bottom Layer w0.157: C32.2@55.5,52.04 v1(56.125,51.5) ; v1(57.5,41) 57.75,41.25 61.575,41.25 61.825,41 J12.13@62.6,41 63.98,41 R42.2@64.15,40.83
PCIERX_N: J12.23 R44.2 | length 24.8
  Layer 3 w0.119: v1(61.25,34) 61.047,33.797 60.75,33.797 60.6,33.947 60.6,47.914 61.594,48.908 61.594,53.894 61.9,54.2 62.35,54.2 62.55,54 62.55,53.9 v1(62.4,53.75)
  Bottom Layer w0.157: v1(61.25,34) 61.45,33.8 J12.23@62.6,33.8 ; R44.2@62.2,54.42 62.4,54.22 v1(62.4,53.75)
PCIERX_P: J12.25 R47.2 | length 26.2
  Layer 3 w0.119: v1(61.25,33.35) 61.047,33.553 60.649,33.553 60.356,33.846 60.356,48.015 61.35,49.009 61.35,54 61.8,54.45 62.5,54.45 62.8,54.15 62.8,53.95 v1(63,53.75)
  Bottom Layer w0.157: v1(61.25,33.35) 61.6,33 J12.25@62.6,33 ; v1(63,53.75) 63,54.22 R47.2@63.2,54.42
PCIETX_N: J12.31 R51.2 | length 2
  Bottom Layer w0.157: J12.31@62.6,30.6 64.37,30.6 R51.2@64.52,30.75
PCIETX_P: J12.33 R52.2 | length 2
  Bottom Layer w0.157: J12.33@62.6,29.8 64.345,29.8 R52.2@64.52,29.625
PMIC_ADCIN1: R204.1 U1.AB14 | length 85.6
  Top Layer w0.125: U1.AB14@73.5,20.5 v1(74.325,20.5) v1@74.375,20.5
  Layer 8 w0.125: v1(9.2,17.35) 10,18.15 16.063,18.15 16.626,18.713 19.079,18.713 19.229,18.562 20.012,18.562 20.55,19.1 20.907,19.1 21.97,20.163 28.962,20.163 31.325,17.8 34.969,17.8 35.494,17.275 37.025,17.275 37.65,17.9 43.475,17.9 49.5,11.875 59.012,11.875 62.249,15.113 72.127,15.113 73.364,16.35 74.683,16.35 75.163,16.829 75.163,19.254 75.087,19.329 75.087,19.738 v1(74.325,20.5)
  Bottom Layer w0.125: R204.1@5.58,12.25 5.993,12.663 7.22,12.663 9.4,14.842 9.4,15.832 9.2,16.032 v1(9.2,17.35)
PMIC_ADCIN2: R205.1 U1.AC14 | length 80.2
  Top Layer w0.125: v1(73.5,17.675) U1.AC14@73.5,18.5
  Layer 8 w0.125: v1(8.651,16.25) 8.651,17.401 9.65,18.4 15.95,18.4 17.163,19.613 17.696,19.613 17.908,19.4 20.854,19.4 21.866,20.413 29.087,20.413 31.425,18.075 35.048,18.075 35.598,17.525 36.9,17.525 37.525,18.15 43.6,18.15 48.95,12.8 59.583,12.8 62.213,15.429 72.09,15.429 73.5,16.839 v1(73.5,17.675)
  Bottom Layer w0.125: R205.1@5.58,13.4 5.58,13.48 5.95,13.85 8.054,13.85 9.15,14.946 9.15,15.713 8.651,16.213 v1(8.651,16.25)
PMIC_ADCIN3: R206.1 U1.AD14 | length 78.4
  Top Layer w0.125: v1(72.475,16.5) U1.AD14@73.5,16.5
  Layer 8 w0.125: v1(8.55,17.95) 9.25,18.65 13.492,18.65 14.742,19.9 17.9,19.9 18.15,19.65 20.75,19.65 21.763,20.663 29.212,20.663 31.55,18.325 35.151,18.325 35.701,17.775 36.775,17.775 37.4,18.4 43.85,18.4 45.95,16.3 47.075,16.3 50.325,13.05 50.346,13.05 50.936,13.05 57.773,13.05 58.937,14.215 58.937,14.221 59.179,14.463 59.185,14.463 60.435,15.712 60.965,15.712 61.678,16.425 72.4,16.425 v1(72.475,16.5)
  Bottom Layer w0.125: R206.1@5.58,14.6 5.993,15.013 7.637,15.013 7.85,14.8 8.651,14.8 8.9,15.05 8.9,15.383 8.15,16.133 8.15,17.55 v1(8.55,17.95)
POR_N: CAD1.10 J10.10 R7.1 R15.1 R123.2 U1.E18 | length 148.4
  Top Layer w0.125: U1.E18@81.5,54.5 82.05,53.95 82.9,53.95 83.718,53.132 v1@83.974,53.132 ; v1@83.974,53.132 84.118,53.132 v1(84.15,53.1) 84.006,53.1 v1@83.974,53.132
  Top Layer w0.15: J10.10@12.932,35.26 12.942,35.25 v1(14.7,35.25)
  Layer 8 w0.125: v1(82.35,26.5) 82.388,26.538 82.388,28.938 85.3,31.85 85.3,37.3 84.15,38.45 84.15,45.146 85.55,46.546 85.55,51.758 84.208,53.1 v1(84.15,53.1)
  Layer 5 w0.125: v1(17.95,27.35) 19.95,27.35 22.05,25.25 22.05,24.343 24.893,21.5 26.775,21.5 30.938,17.337 36.845,17.337 37.132,17.625 44.5,17.625 47,15.125 v1(47.375,15.125)
  Layer 10 w0.125: v1(14.7,35.25) 14.7,29.2 16,27.9 17.7,27.9 17.95,27.65 v1(17.95,27.35) ; v1(47.375,15.125) 47.375,14.667 47.704,14.337 48.054,14.337 48.179,14.463 49.362,14.463 51.025,12.8 57.839,12.8 58.702,13.663 59.154,13.663 59.329,13.487 67.787,13.487 68.213,13.913 75.963,13.913 76.175,14.125 v1(77,14.125)
  Layer 3 w0.125: v1(9.45,41.3) 9.22,41.3 8.958,41.563 8.429,41.563 8.187,41.321 8.187,40.979 13.917,35.25 v1(14.7,35.25) ; v1(77,14.125) 79.675,16.8 79.675,23 78.725,23.95 78.592,23.95 78.212,24.329 78.212,24.671 79.104,25.563 81.413,25.563 v1(82.35,26.5)
  Bottom Layer w0.125: v1(9.45,41.3) 9.45,41.055 CAD1.10@10.265,40.24 ; v1(17.95,27.35) 17.95,24.45 18.38,24.02 R123.2@18.38,22.55 R7.1@19.695,22.55 ; R15.1@81.5,26.3 82.15,26.3 v1(82.35,26.5)
PWR_EN: R22.1 U1.AB9 U7.4 | length 79.1
  Top Layer w0.125: U1.AB9@63.5,20.5 64.05,21.05 v1(64.05,21.35)
  Layer 8 w0.125: v1(47.95,51.3) 47.95,45.217 48.567,44.6 48.912,44.6 53.262,48.95 53.262,51.237 54.512,52.487 57.238,52.487 59.45,54.7 60.033,54.7 60.246,54.913 60.671,54.913 60.913,54.671 60.913,50.077 61.8,49.189 61.8,36.3 60.837,35.337 60.837,30.27 62.863,28.245 62.863,22.438 63.95,21.35 v1(64.05,21.35)
  Layer 10 w0.125: v1(40.7,59.1) 43.267,59.1 46.05,56.317 46.05,53.2 v1(47.95,51.3)
  Bottom Layer w0.125: v1(40.7,59.1) 40.7,56.45 41.13,56.02 R22.1@42,56.02 42.98,56.02 U7.4@43.05,56.09
RGMII_1V2: C57.2 C58.2 C59.2 L4.2 L5.1 U10.4 U10.9 U11.1 U11.2 U11.5 U11.6 U11.7 | length 14.9
  Top Layer w0.125: C58.2@25.835,31.25 v1(26.625,31.25) 27.25,31.25 27.5,31.5 U10.9@28.425,31.5 ; C59.2@25.835,34 v1(26.625,34) U10.4@28.425,34
  Top Layer w0.25: L4.2@37.23,39.125 38.35,39.125 v1(38.725,39.5)
  Bottom Layer w0.125: C57.2@25.835,30.125 26.625,30.915 v1(26.625,31.25)
  Bottom Layer w0.5: L5.1@27.2,41.98 27.245,42.025 v1@33.65,42.025
  other v1: 32,40.85 32,41.45 31.75,42 32.5,42 33.1,42 33.65,42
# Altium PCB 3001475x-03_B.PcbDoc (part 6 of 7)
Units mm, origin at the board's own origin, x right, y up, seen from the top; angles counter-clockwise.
Board outline 100 x 72 mm, 12 copper layers (Top Layer, L2 GND, Layer 3, L4 GND, Layer 5, L6 PWR, L7 3V3, Layer 8, L9 GND, Layer 10, L11 GND, Bottom Layer), stack 1.735 mm thick; 431 components, 499 nets, 1977 pads, 1473 vias.

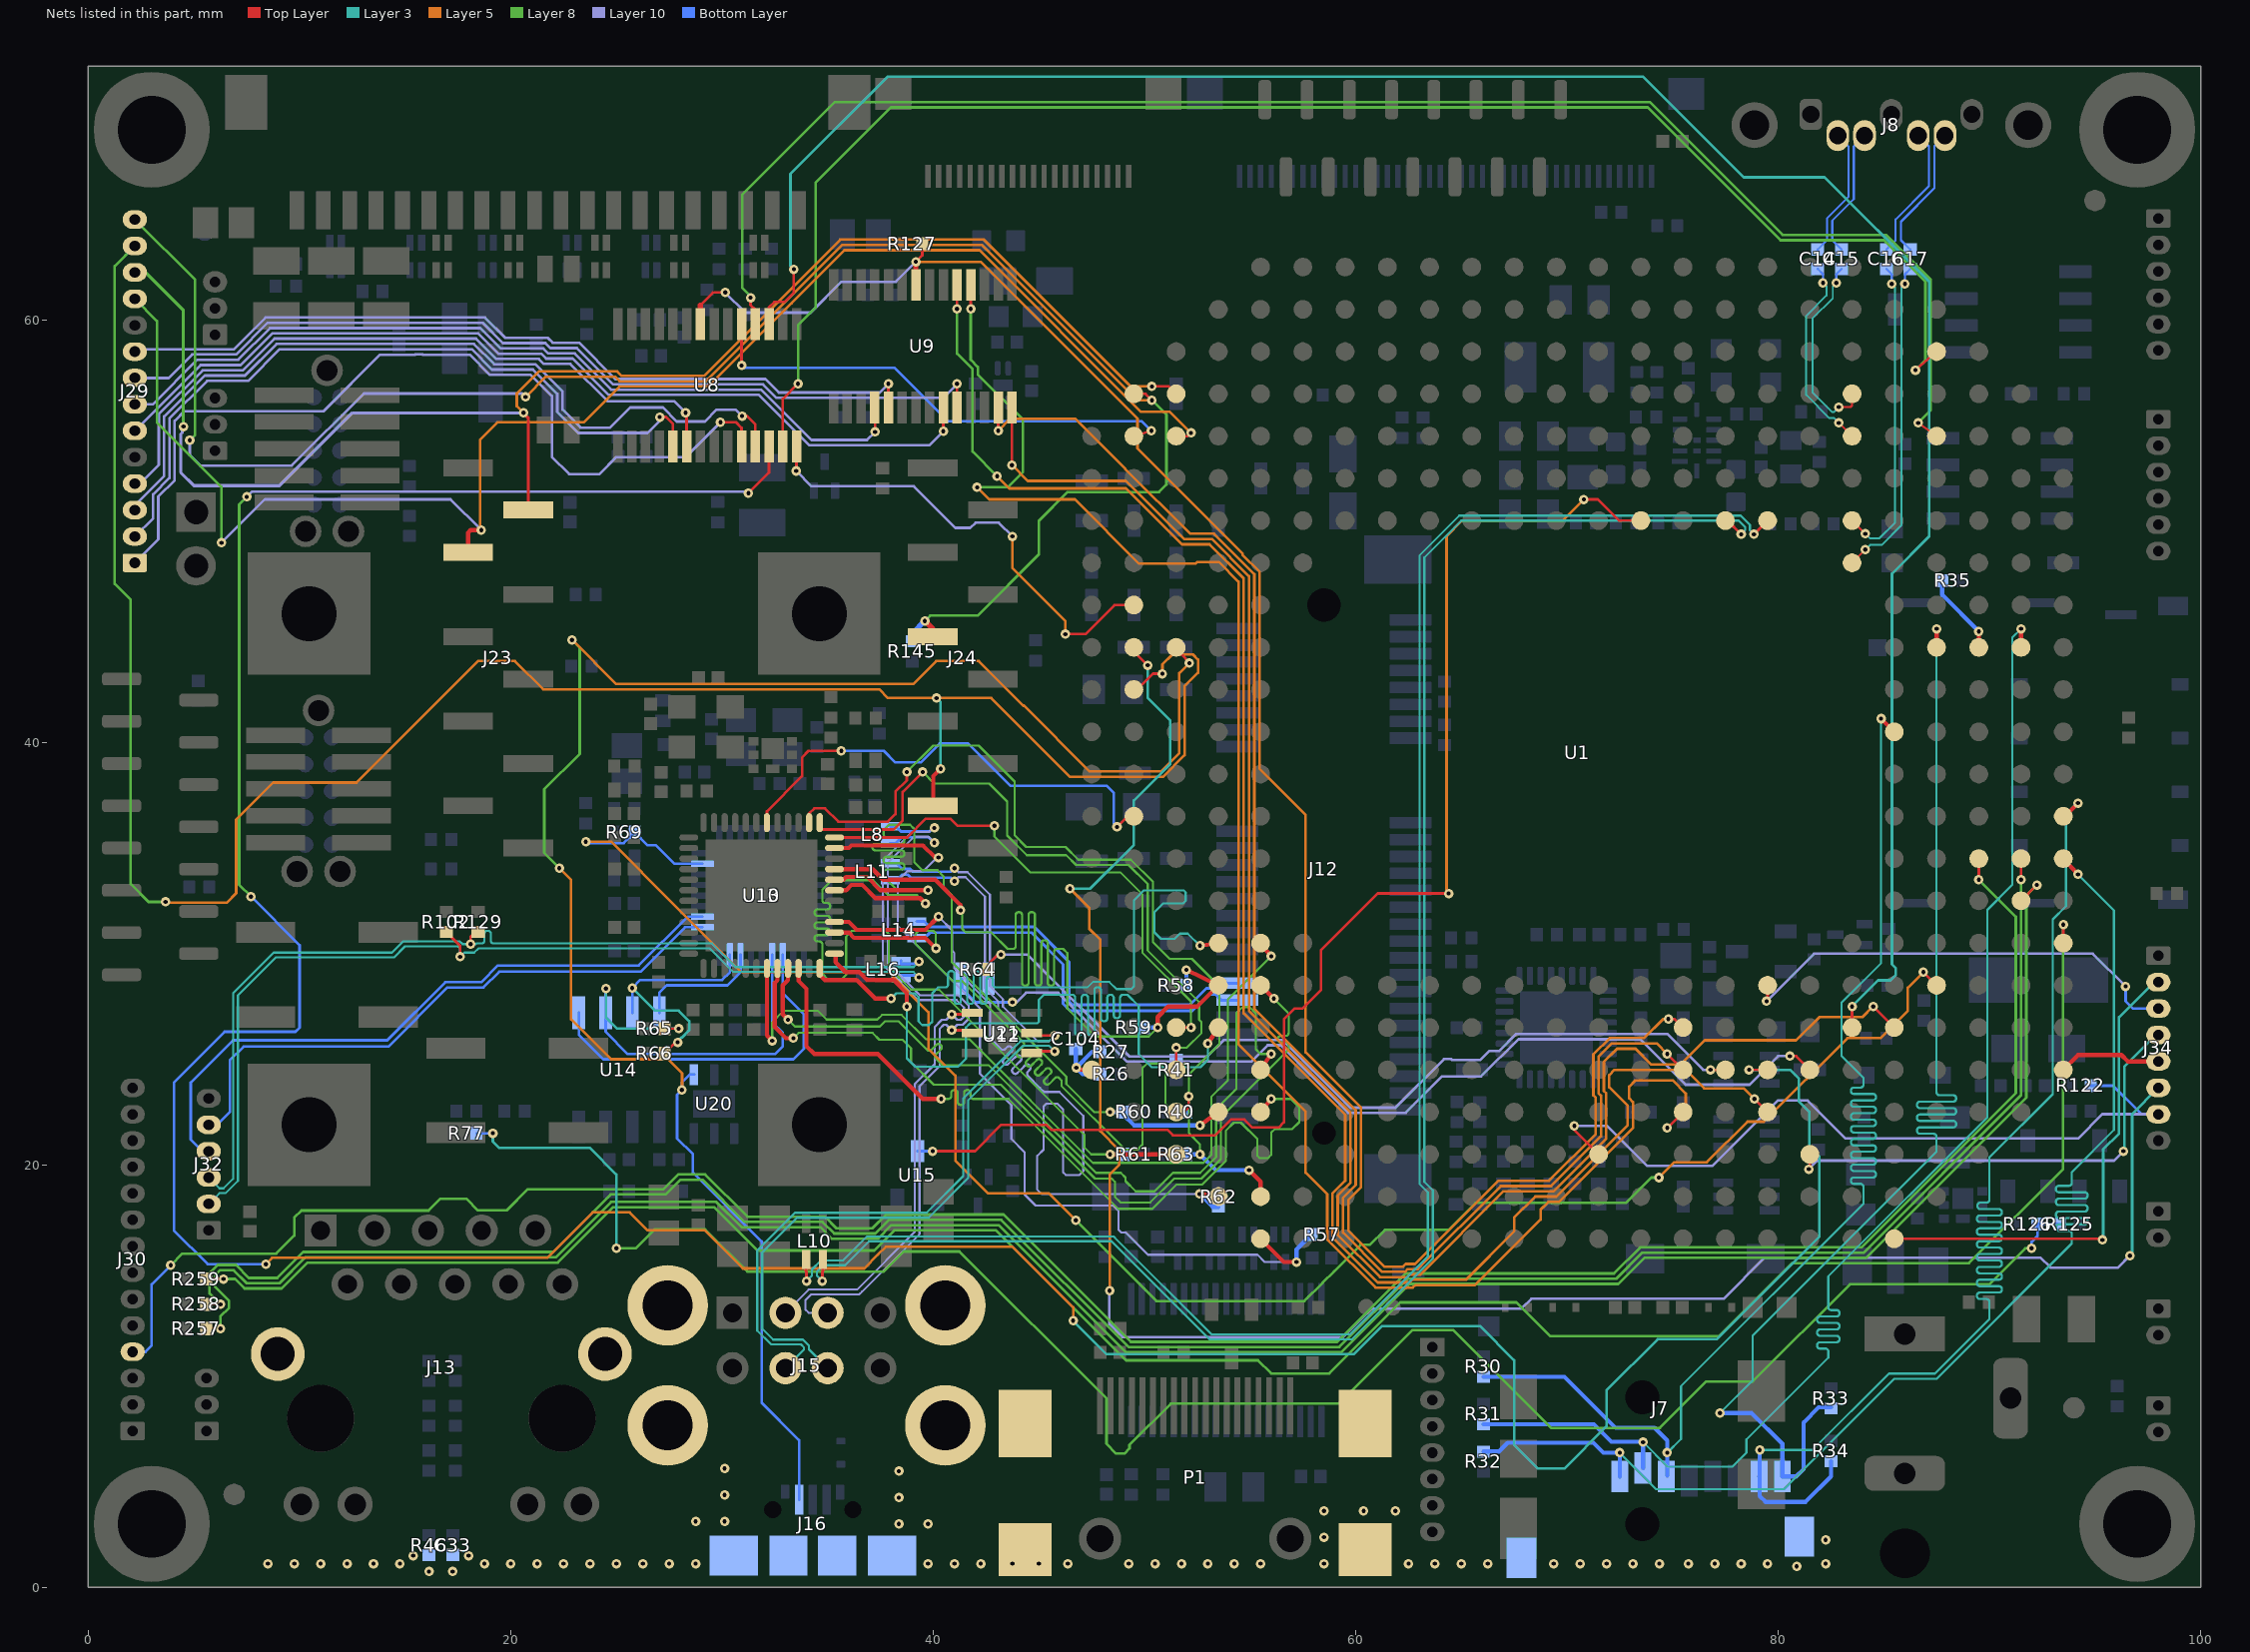
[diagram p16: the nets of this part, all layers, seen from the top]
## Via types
v1: diameter 0.45, hole 0.2, Top Layer to Bottom Layer, tented both sides, 1473 vias

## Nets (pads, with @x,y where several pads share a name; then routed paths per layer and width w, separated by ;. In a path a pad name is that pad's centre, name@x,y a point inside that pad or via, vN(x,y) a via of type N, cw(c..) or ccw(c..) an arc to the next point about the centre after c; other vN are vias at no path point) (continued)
RGMII_INT_N: R40.1 U1.AA3 U10.38 | length 38.3
  Top Layer w0.125: U10.38@34.125,36.2 34.125,36.625 34.375,36.875 34.875,36.875 35.5,36.25 37.85,36.25 38.213,36.613 38.213,37.666 38.75,38.204 v1(38.75,38.6) ; U1.AA3@51.5,22.5 51.875,22.5 52.1,22.725 v1(52.1,23.25)
  Layer 8 w0.103: v1(38.75,38.6) 40,39.85 42.15,39.85 43.85,38.15 43.85,35.6 44.4,35.05 46.262,35.05 46.862,34.45 49.35,34.45 50.4,33.4 50.4,30.55 51.2,29.75 52.25,29.75 53.55,28.45 53.55,25.717 53.171,25.337 53.15,25.337 52.1,24.287 v1(52.1,23.25)
  Bottom Layer w0.125: R40.1@51.98,22.5 52.1,22.62 v1(52.1,23.25)
RGMII_MDC: U1.W3 U10.36 | length 24.7
  Top Layer w0.125: U10.36@35.325,35.5 38.763,35.5 39.65,36.387 40.813,36.387 41.151,36.05 v1(42.9,36.05) ; U1.W3@51.5,26.5 v1(52.2,26.5)
  Layer 8 w0.103: v1(42.9,36.05) 42.9,35.55 44.613,33.837 48.871,33.837 49.9,32.808 49.9,30.046 52.2,27.746 v1(52.2,26.5)
RGMII_MDIO: R41.1 U1.Y3 U10.37 | length 32.1
  Top Layer w0.125: U10.37@34.625,36.2 34.625,35.875 38.125,35.875 38.55,36.3 38.55,37.65 v1(39.5,38.6) ; U1.Y3@51.5,24.5 v1(51.5,25.55)
  Layer 8 w0.103: v1(39.5,38.6) 40.05,38.05 42.649,38.05 43.5,37.199 43.5,35.596 44.434,34.663 46.296,34.663 46.758,34.2 49.246,34.2 50.15,33.296 50.15,30.15 52.587,27.713 52.587,26.867 52.7,26.754 52.7,26.25 52,25.55 v1(51.5,25.55)
  Bottom Layer w0.125: R41.1@51.5,24.98 v1(51.5,25.55)
RGMII_RD0: R60.1 U1.AA4 U10.32 | length 41.3
  Top Layer w0.2: U10.32@35.325,33.5 35.75,33.5 35.875,33.625 36.875,33.625 37.5,33 v1(39.75,33) ; v1(52.625,21.875) U1.AA4@53.5,22.5
  Layer 8 w0.103: v1(39.75,33) 38.3,33 37.65,33.65 37.65,33.841 cw(c37.787,33.841) 37.787,33.978 38.494,33.978 ccw(c38.494,34.115) 38.631,34.115 38.631,34.145 ccw(c38.494,34.145) 38.494,34.282 37.787,34.282 cw(c37.787,34.419) 37.65,34.419 37.65,34.449 cw(c37.787,34.449) 37.787,34.586 38.494,34.586 ccw(c38.494,34.723) 38.631,34.723 38.631,34.753 ccw(c38.494,34.753) 38.494,34.89 37.65,34.89 37.257,34.89 cw(c37.257,35.027) 37.12,35.027 37.12,35.057 cw(c37.257,35.057) 37.257,35.194 37.65,35.194 38.494,35.194 ccw(c38.494,35.331) 38.631,35.331 38.631,35.361 ccw(c38.494,35.361) 38.494,35.498 37.787,35.498 cw(c37.787,35.635) 37.65,35.635 37.65,35.65 37.65,35.85 37.9,36.1 38.9,36.1 39.098,35.902 39.098,34.333 39.481,33.95 40.2,33.95 40.5,33.65 40.5,33.15 40.875,32.775 40.875,31.875 ; 40.875,31.55 40.875,31.875 ; v1(48.375,22.5) 47.631,22.5 46.298,23.833 46.298,24.176 40.875,29.599 40.875,31.875
  Bottom Layer w0.2: v1(48.375,22.5) R60.1@49.02,22.5 49.02,22.355 49.5,21.875 v1(52.625,21.875)
RGMII_RD1: R61.1 U1.AB3 U10.31 | length 43
  Top Layer w0.2: U10.31@35.325,33 35.875,33 36.125,33.25 36.636,33.25 37.261,32.625 39.375,32.625 v1(39.625,32.375) ; v1(48.375,20.5) U1.AB3@51.5,20.5
  Layer 8 w0.103: v1(39.625,32.375) 39.229,32.771 37.854,32.771 37.15,33.475 35.2,33.475 34.75,33.025 34.75,32.535 ccw(c34.887,32.535) 34.887,32.398 34.982,32.398 cw(c34.982,32.261) 35.119,32.261 35.119,32.231 cw(c34.982,32.231) 34.982,32.094 34.518,32.094 ccw(c34.518,31.957) 34.381,31.957 34.381,31.927 ccw(c34.518,31.927) 34.518,31.79 34.982,31.79 cw(c34.982,31.653) 35.119,31.653 35.119,31.623 cw(c34.982,31.623) 34.982,31.486 34.518,31.486 ccw(c34.518,31.349) 34.381,31.349 34.381,31.319 ccw(c34.518,31.319) 34.518,31.182 34.982,31.182 cw(c34.982,31.045) 35.119,31.045 35.119,31.015 cw(c34.982,31.015) 34.982,30.878 34.518,30.878 ccw(c34.518,30.741) 34.381,30.741 34.381,30.711 ccw(c34.518,30.711) 34.518,30.574 34.613,30.574 cw(c34.613,30.437) 34.75,30.437 34.75,29.05 35,28.8 35.675,28.8 35.875,29 35.875,30.8 36.15,31.075 37.75,31.075 37.9,30.925 37.9,29.35 38.95,28.3 40.269,28.3 47.148,21.421 47.148,20.833 47.481,20.5 v1(48.375,20.5)
  Bottom Layer w0.2: v1(48.375,20.5) R61.1@49.02,20.5
RGMII_RD2: R62.1 U1.AC4 U10.28 | length 43
  Top Layer w0.2: U10.28@35.325,31.5 36,31.5 36.375,31.125 39.625,31.125 v1(40.25,31.75) ; v1(52.605,18.625) 53.375,18.625 U1.AC4@53.5,18.5
  Layer 10 w0.103: v1(40.25,31.75) 40.898,31.102 40.898,30.133 41,30.031 41,29.302 42.69,27.613 42.69,26.91 42.7,26.9 42.7,26 43.2,25.5 43.211,25.489 ccw(c43.307,25.586) 43.404,25.489 43.492,25.577 cw(c43.589,25.48) 43.685,25.577 43.707,25.556 cw(c43.61,25.459) 43.707,25.362 43.522,25.178 43.338,24.993 ccw(c43.435,24.896) 43.338,24.8 43.359,24.778 ccw(c43.456,24.875) 43.553,24.778 43.737,24.963 43.922,25.147 cw(c44.019,25.05) 44.115,25.147 44.137,25.126 cw(c44.04,25.029) 44.137,24.932 43.952,24.748 43.768,24.563 ccw(c43.865,24.466) 43.768,24.37 43.789,24.348 ccw(c43.886,24.445) 43.983,24.348 44.167,24.533 44.352,24.717 cw(c44.449,24.62) 44.545,24.717 44.567,24.696 cw(c44.47,24.599) 44.567,24.502 44.479,24.414 ccw(c44.576,24.318) 44.479,24.221 45.05,23.65 45.25,23.45 45.975,23.45 47.1,22.325 47.1,19.7 46.925,19.525 46.275,19.525 46.15,19.65 46.15,22.625 45.875,22.9 45.35,22.9 45.225,22.775 45.225,20.725 44.925,20.425 44.925,18.825 45.125,18.625 v1(52.605,18.625)
  Bottom Layer w0.2: v1(52.605,18.625) 53.21,18.02 R62.1@53.5,18.02
RGMII_RD3: R63.1 U1.AC5 U10.27 | length 41.6
  Top Layer w0.2: U10.27@35.325,31 36,31 36.25,30.75 39.625,30.75 v1(40.125,30.25) ; v1(54.95,19.75) 55.5,19.2 U1.AC5@55.5,18.5
  Layer 8 w0.103: v1(40.125,30.25) 40.125,30.95 40,31.075 39.3,31.075 39.15,30.925 39.15,30.475 40.925,28.7 41.369,28.7 43.684,26.384 44.26,25.809 cw(c44.163,25.712) 44.26,25.615 43.988,25.344 ccw(c44.085,25.247) 43.988,25.151 44.01,25.129 ccw(c44.107,25.226) 44.203,25.129 44.475,25.401 cw(c44.571,25.304) 44.668,25.401 44.69,25.379 cw(c44.593,25.282) 44.69,25.186 44.418,24.914 ccw(c44.515,24.818) 44.418,24.721 44.44,24.699 ccw(c44.536,24.796) 44.633,24.699 44.904,24.971 cw(c45.001,24.874) 45.098,24.971 45.119,24.949 cw(c45.023,24.852) 45.119,24.756 44.848,24.484 ccw(c44.945,24.388) 44.848,24.291 44.87,24.269 ccw(c44.966,24.366) 45.063,24.269 45.334,24.541 cw(c45.431,24.444) 45.528,24.541 45.549,24.519 cw(c45.453,24.422) 45.549,24.326 45.278,24.054 ccw(c45.375,23.958) 45.278,23.861 45.3,23.84 ccw(c45.396,23.936) 45.493,23.839 45.764,24.111 cw(c45.861,24.014) 45.958,24.111 45.969,24.1 46.069,24 46.069,23.739 49.085,20.723 49.667,20.723 49.902,20.958 49.902,21.798 49.9,21.8 49.9,24.575 50.125,24.8 50.725,24.8 51,24.525 51,22.875 51.175,22.7 51.975,22.7 52.1,22.575 52.1,21.5 52.625,20.975 v1(52.625,20.5)
  Bottom Layer w0.2: R63.1@51.98,20.5 v1(52.625,20.5) 53.375,19.75 v1(54.95,19.75)
RGMII_REF_CLK: C104.1 R26.1 R27.2 U1.Y1 | length 4.4
  Top Layer w0.2: v1(46.775,24.6) 46.875,24.5 U1.Y1@47.5,24.5
  Bottom Layer w0.2: C104.1@46.75,25.49 46.75,24.625 v1(46.775,24.6) ; R26.1@47.92,24.3 47.075,24.3 v1(46.775,24.6) ; R27.2@47.92,25.35 47.525,25.35 v1(46.775,24.6)
RGMII_RESET_N: U1.P2 U10.42 | length 22.9
  Top Layer w0.125: U10.42@32.125,36.2 32.125,36.738 33.787,38.401 33.787,39.287 34.1,39.6 v1(35.65,39.6) ; v1(48.7,36) 49.2,36.5 U1.P2@49.5,36.5
  Bottom Layer w0.125: v1(35.65,39.6) 37.65,39.6 38.2,39.05 39.4,39.05 40.3,39.95 41.649,39.95 43.649,37.95 48.213,37.95 48.55,37.613 48.55,36.15 v1(48.7,36)
RGMII_RX_CTL: R58.1 R59.1 U1.V4 U10.33 | length 45.4
  Top Layer w0.2: U10.33@35.325,34 36,34 37.125,34 37.625,33.5 40.092,33.5 41.3,32.292 v1(41.3,32.05) ; v1(50.625,26.5) 50.625,27 51.125,27.5 52.5,27.5 U1.V4@53.5,28.5 v1(51.98,29.23)
  Layer 8 w0.103: v1(41.3,32.05) 41.375,31.975 41.375,31.175 41.55,31 41.775,31 42.75,31 43.525,30.225 43.75,30.225 43.765,30.225 ccw(c43.765,30.362) 43.902,30.362 43.902,31.83 cw(c44.039,31.83) 44.039,31.966 44.069,31.966 cw(c44.069,31.83) 44.206,31.83 44.206,30.225 44.206,28.62 ccw(c44.343,28.62) 44.343,28.484 44.373,28.484 ccw(c44.373,28.62) 44.51,28.62 44.51,30.225 44.51,31.83 cw(c44.647,31.83) 44.647,31.966 44.677,31.966 cw(c44.677,31.83) 44.814,31.83 44.814,30.225 44.814,28.62 ccw(c44.951,28.62) 44.951,28.484 44.981,28.484 ccw(c44.981,28.62) 45.118,28.62 45.118,30.225 45.118,30.498 cw(c45.255,30.498) 45.255,30.634 45.285,30.634 cw(c45.285,30.498) 45.422,30.498 45.422,30.225 45.422,28.62 ccw(c45.559,28.62) 45.559,28.484 45.589,28.484 ccw(c45.589,28.62) 45.726,28.62 45.726,30.101 cw(c45.85,30.101) 45.85,30.225 46.15,30.225 46.35,30.025 46.35,27.4 47.675,26.075 50.2,26.075 v1(50.625,26.5)
  Bottom Layer w0.2: R59.1@49.98,26.5 v1(50.625,26.5) ; R58.1@51.98,28.5 v1(51.98,29.23)
RGMII_RXC: R57.1 U1.AD5 U10.35 | length 43.4
  Top Layer w0.2: U10.35@35.325,35 36,35 36.125,35.125 39.38,35.125 39.511,35.125 40.086,34.55 v1(40.25,34.55) ; U1.AD5@55.5,16.5 56.6,15.4 v1(57.2,15.4)
  Layer 10 w0.103: v1(40.25,34.55) 40.175,34.55 39.525,33.9 38.775,33.9 38.325,33.45 38.325,31.3 42.21,27.415 42.21,24.315 43.7,22.825 43.7,21.225 44.325,20.6 44.325,18.6 44.85,18.075 48.525,18.075 48.775,17.825 48.775,16.925 48.9,16.8 49.117,16.8 50.167,15.75 55.35,15.75 55.7,15.4 v1(57.2,15.4)
  Bottom Layer w0.2: v1(57.2,15.4) 57.2,15.992 57.908,16.7 R57.1@57.92,16.7
RGMII_TD0: U1.U5 U10.19 | length 40.1
  Top Layer w0.2: U10.19@32.125,29.3 32.125,26.125 v1(32.375,25.875) ; U1.U5@55.5,30.5 v1(56,29.875)
  Layer 8 w0.103: v1(32.375,25.875) 32.375,26.75 32.925,27.3 34.525,27.3 34.946,26.879 37.354,26.879 37.575,27.1 38.5,27.1 39.646,25.954 41.704,25.954 47.56,20.098 52.792,20.098 53.161,20.467 53.161,23.211 53.95,24 53.95,27.828 55.781,29.659 55.784,29.659 v1(56,29.875)
RGMII_TD1: U1.V5 U10.20 | length 40.1
  Top Layer w0.2: U10.20@32.625,29.3 32.625,28.75 32.5,28.625 32.5,26.525 33.025,26 v1(33.375,26) ; U1.V5@55.5,28.5 v1(56.125,27.875)
  Layer 8 w0.103: v1(33.375,26) 33.625,26.25 37.125,26.25 37.45,25.925 38.55,25.925 38.95,25.525 38.95,24.875 40.025,23.8 43.21,23.8 47.66,19.35 48.45,19.35 48.6,19.2 48.6,18.494 48.869,18.225 50.275,18.225 51.4,19.35 52.691,19.35 53.619,20.278 53.619,22.244 56.825,25.45 56.825,25.65 56.825,25.665 ccw(c56.688,25.665) 56.688,25.802 56.45,25.802 cw(c56.45,25.939) 56.314,25.939 56.314,25.969 cw(c56.45,25.969) 56.45,26.106 56.688,26.106 ccw(c56.688,26.243) 56.825,26.243 56.825,27.175 v1(56.125,27.875)
RGMII_TD2: U1.Y5 U10.21 | length 40
  Top Layer w0.2: v1(33.125,26.875) 32.875,27.125 32.875,28.5 33.125,28.75 U10.21@33.125,29.3 ; U1.Y5@55.5,24.5 v1(56,25.25)
  Layer 8 w0.103: v1(33.125,26.875) 33.45,26.55 37.475,26.55 37.725,26.8 38.35,26.8 39.7,25.45 39.711,25.439 ccw(c39.807,25.536) 39.904,25.439 40.15,25.685 cw(c40.247,25.588) 40.343,25.685 40.365,25.663 cw(c40.268,25.567) 40.365,25.47 40.119,25.224 ccw(c40.216,25.128) 40.119,25.031 40.425,24.725 42.609,24.725 47.709,19.625 48.875,19.625 49.1,19.4 49.1,19.231 49.583,18.748 50.474,18.748 51.351,19.625 52.642,19.625 53.39,20.373 53.39,22.64 54.35,23.6 54.35,27.175 54.65,27.475 54.975,27.475 55.275,27.175 55.275,25.475 55.5,25.25 v1(56,25.25)
RGMII_TD3: U1.AA5 U10.22 | length 40.1
  Top Layer w0.2: U10.22@33.625,29.3 33.625,28.708 34,28.333 34,25.625 34.375,25.25 37.375,25.25 39.5,23.125 v1(40.375,23.125) ; U1.AA5@55.5,22.5 v1(56,23.125)
  Layer 8 w0.103: v1(40.375,23.125) 40.7,23.125 40.715,23.125 ccw(c40.715,23.262) 40.852,23.262 40.852,23.408 cw(c40.989,23.408) 40.989,23.545 41.019,23.545 cw(c41.019,23.408) 41.156,23.408 41.156,23.125 41.156,22.977 ccw(c41.293,22.977) 41.293,22.84 41.323,22.84 ccw(c41.323,22.977) 41.46,22.977 41.46,23.125 41.46,23.408 cw(c41.597,23.408) 41.597,23.545 41.627,23.545 cw(c41.627,23.408) 41.764,23.408 41.764,23.262 ccw(c41.901,23.262) 41.901,23.125 43.55,23.125 43.561,23.125 48.761,17.925 50.375,17.925 51.525,19.075 52.74,19.075 53.848,20.183 53.848,21.617 54.233,22.002 54.567,22.002 55.35,21.219 55.35,20.425 55.45,20.325 55.85,20.325 56,20.475 56,21.525 56.175,21.7 57,21.7 57.325,22.025 57.325,22.725 56.925,23.125 v1(56,23.125)
RGMII_TX_CTL: U1.W4 U10.25 | length 41.5
  Top Layer w0.2: U10.25@35.375,29.95 35.375,29.6 35.85,29.125 36.5,29.125 36.875,28.75 38.125,28.75 38.75,28.125 v1(38.75,27.5) ; v1(53,25.75) U1.W4@53.5,26.5
  Layer 3 w0.103: v1(38.75,27.5) 38.75,25.05 39.15,24.65 41.175,24.65 41.55,25.025 41.55,26.5 41.75,26.7 44.925,26.7 44.998,26.773 44.998,27.817 45.233,28.052 45.45,28.052 46.583,28.052 cw(c46.583,27.915) 46.72,27.915 46.72,26.264 ccw(c46.857,26.264) 46.857,26.127 46.887,26.127 ccw(c46.887,26.264) 47.024,26.264 47.024,27.915 cw(c47.161,27.915) 47.161,28.052 47.191,28.052 cw(c47.191,27.915) 47.328,27.915 47.328,26.264 ccw(c47.465,26.264) 47.465,26.127 47.495,26.127 ccw(c47.495,26.264) 47.632,26.264 47.632,28.052 47.632,28.276 cw(c47.769,28.276) 47.769,28.413 47.799,28.413 cw(c47.799,28.276) 47.936,28.276 47.936,28.052 47.936,26.94 ccw(c48.073,26.94) 48.073,26.803 48.103,26.803 ccw(c48.103,26.94) 48.24,26.94 48.24,27.915 cw(c48.377,27.915) 48.377,28.052 48.407,28.052 cw(c48.407,27.915) 48.544,27.915 48.544,27.083 ccw(c48.681,27.083) 48.681,26.946 48.711,26.946 ccw(c48.711,27.083) 48.848,27.083 48.848,27.915 cw(c48.985,27.915) 48.985,28.052 49,28.052 49.198,28.052 49.725,27.525 49.725,25.25 50.35,24.625 52.65,24.625 53,24.975 v1(53,25.75)
RGMII_TXC: U1.U4 U10.24 | length 41.6
  Top Layer w0.2: U10.24@34.625,29.3 34.625,29 34.875,28.75 36.375,28.75 37.25,27.875 v1(38,27.875) ; v1(52.625,30.375) U1.U4@53.5,30.5
  Layer 3 w0.103: v1(38,27.875) 38.25,28.125 39.125,28.125 39.3,27.95 39.3,26.8 39.475,26.625 39.8,26.625 39.95,26.775 39.95,28.125 40.225,28.4 40.55,28.4 40.565,28.4 ccw(c40.565,28.536) 40.701,28.536 40.701,29.039 cw(c40.838,29.039) 40.838,29.176 40.868,29.176 cw(c40.868,29.039) 41.004,29.039 41.004,28.4 41.004,27.761 ccw(c41.141,27.761) 41.141,27.624 41.171,27.624 ccw(c41.171,27.761) 41.307,27.761 41.307,28.4 41.307,29.039 cw(c41.444,29.039) 41.444,29.176 41.474,29.176 cw(c41.474,29.039) 41.61,29.039 41.61,28.4 41.61,27.761 ccw(c41.747,27.761) 41.747,27.624 41.777,27.624 ccw(c41.777,27.761) 41.913,27.761 41.913,28.4 41.913,29.039 cw(c42.05,29.039) 42.05,29.176 42.08,29.176 cw(c42.08,29.039) 42.216,29.039 42.216,28.4 42.216,27.761 ccw(c42.353,27.761) 42.353,27.624 42.383,27.624 ccw(c42.383,27.761) 42.519,27.761 42.519,28.4 42.519,28.767 cw(c42.656,28.767) 42.656,28.903 42.686,28.903 cw(c42.686,28.767) 42.822,28.767 42.822,28.536 ccw(c42.959,28.536) 42.959,28.4 43.4,28.4 47.3,28.4 47.56,28.66 48.34,28.66 48.675,28.325 49.375,28.325 49.5,28.45 49.5,32.525 49.975,33 51.85,33 51.95,32.9 51.95,32.5 51.825,32.375 50.881,32.375 50.473,31.967 50.473,31.008 50.783,30.698 51.423,30.698 51.675,30.95 52.05,30.95 v1(52.625,30.375)
RS232_1_CTS_N: J29.4 U8.6 | length 33.4
  Top Layer w0.125: v1(28.275,55.605) 28.325,55.555 U8.6@28.325,54.005
  Layer 10 w0.125: J29.4@2.2,52.25 2.45,52.25 3.337,53.137 3.337,55.534 5.416,57.612 7.309,57.612 8.809,59.112 18.354,59.112 19.317,58.15 21.331,58.15 21.565,57.916 22.82,57.916 24.586,56.15 27.73,56.15 v1(28.275,55.605)
RS232_1_RTS_N: J29.3 U8.11 | length 38.6
  Top Layer w0.125: 31.175,55.455 31.575,55.055 U8.11@31.575,54.005
  Layer 10 w0.125: J29.3@2.2,51 2.2,51.229 3.587,52.616 3.587,55.43 5.52,57.362 7.412,57.362 8.912,58.862 18.251,58.862 19.213,57.9 21.15,57.9 22.45,56.6 22.45,55.754 23.304,54.9 24.7,54.9 25.65,55.85 27.2,55.85 27.858,55.192 29.192,55.192 29.75,55.75 30.65,55.75 v1(30.95,55.45)
RS232_1_RX: J29.2 U8.5 | length 35.2
  Top Layer w0.125: v1(27.05,55.4) 27.343,55.4 27.675,55.068 U8.5@27.675,54.005
  Layer 10 w0.125: J29.2@2.2,49.75 3.064,50.614 3.064,51.739 3.837,52.513 3.837,55.327 5.623,57.112 7.562,57.112 9.062,58.612 18.147,58.612 19.11,57.65 21.046,57.65 22.2,56.496 22.2,55.65 23.2,54.65 26.478,54.65 27.05,55.222 v1(27.05,55.4)
RS232_1_TX: J29.1 U8.10 | length 41.7
  Top Layer w0.125: v1(29.925,55.155) 30.662,55.155 30.925,54.892 U8.10@30.925,54.005
  Layer 10 w0.125: J29.1@2.2,48.5 3.314,49.614 3.314,51.636 4.087,52.409 4.087,55.223 4.539,55.675 11.143,55.675 13.818,58.35 15.467,58.35 15.479,58.363 15.821,58.363 15.833,58.35 18.056,58.35 19.006,57.4 20.943,57.4 21.95,56.393 21.95,53.507 22.757,52.7 24.2,52.7 25,53.5 28.27,53.5 v1(29.925,55.155)
RS232_3_CTS_N: J29.9 U9.5 | length 39.1
  Top Layer w0.125: U9.5@37.875,55.85 v1(37.875,56.975)
  Layer 10 w0.125: J29.9@2.2,58.5 2.312,58.612 6.895,58.612 8.395,60.112 18.769,60.112 19.731,59.15 21.745,59.15 21.979,58.916 23.234,58.916 24.95,57.2 32.05,57.2 32.688,56.562 37.462,56.562 v1(37.875,56.975)
RS232_3_RTS_N: J29.8 U9.10 | length 42.9
  Top Layer w0.125: U9.10@41.125,55.85 v1(41.125,56.975)
  Layer 10 w0.125: J29.8@2.2,57.25 3.8,57.25 4.912,58.362 6.998,58.362 8.498,59.862 18.665,59.862 19.627,58.9 21.641,58.9 21.875,58.666 23.13,58.666 24.846,56.95 31.946,56.95 32.584,56.312 40.462,56.312 v1(41.125,56.975)
RS232_3_RX: J29.7 U9.4 | length 40.1
  Top Layer w0.125: U9.4@37.225,55.85 37.25,55.825 v1(37.25,54.7)
  Layer 10 w0.125: J29.7@2.2,56 3.05,56 5.162,58.112 7.102,58.112 8.602,59.612 18.561,59.612 19.524,58.65 21.538,58.65 21.772,58.416 23.027,58.416 24.743,56.7 31.843,56.7 34.23,54.312 36.862,54.312 v1(37.25,54.7)
RS232_3_TX: J29.6 U9.9 | length 43.8
  Top Layer w0.125: v1(40.475,54.725) U9.9@40.475,55.85
  Layer 10 w0.125: J29.6@2.2,54.75 5.312,57.862 7.205,57.862 8.705,59.362 18.458,59.362 19.42,58.4 21.434,58.4 21.668,58.166 22.923,58.166 24.639,56.45 31.739,56.45 34.127,54.062 39.812,54.062 v1(40.475,54.725)
RST: R77.2 R125.1 R126.1 | length 95.2
  Layer 8 w0.125: v1(25,16.05) 25.9,16.05 26.8,16.95 29.2,16.95 31.2,14.95 37.65,14.95 38.6,15.9 41.239,15.9 48.2,8.939 48.2,6.8 48.663,6.337 49.046,6.337 49.288,6.579 49.288,6.746 51.242,8.7 59.2,8.7 62.675,12.175 64.625,12.175 69.25,7.55 74.4,7.55 76.6,9.75 78.8,9.75 83.4,14.35 90,14.35 91.7,16.05 v1(92,16.05)
  Layer 3 w0.125: v1(19.15,21.5) 19.15,21.1 19.437,20.813 23.737,20.813 25,19.55 v1(25,16.05)
  Bottom Layer w0.125: R77.2@18.38,21.5 v1(19.15,21.5) ; v1(92,16.05) 92,16.35 92.28,16.63 R126.1@92.28,17.2 R125.1@93.32,17.2
SATA_RX_N: C16.1 U1.G19 | length 14.8
  Top Layer w0.104: U1.G19@83.5,50.5 v1(84.125,49.875)
  Layer 3 w0.093: v1(84.125,49.875) 84.35,49.65 84.775,49.65 85.538,50.413 85.538,61.537 v1(85.375,61.7)
  Bottom Layer w0.104: C16.1@85.125,62.415 85.375,62.165 v1@85.375,61.75
SATA_RX_P: C17.1 U1.H19 | length 15.3
  Top Layer w0.104: U1.H19@83.5,48.5 v1(84.125,49.125)
  Layer 3 w0.093: v1(84.125,49.125) 84.35,49.35 84.899,49.35 85.838,50.288 85.838,61.538 v1(86,61.7)
  Bottom Layer w0.104: v1@86,61.75 86,62.165 C17.1@86.25,62.415
SATA_TX_N: C15.1 U1.D19 | length 9.3
  Top Layer w0.104: v1(82.875,55.875) 83.425,55.875 83.5,55.95 U1.D19@83.5,56.5
  Layer 3 w0.093: v1(82.75,61.75) 82.588,61.588 82.588,61.026 81.625,60.063 81.625,56.575 82.55,55.65 82.65,55.65 v1(82.875,55.875)
  Bottom Layer w0.104: v1(82.75,61.75) 82.75,62.165 C15.1@83,62.415
SATA_TX_P: C14.1 U1.E19 | length 9.5
  Top Layer w0.104: v1(82.875,55.125) U1.E19@83.5,54.5
  Layer 3 w0.093: v1(82.125,61.75) 82.288,61.587 82.288,61.15 81.325,60.188 81.325,56.451 82.426,55.35 82.65,55.35 v1(82.875,55.125)
  Bottom Layer w0.104: C14.1@81.875,62.415 82.125,62.165 v1(82.125,61.75)
SATARX_N: C16.2 J8.5 | length 6.4
  Bottom Layer w0.104: C16.2@85.125,63.335 85.56,63.77 85.56,64.756 87.137,66.333 87.137,68.217 J8.5@86.63,68.725
SATARX_P: C17.2 J8.6 | length 6.4
  Bottom Layer w0.104: C17.2@86.25,63.335 85.815,63.77 85.815,64.65 87.392,66.227 87.392,68.217 J8.6@87.9,68.725
SATATX_N: C15.2 J8.3 | length 6.2
  Bottom Layer w0.104: C15.2@83,63.335 82.565,63.77 82.565,64.7 83.582,65.718 83.582,68.217 J8.3@84.09,68.725
SATATX_P: C14.2 J8.2 | length 6.2
  Bottom Layer w0.104: C14.2@81.875,63.335 82.31,63.77 82.31,64.806 83.327,65.823 83.327,68.217 J8.2@82.82,68.725
SD2_CLK: R35.1 U1.K22 | length 3.9
  Top Layer w0.2: U1.K22@89.5,44.5 v1(89.5,45.25)
  Bottom Layer w0.2: R35.1@87.77,47.65 87.77,46.98 v1(89.5,45.25)
SD2_CMD: J7.3 R30.1 U1.M20 | length 68.1
  Top Layer w0.2: v1(84.875,41.125) U1.M20@85.5,40.5
  Layer 3 w0.103: v1(74.75,6.375) 75.4,7.025 75.4,9.525 84.038,18.163 84.038,18.95 84.038,18.965 ccw(c83.901,18.965) 83.901,19.102 83.584,19.102 cw(c83.584,19.239) 83.448,19.239 83.448,19.269 cw(c83.584,19.269) 83.584,19.406 84.038,19.406 84.491,19.406 ccw(c84.491,19.543) 84.627,19.543 84.627,19.573 ccw(c84.491,19.573) 84.491,19.71 84.038,19.71 83.584,19.71 cw(c83.584,19.847) 83.448,19.847 83.448,19.877 cw(c83.584,19.877) 83.584,20.014 84.038,20.014 84.491,20.014 ccw(c84.491,20.151) 84.627,20.151 84.627,20.181 ccw(c84.491,20.181) 84.491,20.318 84.038,20.318 83.584,20.318 cw(c83.584,20.455) 83.448,20.455 83.448,20.485 cw(c83.584,20.485) 83.584,20.622 84.038,20.622 84.491,20.622 ccw(c84.491,20.759) 84.627,20.759 84.627,20.789 ccw(c84.491,20.789) 84.491,20.926 84.038,20.926 83.584,20.926 cw(c83.584,21.063) 83.448,21.063 83.448,21.093 cw(c83.584,21.093) 83.584,21.23 84.038,21.23 84.491,21.23 ccw(c84.491,21.367) 84.627,21.367 84.627,21.397 ccw(c84.491,21.397) 84.491,21.534 84.038,21.534 83.584,21.534 cw(c83.584,21.671) 83.448,21.671 83.448,21.701 cw(c83.584,21.701) 83.584,21.838 84.038,21.838 84.491,21.838 ccw(c84.491,21.975) 84.627,21.975 84.627,22.005 ccw(c84.491,22.005) 84.491,22.142 84.038,22.142 83.584,22.142 cw(c83.584,22.279) 83.448,22.279 83.448,22.309 cw(c83.584,22.309) 83.584,22.446 84.038,22.446 84.491,22.446 ccw(c84.491,22.583) 84.627,22.583 84.627,22.613 ccw(c84.491,22.613) 84.491,22.75 84.038,22.75 83.584,22.75 cw(c83.584,22.887) 83.448,22.887 83.448,22.917 cw(c83.584,22.917) 83.584,23.054 84.038,23.054 84.491,23.054 ccw(c84.491,23.191) 84.627,23.191 84.627,23.221 ccw(c84.491,23.221) 84.491,23.358 84.038,23.358 83.584,23.358 cw(c83.584,23.495) 83.448,23.495 83.448,23.525 cw(c83.584,23.525) 83.584,23.662 83.901,23.662 ccw(c83.901,23.799) 84.038,23.799 84.038,24.112 83,25.15 83,27.681 84.875,29.556 v1(84.875,41.125)
  Bottom Layer w0.2: R30.1@66.05,9.97 69.88,9.97 72.3,7.55 74.15,7.55 74.75,6.95 v1(74.75,6.375) J7.3@74.75,5.3
SD2_DAT0: J7.7 R34.1 U1.P24 | length 63.2
  Top Layer w0.2: U1.P24@93.5,36.5 93.575,36.5 v1(94.2,37.125)
  Layer 3 w0.103: v1(79.125,6.5) 81.625,6.5 85.25,10.125 87.425,10.125 90,12.7 90,13.5 90,13.515 ccw(c89.863,13.515) 89.863,13.652 89.546,13.652 cw(c89.546,13.789) 89.409,13.789 89.409,13.819 cw(c89.546,13.819) 89.546,13.956 90,13.956 90.454,13.956 ccw(c90.454,14.093) 90.591,14.093 90.591,14.123 ccw(c90.454,14.123) 90.454,14.26 90,14.26 89.546,14.26 cw(c89.546,14.397) 89.409,14.397 89.409,14.427 cw(c89.546,14.427) 89.546,14.564 90,14.564 90.454,14.564 ccw(c90.454,14.701) 90.591,14.701 90.591,14.731 ccw(c90.454,14.731) 90.454,14.868 90,14.868 89.546,14.868 cw(c89.546,15.005) 89.409,15.005 89.409,15.035 cw(c89.546,15.035) 89.546,15.172 90,15.172 90.454,15.172 ccw(c90.454,15.309) 90.591,15.309 90.591,15.339 ccw(c90.454,15.339) 90.454,15.476 90,15.476 89.546,15.476 cw(c89.546,15.613) 89.409,15.613 89.409,15.643 cw(c89.546,15.643) 89.546,15.78 90,15.78 90.454,15.78 ccw(c90.454,15.917) 90.591,15.917 90.591,15.947 ccw(c90.454,15.947) 90.454,16.084 90,16.084 89.546,16.084 cw(c89.546,16.221) 89.409,16.221 89.409,16.251 cw(c89.546,16.251) 89.546,16.388 90,16.388 90.454,16.388 ccw(c90.454,16.525) 90.591,16.525 90.591,16.555 ccw(c90.454,16.555) 90.454,16.692 90,16.692 89.546,16.692 cw(c89.546,16.829) 89.409,16.829 89.409,16.859 cw(c89.546,16.859) 89.546,16.996 90,16.996 90.454,16.996 ccw(c90.454,17.133) 90.591,17.133 90.591,17.163 ccw(c90.454,17.163) 90.454,17.3 90,17.3 89.546,17.3 cw(c89.546,17.437) 89.409,17.437 89.409,17.467 cw(c89.546,17.467) 89.546,17.604 90,17.604 90.454,17.604 ccw(c90.454,17.741) 90.591,17.741 90.591,17.771 ccw(c90.454,17.771) 90.454,17.908 90,17.908 89.571,17.908 cw(c89.571,18.045) 89.434,18.045 89.434,18.075 cw(c89.571,18.075) 89.571,18.212 89.863,18.212 ccw(c89.863,18.349) 90,18.349 90,20.35 93,23.35 93,31.625 93.625,32.25 93.625,36.625 v1@94.125,37.125
  Bottom Layer w0.2: J7.7@79.1,5.25 J7.7@79.125,5.275 ; v1(79.125,6.5) J7.7@79.125,5.275 ; R34.1@82.5,5.97 82.5,5.25 81.3,4.05 79.4,4.05 79.125,4.325 J7.7@79.125,5.275
SD2_DAT1: J7.8 R33.1 U1.K21 | length 62.6
  Top Layer w0.2: U1.K21@87.5,44.5 v1(87.5,45.375)
  Layer 3 w0.103: v1(77.25,8.25) 78.8,9.8 78.8,11.925 87.5,20.625 87.5,21.337 ccw(c87.363,21.337) 87.363,21.474 86.711,21.474 cw(c86.711,21.611) 86.574,21.611 86.574,21.641 cw(c86.711,21.641) 86.711,21.778 87.5,21.778 88.289,21.778 ccw(c88.289,21.915) 88.426,21.915 88.426,21.945 ccw(c88.289,21.945) 88.289,22.082 87.5,22.082 86.711,22.082 cw(c86.711,22.219) 86.574,22.219 86.574,22.249 cw(c86.711,22.249) 86.711,22.386 87.5,22.386 88.289,22.386 ccw(c88.289,22.523) 88.426,22.523 88.426,22.553 ccw(c88.289,22.553) 88.289,22.69 87.5,22.69 86.711,22.69 cw(c86.711,22.827) 86.574,22.827 86.574,22.857 cw(c86.711,22.857) 86.711,22.994 87.5,22.994 88.289,22.994 ccw(c88.289,23.131) 88.426,23.131 88.426,23.161 ccw(c88.289,23.161) 88.289,23.298 87.637,23.298 cw(c87.637,23.435) 87.5,23.435 87.5,23.45 v1(87.5,45.375)
  Bottom Layer w0.2: v1(77.25,8.25) 78.75,8.25 80.2,6.8 J7.8@80.2,5.25 80.85,5.25 81.2,5.6 81.2,7.8 81.92,8.52 R33.1@82.5,8.52
SD2_DAT2: J7.1 R32.1 U1.R24 | length 64.5
  Top Layer w0.2: U1.R24@93.5,34.5 v1(94.2,33.75)
  Layer 3 w0.103: v1(72.5,6.375) 74.225,4.65 80.275,4.65 85.5,9.875 87.5,9.875 93.9,16.275 93.9,16.729 93.9,16.744 ccw(c93.763,16.744) 93.763,16.881 93.288,16.881 cw(c93.288,17.018) 93.151,17.018 93.151,17.048 cw(c93.288,17.048) 93.288,17.185 93.9,17.185 94.512,17.185 ccw(c94.512,17.322) 94.649,17.322 94.649,17.352 ccw(c94.512,17.352) 94.512,17.489 93.9,17.489 93.288,17.489 cw(c93.288,17.626) 93.151,17.626 93.151,17.656 cw(c93.288,17.656) 93.288,17.793 93.9,17.793 94.512,17.793 ccw(c94.512,17.93) 94.649,17.93 94.649,17.96 ccw(c94.512,17.96) 94.512,18.097 93.9,18.097 93.288,18.097 cw(c93.288,18.234) 93.151,18.234 93.151,18.264 cw(c93.288,18.264) 93.288,18.401 93.9,18.401 94.512,18.401 ccw(c94.512,18.538) 94.649,18.538 94.649,18.568 ccw(c94.512,18.568) 94.512,18.705 93.9,18.705 93.288,18.705 cw(c93.288,18.842) 93.151,18.842 93.151,18.872 cw(c93.288,18.872) 93.288,19.009 93.763,19.009 ccw(c93.763,19.146) 93.9,19.146 93.9,19.65 95.9,21.65 95.9,32.05 v1(94.2,33.75)
  Bottom Layer w0.2: R32.1@66.05,6.43 66.78,6.43 67.2,6.85 71.25,6.85 71.725,6.375 v1(72.5,6.375) J7.1@72.5,5.25
SD2_DAT3: J7.2 R31.1 U1.K23 | length 65.5
  Top Layer w0.2: U1.K23@91.5,44.5 v1(91.5,45.375)
  Layer 3 w0.103: v1(73.6,6.875) 74.763,5.712 77.837,5.712 78.5,6.375 78.5,7 82.375,10.875 82.375,11.15 82.375,11.165 ccw(c82.238,11.165) 82.238,11.302 81.985,11.302 cw(c81.985,11.439) 81.849,11.439 81.849,11.469 cw(c81.985,11.469) 81.985,11.606 82.375,11.606 82.765,11.606 ccw(c82.765,11.743) 82.901,11.743 82.901,11.773 ccw(c82.765,11.773) 82.765,11.91 82.375,11.91 81.985,11.91 cw(c81.985,12.047) 81.849,12.047 81.849,12.077 cw(c81.985,12.077) 81.985,12.214 82.375,12.214 82.765,12.214 ccw(c82.765,12.351) 82.901,12.351 82.901,12.381 ccw(c82.765,12.381) 82.765,12.518 82.375,12.518 81.985,12.518 cw(c81.985,12.655) 81.849,12.655 81.849,12.685 cw(c81.985,12.685) 81.985,12.822 82.375,12.822 82.765,12.822 ccw(c82.765,12.959) 82.901,12.959 82.901,12.989 ccw(c82.765,12.989) 82.765,13.126 82.512,13.126 cw(c82.512,13.263) 82.375,13.263 82.375,14.25 82.375,14.725 89.9,22.25 89.9,32.071 91.079,33.25 91.079,44.954 v1(91.5,45.375)
  Bottom Layer w0.2: R31.1@66.05,7.72 71.28,7.72 72.1,6.9 73.575,6.9 v1(73.6,6.875) J7.2@73.6,5.65
SHLD: C33.1 J7.11 J7.12 J13.SHLD1 J13.SHLD2 J15.SH1 J15.SH2 J15.SH3 J15.SH4 J16.6 J16.7 J16.8 J16.9 P1.M1 P1.M2 P1.M3 P1.M4 R46.2
  other v1: 16.125,0.75 17.25,0.75 80.875,1 8.5,1.125 9.75,1.125 11,1.125 12.25,1.125 13.5,1.125 14.75,1.125 18.75,1.125 20,1.125 21.25,1.125 22.5,1.125 23.75,1.125 25,1.125 26.25,1.125 27.5,1.125 28.75,1.125 39.75,1.125 41,1.125 42.25,1.125 43.75,1.125 45,1.125 46.375,1.125 49.25,1.125 50.5,1.125 51.75,1.125 53,1.125 54.25,1.125 55.5,1.125 58.5,1.125 62.5,1.125 63.75,1.125 65,1.125 66.25,1.125 69.375,1.125 70.625,1.125 71.875,1.125 73.125,1.125 74.375,1.125 75.75,1.125 77,1.125 78.25,1.125 79.5,1.125 82.25,1.125 15.375,1.5 18,1.5 82.25,2.25 58.5,2.375 38.375,3 39.75,3 28.75,3.125 30.125,3.125 58.5,3.625 60.375,3.625 61.875,3.625 38.375,4.25 30.125,4.375 38.375,5.5 30.125,5.625
SPI1_CLK: J34.2 U1.AD20 | length 23.3
  Top Layer w0.125: U1.AD20@85.5,16.5 95.3,16.5 v1(95.35,16.45)
  Layer 3 w0.125: v1(95.35,16.45) 95.39,16.49 95.39,20.74 96.14,21.49 96.14,26.99 97.8,28.65 J34.2@98,28.65
SPI1_IRQ_N: J34.7 R122.2 U1.AB13 | length 36.5
  Top Layer w0.125: v1(70.35,21.85) 70.35,21.65 U1.AB13@71.5,20.5
  Layer 10 w0.125: v1(70.35,21.85) 71.9,21.85 73.8,19.95 76.883,19.95 79.983,23.05 81.4,23.05 83.2,21.25 94.2,21.25 95.35,22.4 J34.7@98,22.4
  Bottom Layer w0.125: R122.2@94.8,23.75 95.85,23.75 97.2,22.4 J34.7@98,22.4
SPI1_MISO: J34.3 U1.V17 | length 21.7
  Top Layer w0.125: v1(79.45,27.75) 79.5,27.8 U1.V17@79.5,28.5
  Layer 10 w0.125: v1(79.45,27.75) 81.7,30 94.9,30 v1(96.45,28.45)
  Bottom Layer w0.125: v1(96.45,28.45) 96.45,27.75 96.8,27.4 J34.3@98,27.4
SPI1_MOSI: J34.4 U1.AB18 | length 22.2
  Top Layer w0.125: v1(81.45,19.8) 81.5,19.85 U1.AB18@81.5,20.5
  Layer 10 w0.125: v1(81.45,19.8) 81.85,20.2 95.9,20.2 v1(96.35,20.65)
  Layer 3 w0.125: v1(96.35,20.65) 96.39,20.69 96.39,24.64 97.9,26.15 J34.4@98,26.15
SPI1_SS0: J34.5 U1.Y24 | length 4.9
  Top Layer w0.2: U1.Y24@93.5,24.5 94.2,25.2 96.25,25.2 96.55,24.9 J34.5@98,24.9
SPI1_SS1: J34.6 U1.K2 | length 95.5
  Top Layer w0.125: U1.K2@49.5,44.5 49.5,44.3 v1(50.15,43.65)
  Layer 5 w0.125: v1(46.475,33.075) 47.387,32.163 47.387,31.179 47.913,30.654 47.913,21.587 48.8,20.7 48.8,20 48.35,19.55 v1(48.35,14.05)
  Layer 10 w0.125: v1(48.35,14.05) 48.337,14.037 48.337,12.463 48.95,11.85 59.4,11.85 60.75,13.2 67.854,13.2 68.316,13.663 77.413,13.663 79.363,15.613 92.421,15.613 92.896,15.137 96.087,15.137 v1(96.65,15.7)
  Layer 3 w0.125: v1(46.475,33.075) 47.425,33.075 49.5,35.15 49.5,37.254 51.225,38.979 51.225,41.042 50.15,42.117 v1(50.15,43.65) ; v1(96.65,15.7) 96.763,15.813 96.763,22.413 J34.6@98,23.65
TOUCH_X1: R257.1 U1.T23 | length 111.2
  Top Layer w0.125: R257.1@5.58,12.25 v1(6.25,12.25) ; U1.T23@91.5,32.5 v1(92.25,33.25)
  Layer 8 w0.125: v1(6.25,12.25) 6.25,12.817 6.663,13.229 6.663,13.571 5.987,14.246 5.987,14.771 6.229,15.013 6.884,15.013 7.496,14.4 9.046,14.4 10.271,15.625 22.125,15.625 24.75,18.25 29.729,18.25 30.929,17.05 34.658,17.05 35.208,16.5 37.375,16.5 38.025,17.15 43.1,17.15 49.125,11.125 59.323,11.125 62.56,14.363 72.437,14.363 73.675,15.6 84.161,15.6 91.75,23.189 91.75,32.75 v1(92.25,33.25)
TOUCH_X2: R258.1 U1.R23 | length 110.4
  Top Layer w0.125: R258.1@5.58,13.4 v1(6.25,13.4) ; v1(91.5,33.5) U1.R23@91.5,34.5
  Layer 8 w0.125: v1(6.25,13.4) 5.737,13.913 5.737,14.874 6.126,15.263 6.987,15.263 7.6,14.65 8.943,14.65 10.168,15.875 11.279,15.875 22,15.875 24.725,18.6 27.329,18.6 28.029,19.3 29.075,19.3 31.075,17.3 34.762,17.3 35.312,16.75 37.25,16.75 37.9,17.4 43.225,17.4 49.25,11.375 59.219,11.375 62.457,14.613 72.334,14.613 73.571,15.85 84.057,15.85 91.5,23.293 v1(91.5,33.5)
TOUCH_Y1: R259.1 U1.U24 | length 111.5
  Top Layer w0.125: R259.1@5.58,14.6 v1(6.4,14.6) ; U1.U24@93.5,30.5 v1(93.5,31.375)
  Layer 8 w0.125: v1(6.4,14.6) 6.943,14.6 7.393,14.15 9.15,14.15 10.375,15.375 22.229,15.375 24.854,18 29.625,18 31.675,15.95 37.2,15.95 38.15,16.9 42.975,16.9 49.125,10.75 55.375,10.75 56,10.125 58.75,10.125 62.112,13.487 67.613,13.487 69.2,11.9 77.214,11.9 80.664,15.35 89.039,15.35 93.487,19.798 93.487,31.362 v1(93.5,31.375)
TOUCH_Y2: J30.4 U1.R22 | length 115.8
  Top Layer w0.125: v1(89.5,33.5) U1.R22@89.5,34.5
  Layer 8 w0.125: v1(3.9,15.25) 4.45,15.8 8.9,15.8 9.75,16.65 9.75,17.5 10.09,17.84 16.106,17.84 16.654,18.388 17.912,18.388 18.45,17.85 19.8,17.85 20.8,18.85 27.225,18.85 27.925,19.55 29.2,19.55 31.2,17.55 34.865,17.55 35.415,17 37.125,17 37.775,17.65 43.329,17.65 49.354,11.625 59.115,11.625 62.353,14.863 72.23,14.863 73.468,16.1 83.954,16.1 91.25,23.396 91.25,31.75 v1(89.5,33.5)
  Bottom Layer w0.125: J30.4@2.1,11.15 2.7,11.15 3,11.45 3,14.35 v1(3.9,15.25)
UART1_CTS_N: U1.Y17 U8.12 | length 173.1
  Top Layer w0.125: v1(31.25,51.8) 32.225,52.775 U8.12@32.225,54.005 ; v1(78.625,24.5) U1.Y17@79.5,24.5
  Layer 8 w0.125: v1(7.5,51.625) 7.137,51.262 7.137,33.263 v1(7.7,32.7)
  Layer 5 w0.125: v1(8.4,15.3) 8.7,15.6 21.725,15.6 23.875,17.75 25.632,17.75 26.482,16.9 29.186,16.9 30.986,15.1 36.728,15.1 37.378,15.75 37.753,16.125 43.75,16.125 46.625,13.25 v1(46.625,12.625)
  Layer 10 w0.125: v1(7.5,51.625) 7.75,51.875 31.175,51.875 v1(31.25,51.8)
  Layer 3 w0.125: v1(46.625,12.625) 48.212,11.038 59.913,11.038 61.25,12.375 65.875,12.375 67.5,10.75 67.5,6.75 68.625,5.625 69.875,5.625 71.875,7.625 71.875,9.325 74.3,11.75 77.1,11.75 81.95,16.6 81.95,20.4 81.475,20.875 81.475,22.525 80.975,23.025 80.975,24.1 80.575,24.5 v1(78.625,24.5)
  Bottom Layer w0.125: v1(7.7,32.7) 10,30.4 10,26.5 9.8,26.3 6.45,26.3 4.05,23.9 4.05,16.9 5.65,15.3 v1(8.4,15.3)
UART1_RTS_N: U1.W19 U8.17 | length 105.1
  Top Layer w0.125: U8.17@32.225,59.805 32.225,60.603 32.472,60.85 32.95,60.85 33.4,61.3 v1(33.4,62.4) ; U1.W19@83.5,26.5 v1(83.5,27.5)
  Layer 3 w0.125: v1(33.4,62.4) 33.237,62.563 33.237,66.912 37.837,71.512 73.613,71.512 78.375,66.75 82.2,66.75 87.15,61.8 87.15,49.75 85.387,47.987 85.387,29.496 85.563,29.321 85.563,28.979 85.321,28.737 84.737,28.737 v1(83.5,27.5)
UART1_RX: U1.E21 U8.18 | length 76.2
  Top Layer w0.125: v1(31.35,61.05) 31.35,60.7 31.575,60.475 U8.18@31.575,59.805 ; v1(86.625,55.125) U1.E21@87.5,54.5
  Layer 8 w0.125: v1(31.35,61.05) 31.417,61.05 30.95,61.517 30.95,65.925 35.338,70.313 73.924,70.313 80.213,64.024 85.104,64.024 87.225,61.904 87.225,55.725 v1(86.625,55.125)
UART1_TX: U1.C21 U8.13 | length 76.3
  Top Layer w0.125: U8.13@32.875,54.005 32.875,56.255 v1(33.6,56.98) ; v1(86.5,57.625) U1.C21@87.5,58.5
  Layer 8 w0.125: v1(33.6,56.98) 33.6,59.75 34.426,60.576 34.426,66.489 38,70.063 73.821,70.063 80.109,63.774 85.001,63.774 86.975,61.8 86.975,58.1 v1(86.5,57.625)
UART3_CTS_N: U1.Y15 U9.13 | length 74.2
  Top Layer w0.125: v1(43.075,54.75) U9.13@43.075,55.85 ; v1(74.75,25.25) U1.Y15@75.5,24.5
  Layer 5 w0.125: v1(43.075,54.75) 43.65,55.325 46.725,55.325 49.087,52.963 49.087,52.954 52.167,49.875 53.288,49.875 55.2,47.963 55.2,27.396 60,22.596 60,19.043 59.4,18.443 59.4,16.788 61.251,14.937 62.341,14.937 62.466,15.063 62.938,15.063 66.875,19 69.25,19 71.613,21.363 71.613,23.283 71.5,23.396 71.5,25.125 72.125,25.75 74.25,25.75 v1(74.75,25.25)
UART3_RTS_N: U1.AA15 U9.18 | length 86.5
  Top Layer w0.125: v1(41.775,60.525) U9.18@41.775,61.65 ; v1(74.75,21.75) U1.AA15@75.5,22.5
  Layer 8 w0.125: v1(41.775,60.525) 41.775,58.112 42.113,57.774 42.113,57.412 44.25,55.275 44.25,52.8 43.525,52.075 v1(42.075,52.075)
  Layer 5 w0.125: v1(42.075,52.075) 42.65,51.5 46.708,51.5 49.746,48.462 52.421,48.462 52.496,48.538 53.524,48.538 54.45,47.612 54.45,25.704 57.625,22.529 57.625,19.636 58.65,18.611 58.65,16.477 60.94,14.187 62.704,14.187 62.829,14.313 65.646,14.313 68.75,17.417 68.75,17.875 69.125,18.25 69.625,18.25 73.125,21.75 73.125,22.975 72.95,23.15 72.95,23.7 73.25,24 75,24 75.625,23.375 75.625,22.625 v1(74.75,21.75)
UART3_RX: U1.AA17 U9.19 | length 86.4
  Top Layer w0.125: v1(41.125,60.525) U9.19@41.125,61.65 ; v1(78.875,23.125) U1.AA17@79.5,22.5
  Layer 8 w0.125: v1(41.125,60.525) 41.125,58.408 41.863,57.671 41.863,53.762 v1(43.025,52.6)
  Layer 5 w0.125: v1(43.025,52.6) 43.6,52.025 49.125,52.025 51.775,49.375 53.081,49.375 54.7,47.756 54.7,27.175 59.5,22.375 59.5,19.25 58.9,18.65 58.9,16.581 61.043,14.437 62.548,14.437 62.673,14.563 65.213,14.563 67.5,16.85 67.5,17.5 68.5,18.5 69.5,18.5 72.875,21.875 72.875,22.8 72,23.675 72,24.25 72.25,24.5 75.625,24.5 76.5,23.625 78.375,23.625 v1(78.875,23.125)
UART3_TX: U1.W20 U9.14 | length 85.5
  Top Layer w0.125: v1(43.725,53.125) U9.14@43.725,56 ; v1(84.5,27.5) U1.W20@85.5,26.5
  Layer 5 w0.125: v1(43.725,53.125) 44.475,52.375 49.129,52.375 51.879,49.625 53.185,49.625 54.95,47.86 54.95,27.293 59.75,22.493 59.75,19.146 59.15,18.546 59.15,16.685 61.147,14.687 62.445,14.687 62.57,14.813 63.063,14.813 67,18.75 69.375,18.75 71.863,21.238 71.863,23.387 71.75,23.499 71.75,24.875 72.375,25.5 73.25,25.5 74,24.75 75.375,24.75 76.525,25.9 80.85,25.9 81.95,27 84,27 v1(84.5,27.5)
UART4_RX: U1.E2 U8.19 | length 23.5
  Top Layer w0.125: v1(30.925,57.842) U8.19@30.925,59.805 ; U1.E2@49.5,54.5 v1(50.325,54.75)
  Bottom Layer w0.125: v1(30.925,57.842) 31.042,57.725 38.175,57.725 40.7,55.2 49.875,55.2 v1(50.325,54.75)
UART4_TX: U1.J2 U8.14 | length 22.4
  Top Layer w0.125: v1(33.512,52.85) 33.525,52.863 U8.14@33.525,54.005 U8.14@33.512,53.992 ; v1(46.25,45.125) 47.2,45.125 48.575,46.5 U1.J2@49.5,46.5
  Layer 5 w0.125: v1(43.75,49.75) 43.75,48.25 46.25,45.75 v1(46.25,45.125)
  Layer 10 w0.125: v1(33.512,52.85) 34.237,52.125 39.076,52.125 41.049,50.152 41.751,50.152 42,50.401 43.099,50.401 v1(43.75,49.75)
UART5_CTS_N: J24.5 J29.14 R145.2 U1.D2 | length 88.3
  Top Layer w0.125: U1.D2@49.5,56.5 50.05,56.5 v1(50.35,56.2)
  Top Layer w0.25: v1(39.6,45.75) 39.975,45.375 J24.5@39.975,45
  Layer 8 w0.125: J29.14@2.2,64.75 5.05,61.9 5.05,54.55 v1(4.8,54.3) ; v1(39.6,45.75) 39.85,46 42.1,46 45,48.9 45,50.496 46.354,51.85 50.683,51.85 51.038,52.204 51.038,55.512 v1(50.35,56.2)
  Layer 5 w0.125: v1(20.7,56.35) 21.663,57.313 24.934,57.313 25.146,57.1 29.246,57.1 35.696,63.55 42.296,63.55 49.646,56.2 v1(50.35,56.2)
  Layer 10 w0.125: v1(4.8,54.3) 4.8,53.6 5.3,53.1 9.629,53.1 13.041,56.513 20.537,56.513 v1(20.7,56.35)
  Bottom Layer w0.25: R145.2@39,44.78 39,45.15 v1(39.6,45.75)
UART5_RTS_N: J24.9 J29.13 U1.L2 | length 104.9
  Top Layer w0.125: U1.L2@49.5,42.5 49.65,42.5 50.4,43.25 v1(50.85,43.25)
  Top Layer w0.2: J24.9@40,37 40,38.4 v1(40.35,38.75)
  Layer 8 w0.125: J29.13@2.2,63.5 1.25,62.55 1.25,47.5 2,46.75 2,33.3 2.85,32.45 v1(3.65,32.45)
  Layer 5 w0.125: v1(3.65,32.45) 3.687,32.413 6.55,32.413 7,32.863 7,36.35 8.75,38.1 12.7,38.1 18.45,43.85 20.2,43.85 21.537,42.513 37.437,42.513 37.85,42.1 v1(40.15,42.1) 42.75,42.1 46.487,38.363 50.866,38.363 51.9,39.396 51.9,42.662 52.538,43.3 52.538,43.921 52.296,44.163 51.313,44.163 50.85,43.7 v1(50.85,43.25)
  Layer 3 w0.125: v1(40.15,42.1) 40.35,41.9 v1(40.35,38.75)
UART5_RX: J23.2 J29.12 U1.D3 | length 71.9
  Top Layer w0.125: v1(50.35,56.85) 51.15,56.85 U1.D3@51.5,56.5
  Top Layer w0.15: v1(20.6,55.6) 20.825,55.375 J23.2@20.825,51
  Layer 8 w0.15: J29.12@2.2,62.25 2.704,62.25 4.5,60.454 v1(4.5,54.95)
  Layer 5 w0.125: v1(20.6,55.6) 20.287,55.913 20.287,56.521 21.329,57.563 25.037,57.563 25.25,57.35 29.142,57.35 35.592,63.8 42.4,63.8 49.35,56.85 v1(50.35,56.85)
  Layer 10 w0.15: v1(4.5,54.95) 4.45,54.9 4.45,54.676 4.375,54.601 4.375,52.775 5,52.15 9.05,52.15 12.5,55.6 v1(20.6,55.6)
UART5_TX: J23.3 J29.11 U1.E3 | length 74.6
  Top Layer w0.125: U1.E3@51.5,54.5 52.05,54.5 v1(52.2,54.65)
  Top Layer w0.2: J23.3@17.975,49 17.975,49.925 18.1,50.05 v1(18.6,50.05)
  Layer 8 w0.125: J29.11@2.2,61 3.25,59.95 3.25,55.15 6.3,52.1 v1(6.3,49.45)
  Layer 5 w0.125: v1(18.6,50.05) 18.552,50.098 18.552,54.335 19.367,55.15 23.45,55.15 25.15,56.85 29.349,56.85 30.85,58.35 33.295,60.796 35.799,63.3 42.193,63.3 49.843,55.65 51.2,55.65 v1(52.2,54.65)
  Layer 10 w0.125: v1(6.3,49.45) 8.35,51.5 17.15,51.5 v1(18.6,50.05)
UART_PWR_EN: R127.2 U1.W15 U8.22 U9.22 | length 95.4
  Top Layer w0.125: 28.975,60.7 29.575,61.3 v1(30.15,61.3) ; v1(39.175,62.75) 39.48,63.055 R127.2@39.48,63.6 ; v1(74.8,26.9) 75.1,26.9 U1.W15@75.5,26.5
  Top Layer w0.25: U8.22@28.975,59.805 28.975,60.7 ; U9.22@39.175,61.65 v1(39.175,62.75)
  Layer 5 w0.125: v1(39.175,62.75) 42.25,62.75 49.667,55.333 49.667,53.917 54.637,48.946 54.637,48.879 55.45,48.067 55.45,38.742 57.625,36.567 57.625,25.325 60.25,22.7 60.25,18.939 59.65,18.339 59.65,16.892 61.354,15.187 62.237,15.187 62.363,15.313 62.813,15.313 66.75,19.25 69.146,19.25 71.363,21.466 71.363,23.179 71.25,23.292 71.25,25.229 72.021,26 73.65,26 74.55,26.9 v1(74.8,26.9)
  Layer 10 w0.125: v1(30.15,61.3) 31.103,60.347 34.197,60.347 35.65,61.8 38.225,61.8 v1(39.175,62.75)
USB_HUB_RESET_N: R69.2 U1.V21 U13.26 | length 90.1
  Top Layer w0.125: v1(86.875,29.125) U1.V21@87.5,28.5
  Layer 8 w0.125: v1(46.75,17.375) 46.75,17.36 50.56,13.55 50.8,13.55 51.143,13.55 57.565,13.55 58.437,14.422 58.437,14.428 58.972,14.963 58.978,14.963 60.228,16.212 60.671,16.212 61.383,16.925 64.4,16.925 65.675,18.2 72.8,18.2 74,19.4 v1(74.35,19.4)
  Layer 5 w0.125: v1(23.55,35.3) 24.75,35.3 26.212,33.838 26.212,33.829 30.906,29.135 37.864,29.135 39.775,27.225 39.775,25.5 41.05,24.225 41.05,20.2 42.6,18.65 45.475,18.65 v1(46.75,17.375) ; v1(74.35,19.4) 75.075,20.125 76.625,20.125 78.55,22.05 79.325,22.05 83.275,26 84.85,26 86.138,27.288 86.138,28.387 v1(86.875,29.125)
  Bottom Layer w0.125: v1(23.55,35.3) 23.623,35.227 25.352,35.227 25.855,35.73 R69.2@25.855,35.75 26.48,35.125 26.875,35.125 27.75,34.25 U13.26@29.075,34.25
USB_OTG_D_N: L10.1 U1.G16 | length 85.7
  Top Layer w0.137: v1(34.75,14.5) 34.75,14.923 34.775,14.948 L10.1@34.775,15.525 ; U1.G16@77.5,50.5 77.6,50.5 v1(78.25,49.85)
  Layer 3 w0.103: v1(34.75,14.5) 34.49,14.759 34.49,14.95 34.79,15.25 35.827,15.25 36.963,16.387 48.437,16.387 53.081,11.742 59.819,11.742 59.846,11.769 63.648,15.572 63.648,18.802 63.25,19.2 63.25,48.75 65,50.5 78.134,50.5 78.434,50.2 78.434,50.034 v1(78.25,49.85)
USB_OTG_D_P: L10.4 U1.G17 | length 86.3
  Top Layer w0.137: L10.4@33.975,15.525 33.975,14.948 34,14.923 v1(34,14.5) ; v1(78.85,49.85) U1.G17@79.5,50.5
  Layer 3 w0.103: v1(34,14.5) 34.259,14.759 34.259,15.046 34.695,15.481 35.731,15.481 36.868,16.618 48.532,16.618 48.6,16.55 53.177,11.973 59.723,11.973 63.417,15.667 63.417,18.706 63.019,19.104 63.019,48.846 64.904,50.731 78.23,50.731 78.665,50.296 78.665,50.034 v1(78.85,49.85)
USB_OTG_ID: J16.4 U1.K3 U20.1 | length 87.4
  Top Layer w0.125: U1.K3@51.5,44.5 v1(52.125,43.75)
  Layer 8 w0.125: v1(22.3,34.05) 21.587,34.763 21.587,37.78 23.263,39.455 23.263,44.487 v1(22.9,44.85)
  Layer 5 w0.125: v1(22.3,34.05) 22.85,33.5 22.85,26.896 24.746,25 27.446,25 28.113,24.334 28.113,23.563 v1(28.1,23.55) ; v1(22.9,44.85) 24.987,42.763 39.046,42.763 40.131,43.848 42.152,43.848 44.262,41.738 44.296,41.738 47.408,38.625 50.775,38.625 51.65,39.5 51.65,43.275 v1(52.125,43.75)
  Bottom Layer w0.125: U20.1@28.675,24.275 28.475,24.275 28.113,23.913 28.113,23.563 v1(28.1,23.55) 27.875,23.325 27.875,21.25 28.625,20.5 28.625,19.625 31.875,16.375 31.875,8.75 33.65,6.975 J16.4@33.65,4.15
USB_OTG_OC: R64.1 U1.Y16 U12.2 | length 42.6
  Top Layer w0.125: R64.1@42.605,29.25 42.605,29.505 43.05,29.95 v1(43.2,29.95) ; v1(76.8,24.5) U1.Y16@77.5,24.5
  Layer 10 w0.125: v1(43.2,29.95) 44.467,29.95 49.279,25.137 52.987,25.137 53.763,25.913 56.546,25.913 59.746,22.712 61.879,22.712 64.179,25.013 64.521,25.013 64.571,24.962 65.896,24.962 66.333,25.4 66.8,25.4 67.6,26.2 74.75,26.2 76.45,24.5 v1(76.8,24.5)
  Bottom Layer w0.125: U12.2@42.615,28.825 42.615,29.515 43.05,29.95 v1(43.2,29.95)
USB_OTG_PWR: U1.Y18 U12.1 | length 47.2
  Top Layer w0.125: v1(80.55,25.15) 80.85,25.15 U1.Y18@81.5,24.5
  Layer 10 w0.125: v1(43.75,27.7) 43.95,27.7 44.4,28.15 45.913,28.15 49.176,24.887 55.054,24.887 55.829,25.663 56.442,25.663 59.642,22.462 62.366,22.462 64.091,24.187 65.941,24.187 67.704,25.95 73.467,25.95 75.617,23.8 78.65,23.8 80,25.15 v1(80.55,25.15)
  Bottom Layer w0.125: U12.1@41.345,28.825 41.345,28.355 42,27.7 v1(43.75,27.7)
USB_OTG_VBUS: U1.G14 U15.D | length 62.2
  Top Layer w0.125: v1(39.975,20.65) 41.975,20.65 43.225,21.9 45.35,21.9 45.6,21.65 51.1,21.65 51.35,21.4 53.35,21.4 54.1,22.15 54.725,22.15 55.1,21.775 56.35,21.775 56.6,22.025 56.6,26.9 57.1,27.4 57.475,27.4 58.35,28.275 58.35,30.15 61.05,32.85 v1(64.4,32.85) ; v1(70.8,51.5) 71.467,51.5 72.467,50.5 U1.G14@73.5,50.5
  Layer 5 w0.125: v1(64.4,32.85) 64.3,32.95 64.3,49.754 65.046,50.5 69.8,50.5 v1(70.8,51.5)
  Bottom Layer w0.125: U15.D@39.25,20.65 v1(39.975,20.65)
USBH1_D_N: J15.A2 L8.2 U21.1 | length 36
  Top Layer w0.137: v1@40.757,27.125 v1(40.875,27.125) U21.1@41.775,27.125
  Layer 10 w0.103: J15.A2@33,13 34.098,14.098 36.398,14.098 39.119,16.819 39.119,23.819 40.069,24.769 40.069,26.53 40.404,26.865 40.615,26.865 v1(40.875,27.125) 41.135,26.865 41.3,26.865 41.45,27.015 41.45,27.45 41.1,27.8 39.273,27.8 37.619,29.454 37.619,34.396 38.989,35.765 39.816,35.765 v1@40.05,36
  Bottom Layer w0.137: L8.2@37.975,36.025 38.225,36.025 38.46,35.79 39.84,35.79 v1@40.05,36
  other v1: 40.05,35.95
USBH1_D_P: J15.A3 L8.3 U21.2 | length 36
  Top Layer w0.137: v1(40.875,26.375) U21.2@41.725,26.375
  Layer 10 w0.103: J15.A3@35,13 34.1,13 33.95,13.15 33.95,13.6 34.217,13.867 36.494,13.867 36.627,14 39.35,16.723 39.35,23.723 40.3,24.673 40.3,26.434 40.5,26.634 40.616,26.634 v1(40.875,26.375) 41.134,26.634 41.396,26.634 41.681,26.92 41.681,27.546 41.196,28.031 39.369,28.031 37.85,29.55 37.85,34.3 39.084,35.534 39.766,35.534 v1@40,35.3
  Bottom Layer w0.137: L8.3@37.975,35.225 38.225,35.225 38.51,35.51 39.79,35.51 v1@40,35.3
  other v1: 40.05,35.25
USBH1_OC_N: R65.1 U13.13 U14.2 | length 21.3
  Top Layer w0.125: R65.1@27.28,26.45 v1(27.95,26.45)
  Layer 3 w0.125: v1(24.5,28.35) 24.5,26.99 25.04,26.45 v1(27.95,26.45)
  Bottom Layer w0.125: v1(24.5,28.35) 24.49,28.34 U14.2@24.49,27.2 24.49,26.3 25.54,25.25 32.5,25.25 32.875,25.625 32.875,26.25 32.375,26.75 U13.13@32.375,29.95
USBH1_PWR_EN: U13.12 U14.1 | length 17.2
  Bottom Layer w0.125: U14.1@23.22,27.2 23.22,26.155 24.375,25 33.375,25 33.875,25.5 33.875,27.125 32.875,28.125 U13.12@32.875,29.95
USBH2_D_N: J15.B2 L11.2 U21.5 | length 43.4
  Top Layer w0.137: U21.5@44.775,26.125 v1(45.75,26.125)
  Layer 10 w0.103: v1(41,34.05) 41.197,33.853 41.624,33.853 42.681,32.796 42.681,28.465 43.3,27.846 43.3,27.5 44.935,25.865 45.49,25.865 v1(45.75,26.125)
  Layer 3 w0.103: J15.B2@33,10.38 33.884,11.264 33.884,11.35 33.734,11.5 32.323,11.5 31.669,12.154 31.669,15.946 33.454,17.731 39.681,17.731 41.419,19.469 41.419,23.146 44.139,25.865 45.49,25.865 v1(45.75,26.125)
  Bottom Layer w0.137: L11.2@37.975,34.275 38.275,34.275 38.535,34.015 38.916,34.015 39.053,33.878 40.828,33.878 v1(41,34.05)
USBH2_D_P: J15.B3 L11.3 U21.4 | length 43
  Top Layer w0.137: U21.4@44.725,25.375 v1(45.75,25.375)
  Layer 10 w0.103: v1(41,33.425) 41.197,33.622 41.528,33.622 42.45,32.7 42.45,28.369 43.069,27.75 43.069,27.404 44.839,25.634 45.491,25.634 v1(45.75,25.375)
  Layer 3 w0.103: J15.B3@35,10.38 34.115,11.265 34.115,11.446 33.83,11.731 32.419,11.731 31.9,12.25 31.9,15.85 33.55,17.5 39.777,17.5 41.65,19.373 41.65,23.05 44.234,25.634 45.491,25.634 v1(45.75,25.375)
  Bottom Layer w0.137: L11.3@37.975,33.475 38.275,33.475 38.535,33.735 38.8,33.735 38.938,33.598 40.827,33.598 v1(41,33.425)
USBH2_OC_N: R66.1 U13.17 U14.3 | length 12.4
  Top Layer w0.125: R66.1@27.28,25.275 27.805,25.8 v1(27.9,25.8)
  Layer 3 w0.125: v1(25.75,28.375) 26.825,27.3 27.95,27.3 28.45,26.8 28.45,26.367 28.121,26.037 28.087,26.037 27.9,25.85 v1(27.9,25.8)
  Bottom Layer w0.125: U14.3@25.76,27.2 25.76,28.385 26.125,28.75 30,28.75 30.375,29.125 U13.17@30.375,29.95
USBH2_PWR_EN: U13.16 U14.4 | length 6
  Bottom Layer w0.125: U14.4@27.03,27.2 27.03,28.155 27.375,28.5 30.25,28.5 30.875,29.125 U13.16@30.875,29.95
USBH3_D_N: J12.36 L14.2 | length 18.3
  Bottom Layer w0.137: L14.2@39.225,31.525 39.575,31.525 39.825,31.275 44.771,31.275 46.255,29.791 46.43,29.616 46.43,27.747 46.597,27.58 52.155,27.58 52.93,28.355 53.38,28.355 53.625,28.6 J12.36@54.4,28.6
USBH3_D_P: J12.38 L14.3 | length 18.4
  Bottom Layer w0.137: L14.3@39.225,30.725 39.575,30.725 39.845,30.995 44.655,30.995 46.15,29.5 46.15,27.625 46.475,27.3 52.275,27.3 53.05,28.075 53.35,28.075 53.625,27.8 J12.38@54.4,27.8
USBH4_D_N: J32.3 L16.2 R129.1 | length 47.2
  Top Layer w0.137: v1(18.1,30.45) 18.1,30.8 18.32,31.02 R129.1@18.45,31.02
  Layer 3 w0.103: J32.3@5.7,19.4 6.209,18.89 6.4,18.89 6.85,19.34 6.85,28.127 8.773,30.05 14.373,30.05 14.83,30.507 14.898,30.574 17.589,30.574 17.657,30.507 17.713,30.45 v1(18.1,30.45) 18.345,30.45 18.376,30.481 18.6,30.481 18.615,30.481 ccw(c18.615,30.617) 18.751,30.617 18.751,30.945 cw(c18.888,30.945) 18.888,31.081 18.918,31.081 cw(c18.918,30.945) 19.054,30.945 19.054,30.617 ccw(c19.191,30.617) 19.191,30.481 19.357,30.481 19.4,30.481 29.519,30.481 30.635,29.365 39.065,29.365 v1(39.325,29.625)
  Bottom Layer w0.137: L16.2@38.475,29.65 38.475,29.525 39.225,29.525 v1(39.325,29.625)
USBH4_D_P: J32.2 L16.3 R102.1 | length 47.4
  Top Layer w0.137: R102.1@16.95,31.02 17.6,30.37 17.6,30.02 v1(17.6,29.85)
  Layer 3 w0.103: J32.2@5.7,18.15 6.209,18.659 6.496,18.659 7.081,19.245 7.081,28.031 8.869,29.819 14.469,29.819 14.993,30.343 17.493,30.343 17.6,30.237 v1(17.6,29.85) 17.795,30.045 18.268,30.045 18.472,30.25 29.423,30.25 30.539,29.134 39.065,29.134 v1(39.325,28.875)
  Bottom Layer w0.137: L16.3@38.475,28.85 38.475,28.975 39.225,28.975 v1(39.325,28.875)
USBH4_OC_N: J32.4 U13.21 | length 31.3
  Bottom Layer w0.125: J32.4@5.7,20.65 5.4,20.65 4.85,21.2 4.85,23.9 6.85,25.9 14.15,25.9 16.9,28.65 18.6,28.65 19.387,29.437 26.062,29.437 28.375,31.75 U13.21@29.075,31.75
USBH4_PWR_EN: J32.5 U13.20 | length 28.7
  Bottom Layer w0.125: J32.5@5.7,21.9 6.1,21.9 6.7,22.5 6.7,24.95 7.35,25.6 14.204,25.6 17.004,28.4 18.704,28.4 19.454,29.15 26.15,29.15 28.25,31.25 U13.20@29.075,31.25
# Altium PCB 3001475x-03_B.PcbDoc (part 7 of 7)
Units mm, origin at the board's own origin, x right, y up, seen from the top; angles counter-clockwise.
Board outline 100 x 72 mm, 12 copper layers (Top Layer, L2 GND, Layer 3, L4 GND, Layer 5, L6 PWR, L7 3V3, Layer 8, L9 GND, Layer 10, L11 GND, Bottom Layer), stack 1.735 mm thick; 431 components, 499 nets, 1977 pads, 1473 vias.

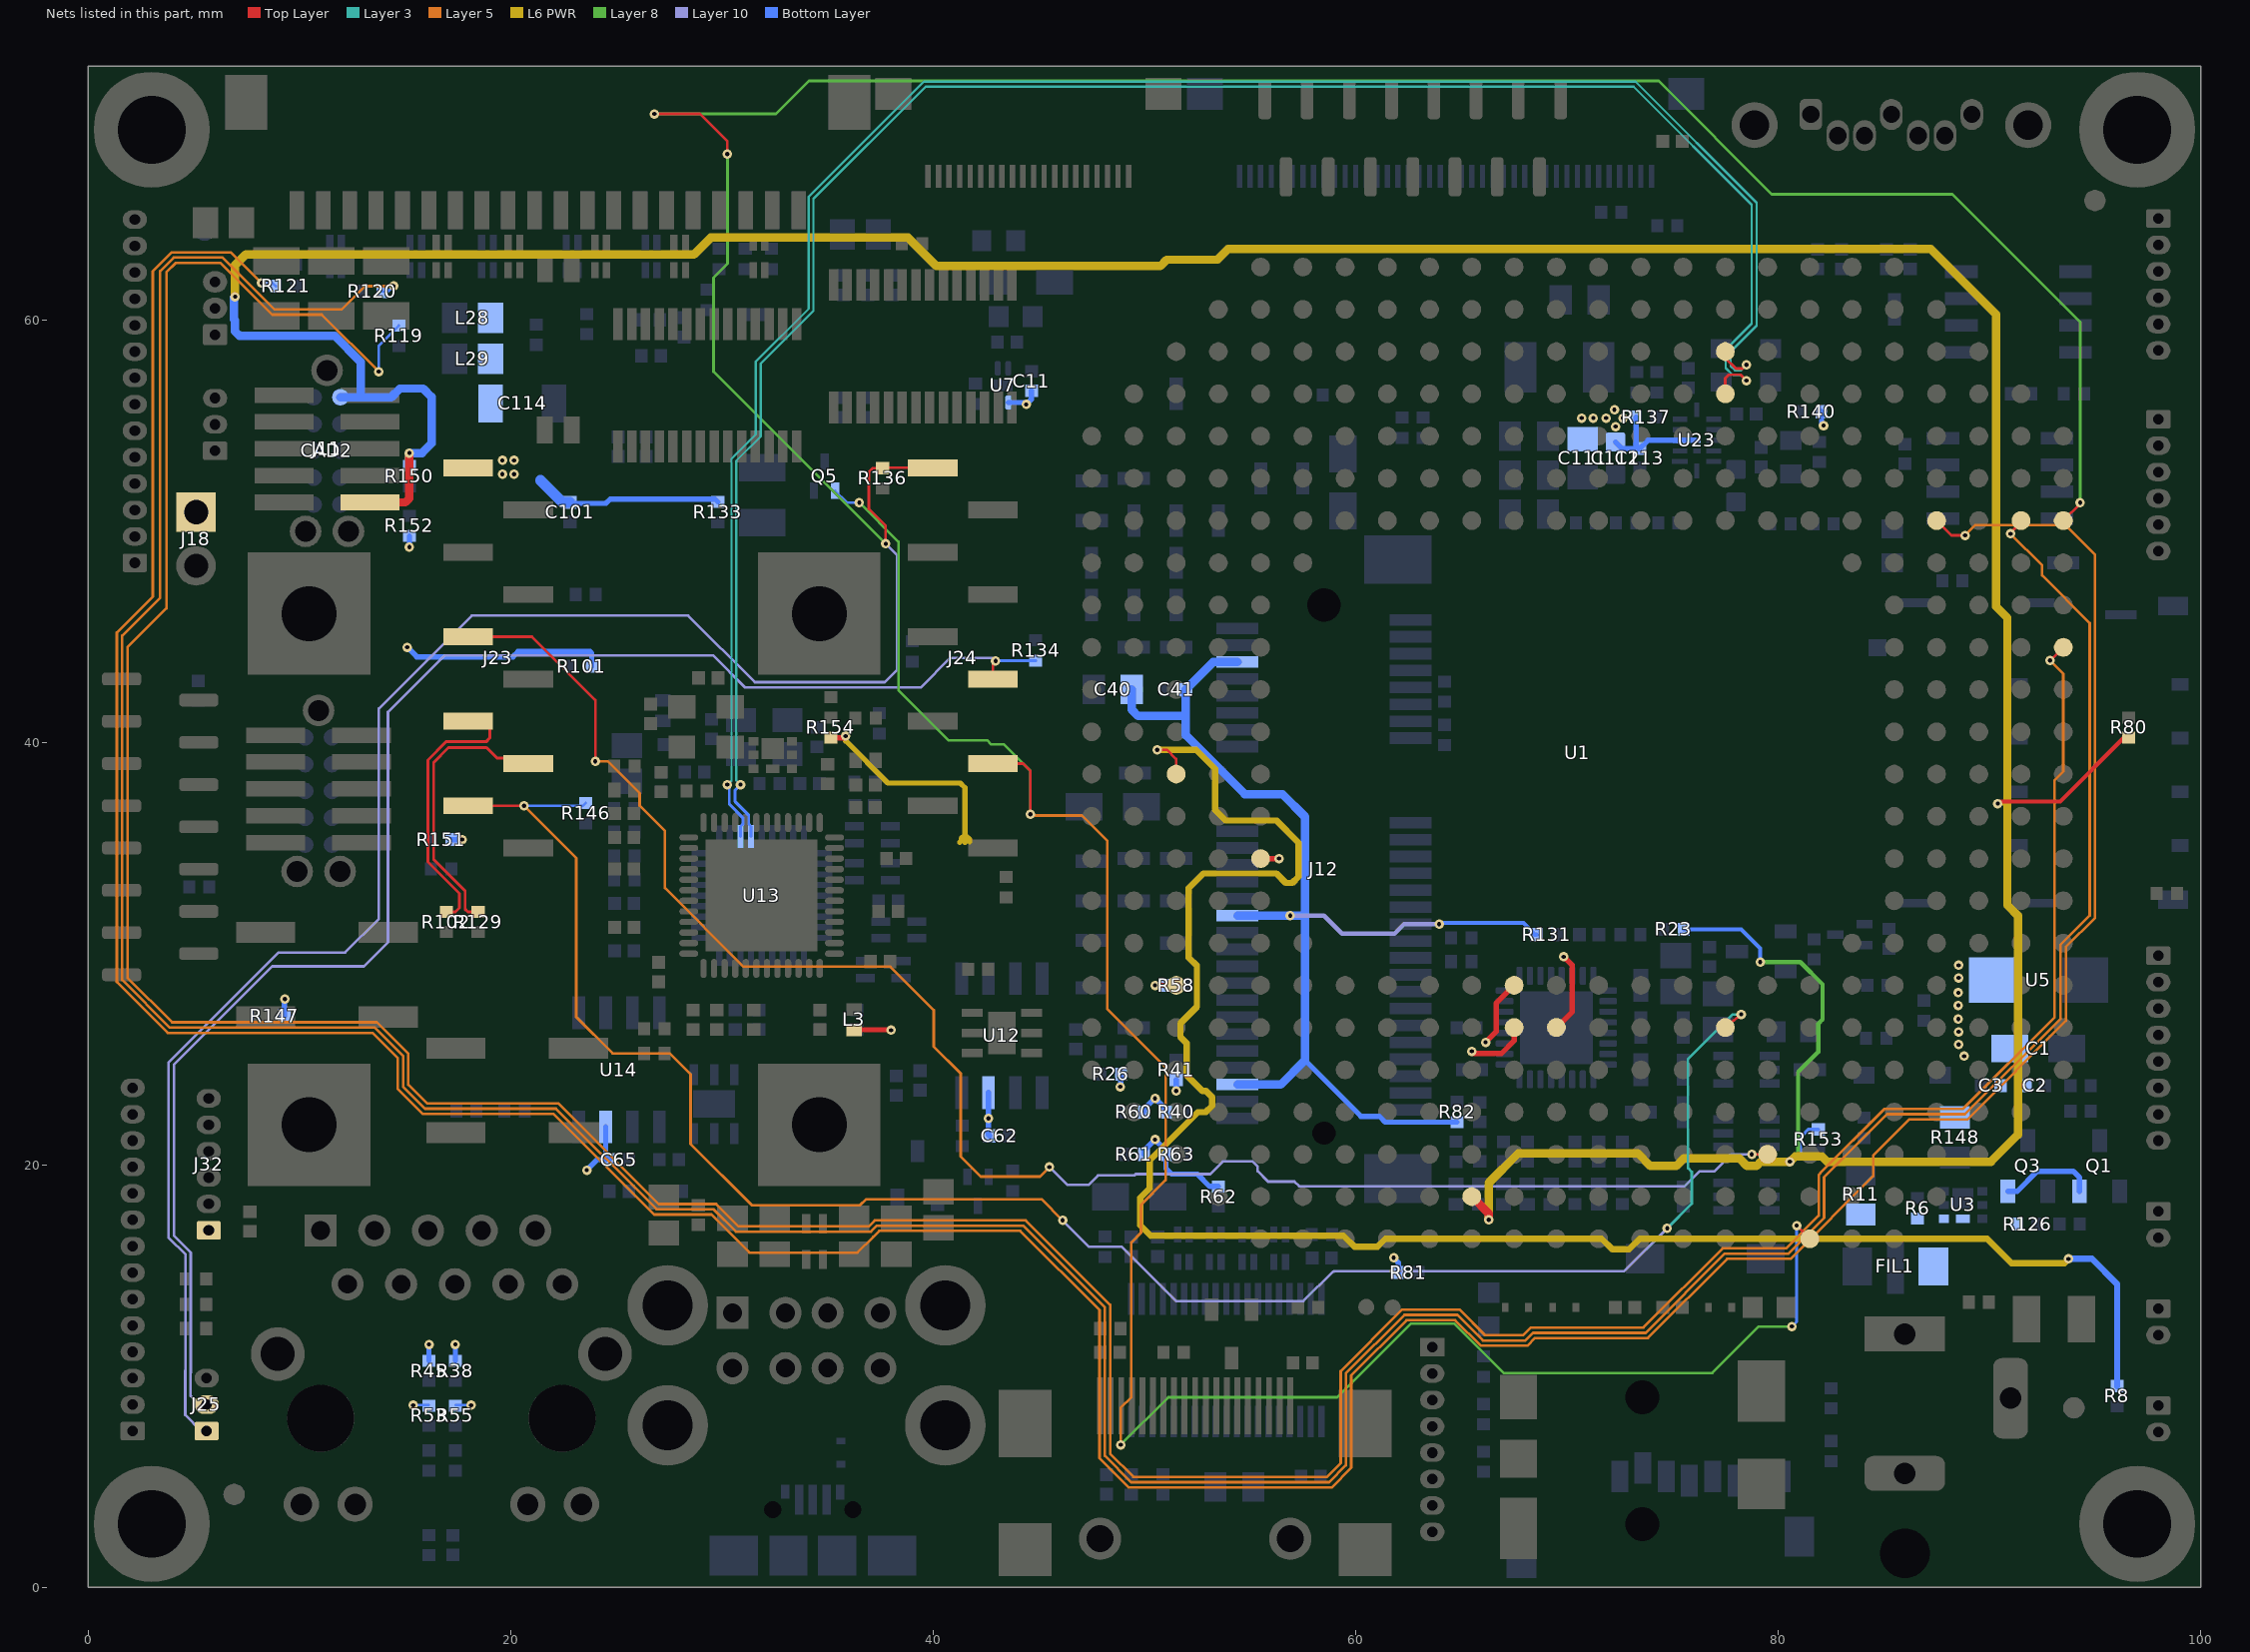
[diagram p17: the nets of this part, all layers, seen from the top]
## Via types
v1: diameter 0.45, hole 0.2, Top Layer to Bottom Layer, tented both sides, 1473 vias

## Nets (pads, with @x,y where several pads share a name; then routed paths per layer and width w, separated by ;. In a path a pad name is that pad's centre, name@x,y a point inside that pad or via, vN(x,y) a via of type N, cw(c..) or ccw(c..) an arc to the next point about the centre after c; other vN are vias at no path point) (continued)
USBH_D_N: U1.C16 U13.30 | length 92.5
  Top Layer w0.137: U1.C16@77.5,58.5 77.5,58.2 78,57.7 78.325,57.7 v1(78.5,57.875)
  Layer 3 w0.103: v1(30.25,38) 30.447,38.197 30.447,53.424 31.6,54.577 31.6,58.027 34.1,60.527 34.1,65.827 39.547,71.273 73.253,71.273 78.981,65.546 78.981,59.731 77.75,58.5 77.75,57.815 77.95,57.615 78.24,57.615 v1(78.5,57.875)
  Bottom Layer w0.137: v1(30.25,38) 30.342,37.908 30.342,37.077 30.985,36.434 30.985,36.135 30.875,36.025 U13.30@30.875,35.55
USBH_D_P: U1.D16 U13.31 | length 92.5
  Top Layer w0.137: U1.D16@77.5,56.5 77.5,57.238 77.663,57.4 78.225,57.4 v1(78.5,57.125)
  Layer 3 w0.103: v1(30.875,38) 30.678,38.197 30.678,53.328 31.831,54.481 31.831,57.931 34.331,60.431 34.331,65.731 39.642,71.042 73.158,71.042 78.75,65.45 78.75,59.827 77.519,58.596 77.519,57.72 77.854,57.384 78.241,57.384 v1(78.5,57.125)
  Bottom Layer w0.137: v1(30.875,38) 30.622,37.747 30.622,37.193 31.265,36.55 31.265,36.135 31.375,36.025 U13.31@31.375,35.55
USER_LED0: R121.2 U1.G21 | length 193.7
  Top Layer w0.125: U1.G21@87.5,50.5 88.2,49.8 v1(88.85,49.8)
  Layer 5 w0.125: v1(8.2,61.75) 6.75,63.2 3.943,63.2 3.05,62.307 3.05,46.9 1.35,45.2 1.35,28.657 3.757,26.25 13.457,26.25 14.65,25.057 14.65,23.593 15.83,22.413 22.03,22.413 26.793,17.65 29.496,17.65 31.296,15.85 36.418,15.85 37.155,16.587 37.443,16.875 44.125,16.875 47.875,13.125 47.875,6.354 47.875,6.118 49.263,4.73 58.855,4.73 59.788,5.663 59.788,10.027 62.411,12.65 64.714,12.65 65.927,11.437 68.134,11.437 68.496,11.8 73.832,11.8 77.582,15.55 80.59,15.55 84.5,19.46 84.5,20.45 86.2,22.15 88.95,22.15 93.625,26.825 93.625,30.325 95,31.7 95,48.875 93.587,50.288 89.338,50.288 v1(88.85,49.8)
  Bottom Layer w0.125: v1(8.2,61.75) 8.72,61.75 R121.2@8.87,61.6
USER_LED1: R120.2 U1.G23 | length 194.2
  Top Layer w0.125: v1(91,49.875) U1.G23@91.5,50.5
  Layer 5 w0.125: v1(14.45,61.6) 13.1,61.6 12,60.5 8.804,60.5 6.354,62.95 4.046,62.95 3.4,62.304 3.4,46.85 1.6,45.05 1.6,28.761 3.861,26.5 13.561,26.5 14.9,25.161 14.9,23.696 15.934,22.663 22.134,22.663 26.896,17.9 29.6,17.9 29.625,17.875 30.663,16.837 37.052,16.837 37.339,17.125 44.25,17.125 48.125,13.25 48.125,6.221 49.366,4.98 58.745,4.98 59.538,5.772 59.538,10.13 62.307,12.9 64.818,12.9 66.03,11.687 68.03,11.687 68.393,12.05 73.729,12.05 77.479,15.8 80.487,15.8 82.175,17.488 82.175,19.425 85.15,22.4 88.846,22.4 93.375,26.929 93.375,30.429 94.75,31.804 94.75,45.65 92.5,47.9 92.5,48.375 v1(91,49.875)
  Bottom Layer w0.125: R120.2@13.93,61.35 14.2,61.35 v1(14.45,61.6)
USER_LED2: R119.2 U1.K24 | length 187.3
  Top Layer w0.125: v1(92.875,43.875) U1.K24@93.5,44.5
  Layer 5 w0.125: v1(13.75,57.55) 11.05,60.25 8.7,60.25 6.25,62.7 4.15,62.7 3.7,62.25 3.7,46.35 1.85,44.5 1.85,28.864 3.964,26.75 13.664,26.75 15.15,25.264 15.15,23.8 16.037,22.913 22.237,22.913 27,18.15 29.725,18.15 30.788,17.087 36.948,17.087 37.236,17.375 44.375,17.375 48.375,13.375 48.375,6.325 49.47,5.23 58.642,5.23 59.288,5.876 59.288,10.234 62.204,13.15 64.921,13.15 66.134,11.937 67.927,11.937 68.289,12.3 73.625,12.3 77.375,16.05 80.383,16.05 81.925,17.592 81.925,19.529 82,19.604 82,19.625 85.025,22.65 88.743,22.65 93.087,26.995 93.087,38.212 93.5,38.625 93.5,43.25 v1(92.875,43.875)
  Bottom Layer w0.125: v1(13.75,57.55) 13.75,58.78 R119.2@14.7,59.73
VCC_LICELL: R8.2 U1.N3 | length 90.8
  Top Layer w0.125: v1(50.6,39.65) 51.067,39.65 51.5,39.217 U1.N3@51.5,38.5
  L6 PWR w0.3: v1(50.6,39.65) 52.45,39.65 53.35,38.75 53.35,36.8 53.85,36.3 56.25,36.3 57.3,35.25 57.3,33.65 57,33.35 56.693,33.35 56.243,33.8 52.793,33.8 52.1,33.107 52.1,29.817 52.48,29.437 52.48,27.487 51.7,26.707 51.7,26.057 52,25.757 52,25.3 52,24.243 52.743,23.5 52.907,23.5 53.2,23.207 53.2,22.793 52.907,22.5 52.543,22.5 50.25,20.207 50.25,18.9 49.8,18.45 49.8,17.143 50.293,16.65 59.425,16.65 59.95,16.125 61.025,16.125 61.4,16.5 71.65,16.5 72.15,16 72.95,16 73.45,16.5 89.9,16.5 91.05,15.35 93.55,15.35 v1(93.75,15.55)
  Bottom Layer w0.3: v1(93.75,15.55) 94.85,15.55 96.05,14.35 R8.2@96.05,9.53
VIN: FIL1.3 Q1.2 Q3.2 R6.1 R11.2 R126.2 U3.4 U3.8 | length 4.6
  Bottom Layer w0.25: Q3.2@90.87,18.75 91.32,18.75 92.27,19.7 93.97,19.7 94.27,19.4 Q1.2@94.27,18.75
VLDO3_MCA: CAD2.1 J11.1 R23.2 R80.1 R150.1 R153.2 U1.AC10 | length 207.2
  Top Layer w0.2: v1(90.4,37.1) 90.5,37.2 93.35,37.2 96.37,40.22 R80.1@96.6,40.22
  Top Layer w0.4: J11.1@13.332,51.36 15.01,51.36 15.2,51.55 v1(15.2,53.7) ; U1.AC10@65.5,18.5 66.3,17.7 v1(66.3,17.4)
  Layer 8 w0.2: v1(79.15,29.6) 81.05,29.6 82.1,28.55 82.1,26.886 81.9,26.686 81.9,25.35 80.95,24.4 80.95,20.55 v1(80.55,20.15)
  L6 PWR w0.2: v1(90.4,37.1) 90.85,37.1
  L6 PWR w0.4: v1(6.95,61.1) 6.95,62.6 7.45,63.1 28.672,63.1 29.472,63.9 38.803,63.9 40.153,62.55 50.75,62.55 51.05,62.85 53.453,62.85 53.953,63.35 87.228,63.35 90.325,60.253 90.325,46.425 90.85,45.9 90.85,37.1 90.85,32.3 91.35,31.8 91.35,21.425 90.075,20.15 82.322,20.15 82.072,20.4 80.803,20.4 80.553,20.15 v1(80.55,20.15) 79.178,20.15 78.978,19.95 78.522,19.95 78.172,20.3 75.522,20.3 75.172,19.95 73.95,19.95 73.35,20.55 67.7,20.55 66.3,19.15 v1(66.3,17.4)
  Bottom Layer w0.15: v1(80.55,20.15) 80.7,20.15 81.05,20.5 81.05,21.3 81.43,21.68 R153.2@81.9,21.68
  Bottom Layer w0.2: R23.2@75.53,31.15 78.25,31.15 79.15,30.25 v1(79.15,29.6)
  Bottom Layer w0.4: v1(6.95,61.1) 6.9,61.05 6.9,60.022 6.95,59.972 6.95,59.45 7.15,59.25 11.662,59.25 12.9,58.012 12.9,56.34 ; CAD2.1@11.935,56.34 12.9,56.34 ; R150.1@15.2,53.08 v1(15.2,53.7) 15.8,53.7 16.25,54.15 16.25,56.35 15.85,56.75 14.75,56.75 14.34,56.34 12.9,56.34
VLDO4_2V5: L3.2 R26.2 R38.2 R40.2 R41.2 R45.2 R53.2 R55.2 R58.2 R60.2 R61.2 R62.2 R63.2 R81.1 R154.1 U1.R5 U1.V3 | length 27
  Top Layer w0.25: R154.1@35.15,40.22 35.77,40.22 v1(35.85,40.3) ; L3.2@36.375,26.395 v1@38,26.395 ; v1(50.5,28.5) U1.V3@51.5,28.5 ; U1.R5@55.5,34.5 v1(56.375,34.5)
  L6 PWR w0.25: v1(35.85,40.3) 35.85,40.078 37.853,38.075 41.275,38.075 41.5,37.85 41.5,35.625 ; 41.25,35.275 41.325,35.35 41.325,35.45 41.5,35.625 ; 41.5,35.275 41.5,35.625 ; 41.725,35.3 41.725,35.4 41.5,35.625
  Bottom Layer w0.125: v1(15.375,8.625) R53.2@16.105,8.625 ; R55.2@17.395,8.625 v1(18.125,8.625)
  Bottom Layer w0.25: R45.2@16.125,10.73 v1(16.125,11.5) ; R38.2@17.375,10.73 v1(17.375,11.5) ; v1(48.85,23.7) 48.88,23.73 R26.2@48.88,24.3 ; R61.2@49.98,20.5 49.98,20.68 v1(50.5,21.2) 51.02,20.68 R63.2@51.02,20.5 51.02,19.83 51.287,19.563 52.5,19.563 53.083,18.98 R62.2@53.5,18.98 ; R60.2@49.98,22.5 49.98,22.63 v1(50.5,23.15) 51.02,22.63 R40.2@51.02,22.5 ; v1(50.5,28.5) R58.2@51.02,28.5 ; v1(51.5,23.5) R41.2@51.5,24.02 ; v1(61.8,15.6) 62.02,15.38 R81.1@62.02,14.9
  other v1: 38,26.375
VLDO6_1V5: C40.2 C41.2 J12.6 J12.28 J12.48 R82.1 R131.2 | length 55.3
  Layer 10 w0.2: v1(56.9,31.8) 58.5,31.8 59.35,30.95 61.837,30.95 62.287,31.4 v1(63.95,31.4)
  Bottom Layer w0.2: v1(63.95,31.4) 64,31.45 67.939,31.45 68.489,30.9 R131.2@68.57,30.9
  Bottom Layer w0.25: 57.6,24.95 60.25,22.3 61.122,22.3 61.402,22.02 R82.1@64.8,22.02
  Bottom Layer w0.4: C40.2@49.4,42.5 49.4,41.55 49.7,41.25 51.96,41.25 ; J12.48@54.4,23.8 56.45,23.8 57.6,24.95 57.6,31.8 ; J12.28@54.4,31.8 57.6,31.8 ; J12.6@54.4,43.8 53.25,43.8 51.96,42.51 C41.2@51.96,42.5 51.96,41.25 ; 51.96,41.25 51.96,40.34 54.75,37.55 56.528,37.55 57.6,36.478 57.6,31.8
VSYS: C1.1 C2.2 C3.2 C11.2 C62.2 C65.1 C111.2 C112.2 C113.2 J18.1 J32.1 R101.1 R137.2 R140.2 R147.2 R148.2 R151.1 R152.1 U1.V11 U1.W11 U1.W12 U5.K U7.3 U12.7 U14.7 U23.3 U23.14 | length 34.5
  Top Layer w0.254: v1(65.5,25.375) 65.602,25.273 66.898,25.273 67.5,25.875 U1.W11@67.5,26.5 ; v1(66.15,25.8) 66.65,26.3 66.65,27.65 U1.V11@67.5,28.5 ; U1.W12@69.5,26.5 70.25,27.25 70.25,29.45 v1(69.85,29.85)
  Bottom Layer w0.25: 73.84,54.3 U23.3@75.35,54.3 U23.14@76.15,54.3
  Bottom Layer w0.254: R147.2@9.28,27.05 9.28,27.83 v1(9.3,27.85) ; v1(15.1,44.5) 15.55,44.05 20.1,44.05 20.35,44.3 23.75,44.3 23.83,44.22 R101.1@23.83,43.6 ; v1(15.2,49.25) R152.1@15.2,49.77 ; R151.1@17.18,35.4 v1(17.7,35.4) ; v1(23.6,19.75) 24.1,20.25 C65.1@24.665,20.25 24.49,20.425 U14.7@24.49,21.8 ; U12.7@42.615,23.425 v1(42.615,22.2) 42.615,21.425 C62.2@42.665,21.375 ; U7.3@43.55,56.09 44.31,56.09 v1(44.4,56) 44.65,56.25 C11.2@44.65,56.64 ; C112.2@72.3,54.22 72.61,53.91 C113.2@73.45,53.91 ; R137.2@73.27,55.4 73.27,54.09 C113.2@73.45,53.91 ; 73.84,54.3 C113.2@73.45,53.91 ; R140.2@82.056,55.65 82.056,55.094 v1(82.15,55)
  other v1: 88.8,25.15 88.55,25.7 88.55,26.3 88.53,26.9 88.53,27.55 88.53,28.15 88.55,28.85 88.55,29.45 72.3,54.95 70.7,55.35 71.25,55.35 71.85,55.35 72.65,55.35 72.25,55.75
XBEE_ASSOC: J24.6 J25.2 R134.1 | length 74.3
  Top Layer w0.125: J24.6@42.825,43 42.825,43.725 v1(42.95,43.85)
  Layer 10 w0.125: J25.2@5.6,8.65 5.25,8.65 4.837,9.063 4.837,10.159 4.85,10.171 4.85,15.854 4.05,16.654 4.05,24.746 8.704,29.4 13.05,29.4 14.187,30.537 14.187,41.437 16.863,44.113 29.587,44.113 31.1,42.6 39.4,42.6 40.8,44 42.8,44 v1(42.95,43.85)
  Bottom Layer w0.125: v1(42.95,43.85) 42.97,43.87 R134.1@44.85,43.87
XBEE_IDENT: J24.1 J25.1 R136.1 U1.G24 | length 191.3
  Top Layer w0.125: v1(26.8,69.75) 28.95,69.75 30.25,68.45 v1(30.25,67.85) ; v1(37.75,49.4) 37.75,50.25 36.95,51.05 36.95,52.8 37.13,52.98 R136.1@37.6,52.98 37.62,53 J24.1@39.975,53 ; U1.G24@93.5,50.5 94.3,51.3 v1(94.3,51.35)
  Layer 8 w0.125: v1(26.8,69.75) 32.55,69.75 34.113,71.313 74.339,71.313 79.701,65.95 88.25,65.95 94.3,59.9 v1(94.3,51.35) ; v1(30.25,67.85) 30.263,67.837 30.263,62.663 29.6,62 29.6,57.55 v1(37.75,49.4)
  Layer 10 w0.125: J25.1@5.6,7.4 5.35,7.4 4.587,8.163 4.587,10.262 4.6,10.275 4.6,15.75 3.8,16.55 3.8,24.85 9,30.05 12.15,30.05 13.75,31.65 13.75,41.6 18.15,46 28.4,46 31.55,42.85 37.7,42.85 38.3,43.45 38.3,48.85 v1(37.75,49.4)
XBEE_ON/SLEEP_N: J24.8 Q5.G U1.AD18 | length 101.4
  Top Layer w0.125: J24.8@42.825,39 44.25,39 44.6,38.65 v1(44.6,36.6) ; v1(80.875,17.125) U1.AD18@81.5,16.5
  Layer 8 w0.125: v1(36.5,51.35) 38.35,49.5 38.35,42.467 40.717,40.1 42.554,40.1 42.754,39.9 43.35,39.9 44.6,38.65 v1(44.6,36.6) ; v1(48.875,6.75) 51.125,9 59.125,9 62.612,12.487 64.666,12.487 67.004,10.15 76.879,10.15 79.079,12.35 v1(80.65,12.35)
  Layer 5 w0.125: v1(44.6,36.6) 44.663,36.537 47.046,36.537 48.237,35.346 48.237,27.388 51,24.625 51,19.274 49.837,18.111 49.837,16.787 49.375,16.325 49.375,9 48.875,8.5 v1(48.875,6.75)
  Bottom Layer w0.125: Q5.G@35.35,51.91 35.91,51.35 v1(36.5,51.35) ; v1(80.65,12.35) 80.875,12.575 v1(80.875,17.125)
XBEE_RESET_N: J23.5 U1.AB17 | length 81.3
  Top Layer w0.125: J23.5@17.975,45 21,45 24,42 v1(24,39.1) ; v1(78.75,20.5) U1.AB17@79.5,20.5
  Layer 5 w0.125: v1(24,39.1) 24.602,39.1 26.1,37.602 26.1,37 27.3,35.8 27.3,33.104 31.018,29.386 37.968,29.386 40.025,27.329 40.025,25.604 41.3,24.329 41.3,20.4 42.25,19.45 45.05,19.45 v1(45.5,19.9)
  Layer 10 w0.125: v1(45.5,19.9) 46.35,19.05 47.35,19.05 47.8,19.5 49.517,19.5 49.579,19.563 53.113,19.563 53.713,20.163 55.121,20.163 55.363,19.921 55.363,19.701 55.851,19.212 57.099,19.212 57.324,18.987 75.571,18.987 76.283,19.7 76.987,19.7 77.787,20.5 v1(78.75,20.5)
XBEE_SLEEP_RQ: J23.9 R146.2 U1.W16 | length 90.4
  Top Layer w0.125: J23.9@17.975,37 v1@20.575,37 ; U1.W16@77.5,26.5 v1(78.25,27.125)
  Layer 5 w0.125: v1(20.625,37) 23.1,34.525 23.1,27 24.825,25.275 27.525,25.275 28.513,24.287 28.513,20.987 31.413,18.087 36.534,18.087 36.821,18.375 45.125,18.375 v1(46.125,17.375)
  Layer 10 w0.125: v1(46.125,17.375) 47.375,16.125 48.925,16.125 51.5,13.55 57.529,13.55 58.929,14.95 58.96,14.95 58.972,14.963 72.705,14.963 74.743,17 v1(74.75,17)
  Layer 3 w0.125: v1(74.75,17) 75.913,18.163 75.913,19.671 75.737,19.846 75.737,25.021 77.842,27.125 v1(78.25,27.125)
  Bottom Layer w0.125: v1(20.625,37) 23.42,37 R146.2@23.55,37.13
XBEE_USB_N: J23.8 R129.2 | length 13.3
  Top Layer w0.137: R129.2@18.45,31.98 17.97,31.98 17.84,32.11 17.84,32.45 17.84,32.966 16.35,34.456 16.35,39.05 17.05,39.75 18.85,39.75 19.35,39.25 20.575,39.25 J23.8@20.825,39
XBEE_USB_P: J23.7 R102.2 | length 13.6
  Top Layer w0.137: R102.2@16.95,31.98 17.38,31.98 17.56,32.16 17.56,32.85 16.07,34.34 16.07,39.166 16.934,40.03 18.83,40.03 19,40.2 19,40.95 19.05,41 J23.7@17.975,41
XBEE_VCC: C101.2 C114.2 J23.1 L28.2 L29.2 R133.1 | length 9
  Bottom Layer w0.25: C101.2@22.8,51.36 22.847,51.313 24.5,51.313 24.702,51.515 29.665,51.515 R133.1@29.8,51.38
  Bottom Layer w0.5: 21.4,52.4 22.44,51.36 C101.2@22.8,51.36
  other v1: 19.6,52.7 20.15,52.7 19.6,53.35 20.15,53.35
pads on no net: CAD1.7 CAD1.MT1 CAD1.MT2 CAD1.MT3 CAD2.6 CAD2.7 CAD2.8 CAD2.9 CAD2.MT1 CAD2.MT2 CAD2.MT3 D3.X FIDUCIAL1.1 FIDUCIAL2.1 FIDUCIAL3.1 FIDUCIAL4.1 FIDUCIAL5.1 FIDUCIAL6.1 FIDUCIAL7.1 FIDUCIAL8.1 FIDUCIAL9.1 FIDUCIAL10.1 FIDUCIAL11.1 FIDUCIAL12.1 FIDUCIAL13.1 FIDUCIAL14.1 H1.1 H2.1 H3.1 H4.1 J1.3 J1.4 J8.8 J8.9 J10.7 J11.6 J11.7 J11.8 J12.3 J12.5 J12.7 J12.17 J12.19 J12.42 J12.44 J12.45 J12.46 J12.47 J12.49 J12.51 J12.H1 J12.H2 J12.MT1 J12.MT2 J13.MNT1 J13.MNT2 J14.4 J14.8 J14.9 J14.10 J16.10 J16.11 J17.M1 J17.M2 J19.MT1 J19.MT21 J21.M1 J21.M2 J22.4 J22.MT1 J22.MT2 J24.2 J24.3 J24.4 J31.MT1 J31.MT21 J33.M1 J33.M2 P1.14 P1.H1 P1.H2 P20.4 U1.A6 U1.A16 U1.A19 U1.A20 U1.AA2 U1.AA18 U1.AA20 U1.AA21 U1.AA22 U1.AA23 U1.AB11 U1.AB12 U1.AB20 U1.AB22 U1.AC11 U1.AC21 U1.AD12 U1.AD13 U1.AD19 U1.B12 U1.B16 U1.B21 U1.C3 U1.C12 U1.C17 U1.C18 U1.C19 U1.C20 U1.C22 U1.D5 U1.D6 U1.D11 U1.D12 U1.D17 U1.D23 U1.E11 U1.E12 U1.E13 U1.E15 U1.E22 U1.E23 U1.F2 U1.F17 U1.F18 U1.F21 U1.F22 U1.G15 U1.H21 U1.J21 U1.J22 U1.J23 U1.K5 U1.L20 U1.L21 U1.M21 U1.N20 U1.N21 U1.N22 U1.N24 U1.P20 U1.P21 U1.P22 U1.P23 U1.R2 U1.R20 U1.R21 U1.T20 U1.T21 U1.T22 U1.T24 U1.U2 U1.U19 U1.U20 U1.U22 U1.V2 U1.V19 U1.V24 U1.W22 U1.W23 U1.Y2 U1.Y10 U1.Y22 U1.Y23 U8.7 U8.8 U8.15 U8.16 U8.20 U8.21 U9.6 U9.7 U9.8 U9.11 U9.15 U9.16 U9.17 U9.20 U9.21 U12.3 U12.5 U13.18 U13.19 U17.8 U17.9 U17.17 U17.19 U17.22 U17.28 U18.5 U19.5 U20.2 U20.6 U21.6

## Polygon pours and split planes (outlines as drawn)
VLDO4_2V5 on L6 PWR "Polysolid_L6" (solid, pour order 111): 28 vertices, not listed, extent 13.625,8 62.15,35.45
VSYS on L6 PWR "Polysolid_L6" (solid, remove dead copper, pour order 97): 60 vertices, not listed, extent 1.73,2.081 89.85,62.45
RGMII_1V2 on L6 PWR "Polysolid_L6" (solid, pour order 121): 21 vertices, not listed, extent 21.25,25 42.875,49
SHLD on L6 PWR "Polysolid_L6" (solid, pour order 57): 45 vertices, not listed, extent 7.125,0.25 83,13.625
PCIE_VCC on L6 PWR "Polysolid_L6" (solid, remove dead copper, pour order 95): 26 vertices, not listed, extent 15.4,16.8 67.845,58.493
5V on L6 PWR "Polysolid_L6" (solid, remove dead copper, pour order 109): 34 vertices, not listed, extent 2.7,1.75 98.65,69.5
NetC46_2 on L6 PWR "Polysolid_L6" (solid, pour order 113): 30 vertices, not listed, extent 25.875,25 40.875,39.25
NetC50_2 on L6 PWR "Polysolid_L6" (solid, pour order 115): 32 vertices, not listed, extent 28.25,25.875 37.5,37.875
NetC42_2 on L6 PWR "Polysolid_L6" (solid, pour order 117): 27.25,29.375 27.25,31.75 25.25,31.75 25.25,33.5 27.25,33.5 27.25,34.75 26.125,34.75 26.125,38.625 27.875,38.625 27.875,33.125 26,33.125 26,32.125 30.125,32.125 30.125,29.375
NetC72_2 on L6 PWR "Polysolid_L6" (solid, pour order 119): 24 vertices, not listed, extent 26.25,27.625 36.625,38.625
VLDO3_MCA on L6 PWR "Polysolid_L6" (solid, remove dead copper, pour order 125): 19 vertices, not listed, extent 5.6,16.9 92.05,64
GND on Top Layer "polysolid" (solid, remove dead copper, pour order 129): 19.6,33.3 19.6,35.35 19.75,35.5 22,35.5 22.1,35.4 22.1,34.55 22,34.45 21.288,34.45 21.038,34.2 21.038,33.388 20.85,33.2 19.7,33.2 19.6,33.3
XBEE_VCC on Top Layer "polysolid" (solid, remove dead copper, pour order 127): 20.45,53.05 20.45,53.6 20.3,53.75 16.8,53.75 16.65,53.6 16.65,52.45 16.8,52.3 20.3,52.3 20.45,52.45
RGMII_1V2 on Top Layer "Polysolid" (solid, remove dead copper, pour order 59): 31.25,39.15 31.25,43 34.142,43 34.384,42.758 34.384,39.984 33.55,39.15 31.25,39.15
SHLD on Top Layer "Polygon" (solid, pour order 61): 45 vertices, not listed, extent 7.221,0.25 83,13.5
GND on Bottom Layer "Polysolid" (solid, remove dead copper, pour order 99): 24 vertices, not listed, extent 72.95,50.8 83.675,60.15
NetL1_1 on Bottom Layer "Polysolid" (solid, remove dead copper, pour order 81): 70.7,56.15 72.65,56.15 72.75,56.25 72.75,58.85 72.65,58.95 70.85,58.95 70.7,58.8
PCIE_VCC on Bottom Layer "Polysolid" (solid, remove dead copper, pour order 79): 22 vertices, not listed, extent 65.55,49.9 70.45,61.7
GND on Bottom Layer "Polysolid" (solid, remove dead copper, pour order 123): 92.3,23.55 92.3,29.75 92.65,30.1 95.6,30.1 96,29.7 96,25.8 94.6,24.4 93.45,24.4 93.2,24.15 93.2,23.45 93.05,23.3 92.3,23.3 92.3,23.55
SHLD on Bottom Layer "Polygon" (solid, pour order 63): 45 vertices, not listed, extent 7.125,0.25 83,13.625
NetR6_2 on Bottom Layer "Polysolid" (solid, remove dead copper, pour order 67): 17 vertices, not listed, extent 85.47,17.9 91.37,21.5
VSYS on Bottom Layer "Polysolid" (solid, remove dead copper, pour order 71): 87.07,21.65 90.42,21.65 92.17,23.4 92.17,29.65 91.72,30.1 88.62,30.1 88.17,29.65 88.17,25.35 89.02,24.5 89.92,24.5 90.12,24.3 90.12,23.25 89.97,23.1 87.32,23.1 87.07,22.85
VSYS on Bottom Layer "Polysolid" (solid, remove dead copper, pour order 73): 19 vertices, not listed, extent 69.95,53.55 76.15,56
GND on Bottom Layer "Polysolid" (solid, remove dead copper, pour order 75): 41 vertices, not listed, extent 68.15,49.85 78.55,61.725
XBEE_VCC on Bottom Layer "Polysolid" (solid, remove dead copper, pour order 83): 18.45,60.95 18.45,56.9 18.3,56.75 17.1,55.55 17.1,53.7 17.1,52.85 17.8,52.15 21.6,52.15 21.85,52.4 21.85,53.75 19.85,55.75 19.85,56.25 19.85,60.9 19.75,61 18.5,61
3V3 on Bottom Layer "Polysolid" (solid, remove dead copper, pour order 85): 17.95,59.5 17.95,61.15 17.833,61.267 15.167,61.267 15.167,59.733 15.4,59.5
GND on Bottom Layer "Polysolid" (solid, remove dead copper, pour order 87): 21.465,55.09 21.465,57.465 21.85,57.85 23.6,57.85 23.6,55.09
GND on Bottom Layer "Polysolid" (solid, remove dead copper, pour order 91): 21 vertices, not listed, extent 42.85,56.6 47,63.55
PCIE_VCC on Bottom Layer "Polysolid" (solid, remove dead copper, pour order 93): 18.05,59.112 15.412,59.112 15.35,59.05 15.35,57.3 15.45,57.2 17.95,57.2 18.05,57.3 18.05,59.112
NetFIL1_1 on Bottom Layer "Polysolid" (solid, remove dead copper, pour order 105): 88.25,10.2 82.3,10.2 81.55,10.95 81.55,16.3 81.8,16.55 84.6,16.55 84.7,16.45 84.7,13.4 84.9,13.2 88.2,13.2 88.55,12.85 88.55,10.5
VIN on Bottom Layer "Polysolid" (solid, remove dead copper, pour order 107): 26 vertices, not listed, extent 83,13.45 91.85,19.35
GND on Layer 8 "Polysolid" (solid, remove dead copper, pour order 103): 20 vertices, not listed, extent 68.7,51.35 81.6,59.263
NetL1_1 on Layer 8 "Polysolid" (solid, remove dead copper, pour order 101): 80.9,55 80.9,54.1 80.25,53.45 76.3,53.45 75.8,52.95 72.25,52.95 71.9,53.3 71.9,58.35 72.15,58.6 74.75,58.6 75.35,58 75.35,56.55 75.85,56.05 80.1,56.05 80.9,55.25
SHLD on L2 GND (split plane): 189 vertices, not listed, extent 7.176,0.301 82.949,15.274
GND on L2 GND (split plane): 208 vertices, not listed, extent 0.301,0.301 99.699,71.699
AGND on L4 GND (split plane): 84 vertices, not listed, extent 65.102,4.502 76.648,28.748
SHLD on L4 GND (split plane): 189 vertices, not listed, extent 7.176,0.301 82.949,15.274
GND on L4 GND (split plane): 208 vertices, not listed, extent 0.301,0.301 99.699,71.699
SHLD on L9 GND (split plane): 189 vertices, not listed, extent 7.176,0.301 82.949,15.274
GND on L9 GND (split plane): 208 vertices, not listed, extent 0.301,0.301 99.699,71.699
SHLD on L11 GND (split plane): 189 vertices, not listed, extent 7.176,0.301 82.949,15.274
GND on L11 GND (split plane): 208 vertices, not listed, extent 0.301,0.301 99.699,71.699
SHLD on L7 3V3 (split plane): 189 vertices, not listed, extent 7.176,0.301 82.949,15.274
3V3 on L7 3V3 (split plane): 212 vertices, not listed, extent 1.482,0.301 98.518,69.493

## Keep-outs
Keep-Out Layer:
  lines w0.2: 0,-0.125 0,72 100,72 100,-0.125 0,-0.125

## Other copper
Top Layer:
  pour cut-out: 65,49.5 65,31.75 82.5,31.75 82.5,49.5
  text "30014752-03_TOP" at 23.175,49.75 h0.63
  text "REV B" at 25.9,48.4 h0.63
  text "CCIMX6" at 25.3,45.75 h0.75
  text "SBC" at 26.6,44.65 h0.75
  text ".Layer_Name" at 41.25,-18.875 h2.54
Layer 8:
  pour cut-out: 82.5,31.75 82.5,49.5 65,49.5 65,31.75
  text ".Layer_Name" at 41.047,-19 h2.54
Layer 5:
  pour cut-out: 82.5,49.5 65,49.5 65,31.75 82.5,31.75
  text ".Layer_Name" at 42.625,-19 h2.54
Layer 10:
  pour cut-out: 65,31.75 82.5,31.75 82.5,49.5 65,49.5
  text ".Layer_Name" at 41.25,-18.875 h2.54
L6 PWR:
  text ".Layer_Name" at 44.125,-19.375 h2.54
Layer 3:
  pour cut-out: 65,49.5 65,31.75 82.5,31.75 82.5,49.5
  text ".Layer_Name" at 42.5,-19 h2.54
Bottom Layer:
  pour cut-out: 82.5,49.5 65,49.5 65,31.75 82.5,31.75
  text "CCIMX6_SBC" at 23.6,31.1 h1
  text "30014752-03_BOT" at 0.75,30.1 h1 r270
  text "REV B" at 16,28.85 h1
  text ".Layer_Name" at 37.526,-19 h2.54
L2 GND (plane layer: these items are gaps in the copper):
  lines w0.6: 7.775,0 7.775,9.225 6.875,10.125 6.875,11.875 8.1,13.1 9.75,13.1 11,11.85 11,7.8 10.9,7.7 10.875,7.725 9,7.725 9.025,7.7 9.025,2 24.575,2 24.575,5.225 24.025,5.225 24.025,9.2 22.85,10.375 22.85,11.7 23.7,12.55 25.25,12.55 25.225,12.575 25.225,14.275 26.525,15.575 28.3,15.575 29.525,14.35 29.525,9.7 29.9,9.325 30.75,9.325 30.775,9.3 30.775,3.125 37.875,3.125 37.9,3.15 37.9,9.15 38.475,9.725 38.475,14.425 39.6,15.55 41.55,15.55 46.5,10.6 46.5,2.5 46.55,2.45 56.625,2.45 56.625,4.35 56.65,4.375 58.875,4.375 58.875,9.475 62.375,9.475 62.375,1.95 66.125,1.95 66.125,3.125 69.525,3.125 69.525,2.1 78.95,2.1 78.95,3.2 78.975,3.225 83.25,3.225 83.25,0
L4 GND (plane layer: these items are gaps in the copper):
  lines w0.5: 64.85,20.7 64.85,23.65 64.93,23.73 66.07,23.73 66.55,23.25 71.6,23.25 71.6,26.5 73.4,26.5 73.4,29 76.65,29 76.65,25.8 74.15,25.8 74.15,16.15 72.825,16.15 72.825,12.575 72.85,12.55 74.75,12.55 74.75,13.8 76.9,13.8 76.9,11.65 69.35,11.65 69.35,4.25 66.05,4.25 66.05,13.25 66.05,17.375 69.6,17.375 69.6,20.7 64.85,20.7
  lines w0.6: 7.775,0 7.775,9.225 6.875,10.125 6.875,11.875 8.1,13.1 9.75,13.1 11,11.85 11,7.8 10.9,7.7 10.875,7.725 9,7.725 9.025,7.7 9.025,2 24.575,2 24.575,5.225 24.025,5.225 24.025,9.2 22.85,10.375 22.85,11.7 23.7,12.55 25.25,12.55 25.225,12.575 25.225,14.275 26.525,15.575 28.3,15.575 29.525,14.35 29.525,9.7 29.9,9.325 30.75,9.325 30.775,9.3 30.775,3.125 37.875,3.125 37.9,3.15 37.9,9.15 38.475,9.725 38.475,14.425 39.6,15.55 41.55,15.55 46.5,10.6 46.5,2.5 46.55,2.45 56.625,2.45 56.625,4.35 56.65,4.375 58.875,4.375 58.875,9.475 62.375,9.475 62.375,1.95 66.125,1.95 66.125,3.125 69.525,3.125 69.525,2.1 78.95,2.1 78.95,3.2 78.975,3.225 83.25,3.225 83.25,0
L7 3V3 (plane layer: these items are gaps in the copper):
  pour cut-out: 26.725,61.75 27.875,61.75 27.875,60.9 26.725,60.9
  lines w0.6: 7.775,0 7.775,9.225 6.875,10.125 6.875,11.875 8.1,13.1 9.75,13.1 11,11.85 11,7.8 10.9,7.7 10.875,7.725 9,7.725 9.025,7.7 9.025,2 24.575,2 24.575,5.225 24.025,5.225 24.025,9.2 22.85,10.375 22.85,11.7 23.7,12.55 25.25,12.55 25.225,12.575 25.225,14.275 26.525,15.575 28.3,15.575 29.525,14.35 29.525,9.7 29.9,9.325 30.75,9.325 30.775,9.3 30.775,3.125 37.875,3.125 37.9,3.15 37.9,9.15 38.475,9.725 38.475,14.425 39.6,15.55 41.55,15.55 46.5,10.6 46.5,2.5 46.55,2.45 56.625,2.45 56.625,4.35 56.65,4.375 58.875,4.375 58.875,9.475 62.375,9.475 62.375,1.95 66.125,1.95 66.125,3.125 69.525,3.125 69.525,2.1 78.95,2.1 78.95,3.2 78.975,3.225 83.25,3.225 83.25,0
  lines w2: 0.502,0.502 0.502,71.498 99.498,71.498 99.498,0.502 ; 1.305,70.495 99.498,70.495
L9 GND (plane layer: these items are gaps in the copper):
  lines w0.6: 7.775,0 7.775,9.225 6.875,10.125 6.875,11.875 8.1,13.1 9.75,13.1 11,11.85 11,7.8 10.9,7.7 10.875,7.725 9,7.725 9.025,7.7 9.025,2 24.575,2 24.575,5.225 24.025,5.225 24.025,9.2 22.85,10.375 22.85,11.7 23.7,12.55 25.25,12.55 25.225,12.575 25.225,14.275 26.525,15.575 28.3,15.575 29.525,14.35 29.525,9.7 29.9,9.325 30.75,9.325 30.775,9.3 30.775,3.125 37.875,3.125 37.9,3.15 37.9,9.15 38.475,9.725 38.475,14.425 39.6,15.55 41.55,15.55 46.5,10.6 46.5,2.5 46.55,2.45 56.625,2.45 56.625,4.35 56.65,4.375 58.875,4.375 58.875,9.475 62.375,9.475 62.375,1.95 66.125,1.95 66.125,3.125 69.525,3.125 69.525,2.1 78.95,2.1 78.95,3.2 78.975,3.225 83.25,3.225 83.25,0
L11 GND (plane layer: these items are gaps in the copper):
  lines w0.6: 7.775,0 7.775,9.225 6.875,10.125 6.875,11.875 8.1,13.1 9.75,13.1 11,11.85 11,7.8 10.9,7.7 10.875,7.725 9,7.725 9.025,7.7 9.025,2 24.575,2 24.575,5.225 24.025,5.225 24.025,9.2 22.85,10.375 22.85,11.7 23.7,12.55 25.25,12.55 25.225,12.575 25.225,14.275 26.525,15.575 28.3,15.575 29.525,14.35 29.525,9.7 29.9,9.325 30.75,9.325 30.775,9.3 30.775,3.125 37.875,3.125 37.9,3.15 37.9,9.15 38.475,9.725 38.475,14.425 39.6,15.55 41.55,15.55 46.5,10.6 46.5,2.5 46.55,2.45 56.625,2.45 56.625,4.35 56.65,4.375 58.875,4.375 58.875,9.475 62.375,9.475 62.375,1.95 66.125,1.95 66.125,3.125 69.525,3.125 69.525,2.1 78.95,2.1 78.95,3.2 78.975,3.225 83.25,3.225 83.25,0

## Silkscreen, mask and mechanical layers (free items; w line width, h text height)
Top Overlay:
  circle w0.6: c92.275,3.15 r0.3
  region: 7.4,50.35 7.4,51.35 6.4,50.85
  region: 22.2,52.55 22.2,53.55 21.2,53.05
  region: 16.7,50.8 16.7,51.8 15.7,51.3
  region: 8,41.5 8,42.5 7,42
  region: 6.3,40.85 6.3,39.85 7.3,40.35
  region: 35.35,64.35 35.35,65.35 34.35,64.85
  region: 50.75,65 51.75,65 51.25,66
  region: 71.4,65.65 72.4,65.65 71.9,66.65
  lines w0.25: 19.295,36.3 19.295,27.663 23.85,27.663 ; 19.3,37.675 19.3,40.325 ; 19.3,41.675 19.3,44.325 ; 19.3,45.675 19.3,48.325 ; 19.3,49.675 19.3,52.325 ; 19.824,54.427 19.295,54 ; 20.28,54.794 27.485,60.603 35.602,60.603 40.072,56.947 ; 26.35,27.663 28.025,27.663 ; 30.325,27.663 30.925,27.663 ; 32.075,27.663 34.05,27.663 ; 35.2,27.663 35.625,27.663 ; 36.9,27.663 43.675,27.663 43.675,34.325 ; 42.657,54.833 43.675,54 43.675,51.675 ; 43.675,35.675 43.675,38.325 ; 43.675,39.675 43.675,42.325 ; 43.675,43.675 43.675,46.325 ; 43.675,47.675 43.675,50.325 ; 19.295,54 19.295,53.65 19.295,54
  lines w0.254: 91.075,1.475 91.875,1.475 ; 91.275,3.124 cw(c92.275,3.15) 93.275,3.175 ; 91.475,1.075 91.475,1.875 ; 91.675,4.875 91.675,5.675 ; 92.275,1.075 92.275,2.575 ; 92.275,4.15 92.275,5.65
  text "UART" at 3.55,65.5 h1.2
  text "MIPI CSI" at 54.85,64.65 h2
  text "SATA" at 89.8,64.55 h1.5
  text "CSI0" at 41.8,62.9 h2
  text "LVDS0" at 33.1,62.7 h2
  text "BOOT" at 16.2,59.8 h2
  text "PWR" at 3.9,59.6 h0.9 r90
  text "CAN" at 96.825,58.525 h2 r90
  text "LE0" at 7.8,58.5 h1.5
  text "LE1" at 10.4,58.5 h1.5
  text "LE2" at 13,58.5 h1.5
  text "SWD" at 15.7,55.4 h2
  text "CONS" at 7.8,53.6 h1.2 r90
  text "I2C" at 96.825,49.025 h2 r90
  text "MIPI DSI" at 7.325,42.6 h2 r90
  text "JTAG" at 13.2,33.4 h2
  text "ON/OFF" at 8.95,31.95 h1.5
  text "XBEE" at 20.4,30.775 h1.8
  text "MODULE" at 19.925,29.025 h1.8
  text "GPIO" at 5.7,25.2 h1.5
  text "SPI" at 96.75,23.9 h2 r90
  text "RESET" at 13.6,23.6 h1.5
  text "GbE" at 14,19.3 h2
  text "5V" at 96.85,16.55 h2 r90
  text "for i.MX6 SBC" at 45.025,14.35 h1.8 r90
  text "USB" at 8.15,14.05 h1.5 r90
  text "CONNECT CORE" at 43.7,13.825 h1.8 r90
  text "PWR" at 85.45,13.1 h2
  text "AUDIO" at 62.225,13.025 h2
  text "3.3V" at 96.55,11.3 h2 r90
  text "HEADPHONE" at 80.475,10.425 h2 r270
  text "HDMI" at 46.85,10.2 h2 r90
  text "USB" at 43.6,9.55 h2 r90
  text "BATT" at 96.55,6.4 h2 r90
  text "XBEE" at 8,5.9 h1.5 r90
  text "5VDC" at 91.4,5.9 h2
  text ".Layer_Name" at 36.905,-19.012 h2.54
Bottom Overlay:
  region: 40.15,64.45 39.15,64.45 39.65,65.45
  region: 54.9,64.45 53.9,64.45 54.4,65.45
  region: 8.1,64.05 8.1,65.05 9.1,64.55
  text "CSI1" at 48.85,64 h2
  text "LCD" at 64.7,63.15 h2
  text "LVDS1" at 33.45,58.15 h2
  text "Mini" at 54.3,37.9 h2
  text "PCIe" at 54.225,36.4 h2
  text "MICRO SIM" at 98.05,31 h1.5
  text "MICRO SD" at 82.65,16.6 h1.8 r90
  text "USB OTG" at 44.85,3.275 h2
  text ".Layer_Name" at 36.742,-18.873 h2.54
Top Paste:
  text ".Layer_Name" at 39.548,-18.889 h2.54
Bottom Paste:
  text ".Layer_Name" at 37.409,-19.018 h2.54
Top Solder:
  text ".Layer_Name" at 38.026,-18.881 h2.54
Bottom Solder:
  text ".Layer_Name" at 37.014,-19.018 h2.54
Panel Outline:
  lines w0.25: 192.5,74.5 215,74.5 cw(c215,73.25) 215,72 205,72 205,62 cw(c203.75,62) 202.5,62 202.5,72 192.54,72 cw(c192.54,73.25) 192.54,74.5 ; 287.5,72 222.5,72 cw(c222.5,73.25) 222.5,74.5 287.5,74.5 ; 287.58,72 ccw(c287.58,73.25) 287.58,74.5 ; 295,72 305,72 305,62 ccw(c306.25,62) 307.5,62 307.5,72 ccw(c305,72) 305,74.5 295,74.5 ; 295.08,72 cw(c295.08,73.25) 295.08,74.5 ; 60.975,0 cw(c60.975,-1.25) 62.225,-1.25 ; 60.975,0 cw(c60.975,-1.25) 62.225,-1.25 ; 60.975,0 0,0 0,10 ccw(c-1.25,10) -2.5,10 -2.5,-2.75 ccw(c-1.25,-2.75) -1.25,-4 60.975,-4 ccw(c60.975,-2.75) 62.225,-2.75 62.225,-1.25 ; 66.225,-1.25 cw(c67.475,-1.25) 67.475,0 ; 66.225,-1.25 cw(c67.475,-1.25) 67.475,0 ; 66.225,-1.25 66.225,-2.75 ccw(c67.475,-2.75) 67.475,-4 93,-4 163.475,-4 ccw(c163.475,-2.75) 164.725,-2.75 164.725,-1.25 ccw(c163.475,-1.25) 163.475,0 102.5,0 102.5,10 ccw(c101.25,10) 100,10 100,0 67.475,0 ; -15,-11.5 320,-11.5 320,79.5 -15,79.5 -15,-11.5 ; -2.5,17.5 ccw(c-1.25,17.5) 0,17.5 0,54.5 ccw(c-1.25,54.5) -2.5,54.5 -2.5,17.5 ; -2.5,62 ccw(c-1.25,62) 0,62 0,72 10,72 ccw(c10,73.25) 10,74.5 0,74.5 ccw(c0,72) -2.5,72 -2.5,62 ; 17.5,72 cw(c17.5,73.25) 17.5,74.5 82.5,74.5 cw(c82.5,73.25) 82.5,72 17.5,72 ; 65.5,32.25 82,32.25 82,49 65.5,49 65.5,32.25 ; 90,72 cw(c90,73.25) 90,74.5 112.54,74.5 cw(c112.54,73.25) 112.54,72 102.5,72 102.5,62 cw(c101.25,62) 100,62 100,72 90,72 ; 100,16.25 ccw(c101.25,16.25) 102.5,16.25 102.5,54.5 ccw(c101.25,54.5) 100,54.5 100,16.25 ; 120,72 cw(c120,73.25) 120,74.5 185,74.5 cw(c185,73.25) 185,72 120,72 ; 168.725,-2.75 ccw(c169.975,-2.75) 169.975,-4 266.05,-4 ccw(c266.05,-2.75) 267.3,-2.75 267.3,-1.25 ccw(c266.05,-1.25) 266.05,0 205,0 205,10 ccw(c203.75,10) 202.5,10 202.5,0 169.975,0 ccw(c169.975,-1.25) 168.725,-1.25 168.725,-2.75 ; 202.5,16.25 ccw(c203.75,16.25) 205,16.25 205,54.5 ccw(c203.75,54.5) 202.5,54.5 202.5,16.25 ; 271.3,-2.75 ccw(c272.55,-2.75) 272.55,-4 306.25,-4 ccw(c306.25,-2.75) 307.5,-2.75 307.5,10 ccw(c306.25,10) 305,10 305,0 272.55,0 ccw(c272.55,-1.25) 271.3,-1.25 271.3,-2.75 ; 305,16.25 ccw(c306.25,16.25) 307.5,16.25 307.5,54.5 ccw(c306.25,54.5) 305,54.5 305,16.25
Top Assembly:
  text ".Layer_Name" at 35.875,-18.875 h0.5
Bottom Assembly:
  text ".Layer_Name" at 70.324,-19.016 h2.54
Board Outline:
  the board outline again, w0.25
PCB Name:
  text "CCIMX6_SBC_0.3" at 36.25,-24.125 h2.54
Sheet Graphics:
  lines w0.127: -76.86,-127.35 -69.24,-127.35 ; -76.86,-0.35 -69.24,-0.35 ; -76.86,126.65 -69.24,126.65 ; 24.74,-254.35 24.74,-246.73 ; 24.74,246.03 24.74,253.65 ; 126.34,-254.35 126.34,-246.73 ; 126.34,246.03 126.34,253.65 ; 227.94,-254.35 227.94,-246.73 ; 227.94,246.03 227.94,253.65 ; 329.54,-254.35 329.54,-246.73 ; 329.54,246.03 329.54,253.65 ; 431.14,-254.35 431.14,-246.73 ; 431.14,246.03 431.14,253.65 ; 532.74,-254.35 532.74,-246.73 ; 532.74,246.03 532.74,253.65 ; 614.02,-239.11 728.32,-239.11 ; 614.02,-231.49 728.32,-231.49 ; 614.02,-223.87 652.12,-223.87 ; 634.34,-254.35 634.34,-246.73 ; 634.34,246.03 634.34,253.65 ; 652.12,-246.73 652.12,-231.49 652.12,-216.25 ; 705.46,-246.73 705.46,-231.49 ; 728.32,-127.35 735.94,-127.35 ; 728.32,-0.35 735.94,-0.35 ; 728.32,126.65 735.94,126.65 ; 614.02,-246.73 614.02,-216.25 ; 614.02,-246.73 728.32,-246.73 ; 614.02,-246.73 578.46,-246.73 578.46,-216.25 614.02,-216.25 ; 614.02,-216.25 652.12,-216.25 ; 652.12,-216.25 728.32,-216.25 728.32,-246.73 ; 728.32,-246.73 728.32,246.03 -69.24,246.03 -69.24,-246.73 728.32,-246.73 ; -76.86,-254.35 -76.86,253.65 735.94,253.65 735.94,-254.35 -76.86,-254.35
  lines w0.345: 12.5,138.399 53.938,138.399 ; 12.5,146.687 53.938,146.687 ; 12.5,154.974 53.938,154.974 ; 12.5,163.262 53.938,163.262 ; 12.5,171.549 53.938,171.549 ; 12.5,179.837 53.938,179.837 ; 12.5,188.125 53.938,188.125 ; 12.5,196.412 53.938,196.412 ; 12.5,204.7 53.938,204.7 ; 12.5,212.987 53.938,212.987 ; 12.5,221.275 53.938,221.275 ; 12.5,229.563 53.938,229.563 ; 12.5,141.162 12.5,143.924 53.938,143.924 53.938,141.162 12.5,141.162 ; 12.5,149.449 12.5,152.212 53.938,152.212 53.938,149.449 12.5,149.449 ; 12.5,157.737 12.5,160.499 53.938,160.499 53.938,157.737 12.5,157.737 ; 12.5,166.024 12.5,168.787 53.938,168.787 53.938,166.024 12.5,166.024 ; 12.5,174.312 12.5,177.075 53.938,177.075 53.938,174.312 12.5,174.312 ; 12.5,182.6 12.5,185.362 53.938,185.362 53.938,182.6 12.5,182.6 ; 12.5,190.887 12.5,193.65 53.938,193.65 53.938,190.887 12.5,190.887 ; 12.5,199.175 12.5,201.937 53.938,201.937 53.938,199.175 12.5,199.175 ; 12.5,207.462 12.5,210.225 53.938,210.225 53.938,207.462 12.5,207.462 ; 12.5,215.75 12.5,218.513 53.938,218.513 53.938,215.75 12.5,215.75 ; 12.5,224.038 12.5,226.8 53.938,226.8 53.938,224.038 12.5,224.038
  text "1" at -26.517,248.824 h1.78
  text "2" at 74.956,248.824 h1.78
  text "3" at 176.429,248.824 h1.78
  text "4" at 278.054,248.824 h1.78
  text "5" at 379.612,248.824 h1.78
  text "6" at 481.17,248.824 h1.78
  text "7" at 582.812,248.824 h1.78
  text "8" at 684.285,248.824 h1.78
  text "NOTES:" at 349.935,228.685 h5.08
  text "L1 -TOP SIDE IMPEDANCE CONTROLLED SIGNAL .051 Cu FINISHED" at 56.701,228.181 h2.07
  text "2116H = .130mm" at -17.35,224.3 h2.07
  text "L2 - GND .0127 Cu" at 56.701,219.894 h2.07
  text "1. Manufacture in accordance with IPC-A-600, class 2 & IPC-6012," at 349.935,219.16 h5.08
  text "Core = .100mm" at -16.65,215.85 h2.07
  text "L3 - IMPEDANCE CONTROLLED SIGNAL .0127 Cu" at 56.701,211.606 h2.07
  text "class 2 the latest standards." at 365.175,209 h5.08
  text "2-1080 = .131mm" at -22.55,207.7 h2.07
  text "L4 - GND .0127 Cu" at 56.701,203.319 h2.07
  text "Core = .100mm" at -16.65,199.95 h2.07
  text "2. Manufacturing process and materials used must comply with ROHS directive" at 349.935,198.84 h5.08
  text "L5- SIGNAL .0127 Cu" at 56.701,195.031 h2.07
  text "2-1080 = .131mm" at -19.25,190.75 h2.07
  text "2002/95/EC." at 365.175,188.68 h5.08
  text "A" at -73.685,187.915 h1.78
  text "A" at 731.495,187.915 h1.78
  text "L6 - SPLIT POWER .0127 Cu" at 56.701,186.743 h2.07
  text "Core = .100mm" at -18.2,182.8 h2.07
  text "3. Material: S1000-2" at 349.935,178.52 h5.08
  text "L7 - 3V PWR .0127 Cu" at 56.701,178.456 h2.07
  text "2-1080 = .131mm" at -18.75,174.15 h2.07
  text "L8 - IMPEDANCE CONTROLLED SIGNAL .0127 Cu" at 56.701,170.168 h2.07
  text "Laminate and prepreg shall be per IPC-4101/126." at 365.175,168.36 h5.08
  text "Core = .100mm" at -17.2,165.9 h2.07
  text "L9 - GND .0127 Cu" at 56.701,161.881 h2.07
  text "4. The original Gerber data must be increased to account for manufacturing" at 349.935,158.2 h5.08
  text "2-1080 = .131mm" at -20,157.75 h2.07
  text "L10 - IMPEDANCE CONTROLLED SIGNAL .0127 Cu" at 56.701,153.593 h2.07
  text "Core = .100mm" at -18.05,149.3 h2.07
  text "etch tolerances.  Nominal track width +/-10% is expected." at 365.175,148.04 h5.08
  text "L11 - GND .0127 Cu" at 56.701,145.305 h2.07
  text "2116H = .130mm" at -18.4,141.35 h2.07
  text "5. Apply E.N.I.G. to all exposed copper per IPC-4552." at 349.935,137.88 h5.08
  text "BOTTOM SIDE - IMPEDANCE CONTROLLED SIGNAL .051 Cu FINISHED" at 56.701,137.018 h2.07
  text "6. Starting copper weight is 1/2 oz. for all layers." at 349.935,127.72 h5.08
  text "7. Prepreg height and dielectric constant are critical items." at 349.935,117.56 h5.08
  text "8. Silkscreen: Apply silkscreen artwork to the top and bottom sides of the" at 349.935,107.4 h5.08
  text "board using non-conductive epoxy ink. Silkscreen color: YELLOW" at 365.175,97.24 h5.08
  text "9. Solder mask: Liquid photo imageable solder mask over bare copper (SMOBC)" at 349.935,87.08 h5.08
  text "Color: GREEN" at 365.175,76.92 h5.08
  text "CUT OUT" at 45.695,72.644 h1.25
  text "CUT OUT" at 1.27,72.593 h1.25
  text "CUT OUT" at 153.492,72.593 h1.25
  text "CUT OUT" at 254.356,72.593 h1.25
  text "10. Gerber file format: 274-X with 4/3 accuracy (XXXX.XXX). Gerber files are" at 349.935,66.76 h5.08
  text "CUT OUT" at 101.981,63.754 h1.25 r90
  text "CUT OUT" at 204.394,63.703 h1.25 r90
  text "CUT OUT" at 306.908,63.043 h1.25 r90
  text "B" at -73.685,60.915 h1.78
  text "B" at 731.495,60.915 h1.78
  text "in mm, NC Drill files in mils with 2/4 accuracy." at 365.175,56.6 h5.08
  text "11. Maximum warp and twist not to exceed .254mm per linear 25.4mm." at 349.935,46.44 h5.08
  text "CUT OUT" at 68.732,39.522 h1.5
  text "12. Vendor UL flame code 94V-0 to be clearly marked on the silkscreen layer" at 349.935,36.28 h5.08
  text "CUT OUT" at 204.445,31.521 h1.25 r90
  text "CUT OUT" at -0.66,30.734 h1.25 r90
  text "CUT OUT" at 306.934,28.245 h1.25 r90
  text "CUT OUT" at 101.981,27.584 h1.25 r90
  text "only." at 369.25,26.625 h5.08
  text "13. Panelization: 3x1 array, step 102.5mm." at 350.185,15.995 h5.08
  text "14. All boards to be 100% electrically tested." at 350.185,5.835 h5.08
  text "CUT OUT" at 25.248,-2.616 h1.5
  text "CUT OUT" at 107.823,-2.718 h1.5
  text "CUT OUT" at 213.639,-2.896 h1.5
  text "CUT OUT" at 286.233,-2.896 h1.5
  text "15. Unused inner layer pads may be removed." at 350.185,-4.325 h5.08
  text "16. Copper thieving is NOT allowed on the PCB." at 350.685,-15.27 h5.08
  text "17. All drilled holes are specified as finished hole size." at 350.685,-25.43 h5.08
  text "18. Via holes .010 and smaller may be plated shut - All other plated holes" at 350.685,-35.59 h5.08
  text "have a +/- 0.003 inch tolerance." at 365.925,-45.75 h5.08
  text "Non-plated =/- 0.0015 unless otherwise specified." at 365.925,-55.91 h5.08
  text "19. Finished board thickness 0.062 =/-0.006 inch tolerance" at 350.685,-66.07 h5.08
  text "C" at -73.685,-66.085 h1.78
  text "C" at 731.495,-66.085 h1.78
  text "20. Slot/Cutout tolerance +/- 0.005." at 350.625,-77.75 h5.08
  text "21. IMPEDANCE CONTROLLED LINES ARE ON L1, L3, L5, L8, L10, & L12" at 350.125,-87.75 h5.08
  text "100 OHM DIFFERENTIAL PAIR EXTERNAL = .104mm LINE/.151mm SPACE" at 365.625,-95.925 h5.08
  text "100 OHM DIFFERENTIAL PAIR INTERNAL = .093mm LINE/.207mm SPACE" at 365.625,-104.925 h5.08
  text "22. IMPEDANCE CONTROLLED LINES ARE ON L1, L3, L5, L8, L10, & L12" at 350.125,-114.275 h5.08
  text "50 OHM SINGLE ENDED EXTERNAL = .200mm LINE" at 364.25,-123.2 h5.08
  text "50 OHM SINGLE ENDED INTERNAL = .103mm LINE" at 364.25,-132.7 h5.08
  text "23. IMPEDANCE CONTROLLED LINES ARE ON L1, L3, L10, & L12." at 347.35,-143.025 h5.08
  text "90 OHM DIFFERENTIAL PAIR EXTERNAL = .137mm LINE/.143mm SPACE" at 365.05,-153.175 h5.08
  text "90 OHM DIFFERENTIAL PAIR INTERNAL = .103mm LINE/.128mm SPACE" at 365.05,-162.175 h5.08
  text "24. IMPEDANCE CONTROLLED LINES ARE ON L1, L8, & L12." at 349,-171.75 h5.08
  text "85 OHM DIFFERENTIAL PAIR EXTERNAL = .157mm LINE/.143mm SPACE" at 365.6,-180 h5.08
  text "85 OHM DIFFERENTIAL PAIR INTERNAL = .119mm LINE/.125mm SPACE" at 365.6,-189.5 h5.08
  text "D" at -73.685,-193.085 h1.78
  text "D" at 731.495,-193.085 h1.78
  text "25. Class 2 annular ring is acceptable on .2mm vias with .45mm pad." at 347.65,-198.175 h5.08
  text "26. Vendor to generate netlist from Gerber data." at 348.2,-209.25 h5.08
  text "ENGINEER:" at 615.29,-218.79 h1.14
  text "TITLE:" at 653.39,-218.79 h1.14
  text "Digi" at 683.5,-221.25 h3.17
  text "Daniel Alesanco" at 616.56,-222.346 h1.78
  text "PCB DESIGNER:" at 615.29,-226.283 h1.14
  text "i.MX6x SBC" at 674.375,-228 h3.17
  text "Mark Larson" at 616.56,-229.458 h1.78
  text "DATE:" at 615.29,-234.03 h1.14
  text "PART NO.:" at 653.39,-234.03 h1.14
  text "REV:" at 706.73,-234.03 h1.14
  text "30014752-03" at 672.25,-236.25 h1.78
  text "B" at 718.5,-236.25 h1.78
  text ".Print_Date" at 616.56,-237.078 h1.78
  text "FILE NAME:" at 615.29,-241.65 h1.14
  text "SVN HEAD REV:" at 653.39,-241.65 h1.14
  text "SCALE:" at 706.73,-241.65 h1.14
  text "110 N 5th St.  Suite 400" at 580.365,-242.285 h1.78
  text ".VersionControl_RevNumber" at 668.376,-243.682 h1.78
  text ".PCB_FILE_NAME_NO_PATH" at 616.56,-244.698 h1.78
  text "Minneapolis MN 55403" at 580.365,-245.46 h1.78
  text "1" at -26.517,-251.429 h1.78
  text "2" at 74.956,-251.429 h1.78
  text "3" at 176.429,-251.429 h1.78
  text "4" at 278.054,-251.429 h1.78
  text "5" at 379.612,-251.429 h1.78
  text "6" at 481.17,-251.429 h1.78
  text "7" at 582.812,-251.429 h1.78
  text "8" at 684.285,-251.429 h1.78
Drill Drawing:
  drawing of 181 lines, arcs and shapes, not listed
  text ".Layer_Name" at 35.736,-19.262 h2.54
  text "Symbol" at 63.58,-43.925 h1.8
  text "Count" at 75.746,-43.925 h1.8
  text "Hole Size" at 91.442,-43.925 h1.8
  text "Hole Length" at 119.884,-43.925 h1.8
  text "Rout Path Length" at 148.325,-43.925 h1.8
  text "Plated" at 178.186,-43.925 h1.8
  text "Hole Type" at 190.353,-43.925 h1.8
  text "1473" at 75.746,-47.675 h1.5
  text "0.200mm (7.87mil)" at 91.442,-47.675 h1.5
  text "-" at 119.884,-47.675 h1.5
  text "-" at 148.325,-47.675 h1.5
  text "PTH" at 178.186,-47.675 h1.5
  text "Round" at 190.353,-47.675 h1.5
  text "77" at 75.746,-51.425 h1.5
  text "0.500mm (19.69mil)" at 91.442,-51.425 h1.5
  text "-" at 119.884,-51.425 h1.5
  text "-" at 148.325,-51.425 h1.5
  text "PTH" at 178.186,-51.425 h1.5
  text "Round" at 190.353,-51.425 h1.5
  text "2" at 75.746,-55.175 h1.5
  text "0.813mm (32.00mil)" at 91.442,-55.175 h1.5
  text "-" at 119.884,-55.175 h1.5
  text "-" at 148.325,-55.175 h1.5
  text "NPTH" at 178.186,-55.175 h1.5
  text "Round" at 190.353,-55.175 h1.5
  text "7" at 75.746,-58.925 h1.5
  text "0.813mm (32.00mil)" at 91.442,-58.925 h1.5
  text "-" at 119.884,-58.925 h1.5
  text "-" at 148.325,-58.925 h1.5
  text "PTH" at 178.186,-58.925 h1.5
  text "Round" at 190.353,-58.925 h1.5
  text "18" at 75.746,-62.675 h1.5
  text "0.889mm (35.00mil)" at 91.442,-62.675 h1.5
  text "-" at 119.884,-62.675 h1.5
  text "-" at 148.325,-62.675 h1.5
  text "PTH" at 178.186,-62.675 h1.5
  text "Round" at 190.353,-62.675 h1.5
  text "6" at 75.746,-66.425 h1.5
  text "0.991mm (39.00mil)" at 91.442,-66.425 h1.5
  text "-" at 119.884,-66.425 h1.5
  text "-" at 148.325,-66.425 h1.5
  text "NPTH" at 178.186,-66.425 h1.5
  text "Round" at 190.353,-66.425 h1.5
  text "4" at 75.746,-70.175 h1.5
  text "1.016mm (40.00mil)" at 91.442,-70.175 h1.5
  text "-" at 119.884,-70.175 h1.5
  text "-" at 148.325,-70.175 h1.5
  text "PTH" at 178.186,-70.175 h1.5
  text "Round" at 190.353,-70.175 h1.5
  text "1" at 75.746,-73.925 h1.5
  text "1.100mm (43.31mil)" at 91.442,-73.925 h1.5
  text "-" at 119.884,-73.925 h1.5
  text "-" at 148.325,-73.925 h1.5
  text "NPTH" at 178.186,-73.925 h1.5
  text "Round" at 190.353,-73.925 h1.5
  text "2" at 75.746,-77.675 h1.5
  text "1.143mm (45.00mil)" at 91.442,-77.675 h1.5
  text "-" at 119.884,-77.675 h1.5
  text "-" at 148.325,-77.675 h1.5
  text "PTH" at 178.186,-77.675 h1.5
  text "Round" at 190.353,-77.675 h1.5
  text "2" at 75.746,-81.425 h1.5
  text "1.270mm (50.00mil)" at 91.442,-81.425 h1.5
  text "-" at 119.884,-81.425 h1.5
  text "-" at 148.325,-81.425 h1.5
  text "NPTH" at 178.186,-81.425 h1.5
  text "Round" at 190.353,-81.425 h1.5
  text "2" at 75.746,-85.175 h1.5
  text "1.397mm (55.00mil)" at 91.442,-85.175 h1.5
  text "-" at 119.884,-85.175 h1.5
  text "-" at 148.325,-85.175 h1.5
  text "PTH" at 178.186,-85.175 h1.5
  text "Round" at 190.353,-85.175 h1.5
  text "3" at 75.746,-88.925 h1.5
  text "1.600mm (62.99mil)" at 91.442,-88.925 h1.5
  text "-" at 119.884,-88.925 h1.5
  text "-" at 148.325,-88.925 h1.5
  text "NPTH" at 178.186,-88.925 h1.5
  text "Round" at 190.353,-88.925 h1.5
  text "2" at 75.746,-92.675 h1.5
  text "1.600mm (63.00mil)" at 91.442,-92.675 h1.5
  text "-" at 119.884,-92.675 h1.5
  text "-" at 148.325,-92.675 h1.5
  text "PTH" at 178.186,-92.675 h1.5
  text "Round" at 190.353,-92.675 h1.5
  text "1" at 75.746,-96.425 h1.5
  text "2.362mm (93.00mil)" at 91.442,-96.425 h1.5
  text "-" at 119.884,-96.425 h1.5
  text "-" at 148.325,-96.425 h1.5
  text "NPTH" at 178.186,-96.425 h1.5
  text "Round" at 190.353,-96.425 h1.5
  text "4" at 75.746,-100.175 h1.5
  text "2.362mm (93.00mil)" at 91.442,-100.175 h1.5
  text "-" at 119.884,-100.175 h1.5
  text "-" at 148.325,-100.175 h1.5
  text "PTH" at 178.186,-100.175 h1.5
  text "Round" at 190.353,-100.175 h1.5
  text "A" at 62.955,-100.275 h1.67
  text "4" at 75.746,-103.925 h1.5
  text "2.600mm (102.36mil)" at 91.442,-103.925 h1.5
  text "-" at 119.884,-103.925 h1.5
  text "-" at 148.325,-103.925 h1.5
  text "PTH" at 178.186,-103.925 h1.5
  text "Round" at 190.353,-103.925 h1.5
  text "B" at 62.955,-104.025 h1.67
  text "6" at 75.746,-107.675 h1.5
  text "3.175mm (125.00mil)" at 91.442,-107.675 h1.5
  text "-" at 119.884,-107.675 h1.5
  text "-" at 148.325,-107.675 h1.5
  text "NPTH" at 178.186,-107.675 h1.5
  text "Round" at 190.353,-107.675 h1.5
  text "C" at 62.955,-107.775 h1.67
  text "4" at 75.746,-111.425 h1.5
  text "3.200mm (125.98mil)" at 91.442,-111.425 h1.5
  text "-" at 119.884,-111.425 h1.5
  text "-" at 148.325,-111.425 h1.5
  text "PTH" at 178.186,-111.425 h1.5
  text "Round" at 190.353,-111.425 h1.5
  text "D" at 62.955,-111.525 h1.67
  text "3" at 75.746,-115.175 h1.5
  text "1.016mm (40.00mil)" at 91.442,-115.175 h1.5
  text "3.200mm (126.00mil)" at 119.884,-115.175 h1.5
  text "2.184mm (86.00mil)" at 148.325,-115.175 h1.5
  text "PTH" at 178.186,-115.175 h1.5
  text "Slot" at 190.353,-115.175 h1.5
  text "E" at 62.955,-115.275 h1.67
  text "1621 Total" at 75.746,-118.925 h1.5
  text "Slot definitions :" at 63.58,-122.249 h1.5
  text "Rout Path Length" at 88.977,-122.249 h1.5
  text "= Calculated from tool start centre position to tool end centre position." at 113.124,-122.249 h1.5
  text "Hole Length" at 88.977,-124.449 h1.5
  text "= Rout Path Length + Tool Size = Slot length as defined in the PCB layout" at 105.877,-124.449 h1.5

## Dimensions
0,72 to 100,72 on Sheet Graphics
0,72 to 102.5,72 on Sheet Graphics
202.5,72 to 205,72 on Sheet Graphics
0,72 to 0,0 on Sheet Graphics
-15,79.5 to 0,72 on Sheet Graphics
-15,79.5 to 320,79.5 on Sheet Graphics
-15,79.5 to -15,-11.5 on Sheet Graphics
-15,-11.5 to 0,0 on Sheet Graphics
305,0 to 306.25,-4 on Sheet Graphics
